VERSION 5.8 ;
BUSBITCHARS "[]" ;
DIVIDERCHAR "/" ;
UNITS
    DATABASE MICRONS 1000 ;
END UNITS

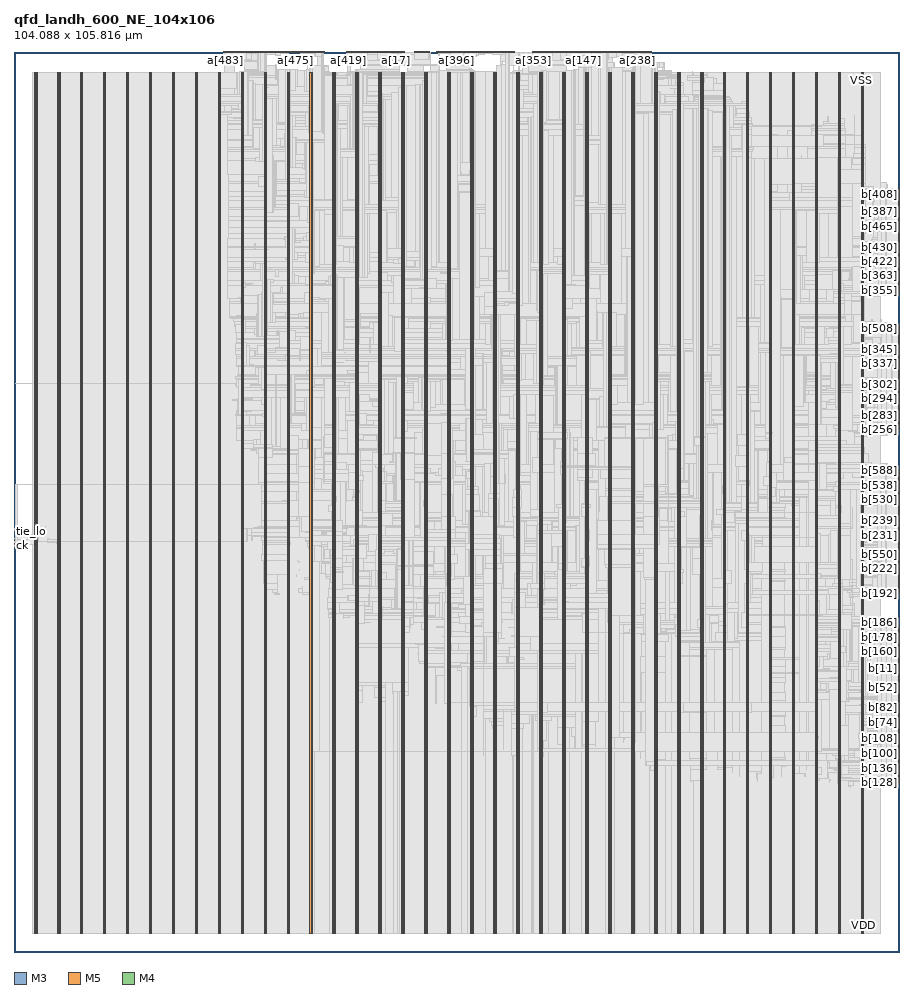
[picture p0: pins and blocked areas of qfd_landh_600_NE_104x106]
MACRO qfd_landh_600_NE_104x106
  FOREIGN qfd_landh_600_NE_104x106 0 0 ;
  CLASS BLOCK ;
  SIZE 104.088 BY 105.816 ;
  PIN a[0]
    DIRECTION INPUT ;
    USE SIGNAL ;
    PORT
      LAYER M3 ;
        RECT  43.668 105.779 43.686 105.816 ;
    END
  END a[0]
  PIN a[100]
    DIRECTION INPUT ;
    USE SIGNAL ;
    PORT
      LAYER M5 ;
        RECT  50.064 105.732 50.088 105.816 ;
    END
  END a[100]
  PIN a[101]
    DIRECTION INPUT ;
    USE SIGNAL ;
    PORT
      LAYER M5 ;
        RECT  50.16 105.732 50.184 105.816 ;
    END
  END a[101]
  PIN a[102]
    DIRECTION INPUT ;
    USE SIGNAL ;
    PORT
      LAYER M5 ;
        RECT  50.256 105.732 50.28 105.816 ;
    END
  END a[102]
  PIN a[103]
    DIRECTION INPUT ;
    USE SIGNAL ;
    PORT
      LAYER M5 ;
        RECT  50.352 105.732 50.376 105.816 ;
    END
  END a[103]
  PIN a[104]
    DIRECTION INPUT ;
    USE SIGNAL ;
    PORT
      LAYER M5 ;
        RECT  50.448 105.732 50.472 105.816 ;
    END
  END a[104]
  PIN a[105]
    DIRECTION INPUT ;
    USE SIGNAL ;
    PORT
      LAYER M5 ;
        RECT  50.544 105.732 50.568 105.816 ;
    END
  END a[105]
  PIN a[106]
    DIRECTION INPUT ;
    USE SIGNAL ;
    PORT
      LAYER M5 ;
        RECT  50.64 105.732 50.664 105.816 ;
    END
  END a[106]
  PIN a[107]
    DIRECTION INPUT ;
    USE SIGNAL ;
    PORT
      LAYER M5 ;
        RECT  50.736 105.732 50.76 105.816 ;
    END
  END a[107]
  PIN a[108]
    DIRECTION INPUT ;
    USE SIGNAL ;
    PORT
      LAYER M5 ;
        RECT  50.832 105.732 50.856 105.816 ;
    END
  END a[108]
  PIN a[109]
    DIRECTION INPUT ;
    USE SIGNAL ;
    PORT
      LAYER M5 ;
        RECT  50.928 105.732 50.952 105.816 ;
    END
  END a[109]
  PIN a[10]
    DIRECTION INPUT ;
    USE SIGNAL ;
    PORT
      LAYER M3 ;
        RECT  44.388 105.779 44.406 105.816 ;
    END
  END a[10]
  PIN a[110]
    DIRECTION INPUT ;
    USE SIGNAL ;
    PORT
      LAYER M5 ;
        RECT  51.024 105.732 51.048 105.816 ;
    END
  END a[110]
  PIN a[111]
    DIRECTION INPUT ;
    USE SIGNAL ;
    PORT
      LAYER M5 ;
        RECT  51.12 105.732 51.144 105.816 ;
    END
  END a[111]
  PIN a[112]
    DIRECTION INPUT ;
    USE SIGNAL ;
    PORT
      LAYER M5 ;
        RECT  51.216 105.732 51.24 105.816 ;
    END
  END a[112]
  PIN a[113]
    DIRECTION INPUT ;
    USE SIGNAL ;
    PORT
      LAYER M5 ;
        RECT  51.312 105.732 51.336 105.816 ;
    END
  END a[113]
  PIN a[114]
    DIRECTION INPUT ;
    USE SIGNAL ;
    PORT
      LAYER M5 ;
        RECT  51.408 105.732 51.432 105.816 ;
    END
  END a[114]
  PIN a[115]
    DIRECTION INPUT ;
    USE SIGNAL ;
    PORT
      LAYER M5 ;
        RECT  51.504 105.732 51.528 105.816 ;
    END
  END a[115]
  PIN a[116]
    DIRECTION INPUT ;
    USE SIGNAL ;
    PORT
      LAYER M5 ;
        RECT  51.6 105.732 51.624 105.816 ;
    END
  END a[116]
  PIN a[117]
    DIRECTION INPUT ;
    USE SIGNAL ;
    PORT
      LAYER M5 ;
        RECT  51.696 105.732 51.72 105.816 ;
    END
  END a[117]
  PIN a[118]
    DIRECTION INPUT ;
    USE SIGNAL ;
    PORT
      LAYER M5 ;
        RECT  51.792 105.732 51.816 105.816 ;
    END
  END a[118]
  PIN a[119]
    DIRECTION INPUT ;
    USE SIGNAL ;
    PORT
      LAYER M5 ;
        RECT  51.888 105.732 51.912 105.816 ;
    END
  END a[119]
  PIN a[11]
    DIRECTION INPUT ;
    USE SIGNAL ;
    PORT
      LAYER M3 ;
        RECT  44.46 105.779 44.478 105.816 ;
    END
  END a[11]
  PIN a[120]
    DIRECTION INPUT ;
    USE SIGNAL ;
    PORT
      LAYER M5 ;
        RECT  51.984 105.732 52.008 105.816 ;
    END
  END a[120]
  PIN a[121]
    DIRECTION INPUT ;
    USE SIGNAL ;
    PORT
      LAYER M5 ;
        RECT  52.08 105.732 52.104 105.816 ;
    END
  END a[121]
  PIN a[122]
    DIRECTION INPUT ;
    USE SIGNAL ;
    PORT
      LAYER M5 ;
        RECT  52.176 105.732 52.2 105.816 ;
    END
  END a[122]
  PIN a[123]
    DIRECTION INPUT ;
    USE SIGNAL ;
    PORT
      LAYER M5 ;
        RECT  52.272 105.732 52.296 105.816 ;
    END
  END a[123]
  PIN a[124]
    DIRECTION INPUT ;
    USE SIGNAL ;
    PORT
      LAYER M5 ;
        RECT  52.368 105.732 52.392 105.816 ;
    END
  END a[124]
  PIN a[125]
    DIRECTION INPUT ;
    USE SIGNAL ;
    PORT
      LAYER M5 ;
        RECT  52.464 105.732 52.488 105.816 ;
    END
  END a[125]
  PIN a[126]
    DIRECTION INPUT ;
    USE SIGNAL ;
    PORT
      LAYER M5 ;
        RECT  52.56 105.732 52.584 105.816 ;
    END
  END a[126]
  PIN a[127]
    DIRECTION INPUT ;
    USE SIGNAL ;
    PORT
      LAYER M5 ;
        RECT  52.656 105.732 52.68 105.816 ;
    END
  END a[127]
  PIN a[128]
    DIRECTION INPUT ;
    USE SIGNAL ;
    PORT
      LAYER M3 ;
        RECT  65.556 105.779 65.574 105.816 ;
    END
  END a[128]
  PIN a[129]
    DIRECTION INPUT ;
    USE SIGNAL ;
    PORT
      LAYER M3 ;
        RECT  65.628 105.779 65.646 105.816 ;
    END
  END a[129]
  PIN a[12]
    DIRECTION INPUT ;
    USE SIGNAL ;
    PORT
      LAYER M3 ;
        RECT  44.532 105.779 44.55 105.816 ;
    END
  END a[12]
  PIN a[130]
    DIRECTION INPUT ;
    USE SIGNAL ;
    PORT
      LAYER M3 ;
        RECT  65.7 105.779 65.718 105.816 ;
    END
  END a[130]
  PIN a[131]
    DIRECTION INPUT ;
    USE SIGNAL ;
    PORT
      LAYER M3 ;
        RECT  65.772 105.779 65.79 105.816 ;
    END
  END a[131]
  PIN a[132]
    DIRECTION INPUT ;
    USE SIGNAL ;
    PORT
      LAYER M3 ;
        RECT  65.844 105.779 65.862 105.816 ;
    END
  END a[132]
  PIN a[133]
    DIRECTION INPUT ;
    USE SIGNAL ;
    PORT
      LAYER M3 ;
        RECT  65.916 105.779 65.934 105.816 ;
    END
  END a[133]
  PIN a[134]
    DIRECTION INPUT ;
    USE SIGNAL ;
    PORT
      LAYER M3 ;
        RECT  65.988 105.779 66.006 105.816 ;
    END
  END a[134]
  PIN a[135]
    DIRECTION INPUT ;
    USE SIGNAL ;
    PORT
      LAYER M3 ;
        RECT  66.06 105.779 66.078 105.816 ;
    END
  END a[135]
  PIN a[136]
    DIRECTION INPUT ;
    USE SIGNAL ;
    PORT
      LAYER M3 ;
        RECT  66.132 105.779 66.15 105.816 ;
    END
  END a[136]
  PIN a[137]
    DIRECTION INPUT ;
    USE SIGNAL ;
    PORT
      LAYER M3 ;
        RECT  66.204 105.779 66.222 105.816 ;
    END
  END a[137]
  PIN a[138]
    DIRECTION INPUT ;
    USE SIGNAL ;
    PORT
      LAYER M3 ;
        RECT  66.276 105.779 66.294 105.816 ;
    END
  END a[138]
  PIN a[139]
    DIRECTION INPUT ;
    USE SIGNAL ;
    PORT
      LAYER M3 ;
        RECT  66.348 105.779 66.366 105.816 ;
    END
  END a[139]
  PIN a[13]
    DIRECTION INPUT ;
    USE SIGNAL ;
    PORT
      LAYER M3 ;
        RECT  44.604 105.779 44.622 105.816 ;
    END
  END a[13]
  PIN a[140]
    DIRECTION INPUT ;
    USE SIGNAL ;
    PORT
      LAYER M3 ;
        RECT  66.42 105.779 66.438 105.816 ;
    END
  END a[140]
  PIN a[141]
    DIRECTION INPUT ;
    USE SIGNAL ;
    PORT
      LAYER M3 ;
        RECT  66.492 105.779 66.51 105.816 ;
    END
  END a[141]
  PIN a[142]
    DIRECTION INPUT ;
    USE SIGNAL ;
    PORT
      LAYER M3 ;
        RECT  66.564 105.779 66.582 105.816 ;
    END
  END a[142]
  PIN a[143]
    DIRECTION INPUT ;
    USE SIGNAL ;
    PORT
      LAYER M3 ;
        RECT  66.636 105.779 66.654 105.816 ;
    END
  END a[143]
  PIN a[144]
    DIRECTION INPUT ;
    USE SIGNAL ;
    PORT
      LAYER M3 ;
        RECT  66.708 105.779 66.726 105.816 ;
    END
  END a[144]
  PIN a[145]
    DIRECTION INPUT ;
    USE SIGNAL ;
    PORT
      LAYER M3 ;
        RECT  66.78 105.779 66.798 105.816 ;
    END
  END a[145]
  PIN a[146]
    DIRECTION INPUT ;
    USE SIGNAL ;
    PORT
      LAYER M3 ;
        RECT  66.852 105.779 66.87 105.816 ;
    END
  END a[146]
  PIN a[147]
    DIRECTION INPUT ;
    USE SIGNAL ;
    PORT
      LAYER M3 ;
        RECT  66.924 105.779 66.942 105.816 ;
    END
  END a[147]
  PIN a[148]
    DIRECTION INPUT ;
    USE SIGNAL ;
    PORT
      LAYER M3 ;
        RECT  66.996 105.779 67.014 105.816 ;
    END
  END a[148]
  PIN a[149]
    DIRECTION INPUT ;
    USE SIGNAL ;
    PORT
      LAYER M3 ;
        RECT  67.068 105.779 67.086 105.816 ;
    END
  END a[149]
  PIN a[14]
    DIRECTION INPUT ;
    USE SIGNAL ;
    PORT
      LAYER M3 ;
        RECT  44.676 105.779 44.694 105.816 ;
    END
  END a[14]
  PIN a[150]
    DIRECTION INPUT ;
    USE SIGNAL ;
    PORT
      LAYER M3 ;
        RECT  67.14 105.779 67.158 105.816 ;
    END
  END a[150]
  PIN a[151]
    DIRECTION INPUT ;
    USE SIGNAL ;
    PORT
      LAYER M3 ;
        RECT  67.212 105.779 67.23 105.816 ;
    END
  END a[151]
  PIN a[152]
    DIRECTION INPUT ;
    USE SIGNAL ;
    PORT
      LAYER M3 ;
        RECT  67.284 105.779 67.302 105.816 ;
    END
  END a[152]
  PIN a[153]
    DIRECTION INPUT ;
    USE SIGNAL ;
    PORT
      LAYER M3 ;
        RECT  67.356 105.779 67.374 105.816 ;
    END
  END a[153]
  PIN a[154]
    DIRECTION INPUT ;
    USE SIGNAL ;
    PORT
      LAYER M3 ;
        RECT  67.428 105.779 67.446 105.816 ;
    END
  END a[154]
  PIN a[155]
    DIRECTION INPUT ;
    USE SIGNAL ;
    PORT
      LAYER M3 ;
        RECT  67.5 105.779 67.518 105.816 ;
    END
  END a[155]
  PIN a[156]
    DIRECTION INPUT ;
    USE SIGNAL ;
    PORT
      LAYER M3 ;
        RECT  67.572 105.779 67.59 105.816 ;
    END
  END a[156]
  PIN a[157]
    DIRECTION INPUT ;
    USE SIGNAL ;
    PORT
      LAYER M3 ;
        RECT  67.644 105.779 67.662 105.816 ;
    END
  END a[157]
  PIN a[158]
    DIRECTION INPUT ;
    USE SIGNAL ;
    PORT
      LAYER M3 ;
        RECT  67.716 105.779 67.734 105.816 ;
    END
  END a[158]
  PIN a[159]
    DIRECTION INPUT ;
    USE SIGNAL ;
    PORT
      LAYER M3 ;
        RECT  67.788 105.779 67.806 105.816 ;
    END
  END a[159]
  PIN a[15]
    DIRECTION INPUT ;
    USE SIGNAL ;
    PORT
      LAYER M3 ;
        RECT  44.748 105.779 44.766 105.816 ;
    END
  END a[15]
  PIN a[160]
    DIRECTION INPUT ;
    USE SIGNAL ;
    PORT
      LAYER M3 ;
        RECT  67.86 105.779 67.878 105.816 ;
    END
  END a[160]
  PIN a[161]
    DIRECTION INPUT ;
    USE SIGNAL ;
    PORT
      LAYER M3 ;
        RECT  67.932 105.779 67.95 105.816 ;
    END
  END a[161]
  PIN a[162]
    DIRECTION INPUT ;
    USE SIGNAL ;
    PORT
      LAYER M3 ;
        RECT  68.004 105.779 68.022 105.816 ;
    END
  END a[162]
  PIN a[163]
    DIRECTION INPUT ;
    USE SIGNAL ;
    PORT
      LAYER M3 ;
        RECT  68.076 105.779 68.094 105.816 ;
    END
  END a[163]
  PIN a[164]
    DIRECTION INPUT ;
    USE SIGNAL ;
    PORT
      LAYER M3 ;
        RECT  68.148 105.779 68.166 105.816 ;
    END
  END a[164]
  PIN a[165]
    DIRECTION INPUT ;
    USE SIGNAL ;
    PORT
      LAYER M3 ;
        RECT  68.22 105.779 68.238 105.816 ;
    END
  END a[165]
  PIN a[166]
    DIRECTION INPUT ;
    USE SIGNAL ;
    PORT
      LAYER M3 ;
        RECT  68.292 105.779 68.31 105.816 ;
    END
  END a[166]
  PIN a[167]
    DIRECTION INPUT ;
    USE SIGNAL ;
    PORT
      LAYER M3 ;
        RECT  68.364 105.779 68.382 105.816 ;
    END
  END a[167]
  PIN a[168]
    DIRECTION INPUT ;
    USE SIGNAL ;
    PORT
      LAYER M3 ;
        RECT  68.436 105.779 68.454 105.816 ;
    END
  END a[168]
  PIN a[169]
    DIRECTION INPUT ;
    USE SIGNAL ;
    PORT
      LAYER M3 ;
        RECT  68.508 105.779 68.526 105.816 ;
    END
  END a[169]
  PIN a[16]
    DIRECTION INPUT ;
    USE SIGNAL ;
    PORT
      LAYER M3 ;
        RECT  44.82 105.779 44.838 105.816 ;
    END
  END a[16]
  PIN a[170]
    DIRECTION INPUT ;
    USE SIGNAL ;
    PORT
      LAYER M3 ;
        RECT  68.58 105.779 68.598 105.816 ;
    END
  END a[170]
  PIN a[171]
    DIRECTION INPUT ;
    USE SIGNAL ;
    PORT
      LAYER M3 ;
        RECT  68.652 105.779 68.67 105.816 ;
    END
  END a[171]
  PIN a[172]
    DIRECTION INPUT ;
    USE SIGNAL ;
    PORT
      LAYER M3 ;
        RECT  68.724 105.779 68.742 105.816 ;
    END
  END a[172]
  PIN a[173]
    DIRECTION INPUT ;
    USE SIGNAL ;
    PORT
      LAYER M3 ;
        RECT  68.796 105.779 68.814 105.816 ;
    END
  END a[173]
  PIN a[174]
    DIRECTION INPUT ;
    USE SIGNAL ;
    PORT
      LAYER M3 ;
        RECT  68.868 105.779 68.886 105.816 ;
    END
  END a[174]
  PIN a[175]
    DIRECTION INPUT ;
    USE SIGNAL ;
    PORT
      LAYER M3 ;
        RECT  68.94 105.779 68.958 105.816 ;
    END
  END a[175]
  PIN a[176]
    DIRECTION INPUT ;
    USE SIGNAL ;
    PORT
      LAYER M3 ;
        RECT  69.012 105.779 69.03 105.816 ;
    END
  END a[176]
  PIN a[177]
    DIRECTION INPUT ;
    USE SIGNAL ;
    PORT
      LAYER M3 ;
        RECT  69.084 105.779 69.102 105.816 ;
    END
  END a[177]
  PIN a[178]
    DIRECTION INPUT ;
    USE SIGNAL ;
    PORT
      LAYER M3 ;
        RECT  69.156 105.779 69.174 105.816 ;
    END
  END a[178]
  PIN a[179]
    DIRECTION INPUT ;
    USE SIGNAL ;
    PORT
      LAYER M3 ;
        RECT  69.228 105.779 69.246 105.816 ;
    END
  END a[179]
  PIN a[17]
    DIRECTION INPUT ;
    USE SIGNAL ;
    PORT
      LAYER M3 ;
        RECT  44.892 105.779 44.91 105.816 ;
    END
  END a[17]
  PIN a[180]
    DIRECTION INPUT ;
    USE SIGNAL ;
    PORT
      LAYER M3 ;
        RECT  69.3 105.779 69.318 105.816 ;
    END
  END a[180]
  PIN a[181]
    DIRECTION INPUT ;
    USE SIGNAL ;
    PORT
      LAYER M3 ;
        RECT  69.372 105.779 69.39 105.816 ;
    END
  END a[181]
  PIN a[182]
    DIRECTION INPUT ;
    USE SIGNAL ;
    PORT
      LAYER M3 ;
        RECT  69.444 105.779 69.462 105.816 ;
    END
  END a[182]
  PIN a[183]
    DIRECTION INPUT ;
    USE SIGNAL ;
    PORT
      LAYER M3 ;
        RECT  69.516 105.779 69.534 105.816 ;
    END
  END a[183]
  PIN a[184]
    DIRECTION INPUT ;
    USE SIGNAL ;
    PORT
      LAYER M3 ;
        RECT  69.588 105.779 69.606 105.816 ;
    END
  END a[184]
  PIN a[185]
    DIRECTION INPUT ;
    USE SIGNAL ;
    PORT
      LAYER M3 ;
        RECT  69.66 105.779 69.678 105.816 ;
    END
  END a[185]
  PIN a[186]
    DIRECTION INPUT ;
    USE SIGNAL ;
    PORT
      LAYER M3 ;
        RECT  69.732 105.779 69.75 105.816 ;
    END
  END a[186]
  PIN a[187]
    DIRECTION INPUT ;
    USE SIGNAL ;
    PORT
      LAYER M3 ;
        RECT  69.804 105.779 69.822 105.816 ;
    END
  END a[187]
  PIN a[188]
    DIRECTION INPUT ;
    USE SIGNAL ;
    PORT
      LAYER M3 ;
        RECT  69.876 105.779 69.894 105.816 ;
    END
  END a[188]
  PIN a[189]
    DIRECTION INPUT ;
    USE SIGNAL ;
    PORT
      LAYER M3 ;
        RECT  69.948 105.779 69.966 105.816 ;
    END
  END a[189]
  PIN a[18]
    DIRECTION INPUT ;
    USE SIGNAL ;
    PORT
      LAYER M3 ;
        RECT  44.964 105.779 44.982 105.816 ;
    END
  END a[18]
  PIN a[190]
    DIRECTION INPUT ;
    USE SIGNAL ;
    PORT
      LAYER M3 ;
        RECT  70.02 105.779 70.038 105.816 ;
    END
  END a[190]
  PIN a[191]
    DIRECTION INPUT ;
    USE SIGNAL ;
    PORT
      LAYER M3 ;
        RECT  70.092 105.779 70.11 105.816 ;
    END
  END a[191]
  PIN a[192]
    DIRECTION INPUT ;
    USE SIGNAL ;
    PORT
      LAYER M5 ;
        RECT  55.824 105.732 55.848 105.816 ;
    END
  END a[192]
  PIN a[193]
    DIRECTION INPUT ;
    USE SIGNAL ;
    PORT
      LAYER M5 ;
        RECT  55.92 105.732 55.944 105.816 ;
    END
  END a[193]
  PIN a[194]
    DIRECTION INPUT ;
    USE SIGNAL ;
    PORT
      LAYER M5 ;
        RECT  56.016 105.732 56.04 105.816 ;
    END
  END a[194]
  PIN a[195]
    DIRECTION INPUT ;
    USE SIGNAL ;
    PORT
      LAYER M5 ;
        RECT  56.112 105.732 56.136 105.816 ;
    END
  END a[195]
  PIN a[196]
    DIRECTION INPUT ;
    USE SIGNAL ;
    PORT
      LAYER M5 ;
        RECT  56.208 105.732 56.232 105.816 ;
    END
  END a[196]
  PIN a[197]
    DIRECTION INPUT ;
    USE SIGNAL ;
    PORT
      LAYER M5 ;
        RECT  56.304 105.732 56.328 105.816 ;
    END
  END a[197]
  PIN a[198]
    DIRECTION INPUT ;
    USE SIGNAL ;
    PORT
      LAYER M5 ;
        RECT  56.4 105.732 56.424 105.816 ;
    END
  END a[198]
  PIN a[199]
    DIRECTION INPUT ;
    USE SIGNAL ;
    PORT
      LAYER M5 ;
        RECT  56.496 105.732 56.52 105.816 ;
    END
  END a[199]
  PIN a[19]
    DIRECTION INPUT ;
    USE SIGNAL ;
    PORT
      LAYER M3 ;
        RECT  45.036 105.779 45.054 105.816 ;
    END
  END a[19]
  PIN a[1]
    DIRECTION INPUT ;
    USE SIGNAL ;
    PORT
      LAYER M3 ;
        RECT  43.74 105.779 43.758 105.816 ;
    END
  END a[1]
  PIN a[200]
    DIRECTION INPUT ;
    USE SIGNAL ;
    PORT
      LAYER M5 ;
        RECT  56.592 105.732 56.616 105.816 ;
    END
  END a[200]
  PIN a[201]
    DIRECTION INPUT ;
    USE SIGNAL ;
    PORT
      LAYER M5 ;
        RECT  56.688 105.732 56.712 105.816 ;
    END
  END a[201]
  PIN a[202]
    DIRECTION INPUT ;
    USE SIGNAL ;
    PORT
      LAYER M5 ;
        RECT  56.784 105.732 56.808 105.816 ;
    END
  END a[202]
  PIN a[203]
    DIRECTION INPUT ;
    USE SIGNAL ;
    PORT
      LAYER M5 ;
        RECT  56.88 105.732 56.904 105.816 ;
    END
  END a[203]
  PIN a[204]
    DIRECTION INPUT ;
    USE SIGNAL ;
    PORT
      LAYER M5 ;
        RECT  56.976 105.732 57 105.816 ;
    END
  END a[204]
  PIN a[205]
    DIRECTION INPUT ;
    USE SIGNAL ;
    PORT
      LAYER M5 ;
        RECT  57.072 105.732 57.096 105.816 ;
    END
  END a[205]
  PIN a[206]
    DIRECTION INPUT ;
    USE SIGNAL ;
    PORT
      LAYER M5 ;
        RECT  57.168 105.732 57.192 105.816 ;
    END
  END a[206]
  PIN a[207]
    DIRECTION INPUT ;
    USE SIGNAL ;
    PORT
      LAYER M5 ;
        RECT  57.264 105.732 57.288 105.816 ;
    END
  END a[207]
  PIN a[208]
    DIRECTION INPUT ;
    USE SIGNAL ;
    PORT
      LAYER M5 ;
        RECT  57.36 105.732 57.384 105.816 ;
    END
  END a[208]
  PIN a[209]
    DIRECTION INPUT ;
    USE SIGNAL ;
    PORT
      LAYER M5 ;
        RECT  57.456 105.732 57.48 105.816 ;
    END
  END a[209]
  PIN a[20]
    DIRECTION INPUT ;
    USE SIGNAL ;
    PORT
      LAYER M3 ;
        RECT  45.108 105.779 45.126 105.816 ;
    END
  END a[20]
  PIN a[210]
    DIRECTION INPUT ;
    USE SIGNAL ;
    PORT
      LAYER M5 ;
        RECT  57.552 105.732 57.576 105.816 ;
    END
  END a[210]
  PIN a[211]
    DIRECTION INPUT ;
    USE SIGNAL ;
    PORT
      LAYER M5 ;
        RECT  57.648 105.732 57.672 105.816 ;
    END
  END a[211]
  PIN a[212]
    DIRECTION INPUT ;
    USE SIGNAL ;
    PORT
      LAYER M5 ;
        RECT  57.744 105.732 57.768 105.816 ;
    END
  END a[212]
  PIN a[213]
    DIRECTION INPUT ;
    USE SIGNAL ;
    PORT
      LAYER M5 ;
        RECT  57.84 105.732 57.864 105.816 ;
    END
  END a[213]
  PIN a[214]
    DIRECTION INPUT ;
    USE SIGNAL ;
    PORT
      LAYER M5 ;
        RECT  57.936 105.732 57.96 105.816 ;
    END
  END a[214]
  PIN a[215]
    DIRECTION INPUT ;
    USE SIGNAL ;
    PORT
      LAYER M5 ;
        RECT  58.032 105.732 58.056 105.816 ;
    END
  END a[215]
  PIN a[216]
    DIRECTION INPUT ;
    USE SIGNAL ;
    PORT
      LAYER M5 ;
        RECT  58.128 105.732 58.152 105.816 ;
    END
  END a[216]
  PIN a[217]
    DIRECTION INPUT ;
    USE SIGNAL ;
    PORT
      LAYER M5 ;
        RECT  58.224 105.732 58.248 105.816 ;
    END
  END a[217]
  PIN a[218]
    DIRECTION INPUT ;
    USE SIGNAL ;
    PORT
      LAYER M5 ;
        RECT  58.32 105.732 58.344 105.816 ;
    END
  END a[218]
  PIN a[219]
    DIRECTION INPUT ;
    USE SIGNAL ;
    PORT
      LAYER M5 ;
        RECT  58.416 105.732 58.44 105.816 ;
    END
  END a[219]
  PIN a[21]
    DIRECTION INPUT ;
    USE SIGNAL ;
    PORT
      LAYER M3 ;
        RECT  45.18 105.779 45.198 105.816 ;
    END
  END a[21]
  PIN a[220]
    DIRECTION INPUT ;
    USE SIGNAL ;
    PORT
      LAYER M5 ;
        RECT  58.512 105.732 58.536 105.816 ;
    END
  END a[220]
  PIN a[221]
    DIRECTION INPUT ;
    USE SIGNAL ;
    PORT
      LAYER M5 ;
        RECT  58.608 105.732 58.632 105.816 ;
    END
  END a[221]
  PIN a[222]
    DIRECTION INPUT ;
    USE SIGNAL ;
    PORT
      LAYER M5 ;
        RECT  58.704 105.732 58.728 105.816 ;
    END
  END a[222]
  PIN a[223]
    DIRECTION INPUT ;
    USE SIGNAL ;
    PORT
      LAYER M5 ;
        RECT  58.8 105.732 58.824 105.816 ;
    END
  END a[223]
  PIN a[224]
    DIRECTION INPUT ;
    USE SIGNAL ;
    PORT
      LAYER M5 ;
        RECT  71.952 105.732 71.976 105.816 ;
    END
  END a[224]
  PIN a[225]
    DIRECTION INPUT ;
    USE SIGNAL ;
    PORT
      LAYER M5 ;
        RECT  72.048 105.732 72.072 105.816 ;
    END
  END a[225]
  PIN a[226]
    DIRECTION INPUT ;
    USE SIGNAL ;
    PORT
      LAYER M5 ;
        RECT  72.144 105.732 72.168 105.816 ;
    END
  END a[226]
  PIN a[227]
    DIRECTION INPUT ;
    USE SIGNAL ;
    PORT
      LAYER M5 ;
        RECT  72.24 105.732 72.264 105.816 ;
    END
  END a[227]
  PIN a[228]
    DIRECTION INPUT ;
    USE SIGNAL ;
    PORT
      LAYER M5 ;
        RECT  72.336 105.732 72.36 105.816 ;
    END
  END a[228]
  PIN a[229]
    DIRECTION INPUT ;
    USE SIGNAL ;
    PORT
      LAYER M5 ;
        RECT  72.432 105.732 72.456 105.816 ;
    END
  END a[229]
  PIN a[22]
    DIRECTION INPUT ;
    USE SIGNAL ;
    PORT
      LAYER M3 ;
        RECT  45.252 105.779 45.27 105.816 ;
    END
  END a[22]
  PIN a[230]
    DIRECTION INPUT ;
    USE SIGNAL ;
    PORT
      LAYER M5 ;
        RECT  72.528 105.732 72.552 105.816 ;
    END
  END a[230]
  PIN a[231]
    DIRECTION INPUT ;
    USE SIGNAL ;
    PORT
      LAYER M5 ;
        RECT  72.624 105.732 72.648 105.816 ;
    END
  END a[231]
  PIN a[232]
    DIRECTION INPUT ;
    USE SIGNAL ;
    PORT
      LAYER M5 ;
        RECT  72.72 105.732 72.744 105.816 ;
    END
  END a[232]
  PIN a[233]
    DIRECTION INPUT ;
    USE SIGNAL ;
    PORT
      LAYER M5 ;
        RECT  72.816 105.732 72.84 105.816 ;
    END
  END a[233]
  PIN a[234]
    DIRECTION INPUT ;
    USE SIGNAL ;
    PORT
      LAYER M5 ;
        RECT  72.912 105.732 72.936 105.816 ;
    END
  END a[234]
  PIN a[235]
    DIRECTION INPUT ;
    USE SIGNAL ;
    PORT
      LAYER M5 ;
        RECT  73.008 105.732 73.032 105.816 ;
    END
  END a[235]
  PIN a[236]
    DIRECTION INPUT ;
    USE SIGNAL ;
    PORT
      LAYER M5 ;
        RECT  73.104 105.732 73.128 105.816 ;
    END
  END a[236]
  PIN a[237]
    DIRECTION INPUT ;
    USE SIGNAL ;
    PORT
      LAYER M5 ;
        RECT  73.2 105.732 73.224 105.816 ;
    END
  END a[237]
  PIN a[238]
    DIRECTION INPUT ;
    USE SIGNAL ;
    PORT
      LAYER M5 ;
        RECT  73.296 105.732 73.32 105.816 ;
    END
  END a[238]
  PIN a[239]
    DIRECTION INPUT ;
    USE SIGNAL ;
    PORT
      LAYER M5 ;
        RECT  73.392 105.732 73.416 105.816 ;
    END
  END a[239]
  PIN a[23]
    DIRECTION INPUT ;
    USE SIGNAL ;
    PORT
      LAYER M3 ;
        RECT  45.324 105.779 45.342 105.816 ;
    END
  END a[23]
  PIN a[240]
    DIRECTION INPUT ;
    USE SIGNAL ;
    PORT
      LAYER M5 ;
        RECT  73.488 105.732 73.512 105.816 ;
    END
  END a[240]
  PIN a[241]
    DIRECTION INPUT ;
    USE SIGNAL ;
    PORT
      LAYER M5 ;
        RECT  73.584 105.732 73.608 105.816 ;
    END
  END a[241]
  PIN a[242]
    DIRECTION INPUT ;
    USE SIGNAL ;
    PORT
      LAYER M5 ;
        RECT  73.68 105.732 73.704 105.816 ;
    END
  END a[242]
  PIN a[243]
    DIRECTION INPUT ;
    USE SIGNAL ;
    PORT
      LAYER M5 ;
        RECT  73.776 105.732 73.8 105.816 ;
    END
  END a[243]
  PIN a[244]
    DIRECTION INPUT ;
    USE SIGNAL ;
    PORT
      LAYER M5 ;
        RECT  73.872 105.732 73.896 105.816 ;
    END
  END a[244]
  PIN a[245]
    DIRECTION INPUT ;
    USE SIGNAL ;
    PORT
      LAYER M5 ;
        RECT  73.968 105.732 73.992 105.816 ;
    END
  END a[245]
  PIN a[246]
    DIRECTION INPUT ;
    USE SIGNAL ;
    PORT
      LAYER M5 ;
        RECT  74.064 105.732 74.088 105.816 ;
    END
  END a[246]
  PIN a[247]
    DIRECTION INPUT ;
    USE SIGNAL ;
    PORT
      LAYER M5 ;
        RECT  74.16 105.732 74.184 105.816 ;
    END
  END a[247]
  PIN a[248]
    DIRECTION INPUT ;
    USE SIGNAL ;
    PORT
      LAYER M5 ;
        RECT  74.256 105.732 74.28 105.816 ;
    END
  END a[248]
  PIN a[249]
    DIRECTION INPUT ;
    USE SIGNAL ;
    PORT
      LAYER M5 ;
        RECT  74.352 105.732 74.376 105.816 ;
    END
  END a[249]
  PIN a[24]
    DIRECTION INPUT ;
    USE SIGNAL ;
    PORT
      LAYER M3 ;
        RECT  45.396 105.779 45.414 105.816 ;
    END
  END a[24]
  PIN a[250]
    DIRECTION INPUT ;
    USE SIGNAL ;
    PORT
      LAYER M5 ;
        RECT  74.448 105.732 74.472 105.816 ;
    END
  END a[250]
  PIN a[251]
    DIRECTION INPUT ;
    USE SIGNAL ;
    PORT
      LAYER M5 ;
        RECT  74.544 105.732 74.568 105.816 ;
    END
  END a[251]
  PIN a[252]
    DIRECTION INPUT ;
    USE SIGNAL ;
    PORT
      LAYER M5 ;
        RECT  74.64 105.732 74.664 105.816 ;
    END
  END a[252]
  PIN a[253]
    DIRECTION INPUT ;
    USE SIGNAL ;
    PORT
      LAYER M5 ;
        RECT  74.736 105.732 74.76 105.816 ;
    END
  END a[253]
  PIN a[254]
    DIRECTION INPUT ;
    USE SIGNAL ;
    PORT
      LAYER M5 ;
        RECT  74.832 105.732 74.856 105.816 ;
    END
  END a[254]
  PIN a[255]
    DIRECTION INPUT ;
    USE SIGNAL ;
    PORT
      LAYER M5 ;
        RECT  74.928 105.732 74.952 105.816 ;
    END
  END a[255]
  PIN a[256]
    DIRECTION INPUT ;
    USE SIGNAL ;
    PORT
      LAYER M5 ;
        RECT  68.88 105.732 68.904 105.816 ;
    END
  END a[256]
  PIN a[257]
    DIRECTION INPUT ;
    USE SIGNAL ;
    PORT
      LAYER M5 ;
        RECT  68.976 105.732 69 105.816 ;
    END
  END a[257]
  PIN a[258]
    DIRECTION INPUT ;
    USE SIGNAL ;
    PORT
      LAYER M5 ;
        RECT  69.072 105.732 69.096 105.816 ;
    END
  END a[258]
  PIN a[259]
    DIRECTION INPUT ;
    USE SIGNAL ;
    PORT
      LAYER M5 ;
        RECT  69.168 105.732 69.192 105.816 ;
    END
  END a[259]
  PIN a[25]
    DIRECTION INPUT ;
    USE SIGNAL ;
    PORT
      LAYER M3 ;
        RECT  45.468 105.779 45.486 105.816 ;
    END
  END a[25]
  PIN a[260]
    DIRECTION INPUT ;
    USE SIGNAL ;
    PORT
      LAYER M5 ;
        RECT  69.264 105.732 69.288 105.816 ;
    END
  END a[260]
  PIN a[261]
    DIRECTION INPUT ;
    USE SIGNAL ;
    PORT
      LAYER M5 ;
        RECT  69.36 105.732 69.384 105.816 ;
    END
  END a[261]
  PIN a[262]
    DIRECTION INPUT ;
    USE SIGNAL ;
    PORT
      LAYER M5 ;
        RECT  69.456 105.732 69.48 105.816 ;
    END
  END a[262]
  PIN a[263]
    DIRECTION INPUT ;
    USE SIGNAL ;
    PORT
      LAYER M5 ;
        RECT  69.552 105.732 69.576 105.816 ;
    END
  END a[263]
  PIN a[264]
    DIRECTION INPUT ;
    USE SIGNAL ;
    PORT
      LAYER M5 ;
        RECT  69.648 105.732 69.672 105.816 ;
    END
  END a[264]
  PIN a[265]
    DIRECTION INPUT ;
    USE SIGNAL ;
    PORT
      LAYER M5 ;
        RECT  69.744 105.732 69.768 105.816 ;
    END
  END a[265]
  PIN a[266]
    DIRECTION INPUT ;
    USE SIGNAL ;
    PORT
      LAYER M5 ;
        RECT  69.84 105.732 69.864 105.816 ;
    END
  END a[266]
  PIN a[267]
    DIRECTION INPUT ;
    USE SIGNAL ;
    PORT
      LAYER M5 ;
        RECT  69.936 105.732 69.96 105.816 ;
    END
  END a[267]
  PIN a[268]
    DIRECTION INPUT ;
    USE SIGNAL ;
    PORT
      LAYER M5 ;
        RECT  70.032 105.732 70.056 105.816 ;
    END
  END a[268]
  PIN a[269]
    DIRECTION INPUT ;
    USE SIGNAL ;
    PORT
      LAYER M5 ;
        RECT  70.128 105.732 70.152 105.816 ;
    END
  END a[269]
  PIN a[26]
    DIRECTION INPUT ;
    USE SIGNAL ;
    PORT
      LAYER M3 ;
        RECT  45.54 105.779 45.558 105.816 ;
    END
  END a[26]
  PIN a[270]
    DIRECTION INPUT ;
    USE SIGNAL ;
    PORT
      LAYER M5 ;
        RECT  70.224 105.732 70.248 105.816 ;
    END
  END a[270]
  PIN a[271]
    DIRECTION INPUT ;
    USE SIGNAL ;
    PORT
      LAYER M5 ;
        RECT  70.32 105.732 70.344 105.816 ;
    END
  END a[271]
  PIN a[272]
    DIRECTION INPUT ;
    USE SIGNAL ;
    PORT
      LAYER M5 ;
        RECT  70.416 105.732 70.44 105.816 ;
    END
  END a[272]
  PIN a[273]
    DIRECTION INPUT ;
    USE SIGNAL ;
    PORT
      LAYER M5 ;
        RECT  70.512 105.732 70.536 105.816 ;
    END
  END a[273]
  PIN a[274]
    DIRECTION INPUT ;
    USE SIGNAL ;
    PORT
      LAYER M5 ;
        RECT  70.608 105.732 70.632 105.816 ;
    END
  END a[274]
  PIN a[275]
    DIRECTION INPUT ;
    USE SIGNAL ;
    PORT
      LAYER M5 ;
        RECT  70.704 105.732 70.728 105.816 ;
    END
  END a[275]
  PIN a[276]
    DIRECTION INPUT ;
    USE SIGNAL ;
    PORT
      LAYER M5 ;
        RECT  70.8 105.732 70.824 105.816 ;
    END
  END a[276]
  PIN a[277]
    DIRECTION INPUT ;
    USE SIGNAL ;
    PORT
      LAYER M5 ;
        RECT  70.896 105.732 70.92 105.816 ;
    END
  END a[277]
  PIN a[278]
    DIRECTION INPUT ;
    USE SIGNAL ;
    PORT
      LAYER M5 ;
        RECT  70.992 105.732 71.016 105.816 ;
    END
  END a[278]
  PIN a[279]
    DIRECTION INPUT ;
    USE SIGNAL ;
    PORT
      LAYER M5 ;
        RECT  71.088 105.732 71.112 105.816 ;
    END
  END a[279]
  PIN a[27]
    DIRECTION INPUT ;
    USE SIGNAL ;
    PORT
      LAYER M3 ;
        RECT  45.612 105.779 45.63 105.816 ;
    END
  END a[27]
  PIN a[280]
    DIRECTION INPUT ;
    USE SIGNAL ;
    PORT
      LAYER M5 ;
        RECT  71.184 105.732 71.208 105.816 ;
    END
  END a[280]
  PIN a[281]
    DIRECTION INPUT ;
    USE SIGNAL ;
    PORT
      LAYER M5 ;
        RECT  71.28 105.732 71.304 105.816 ;
    END
  END a[281]
  PIN a[282]
    DIRECTION INPUT ;
    USE SIGNAL ;
    PORT
      LAYER M5 ;
        RECT  71.376 105.732 71.4 105.816 ;
    END
  END a[282]
  PIN a[283]
    DIRECTION INPUT ;
    USE SIGNAL ;
    PORT
      LAYER M5 ;
        RECT  71.472 105.732 71.496 105.816 ;
    END
  END a[283]
  PIN a[284]
    DIRECTION INPUT ;
    USE SIGNAL ;
    PORT
      LAYER M5 ;
        RECT  71.568 105.732 71.592 105.816 ;
    END
  END a[284]
  PIN a[285]
    DIRECTION INPUT ;
    USE SIGNAL ;
    PORT
      LAYER M5 ;
        RECT  71.664 105.732 71.688 105.816 ;
    END
  END a[285]
  PIN a[286]
    DIRECTION INPUT ;
    USE SIGNAL ;
    PORT
      LAYER M5 ;
        RECT  71.76 105.732 71.784 105.816 ;
    END
  END a[286]
  PIN a[287]
    DIRECTION INPUT ;
    USE SIGNAL ;
    PORT
      LAYER M5 ;
        RECT  71.856 105.732 71.88 105.816 ;
    END
  END a[287]
  PIN a[288]
    DIRECTION INPUT ;
    USE SIGNAL ;
    PORT
      LAYER M3 ;
        RECT  63.252 105.779 63.27 105.816 ;
    END
  END a[288]
  PIN a[289]
    DIRECTION INPUT ;
    USE SIGNAL ;
    PORT
      LAYER M3 ;
        RECT  63.324 105.779 63.342 105.816 ;
    END
  END a[289]
  PIN a[28]
    DIRECTION INPUT ;
    USE SIGNAL ;
    PORT
      LAYER M3 ;
        RECT  45.684 105.779 45.702 105.816 ;
    END
  END a[28]
  PIN a[290]
    DIRECTION INPUT ;
    USE SIGNAL ;
    PORT
      LAYER M3 ;
        RECT  63.396 105.779 63.414 105.816 ;
    END
  END a[290]
  PIN a[291]
    DIRECTION INPUT ;
    USE SIGNAL ;
    PORT
      LAYER M3 ;
        RECT  63.468 105.779 63.486 105.816 ;
    END
  END a[291]
  PIN a[292]
    DIRECTION INPUT ;
    USE SIGNAL ;
    PORT
      LAYER M3 ;
        RECT  63.54 105.779 63.558 105.816 ;
    END
  END a[292]
  PIN a[293]
    DIRECTION INPUT ;
    USE SIGNAL ;
    PORT
      LAYER M3 ;
        RECT  63.612 105.779 63.63 105.816 ;
    END
  END a[293]
  PIN a[294]
    DIRECTION INPUT ;
    USE SIGNAL ;
    PORT
      LAYER M3 ;
        RECT  63.684 105.779 63.702 105.816 ;
    END
  END a[294]
  PIN a[295]
    DIRECTION INPUT ;
    USE SIGNAL ;
    PORT
      LAYER M3 ;
        RECT  63.756 105.779 63.774 105.816 ;
    END
  END a[295]
  PIN a[296]
    DIRECTION INPUT ;
    USE SIGNAL ;
    PORT
      LAYER M3 ;
        RECT  63.828 105.779 63.846 105.816 ;
    END
  END a[296]
  PIN a[297]
    DIRECTION INPUT ;
    USE SIGNAL ;
    PORT
      LAYER M3 ;
        RECT  63.9 105.779 63.918 105.816 ;
    END
  END a[297]
  PIN a[298]
    DIRECTION INPUT ;
    USE SIGNAL ;
    PORT
      LAYER M3 ;
        RECT  63.972 105.779 63.99 105.816 ;
    END
  END a[298]
  PIN a[299]
    DIRECTION INPUT ;
    USE SIGNAL ;
    PORT
      LAYER M3 ;
        RECT  64.044 105.779 64.062 105.816 ;
    END
  END a[299]
  PIN a[29]
    DIRECTION INPUT ;
    USE SIGNAL ;
    PORT
      LAYER M3 ;
        RECT  45.756 105.779 45.774 105.816 ;
    END
  END a[29]
  PIN a[2]
    DIRECTION INPUT ;
    USE SIGNAL ;
    PORT
      LAYER M3 ;
        RECT  43.812 105.779 43.83 105.816 ;
    END
  END a[2]
  PIN a[300]
    DIRECTION INPUT ;
    USE SIGNAL ;
    PORT
      LAYER M3 ;
        RECT  64.116 105.779 64.134 105.816 ;
    END
  END a[300]
  PIN a[301]
    DIRECTION INPUT ;
    USE SIGNAL ;
    PORT
      LAYER M3 ;
        RECT  64.188 105.779 64.206 105.816 ;
    END
  END a[301]
  PIN a[302]
    DIRECTION INPUT ;
    USE SIGNAL ;
    PORT
      LAYER M3 ;
        RECT  64.26 105.779 64.278 105.816 ;
    END
  END a[302]
  PIN a[303]
    DIRECTION INPUT ;
    USE SIGNAL ;
    PORT
      LAYER M3 ;
        RECT  64.332 105.779 64.35 105.816 ;
    END
  END a[303]
  PIN a[304]
    DIRECTION INPUT ;
    USE SIGNAL ;
    PORT
      LAYER M3 ;
        RECT  64.404 105.779 64.422 105.816 ;
    END
  END a[304]
  PIN a[305]
    DIRECTION INPUT ;
    USE SIGNAL ;
    PORT
      LAYER M3 ;
        RECT  64.476 105.779 64.494 105.816 ;
    END
  END a[305]
  PIN a[306]
    DIRECTION INPUT ;
    USE SIGNAL ;
    PORT
      LAYER M3 ;
        RECT  64.548 105.779 64.566 105.816 ;
    END
  END a[306]
  PIN a[307]
    DIRECTION INPUT ;
    USE SIGNAL ;
    PORT
      LAYER M3 ;
        RECT  64.62 105.779 64.638 105.816 ;
    END
  END a[307]
  PIN a[308]
    DIRECTION INPUT ;
    USE SIGNAL ;
    PORT
      LAYER M3 ;
        RECT  64.692 105.779 64.71 105.816 ;
    END
  END a[308]
  PIN a[309]
    DIRECTION INPUT ;
    USE SIGNAL ;
    PORT
      LAYER M3 ;
        RECT  64.764 105.779 64.782 105.816 ;
    END
  END a[309]
  PIN a[30]
    DIRECTION INPUT ;
    USE SIGNAL ;
    PORT
      LAYER M3 ;
        RECT  45.828 105.779 45.846 105.816 ;
    END
  END a[30]
  PIN a[310]
    DIRECTION INPUT ;
    USE SIGNAL ;
    PORT
      LAYER M3 ;
        RECT  64.836 105.779 64.854 105.816 ;
    END
  END a[310]
  PIN a[311]
    DIRECTION INPUT ;
    USE SIGNAL ;
    PORT
      LAYER M3 ;
        RECT  64.908 105.779 64.926 105.816 ;
    END
  END a[311]
  PIN a[312]
    DIRECTION INPUT ;
    USE SIGNAL ;
    PORT
      LAYER M3 ;
        RECT  64.98 105.779 64.998 105.816 ;
    END
  END a[312]
  PIN a[313]
    DIRECTION INPUT ;
    USE SIGNAL ;
    PORT
      LAYER M3 ;
        RECT  65.052 105.779 65.07 105.816 ;
    END
  END a[313]
  PIN a[314]
    DIRECTION INPUT ;
    USE SIGNAL ;
    PORT
      LAYER M3 ;
        RECT  65.124 105.779 65.142 105.816 ;
    END
  END a[314]
  PIN a[315]
    DIRECTION INPUT ;
    USE SIGNAL ;
    PORT
      LAYER M3 ;
        RECT  65.196 105.779 65.214 105.816 ;
    END
  END a[315]
  PIN a[316]
    DIRECTION INPUT ;
    USE SIGNAL ;
    PORT
      LAYER M3 ;
        RECT  65.268 105.779 65.286 105.816 ;
    END
  END a[316]
  PIN a[317]
    DIRECTION INPUT ;
    USE SIGNAL ;
    PORT
      LAYER M3 ;
        RECT  65.34 105.779 65.358 105.816 ;
    END
  END a[317]
  PIN a[318]
    DIRECTION INPUT ;
    USE SIGNAL ;
    PORT
      LAYER M3 ;
        RECT  65.412 105.779 65.43 105.816 ;
    END
  END a[318]
  PIN a[319]
    DIRECTION INPUT ;
    USE SIGNAL ;
    PORT
      LAYER M3 ;
        RECT  65.484 105.779 65.502 105.816 ;
    END
  END a[319]
  PIN a[31]
    DIRECTION INPUT ;
    USE SIGNAL ;
    PORT
      LAYER M3 ;
        RECT  45.9 105.779 45.918 105.816 ;
    END
  END a[31]
  PIN a[320]
    DIRECTION INPUT ;
    USE SIGNAL ;
    PORT
      LAYER M5 ;
        RECT  52.752 105.732 52.776 105.816 ;
    END
  END a[320]
  PIN a[321]
    DIRECTION INPUT ;
    USE SIGNAL ;
    PORT
      LAYER M5 ;
        RECT  52.848 105.732 52.872 105.816 ;
    END
  END a[321]
  PIN a[322]
    DIRECTION INPUT ;
    USE SIGNAL ;
    PORT
      LAYER M5 ;
        RECT  52.944 105.732 52.968 105.816 ;
    END
  END a[322]
  PIN a[323]
    DIRECTION INPUT ;
    USE SIGNAL ;
    PORT
      LAYER M5 ;
        RECT  53.04 105.732 53.064 105.816 ;
    END
  END a[323]
  PIN a[324]
    DIRECTION INPUT ;
    USE SIGNAL ;
    PORT
      LAYER M5 ;
        RECT  53.136 105.732 53.16 105.816 ;
    END
  END a[324]
  PIN a[325]
    DIRECTION INPUT ;
    USE SIGNAL ;
    PORT
      LAYER M5 ;
        RECT  53.232 105.732 53.256 105.816 ;
    END
  END a[325]
  PIN a[326]
    DIRECTION INPUT ;
    USE SIGNAL ;
    PORT
      LAYER M5 ;
        RECT  53.328 105.732 53.352 105.816 ;
    END
  END a[326]
  PIN a[327]
    DIRECTION INPUT ;
    USE SIGNAL ;
    PORT
      LAYER M5 ;
        RECT  53.424 105.732 53.448 105.816 ;
    END
  END a[327]
  PIN a[328]
    DIRECTION INPUT ;
    USE SIGNAL ;
    PORT
      LAYER M5 ;
        RECT  53.52 105.732 53.544 105.816 ;
    END
  END a[328]
  PIN a[329]
    DIRECTION INPUT ;
    USE SIGNAL ;
    PORT
      LAYER M5 ;
        RECT  53.616 105.732 53.64 105.816 ;
    END
  END a[329]
  PIN a[32]
    DIRECTION INPUT ;
    USE SIGNAL ;
    PORT
      LAYER M5 ;
        RECT  27.408 105.732 27.432 105.816 ;
    END
  END a[32]
  PIN a[330]
    DIRECTION INPUT ;
    USE SIGNAL ;
    PORT
      LAYER M5 ;
        RECT  53.712 105.732 53.736 105.816 ;
    END
  END a[330]
  PIN a[331]
    DIRECTION INPUT ;
    USE SIGNAL ;
    PORT
      LAYER M5 ;
        RECT  53.808 105.732 53.832 105.816 ;
    END
  END a[331]
  PIN a[332]
    DIRECTION INPUT ;
    USE SIGNAL ;
    PORT
      LAYER M5 ;
        RECT  53.904 105.732 53.928 105.816 ;
    END
  END a[332]
  PIN a[333]
    DIRECTION INPUT ;
    USE SIGNAL ;
    PORT
      LAYER M5 ;
        RECT  54 105.732 54.024 105.816 ;
    END
  END a[333]
  PIN a[334]
    DIRECTION INPUT ;
    USE SIGNAL ;
    PORT
      LAYER M5 ;
        RECT  54.096 105.732 54.12 105.816 ;
    END
  END a[334]
  PIN a[335]
    DIRECTION INPUT ;
    USE SIGNAL ;
    PORT
      LAYER M5 ;
        RECT  54.192 105.732 54.216 105.816 ;
    END
  END a[335]
  PIN a[336]
    DIRECTION INPUT ;
    USE SIGNAL ;
    PORT
      LAYER M5 ;
        RECT  54.288 105.732 54.312 105.816 ;
    END
  END a[336]
  PIN a[337]
    DIRECTION INPUT ;
    USE SIGNAL ;
    PORT
      LAYER M5 ;
        RECT  54.384 105.732 54.408 105.816 ;
    END
  END a[337]
  PIN a[338]
    DIRECTION INPUT ;
    USE SIGNAL ;
    PORT
      LAYER M5 ;
        RECT  54.48 105.732 54.504 105.816 ;
    END
  END a[338]
  PIN a[339]
    DIRECTION INPUT ;
    USE SIGNAL ;
    PORT
      LAYER M5 ;
        RECT  54.576 105.732 54.6 105.816 ;
    END
  END a[339]
  PIN a[33]
    DIRECTION INPUT ;
    USE SIGNAL ;
    PORT
      LAYER M5 ;
        RECT  27.504 105.732 27.528 105.816 ;
    END
  END a[33]
  PIN a[340]
    DIRECTION INPUT ;
    USE SIGNAL ;
    PORT
      LAYER M5 ;
        RECT  54.672 105.732 54.696 105.816 ;
    END
  END a[340]
  PIN a[341]
    DIRECTION INPUT ;
    USE SIGNAL ;
    PORT
      LAYER M5 ;
        RECT  54.768 105.732 54.792 105.816 ;
    END
  END a[341]
  PIN a[342]
    DIRECTION INPUT ;
    USE SIGNAL ;
    PORT
      LAYER M5 ;
        RECT  54.864 105.732 54.888 105.816 ;
    END
  END a[342]
  PIN a[343]
    DIRECTION INPUT ;
    USE SIGNAL ;
    PORT
      LAYER M5 ;
        RECT  54.96 105.732 54.984 105.816 ;
    END
  END a[343]
  PIN a[344]
    DIRECTION INPUT ;
    USE SIGNAL ;
    PORT
      LAYER M5 ;
        RECT  55.056 105.732 55.08 105.816 ;
    END
  END a[344]
  PIN a[345]
    DIRECTION INPUT ;
    USE SIGNAL ;
    PORT
      LAYER M5 ;
        RECT  55.152 105.732 55.176 105.816 ;
    END
  END a[345]
  PIN a[346]
    DIRECTION INPUT ;
    USE SIGNAL ;
    PORT
      LAYER M5 ;
        RECT  55.248 105.732 55.272 105.816 ;
    END
  END a[346]
  PIN a[347]
    DIRECTION INPUT ;
    USE SIGNAL ;
    PORT
      LAYER M5 ;
        RECT  55.344 105.732 55.368 105.816 ;
    END
  END a[347]
  PIN a[348]
    DIRECTION INPUT ;
    USE SIGNAL ;
    PORT
      LAYER M5 ;
        RECT  55.44 105.732 55.464 105.816 ;
    END
  END a[348]
  PIN a[349]
    DIRECTION INPUT ;
    USE SIGNAL ;
    PORT
      LAYER M5 ;
        RECT  55.536 105.732 55.56 105.816 ;
    END
  END a[349]
  PIN a[34]
    DIRECTION INPUT ;
    USE SIGNAL ;
    PORT
      LAYER M5 ;
        RECT  27.6 105.732 27.624 105.816 ;
    END
  END a[34]
  PIN a[350]
    DIRECTION INPUT ;
    USE SIGNAL ;
    PORT
      LAYER M5 ;
        RECT  55.632 105.732 55.656 105.816 ;
    END
  END a[350]
  PIN a[351]
    DIRECTION INPUT ;
    USE SIGNAL ;
    PORT
      LAYER M5 ;
        RECT  55.728 105.732 55.752 105.816 ;
    END
  END a[351]
  PIN a[352]
    DIRECTION INPUT ;
    USE SIGNAL ;
    PORT
      LAYER M3 ;
        RECT  60.948 105.779 60.966 105.816 ;
    END
  END a[352]
  PIN a[353]
    DIRECTION INPUT ;
    USE SIGNAL ;
    PORT
      LAYER M3 ;
        RECT  61.02 105.779 61.038 105.816 ;
    END
  END a[353]
  PIN a[354]
    DIRECTION INPUT ;
    USE SIGNAL ;
    PORT
      LAYER M3 ;
        RECT  61.092 105.779 61.11 105.816 ;
    END
  END a[354]
  PIN a[355]
    DIRECTION INPUT ;
    USE SIGNAL ;
    PORT
      LAYER M3 ;
        RECT  61.164 105.779 61.182 105.816 ;
    END
  END a[355]
  PIN a[356]
    DIRECTION INPUT ;
    USE SIGNAL ;
    PORT
      LAYER M3 ;
        RECT  61.236 105.779 61.254 105.816 ;
    END
  END a[356]
  PIN a[357]
    DIRECTION INPUT ;
    USE SIGNAL ;
    PORT
      LAYER M3 ;
        RECT  61.308 105.779 61.326 105.816 ;
    END
  END a[357]
  PIN a[358]
    DIRECTION INPUT ;
    USE SIGNAL ;
    PORT
      LAYER M3 ;
        RECT  61.38 105.779 61.398 105.816 ;
    END
  END a[358]
  PIN a[359]
    DIRECTION INPUT ;
    USE SIGNAL ;
    PORT
      LAYER M3 ;
        RECT  61.452 105.779 61.47 105.816 ;
    END
  END a[359]
  PIN a[35]
    DIRECTION INPUT ;
    USE SIGNAL ;
    PORT
      LAYER M5 ;
        RECT  27.696 105.732 27.72 105.816 ;
    END
  END a[35]
  PIN a[360]
    DIRECTION INPUT ;
    USE SIGNAL ;
    PORT
      LAYER M3 ;
        RECT  61.524 105.779 61.542 105.816 ;
    END
  END a[360]
  PIN a[361]
    DIRECTION INPUT ;
    USE SIGNAL ;
    PORT
      LAYER M3 ;
        RECT  61.596 105.779 61.614 105.816 ;
    END
  END a[361]
  PIN a[362]
    DIRECTION INPUT ;
    USE SIGNAL ;
    PORT
      LAYER M3 ;
        RECT  61.668 105.779 61.686 105.816 ;
    END
  END a[362]
  PIN a[363]
    DIRECTION INPUT ;
    USE SIGNAL ;
    PORT
      LAYER M3 ;
        RECT  61.74 105.779 61.758 105.816 ;
    END
  END a[363]
  PIN a[364]
    DIRECTION INPUT ;
    USE SIGNAL ;
    PORT
      LAYER M3 ;
        RECT  61.812 105.779 61.83 105.816 ;
    END
  END a[364]
  PIN a[365]
    DIRECTION INPUT ;
    USE SIGNAL ;
    PORT
      LAYER M3 ;
        RECT  61.884 105.779 61.902 105.816 ;
    END
  END a[365]
  PIN a[366]
    DIRECTION INPUT ;
    USE SIGNAL ;
    PORT
      LAYER M3 ;
        RECT  61.956 105.779 61.974 105.816 ;
    END
  END a[366]
  PIN a[367]
    DIRECTION INPUT ;
    USE SIGNAL ;
    PORT
      LAYER M3 ;
        RECT  62.028 105.779 62.046 105.816 ;
    END
  END a[367]
  PIN a[368]
    DIRECTION INPUT ;
    USE SIGNAL ;
    PORT
      LAYER M3 ;
        RECT  62.1 105.779 62.118 105.816 ;
    END
  END a[368]
  PIN a[369]
    DIRECTION INPUT ;
    USE SIGNAL ;
    PORT
      LAYER M3 ;
        RECT  62.172 105.779 62.19 105.816 ;
    END
  END a[369]
  PIN a[36]
    DIRECTION INPUT ;
    USE SIGNAL ;
    PORT
      LAYER M5 ;
        RECT  27.792 105.732 27.816 105.816 ;
    END
  END a[36]
  PIN a[370]
    DIRECTION INPUT ;
    USE SIGNAL ;
    PORT
      LAYER M3 ;
        RECT  62.244 105.779 62.262 105.816 ;
    END
  END a[370]
  PIN a[371]
    DIRECTION INPUT ;
    USE SIGNAL ;
    PORT
      LAYER M3 ;
        RECT  62.316 105.779 62.334 105.816 ;
    END
  END a[371]
  PIN a[372]
    DIRECTION INPUT ;
    USE SIGNAL ;
    PORT
      LAYER M3 ;
        RECT  62.388 105.779 62.406 105.816 ;
    END
  END a[372]
  PIN a[373]
    DIRECTION INPUT ;
    USE SIGNAL ;
    PORT
      LAYER M3 ;
        RECT  62.46 105.779 62.478 105.816 ;
    END
  END a[373]
  PIN a[374]
    DIRECTION INPUT ;
    USE SIGNAL ;
    PORT
      LAYER M3 ;
        RECT  62.532 105.779 62.55 105.816 ;
    END
  END a[374]
  PIN a[375]
    DIRECTION INPUT ;
    USE SIGNAL ;
    PORT
      LAYER M3 ;
        RECT  62.604 105.779 62.622 105.816 ;
    END
  END a[375]
  PIN a[376]
    DIRECTION INPUT ;
    USE SIGNAL ;
    PORT
      LAYER M3 ;
        RECT  62.676 105.779 62.694 105.816 ;
    END
  END a[376]
  PIN a[377]
    DIRECTION INPUT ;
    USE SIGNAL ;
    PORT
      LAYER M3 ;
        RECT  62.748 105.779 62.766 105.816 ;
    END
  END a[377]
  PIN a[378]
    DIRECTION INPUT ;
    USE SIGNAL ;
    PORT
      LAYER M3 ;
        RECT  62.82 105.779 62.838 105.816 ;
    END
  END a[378]
  PIN a[379]
    DIRECTION INPUT ;
    USE SIGNAL ;
    PORT
      LAYER M3 ;
        RECT  62.892 105.779 62.91 105.816 ;
    END
  END a[379]
  PIN a[37]
    DIRECTION INPUT ;
    USE SIGNAL ;
    PORT
      LAYER M5 ;
        RECT  27.888 105.732 27.912 105.816 ;
    END
  END a[37]
  PIN a[380]
    DIRECTION INPUT ;
    USE SIGNAL ;
    PORT
      LAYER M3 ;
        RECT  62.964 105.779 62.982 105.816 ;
    END
  END a[380]
  PIN a[381]
    DIRECTION INPUT ;
    USE SIGNAL ;
    PORT
      LAYER M3 ;
        RECT  63.036 105.779 63.054 105.816 ;
    END
  END a[381]
  PIN a[382]
    DIRECTION INPUT ;
    USE SIGNAL ;
    PORT
      LAYER M3 ;
        RECT  63.108 105.779 63.126 105.816 ;
    END
  END a[382]
  PIN a[383]
    DIRECTION INPUT ;
    USE SIGNAL ;
    PORT
      LAYER M3 ;
        RECT  63.18 105.779 63.198 105.816 ;
    END
  END a[383]
  PIN a[384]
    DIRECTION INPUT ;
    USE SIGNAL ;
    PORT
      LAYER M3 ;
        RECT  51.156 105.779 51.174 105.816 ;
    END
  END a[384]
  PIN a[385]
    DIRECTION INPUT ;
    USE SIGNAL ;
    PORT
      LAYER M3 ;
        RECT  51.228 105.779 51.246 105.816 ;
    END
  END a[385]
  PIN a[386]
    DIRECTION INPUT ;
    USE SIGNAL ;
    PORT
      LAYER M3 ;
        RECT  51.3 105.779 51.318 105.816 ;
    END
  END a[386]
  PIN a[387]
    DIRECTION INPUT ;
    USE SIGNAL ;
    PORT
      LAYER M3 ;
        RECT  51.372 105.779 51.39 105.816 ;
    END
  END a[387]
  PIN a[388]
    DIRECTION INPUT ;
    USE SIGNAL ;
    PORT
      LAYER M3 ;
        RECT  51.444 105.779 51.462 105.816 ;
    END
  END a[388]
  PIN a[389]
    DIRECTION INPUT ;
    USE SIGNAL ;
    PORT
      LAYER M3 ;
        RECT  51.516 105.779 51.534 105.816 ;
    END
  END a[389]
  PIN a[38]
    DIRECTION INPUT ;
    USE SIGNAL ;
    PORT
      LAYER M5 ;
        RECT  27.984 105.732 28.008 105.816 ;
    END
  END a[38]
  PIN a[390]
    DIRECTION INPUT ;
    USE SIGNAL ;
    PORT
      LAYER M3 ;
        RECT  51.588 105.779 51.606 105.816 ;
    END
  END a[390]
  PIN a[391]
    DIRECTION INPUT ;
    USE SIGNAL ;
    PORT
      LAYER M3 ;
        RECT  51.66 105.779 51.678 105.816 ;
    END
  END a[391]
  PIN a[392]
    DIRECTION INPUT ;
    USE SIGNAL ;
    PORT
      LAYER M3 ;
        RECT  51.732 105.779 51.75 105.816 ;
    END
  END a[392]
  PIN a[393]
    DIRECTION INPUT ;
    USE SIGNAL ;
    PORT
      LAYER M3 ;
        RECT  51.804 105.779 51.822 105.816 ;
    END
  END a[393]
  PIN a[394]
    DIRECTION INPUT ;
    USE SIGNAL ;
    PORT
      LAYER M3 ;
        RECT  51.876 105.779 51.894 105.816 ;
    END
  END a[394]
  PIN a[395]
    DIRECTION INPUT ;
    USE SIGNAL ;
    PORT
      LAYER M3 ;
        RECT  51.948 105.779 51.966 105.816 ;
    END
  END a[395]
  PIN a[396]
    DIRECTION INPUT ;
    USE SIGNAL ;
    PORT
      LAYER M3 ;
        RECT  52.02 105.779 52.038 105.816 ;
    END
  END a[396]
  PIN a[397]
    DIRECTION INPUT ;
    USE SIGNAL ;
    PORT
      LAYER M3 ;
        RECT  52.092 105.779 52.11 105.816 ;
    END
  END a[397]
  PIN a[398]
    DIRECTION INPUT ;
    USE SIGNAL ;
    PORT
      LAYER M3 ;
        RECT  52.164 105.779 52.182 105.816 ;
    END
  END a[398]
  PIN a[399]
    DIRECTION INPUT ;
    USE SIGNAL ;
    PORT
      LAYER M3 ;
        RECT  52.236 105.779 52.254 105.816 ;
    END
  END a[399]
  PIN a[39]
    DIRECTION INPUT ;
    USE SIGNAL ;
    PORT
      LAYER M5 ;
        RECT  28.08 105.732 28.104 105.816 ;
    END
  END a[39]
  PIN a[3]
    DIRECTION INPUT ;
    USE SIGNAL ;
    PORT
      LAYER M3 ;
        RECT  43.884 105.779 43.902 105.816 ;
    END
  END a[3]
  PIN a[400]
    DIRECTION INPUT ;
    USE SIGNAL ;
    PORT
      LAYER M3 ;
        RECT  52.308 105.779 52.326 105.816 ;
    END
  END a[400]
  PIN a[401]
    DIRECTION INPUT ;
    USE SIGNAL ;
    PORT
      LAYER M3 ;
        RECT  52.38 105.779 52.398 105.816 ;
    END
  END a[401]
  PIN a[402]
    DIRECTION INPUT ;
    USE SIGNAL ;
    PORT
      LAYER M3 ;
        RECT  52.452 105.779 52.47 105.816 ;
    END
  END a[402]
  PIN a[403]
    DIRECTION INPUT ;
    USE SIGNAL ;
    PORT
      LAYER M3 ;
        RECT  52.524 105.779 52.542 105.816 ;
    END
  END a[403]
  PIN a[404]
    DIRECTION INPUT ;
    USE SIGNAL ;
    PORT
      LAYER M3 ;
        RECT  52.596 105.779 52.614 105.816 ;
    END
  END a[404]
  PIN a[405]
    DIRECTION INPUT ;
    USE SIGNAL ;
    PORT
      LAYER M3 ;
        RECT  52.668 105.779 52.686 105.816 ;
    END
  END a[405]
  PIN a[406]
    DIRECTION INPUT ;
    USE SIGNAL ;
    PORT
      LAYER M3 ;
        RECT  52.74 105.779 52.758 105.816 ;
    END
  END a[406]
  PIN a[407]
    DIRECTION INPUT ;
    USE SIGNAL ;
    PORT
      LAYER M3 ;
        RECT  52.812 105.779 52.83 105.816 ;
    END
  END a[407]
  PIN a[408]
    DIRECTION INPUT ;
    USE SIGNAL ;
    PORT
      LAYER M3 ;
        RECT  52.884 105.779 52.902 105.816 ;
    END
  END a[408]
  PIN a[409]
    DIRECTION INPUT ;
    USE SIGNAL ;
    PORT
      LAYER M3 ;
        RECT  52.956 105.779 52.974 105.816 ;
    END
  END a[409]
  PIN a[40]
    DIRECTION INPUT ;
    USE SIGNAL ;
    PORT
      LAYER M5 ;
        RECT  28.176 105.732 28.2 105.816 ;
    END
  END a[40]
  PIN a[410]
    DIRECTION INPUT ;
    USE SIGNAL ;
    PORT
      LAYER M3 ;
        RECT  53.028 105.779 53.046 105.816 ;
    END
  END a[410]
  PIN a[411]
    DIRECTION INPUT ;
    USE SIGNAL ;
    PORT
      LAYER M3 ;
        RECT  53.1 105.779 53.118 105.816 ;
    END
  END a[411]
  PIN a[412]
    DIRECTION INPUT ;
    USE SIGNAL ;
    PORT
      LAYER M3 ;
        RECT  53.172 105.779 53.19 105.816 ;
    END
  END a[412]
  PIN a[413]
    DIRECTION INPUT ;
    USE SIGNAL ;
    PORT
      LAYER M3 ;
        RECT  53.244 105.779 53.262 105.816 ;
    END
  END a[413]
  PIN a[414]
    DIRECTION INPUT ;
    USE SIGNAL ;
    PORT
      LAYER M3 ;
        RECT  53.316 105.779 53.334 105.816 ;
    END
  END a[414]
  PIN a[415]
    DIRECTION INPUT ;
    USE SIGNAL ;
    PORT
      LAYER M3 ;
        RECT  53.388 105.779 53.406 105.816 ;
    END
  END a[415]
  PIN a[416]
    DIRECTION INPUT ;
    USE SIGNAL ;
    PORT
      LAYER M3 ;
        RECT  39.06 105.779 39.078 105.816 ;
    END
  END a[416]
  PIN a[417]
    DIRECTION INPUT ;
    USE SIGNAL ;
    PORT
      LAYER M3 ;
        RECT  39.132 105.779 39.15 105.816 ;
    END
  END a[417]
  PIN a[418]
    DIRECTION INPUT ;
    USE SIGNAL ;
    PORT
      LAYER M3 ;
        RECT  39.204 105.779 39.222 105.816 ;
    END
  END a[418]
  PIN a[419]
    DIRECTION INPUT ;
    USE SIGNAL ;
    PORT
      LAYER M3 ;
        RECT  39.276 105.779 39.294 105.816 ;
    END
  END a[419]
  PIN a[41]
    DIRECTION INPUT ;
    USE SIGNAL ;
    PORT
      LAYER M5 ;
        RECT  28.272 105.732 28.296 105.816 ;
    END
  END a[41]
  PIN a[420]
    DIRECTION INPUT ;
    USE SIGNAL ;
    PORT
      LAYER M3 ;
        RECT  39.348 105.779 39.366 105.816 ;
    END
  END a[420]
  PIN a[421]
    DIRECTION INPUT ;
    USE SIGNAL ;
    PORT
      LAYER M3 ;
        RECT  39.42 105.779 39.438 105.816 ;
    END
  END a[421]
  PIN a[422]
    DIRECTION INPUT ;
    USE SIGNAL ;
    PORT
      LAYER M3 ;
        RECT  39.492 105.779 39.51 105.816 ;
    END
  END a[422]
  PIN a[423]
    DIRECTION INPUT ;
    USE SIGNAL ;
    PORT
      LAYER M3 ;
        RECT  39.564 105.779 39.582 105.816 ;
    END
  END a[423]
  PIN a[424]
    DIRECTION INPUT ;
    USE SIGNAL ;
    PORT
      LAYER M3 ;
        RECT  39.636 105.779 39.654 105.816 ;
    END
  END a[424]
  PIN a[425]
    DIRECTION INPUT ;
    USE SIGNAL ;
    PORT
      LAYER M3 ;
        RECT  39.708 105.779 39.726 105.816 ;
    END
  END a[425]
  PIN a[426]
    DIRECTION INPUT ;
    USE SIGNAL ;
    PORT
      LAYER M3 ;
        RECT  39.78 105.779 39.798 105.816 ;
    END
  END a[426]
  PIN a[427]
    DIRECTION INPUT ;
    USE SIGNAL ;
    PORT
      LAYER M3 ;
        RECT  39.852 105.779 39.87 105.816 ;
    END
  END a[427]
  PIN a[428]
    DIRECTION INPUT ;
    USE SIGNAL ;
    PORT
      LAYER M3 ;
        RECT  39.924 105.779 39.942 105.816 ;
    END
  END a[428]
  PIN a[429]
    DIRECTION INPUT ;
    USE SIGNAL ;
    PORT
      LAYER M3 ;
        RECT  39.996 105.779 40.014 105.816 ;
    END
  END a[429]
  PIN a[42]
    DIRECTION INPUT ;
    USE SIGNAL ;
    PORT
      LAYER M5 ;
        RECT  28.368 105.732 28.392 105.816 ;
    END
  END a[42]
  PIN a[430]
    DIRECTION INPUT ;
    USE SIGNAL ;
    PORT
      LAYER M3 ;
        RECT  40.068 105.779 40.086 105.816 ;
    END
  END a[430]
  PIN a[431]
    DIRECTION INPUT ;
    USE SIGNAL ;
    PORT
      LAYER M3 ;
        RECT  40.14 105.779 40.158 105.816 ;
    END
  END a[431]
  PIN a[432]
    DIRECTION INPUT ;
    USE SIGNAL ;
    PORT
      LAYER M3 ;
        RECT  40.212 105.779 40.23 105.816 ;
    END
  END a[432]
  PIN a[433]
    DIRECTION INPUT ;
    USE SIGNAL ;
    PORT
      LAYER M3 ;
        RECT  40.284 105.779 40.302 105.816 ;
    END
  END a[433]
  PIN a[434]
    DIRECTION INPUT ;
    USE SIGNAL ;
    PORT
      LAYER M3 ;
        RECT  40.356 105.779 40.374 105.816 ;
    END
  END a[434]
  PIN a[435]
    DIRECTION INPUT ;
    USE SIGNAL ;
    PORT
      LAYER M3 ;
        RECT  40.428 105.779 40.446 105.816 ;
    END
  END a[435]
  PIN a[436]
    DIRECTION INPUT ;
    USE SIGNAL ;
    PORT
      LAYER M3 ;
        RECT  40.5 105.779 40.518 105.816 ;
    END
  END a[436]
  PIN a[437]
    DIRECTION INPUT ;
    USE SIGNAL ;
    PORT
      LAYER M3 ;
        RECT  40.572 105.779 40.59 105.816 ;
    END
  END a[437]
  PIN a[438]
    DIRECTION INPUT ;
    USE SIGNAL ;
    PORT
      LAYER M3 ;
        RECT  40.644 105.779 40.662 105.816 ;
    END
  END a[438]
  PIN a[439]
    DIRECTION INPUT ;
    USE SIGNAL ;
    PORT
      LAYER M3 ;
        RECT  40.716 105.779 40.734 105.816 ;
    END
  END a[439]
  PIN a[43]
    DIRECTION INPUT ;
    USE SIGNAL ;
    PORT
      LAYER M5 ;
        RECT  28.464 105.732 28.488 105.816 ;
    END
  END a[43]
  PIN a[440]
    DIRECTION INPUT ;
    USE SIGNAL ;
    PORT
      LAYER M3 ;
        RECT  40.788 105.779 40.806 105.816 ;
    END
  END a[440]
  PIN a[441]
    DIRECTION INPUT ;
    USE SIGNAL ;
    PORT
      LAYER M3 ;
        RECT  40.86 105.779 40.878 105.816 ;
    END
  END a[441]
  PIN a[442]
    DIRECTION INPUT ;
    USE SIGNAL ;
    PORT
      LAYER M3 ;
        RECT  40.932 105.779 40.95 105.816 ;
    END
  END a[442]
  PIN a[443]
    DIRECTION INPUT ;
    USE SIGNAL ;
    PORT
      LAYER M3 ;
        RECT  41.004 105.779 41.022 105.816 ;
    END
  END a[443]
  PIN a[444]
    DIRECTION INPUT ;
    USE SIGNAL ;
    PORT
      LAYER M3 ;
        RECT  41.076 105.779 41.094 105.816 ;
    END
  END a[444]
  PIN a[445]
    DIRECTION INPUT ;
    USE SIGNAL ;
    PORT
      LAYER M3 ;
        RECT  41.148 105.779 41.166 105.816 ;
    END
  END a[445]
  PIN a[446]
    DIRECTION INPUT ;
    USE SIGNAL ;
    PORT
      LAYER M3 ;
        RECT  41.22 105.779 41.238 105.816 ;
    END
  END a[446]
  PIN a[447]
    DIRECTION INPUT ;
    USE SIGNAL ;
    PORT
      LAYER M3 ;
        RECT  41.292 105.779 41.31 105.816 ;
    END
  END a[447]
  PIN a[448]
    DIRECTION INPUT ;
    USE SIGNAL ;
    PORT
      LAYER M5 ;
        RECT  30.48 105.732 30.504 105.816 ;
    END
  END a[448]
  PIN a[449]
    DIRECTION INPUT ;
    USE SIGNAL ;
    PORT
      LAYER M5 ;
        RECT  30.576 105.732 30.6 105.816 ;
    END
  END a[449]
  PIN a[44]
    DIRECTION INPUT ;
    USE SIGNAL ;
    PORT
      LAYER M5 ;
        RECT  28.56 105.732 28.584 105.816 ;
    END
  END a[44]
  PIN a[450]
    DIRECTION INPUT ;
    USE SIGNAL ;
    PORT
      LAYER M5 ;
        RECT  30.672 105.732 30.696 105.816 ;
    END
  END a[450]
  PIN a[451]
    DIRECTION INPUT ;
    USE SIGNAL ;
    PORT
      LAYER M5 ;
        RECT  30.768 105.732 30.792 105.816 ;
    END
  END a[451]
  PIN a[452]
    DIRECTION INPUT ;
    USE SIGNAL ;
    PORT
      LAYER M5 ;
        RECT  30.864 105.732 30.888 105.816 ;
    END
  END a[452]
  PIN a[453]
    DIRECTION INPUT ;
    USE SIGNAL ;
    PORT
      LAYER M5 ;
        RECT  30.96 105.732 30.984 105.816 ;
    END
  END a[453]
  PIN a[454]
    DIRECTION INPUT ;
    USE SIGNAL ;
    PORT
      LAYER M5 ;
        RECT  31.056 105.732 31.08 105.816 ;
    END
  END a[454]
  PIN a[455]
    DIRECTION INPUT ;
    USE SIGNAL ;
    PORT
      LAYER M5 ;
        RECT  31.152 105.732 31.176 105.816 ;
    END
  END a[455]
  PIN a[456]
    DIRECTION INPUT ;
    USE SIGNAL ;
    PORT
      LAYER M5 ;
        RECT  31.248 105.732 31.272 105.816 ;
    END
  END a[456]
  PIN a[457]
    DIRECTION INPUT ;
    USE SIGNAL ;
    PORT
      LAYER M5 ;
        RECT  31.344 105.732 31.368 105.816 ;
    END
  END a[457]
  PIN a[458]
    DIRECTION INPUT ;
    USE SIGNAL ;
    PORT
      LAYER M5 ;
        RECT  31.44 105.732 31.464 105.816 ;
    END
  END a[458]
  PIN a[459]
    DIRECTION INPUT ;
    USE SIGNAL ;
    PORT
      LAYER M5 ;
        RECT  31.536 105.732 31.56 105.816 ;
    END
  END a[459]
  PIN a[45]
    DIRECTION INPUT ;
    USE SIGNAL ;
    PORT
      LAYER M5 ;
        RECT  28.656 105.732 28.68 105.816 ;
    END
  END a[45]
  PIN a[460]
    DIRECTION INPUT ;
    USE SIGNAL ;
    PORT
      LAYER M5 ;
        RECT  31.632 105.732 31.656 105.816 ;
    END
  END a[460]
  PIN a[461]
    DIRECTION INPUT ;
    USE SIGNAL ;
    PORT
      LAYER M5 ;
        RECT  31.728 105.732 31.752 105.816 ;
    END
  END a[461]
  PIN a[462]
    DIRECTION INPUT ;
    USE SIGNAL ;
    PORT
      LAYER M5 ;
        RECT  31.824 105.732 31.848 105.816 ;
    END
  END a[462]
  PIN a[463]
    DIRECTION INPUT ;
    USE SIGNAL ;
    PORT
      LAYER M5 ;
        RECT  31.92 105.732 31.944 105.816 ;
    END
  END a[463]
  PIN a[464]
    DIRECTION INPUT ;
    USE SIGNAL ;
    PORT
      LAYER M5 ;
        RECT  32.016 105.732 32.04 105.816 ;
    END
  END a[464]
  PIN a[465]
    DIRECTION INPUT ;
    USE SIGNAL ;
    PORT
      LAYER M5 ;
        RECT  32.112 105.732 32.136 105.816 ;
    END
  END a[465]
  PIN a[466]
    DIRECTION INPUT ;
    USE SIGNAL ;
    PORT
      LAYER M5 ;
        RECT  32.208 105.732 32.232 105.816 ;
    END
  END a[466]
  PIN a[467]
    DIRECTION INPUT ;
    USE SIGNAL ;
    PORT
      LAYER M5 ;
        RECT  32.304 105.732 32.328 105.816 ;
    END
  END a[467]
  PIN a[468]
    DIRECTION INPUT ;
    USE SIGNAL ;
    PORT
      LAYER M5 ;
        RECT  32.4 105.732 32.424 105.816 ;
    END
  END a[468]
  PIN a[469]
    DIRECTION INPUT ;
    USE SIGNAL ;
    PORT
      LAYER M5 ;
        RECT  32.496 105.732 32.52 105.816 ;
    END
  END a[469]
  PIN a[46]
    DIRECTION INPUT ;
    USE SIGNAL ;
    PORT
      LAYER M5 ;
        RECT  28.752 105.732 28.776 105.816 ;
    END
  END a[46]
  PIN a[470]
    DIRECTION INPUT ;
    USE SIGNAL ;
    PORT
      LAYER M5 ;
        RECT  32.592 105.732 32.616 105.816 ;
    END
  END a[470]
  PIN a[471]
    DIRECTION INPUT ;
    USE SIGNAL ;
    PORT
      LAYER M5 ;
        RECT  32.688 105.732 32.712 105.816 ;
    END
  END a[471]
  PIN a[472]
    DIRECTION INPUT ;
    USE SIGNAL ;
    PORT
      LAYER M5 ;
        RECT  32.784 105.732 32.808 105.816 ;
    END
  END a[472]
  PIN a[473]
    DIRECTION INPUT ;
    USE SIGNAL ;
    PORT
      LAYER M5 ;
        RECT  32.88 105.732 32.904 105.816 ;
    END
  END a[473]
  PIN a[474]
    DIRECTION INPUT ;
    USE SIGNAL ;
    PORT
      LAYER M5 ;
        RECT  32.976 105.732 33 105.816 ;
    END
  END a[474]
  PIN a[475]
    DIRECTION INPUT ;
    USE SIGNAL ;
    PORT
      LAYER M5 ;
        RECT  33.072 105.732 33.096 105.816 ;
    END
  END a[475]
  PIN a[476]
    DIRECTION INPUT ;
    USE SIGNAL ;
    PORT
      LAYER M5 ;
        RECT  33.168 105.732 33.192 105.816 ;
    END
  END a[476]
  PIN a[477]
    DIRECTION INPUT ;
    USE SIGNAL ;
    PORT
      LAYER M5 ;
        RECT  33.264 105.732 33.288 105.816 ;
    END
  END a[477]
  PIN a[478]
    DIRECTION INPUT ;
    USE SIGNAL ;
    PORT
      LAYER M5 ;
        RECT  33.36 105.732 33.384 105.816 ;
    END
  END a[478]
  PIN a[479]
    DIRECTION INPUT ;
    USE SIGNAL ;
    PORT
      LAYER M5 ;
        RECT  33.456 105.732 33.48 105.816 ;
    END
  END a[479]
  PIN a[47]
    DIRECTION INPUT ;
    USE SIGNAL ;
    PORT
      LAYER M5 ;
        RECT  28.848 105.732 28.872 105.816 ;
    END
  END a[47]
  PIN a[480]
    DIRECTION INPUT ;
    USE SIGNAL ;
    PORT
      LAYER M3 ;
        RECT  24.66 105.779 24.678 105.816 ;
    END
  END a[480]
  PIN a[481]
    DIRECTION INPUT ;
    USE SIGNAL ;
    PORT
      LAYER M3 ;
        RECT  24.732 105.779 24.75 105.816 ;
    END
  END a[481]
  PIN a[482]
    DIRECTION INPUT ;
    USE SIGNAL ;
    PORT
      LAYER M3 ;
        RECT  24.804 105.779 24.822 105.816 ;
    END
  END a[482]
  PIN a[483]
    DIRECTION INPUT ;
    USE SIGNAL ;
    PORT
      LAYER M3 ;
        RECT  24.876 105.779 24.894 105.816 ;
    END
  END a[483]
  PIN a[484]
    DIRECTION INPUT ;
    USE SIGNAL ;
    PORT
      LAYER M3 ;
        RECT  24.948 105.779 24.966 105.816 ;
    END
  END a[484]
  PIN a[485]
    DIRECTION INPUT ;
    USE SIGNAL ;
    PORT
      LAYER M3 ;
        RECT  25.02 105.779 25.038 105.816 ;
    END
  END a[485]
  PIN a[486]
    DIRECTION INPUT ;
    USE SIGNAL ;
    PORT
      LAYER M3 ;
        RECT  25.092 105.779 25.11 105.816 ;
    END
  END a[486]
  PIN a[487]
    DIRECTION INPUT ;
    USE SIGNAL ;
    PORT
      LAYER M3 ;
        RECT  25.164 105.779 25.182 105.816 ;
    END
  END a[487]
  PIN a[488]
    DIRECTION INPUT ;
    USE SIGNAL ;
    PORT
      LAYER M3 ;
        RECT  25.236 105.779 25.254 105.816 ;
    END
  END a[488]
  PIN a[489]
    DIRECTION INPUT ;
    USE SIGNAL ;
    PORT
      LAYER M3 ;
        RECT  25.308 105.779 25.326 105.816 ;
    END
  END a[489]
  PIN a[48]
    DIRECTION INPUT ;
    USE SIGNAL ;
    PORT
      LAYER M5 ;
        RECT  28.944 105.732 28.968 105.816 ;
    END
  END a[48]
  PIN a[490]
    DIRECTION INPUT ;
    USE SIGNAL ;
    PORT
      LAYER M3 ;
        RECT  25.38 105.779 25.398 105.816 ;
    END
  END a[490]
  PIN a[491]
    DIRECTION INPUT ;
    USE SIGNAL ;
    PORT
      LAYER M3 ;
        RECT  25.452 105.779 25.47 105.816 ;
    END
  END a[491]
  PIN a[492]
    DIRECTION INPUT ;
    USE SIGNAL ;
    PORT
      LAYER M3 ;
        RECT  25.524 105.779 25.542 105.816 ;
    END
  END a[492]
  PIN a[493]
    DIRECTION INPUT ;
    USE SIGNAL ;
    PORT
      LAYER M3 ;
        RECT  25.596 105.779 25.614 105.816 ;
    END
  END a[493]
  PIN a[494]
    DIRECTION INPUT ;
    USE SIGNAL ;
    PORT
      LAYER M3 ;
        RECT  25.668 105.779 25.686 105.816 ;
    END
  END a[494]
  PIN a[495]
    DIRECTION INPUT ;
    USE SIGNAL ;
    PORT
      LAYER M3 ;
        RECT  25.74 105.779 25.758 105.816 ;
    END
  END a[495]
  PIN a[496]
    DIRECTION INPUT ;
    USE SIGNAL ;
    PORT
      LAYER M3 ;
        RECT  25.812 105.779 25.83 105.816 ;
    END
  END a[496]
  PIN a[497]
    DIRECTION INPUT ;
    USE SIGNAL ;
    PORT
      LAYER M3 ;
        RECT  25.884 105.779 25.902 105.816 ;
    END
  END a[497]
  PIN a[498]
    DIRECTION INPUT ;
    USE SIGNAL ;
    PORT
      LAYER M3 ;
        RECT  25.956 105.779 25.974 105.816 ;
    END
  END a[498]
  PIN a[499]
    DIRECTION INPUT ;
    USE SIGNAL ;
    PORT
      LAYER M3 ;
        RECT  26.028 105.779 26.046 105.816 ;
    END
  END a[499]
  PIN a[49]
    DIRECTION INPUT ;
    USE SIGNAL ;
    PORT
      LAYER M5 ;
        RECT  29.04 105.732 29.064 105.816 ;
    END
  END a[49]
  PIN a[4]
    DIRECTION INPUT ;
    USE SIGNAL ;
    PORT
      LAYER M3 ;
        RECT  43.956 105.779 43.974 105.816 ;
    END
  END a[4]
  PIN a[500]
    DIRECTION INPUT ;
    USE SIGNAL ;
    PORT
      LAYER M3 ;
        RECT  26.1 105.779 26.118 105.816 ;
    END
  END a[500]
  PIN a[501]
    DIRECTION INPUT ;
    USE SIGNAL ;
    PORT
      LAYER M3 ;
        RECT  26.172 105.779 26.19 105.816 ;
    END
  END a[501]
  PIN a[502]
    DIRECTION INPUT ;
    USE SIGNAL ;
    PORT
      LAYER M3 ;
        RECT  26.244 105.779 26.262 105.816 ;
    END
  END a[502]
  PIN a[503]
    DIRECTION INPUT ;
    USE SIGNAL ;
    PORT
      LAYER M3 ;
        RECT  26.316 105.779 26.334 105.816 ;
    END
  END a[503]
  PIN a[504]
    DIRECTION INPUT ;
    USE SIGNAL ;
    PORT
      LAYER M3 ;
        RECT  26.388 105.779 26.406 105.816 ;
    END
  END a[504]
  PIN a[505]
    DIRECTION INPUT ;
    USE SIGNAL ;
    PORT
      LAYER M3 ;
        RECT  26.46 105.779 26.478 105.816 ;
    END
  END a[505]
  PIN a[506]
    DIRECTION INPUT ;
    USE SIGNAL ;
    PORT
      LAYER M3 ;
        RECT  26.532 105.779 26.55 105.816 ;
    END
  END a[506]
  PIN a[507]
    DIRECTION INPUT ;
    USE SIGNAL ;
    PORT
      LAYER M3 ;
        RECT  26.604 105.779 26.622 105.816 ;
    END
  END a[507]
  PIN a[508]
    DIRECTION INPUT ;
    USE SIGNAL ;
    PORT
      LAYER M3 ;
        RECT  26.676 105.779 26.694 105.816 ;
    END
  END a[508]
  PIN a[509]
    DIRECTION INPUT ;
    USE SIGNAL ;
    PORT
      LAYER M3 ;
        RECT  26.748 105.779 26.766 105.816 ;
    END
  END a[509]
  PIN a[50]
    DIRECTION INPUT ;
    USE SIGNAL ;
    PORT
      LAYER M5 ;
        RECT  29.136 105.732 29.16 105.816 ;
    END
  END a[50]
  PIN a[510]
    DIRECTION INPUT ;
    USE SIGNAL ;
    PORT
      LAYER M3 ;
        RECT  26.82 105.779 26.838 105.816 ;
    END
  END a[510]
  PIN a[511]
    DIRECTION INPUT ;
    USE SIGNAL ;
    PORT
      LAYER M3 ;
        RECT  26.892 105.779 26.91 105.816 ;
    END
  END a[511]
  PIN a[512]
    DIRECTION INPUT ;
    USE SIGNAL ;
    PORT
      LAYER M3 ;
        RECT  26.964 105.779 26.982 105.816 ;
    END
  END a[512]
  PIN a[513]
    DIRECTION INPUT ;
    USE SIGNAL ;
    PORT
      LAYER M3 ;
        RECT  27.036 105.779 27.054 105.816 ;
    END
  END a[513]
  PIN a[514]
    DIRECTION INPUT ;
    USE SIGNAL ;
    PORT
      LAYER M3 ;
        RECT  27.108 105.779 27.126 105.816 ;
    END
  END a[514]
  PIN a[515]
    DIRECTION INPUT ;
    USE SIGNAL ;
    PORT
      LAYER M3 ;
        RECT  27.18 105.779 27.198 105.816 ;
    END
  END a[515]
  PIN a[516]
    DIRECTION INPUT ;
    USE SIGNAL ;
    PORT
      LAYER M3 ;
        RECT  27.252 105.779 27.27 105.816 ;
    END
  END a[516]
  PIN a[517]
    DIRECTION INPUT ;
    USE SIGNAL ;
    PORT
      LAYER M3 ;
        RECT  27.324 105.779 27.342 105.816 ;
    END
  END a[517]
  PIN a[518]
    DIRECTION INPUT ;
    USE SIGNAL ;
    PORT
      LAYER M3 ;
        RECT  27.396 105.779 27.414 105.816 ;
    END
  END a[518]
  PIN a[519]
    DIRECTION INPUT ;
    USE SIGNAL ;
    PORT
      LAYER M3 ;
        RECT  27.468 105.779 27.486 105.816 ;
    END
  END a[519]
  PIN a[51]
    DIRECTION INPUT ;
    USE SIGNAL ;
    PORT
      LAYER M5 ;
        RECT  29.232 105.732 29.256 105.816 ;
    END
  END a[51]
  PIN a[520]
    DIRECTION INPUT ;
    USE SIGNAL ;
    PORT
      LAYER M3 ;
        RECT  27.54 105.779 27.558 105.816 ;
    END
  END a[520]
  PIN a[521]
    DIRECTION INPUT ;
    USE SIGNAL ;
    PORT
      LAYER M3 ;
        RECT  27.612 105.779 27.63 105.816 ;
    END
  END a[521]
  PIN a[522]
    DIRECTION INPUT ;
    USE SIGNAL ;
    PORT
      LAYER M3 ;
        RECT  27.684 105.779 27.702 105.816 ;
    END
  END a[522]
  PIN a[523]
    DIRECTION INPUT ;
    USE SIGNAL ;
    PORT
      LAYER M3 ;
        RECT  27.756 105.779 27.774 105.816 ;
    END
  END a[523]
  PIN a[524]
    DIRECTION INPUT ;
    USE SIGNAL ;
    PORT
      LAYER M3 ;
        RECT  27.828 105.779 27.846 105.816 ;
    END
  END a[524]
  PIN a[525]
    DIRECTION INPUT ;
    USE SIGNAL ;
    PORT
      LAYER M3 ;
        RECT  27.9 105.779 27.918 105.816 ;
    END
  END a[525]
  PIN a[526]
    DIRECTION INPUT ;
    USE SIGNAL ;
    PORT
      LAYER M3 ;
        RECT  27.972 105.779 27.99 105.816 ;
    END
  END a[526]
  PIN a[527]
    DIRECTION INPUT ;
    USE SIGNAL ;
    PORT
      LAYER M3 ;
        RECT  28.044 105.779 28.062 105.816 ;
    END
  END a[527]
  PIN a[528]
    DIRECTION INPUT ;
    USE SIGNAL ;
    PORT
      LAYER M3 ;
        RECT  28.116 105.779 28.134 105.816 ;
    END
  END a[528]
  PIN a[529]
    DIRECTION INPUT ;
    USE SIGNAL ;
    PORT
      LAYER M3 ;
        RECT  28.188 105.779 28.206 105.816 ;
    END
  END a[529]
  PIN a[52]
    DIRECTION INPUT ;
    USE SIGNAL ;
    PORT
      LAYER M5 ;
        RECT  29.328 105.732 29.352 105.816 ;
    END
  END a[52]
  PIN a[530]
    DIRECTION INPUT ;
    USE SIGNAL ;
    PORT
      LAYER M3 ;
        RECT  28.26 105.779 28.278 105.816 ;
    END
  END a[530]
  PIN a[531]
    DIRECTION INPUT ;
    USE SIGNAL ;
    PORT
      LAYER M3 ;
        RECT  28.332 105.779 28.35 105.816 ;
    END
  END a[531]
  PIN a[532]
    DIRECTION INPUT ;
    USE SIGNAL ;
    PORT
      LAYER M3 ;
        RECT  28.404 105.779 28.422 105.816 ;
    END
  END a[532]
  PIN a[533]
    DIRECTION INPUT ;
    USE SIGNAL ;
    PORT
      LAYER M3 ;
        RECT  28.476 105.779 28.494 105.816 ;
    END
  END a[533]
  PIN a[534]
    DIRECTION INPUT ;
    USE SIGNAL ;
    PORT
      LAYER M3 ;
        RECT  28.548 105.779 28.566 105.816 ;
    END
  END a[534]
  PIN a[535]
    DIRECTION INPUT ;
    USE SIGNAL ;
    PORT
      LAYER M3 ;
        RECT  28.62 105.779 28.638 105.816 ;
    END
  END a[535]
  PIN a[536]
    DIRECTION INPUT ;
    USE SIGNAL ;
    PORT
      LAYER M3 ;
        RECT  28.692 105.779 28.71 105.816 ;
    END
  END a[536]
  PIN a[537]
    DIRECTION INPUT ;
    USE SIGNAL ;
    PORT
      LAYER M3 ;
        RECT  28.764 105.779 28.782 105.816 ;
    END
  END a[537]
  PIN a[538]
    DIRECTION INPUT ;
    USE SIGNAL ;
    PORT
      LAYER M3 ;
        RECT  28.836 105.779 28.854 105.816 ;
    END
  END a[538]
  PIN a[539]
    DIRECTION INPUT ;
    USE SIGNAL ;
    PORT
      LAYER M3 ;
        RECT  28.908 105.779 28.926 105.816 ;
    END
  END a[539]
  PIN a[53]
    DIRECTION INPUT ;
    USE SIGNAL ;
    PORT
      LAYER M5 ;
        RECT  29.424 105.732 29.448 105.816 ;
    END
  END a[53]
  PIN a[540]
    DIRECTION INPUT ;
    USE SIGNAL ;
    PORT
      LAYER M3 ;
        RECT  28.98 105.779 28.998 105.816 ;
    END
  END a[540]
  PIN a[541]
    DIRECTION INPUT ;
    USE SIGNAL ;
    PORT
      LAYER M3 ;
        RECT  29.052 105.779 29.07 105.816 ;
    END
  END a[541]
  PIN a[542]
    DIRECTION INPUT ;
    USE SIGNAL ;
    PORT
      LAYER M3 ;
        RECT  29.124 105.779 29.142 105.816 ;
    END
  END a[542]
  PIN a[543]
    DIRECTION INPUT ;
    USE SIGNAL ;
    PORT
      LAYER M3 ;
        RECT  29.196 105.779 29.214 105.816 ;
    END
  END a[543]
  PIN a[544]
    DIRECTION INPUT ;
    USE SIGNAL ;
    PORT
      LAYER M5 ;
        RECT  33.552 105.732 33.576 105.816 ;
    END
  END a[544]
  PIN a[545]
    DIRECTION INPUT ;
    USE SIGNAL ;
    PORT
      LAYER M5 ;
        RECT  33.648 105.732 33.672 105.816 ;
    END
  END a[545]
  PIN a[546]
    DIRECTION INPUT ;
    USE SIGNAL ;
    PORT
      LAYER M5 ;
        RECT  33.744 105.732 33.768 105.816 ;
    END
  END a[546]
  PIN a[547]
    DIRECTION INPUT ;
    USE SIGNAL ;
    PORT
      LAYER M5 ;
        RECT  33.84 105.732 33.864 105.816 ;
    END
  END a[547]
  PIN a[548]
    DIRECTION INPUT ;
    USE SIGNAL ;
    PORT
      LAYER M5 ;
        RECT  33.936 105.732 33.96 105.816 ;
    END
  END a[548]
  PIN a[549]
    DIRECTION INPUT ;
    USE SIGNAL ;
    PORT
      LAYER M5 ;
        RECT  34.032 105.732 34.056 105.816 ;
    END
  END a[549]
  PIN a[54]
    DIRECTION INPUT ;
    USE SIGNAL ;
    PORT
      LAYER M5 ;
        RECT  29.52 105.732 29.544 105.816 ;
    END
  END a[54]
  PIN a[550]
    DIRECTION INPUT ;
    USE SIGNAL ;
    PORT
      LAYER M5 ;
        RECT  34.128 105.732 34.152 105.816 ;
    END
  END a[550]
  PIN a[551]
    DIRECTION INPUT ;
    USE SIGNAL ;
    PORT
      LAYER M5 ;
        RECT  34.224 105.732 34.248 105.816 ;
    END
  END a[551]
  PIN a[552]
    DIRECTION INPUT ;
    USE SIGNAL ;
    PORT
      LAYER M5 ;
        RECT  34.32 105.732 34.344 105.816 ;
    END
  END a[552]
  PIN a[553]
    DIRECTION INPUT ;
    USE SIGNAL ;
    PORT
      LAYER M5 ;
        RECT  34.416 105.732 34.44 105.816 ;
    END
  END a[553]
  PIN a[554]
    DIRECTION INPUT ;
    USE SIGNAL ;
    PORT
      LAYER M5 ;
        RECT  34.512 105.732 34.536 105.816 ;
    END
  END a[554]
  PIN a[555]
    DIRECTION INPUT ;
    USE SIGNAL ;
    PORT
      LAYER M5 ;
        RECT  34.608 105.732 34.632 105.816 ;
    END
  END a[555]
  PIN a[556]
    DIRECTION INPUT ;
    USE SIGNAL ;
    PORT
      LAYER M5 ;
        RECT  34.704 105.732 34.728 105.816 ;
    END
  END a[556]
  PIN a[557]
    DIRECTION INPUT ;
    USE SIGNAL ;
    PORT
      LAYER M5 ;
        RECT  34.8 105.732 34.824 105.816 ;
    END
  END a[557]
  PIN a[558]
    DIRECTION INPUT ;
    USE SIGNAL ;
    PORT
      LAYER M5 ;
        RECT  34.896 105.732 34.92 105.816 ;
    END
  END a[558]
  PIN a[559]
    DIRECTION INPUT ;
    USE SIGNAL ;
    PORT
      LAYER M5 ;
        RECT  34.992 105.732 35.016 105.816 ;
    END
  END a[559]
  PIN a[55]
    DIRECTION INPUT ;
    USE SIGNAL ;
    PORT
      LAYER M5 ;
        RECT  29.616 105.732 29.64 105.816 ;
    END
  END a[55]
  PIN a[560]
    DIRECTION INPUT ;
    USE SIGNAL ;
    PORT
      LAYER M5 ;
        RECT  35.088 105.732 35.112 105.816 ;
    END
  END a[560]
  PIN a[561]
    DIRECTION INPUT ;
    USE SIGNAL ;
    PORT
      LAYER M5 ;
        RECT  35.184 105.732 35.208 105.816 ;
    END
  END a[561]
  PIN a[562]
    DIRECTION INPUT ;
    USE SIGNAL ;
    PORT
      LAYER M5 ;
        RECT  35.28 105.732 35.304 105.816 ;
    END
  END a[562]
  PIN a[563]
    DIRECTION INPUT ;
    USE SIGNAL ;
    PORT
      LAYER M5 ;
        RECT  35.376 105.732 35.4 105.816 ;
    END
  END a[563]
  PIN a[564]
    DIRECTION INPUT ;
    USE SIGNAL ;
    PORT
      LAYER M5 ;
        RECT  35.472 105.732 35.496 105.816 ;
    END
  END a[564]
  PIN a[565]
    DIRECTION INPUT ;
    USE SIGNAL ;
    PORT
      LAYER M5 ;
        RECT  35.568 105.732 35.592 105.816 ;
    END
  END a[565]
  PIN a[566]
    DIRECTION INPUT ;
    USE SIGNAL ;
    PORT
      LAYER M5 ;
        RECT  35.664 105.732 35.688 105.816 ;
    END
  END a[566]
  PIN a[567]
    DIRECTION INPUT ;
    USE SIGNAL ;
    PORT
      LAYER M5 ;
        RECT  35.76 105.732 35.784 105.816 ;
    END
  END a[567]
  PIN a[568]
    DIRECTION INPUT ;
    USE SIGNAL ;
    PORT
      LAYER M5 ;
        RECT  35.856 105.732 35.88 105.816 ;
    END
  END a[568]
  PIN a[569]
    DIRECTION INPUT ;
    USE SIGNAL ;
    PORT
      LAYER M5 ;
        RECT  35.952 105.732 35.976 105.816 ;
    END
  END a[569]
  PIN a[56]
    DIRECTION INPUT ;
    USE SIGNAL ;
    PORT
      LAYER M5 ;
        RECT  29.712 105.732 29.736 105.816 ;
    END
  END a[56]
  PIN a[570]
    DIRECTION INPUT ;
    USE SIGNAL ;
    PORT
      LAYER M5 ;
        RECT  36.048 105.732 36.072 105.816 ;
    END
  END a[570]
  PIN a[571]
    DIRECTION INPUT ;
    USE SIGNAL ;
    PORT
      LAYER M5 ;
        RECT  36.144 105.732 36.168 105.816 ;
    END
  END a[571]
  PIN a[572]
    DIRECTION INPUT ;
    USE SIGNAL ;
    PORT
      LAYER M5 ;
        RECT  36.24 105.732 36.264 105.816 ;
    END
  END a[572]
  PIN a[573]
    DIRECTION INPUT ;
    USE SIGNAL ;
    PORT
      LAYER M5 ;
        RECT  36.336 105.732 36.36 105.816 ;
    END
  END a[573]
  PIN a[574]
    DIRECTION INPUT ;
    USE SIGNAL ;
    PORT
      LAYER M5 ;
        RECT  36.432 105.732 36.456 105.816 ;
    END
  END a[574]
  PIN a[575]
    DIRECTION INPUT ;
    USE SIGNAL ;
    PORT
      LAYER M5 ;
        RECT  36.528 105.732 36.552 105.816 ;
    END
  END a[575]
  PIN a[576]
    DIRECTION INPUT ;
    USE SIGNAL ;
    PORT
      LAYER M3 ;
        RECT  47.052 105.779 47.07 105.816 ;
    END
  END a[576]
  PIN a[577]
    DIRECTION INPUT ;
    USE SIGNAL ;
    PORT
      LAYER M3 ;
        RECT  47.124 105.779 47.142 105.816 ;
    END
  END a[577]
  PIN a[578]
    DIRECTION INPUT ;
    USE SIGNAL ;
    PORT
      LAYER M3 ;
        RECT  47.196 105.779 47.214 105.816 ;
    END
  END a[578]
  PIN a[579]
    DIRECTION INPUT ;
    USE SIGNAL ;
    PORT
      LAYER M3 ;
        RECT  47.268 105.779 47.286 105.816 ;
    END
  END a[579]
  PIN a[57]
    DIRECTION INPUT ;
    USE SIGNAL ;
    PORT
      LAYER M5 ;
        RECT  29.808 105.732 29.832 105.816 ;
    END
  END a[57]
  PIN a[580]
    DIRECTION INPUT ;
    USE SIGNAL ;
    PORT
      LAYER M3 ;
        RECT  47.34 105.779 47.358 105.816 ;
    END
  END a[580]
  PIN a[581]
    DIRECTION INPUT ;
    USE SIGNAL ;
    PORT
      LAYER M3 ;
        RECT  47.412 105.779 47.43 105.816 ;
    END
  END a[581]
  PIN a[582]
    DIRECTION INPUT ;
    USE SIGNAL ;
    PORT
      LAYER M3 ;
        RECT  47.484 105.779 47.502 105.816 ;
    END
  END a[582]
  PIN a[583]
    DIRECTION INPUT ;
    USE SIGNAL ;
    PORT
      LAYER M3 ;
        RECT  47.556 105.779 47.574 105.816 ;
    END
  END a[583]
  PIN a[584]
    DIRECTION INPUT ;
    USE SIGNAL ;
    PORT
      LAYER M3 ;
        RECT  47.628 105.779 47.646 105.816 ;
    END
  END a[584]
  PIN a[585]
    DIRECTION INPUT ;
    USE SIGNAL ;
    PORT
      LAYER M3 ;
        RECT  47.7 105.779 47.718 105.816 ;
    END
  END a[585]
  PIN a[586]
    DIRECTION INPUT ;
    USE SIGNAL ;
    PORT
      LAYER M3 ;
        RECT  47.772 105.779 47.79 105.816 ;
    END
  END a[586]
  PIN a[587]
    DIRECTION INPUT ;
    USE SIGNAL ;
    PORT
      LAYER M3 ;
        RECT  47.844 105.779 47.862 105.816 ;
    END
  END a[587]
  PIN a[588]
    DIRECTION INPUT ;
    USE SIGNAL ;
    PORT
      LAYER M3 ;
        RECT  47.916 105.779 47.934 105.816 ;
    END
  END a[588]
  PIN a[589]
    DIRECTION INPUT ;
    USE SIGNAL ;
    PORT
      LAYER M3 ;
        RECT  47.988 105.779 48.006 105.816 ;
    END
  END a[589]
  PIN a[58]
    DIRECTION INPUT ;
    USE SIGNAL ;
    PORT
      LAYER M5 ;
        RECT  29.904 105.732 29.928 105.816 ;
    END
  END a[58]
  PIN a[590]
    DIRECTION INPUT ;
    USE SIGNAL ;
    PORT
      LAYER M3 ;
        RECT  48.06 105.779 48.078 105.816 ;
    END
  END a[590]
  PIN a[591]
    DIRECTION INPUT ;
    USE SIGNAL ;
    PORT
      LAYER M3 ;
        RECT  48.132 105.779 48.15 105.816 ;
    END
  END a[591]
  PIN a[592]
    DIRECTION INPUT ;
    USE SIGNAL ;
    PORT
      LAYER M3 ;
        RECT  48.204 105.779 48.222 105.816 ;
    END
  END a[592]
  PIN a[593]
    DIRECTION INPUT ;
    USE SIGNAL ;
    PORT
      LAYER M3 ;
        RECT  48.276 105.779 48.294 105.816 ;
    END
  END a[593]
  PIN a[594]
    DIRECTION INPUT ;
    USE SIGNAL ;
    PORT
      LAYER M3 ;
        RECT  48.348 105.779 48.366 105.816 ;
    END
  END a[594]
  PIN a[595]
    DIRECTION INPUT ;
    USE SIGNAL ;
    PORT
      LAYER M3 ;
        RECT  48.42 105.779 48.438 105.816 ;
    END
  END a[595]
  PIN a[596]
    DIRECTION INPUT ;
    USE SIGNAL ;
    PORT
      LAYER M3 ;
        RECT  48.492 105.779 48.51 105.816 ;
    END
  END a[596]
  PIN a[597]
    DIRECTION INPUT ;
    USE SIGNAL ;
    PORT
      LAYER M3 ;
        RECT  48.564 105.779 48.582 105.816 ;
    END
  END a[597]
  PIN a[598]
    DIRECTION INPUT ;
    USE SIGNAL ;
    PORT
      LAYER M3 ;
        RECT  48.636 105.779 48.654 105.816 ;
    END
  END a[598]
  PIN a[599]
    DIRECTION INPUT ;
    USE SIGNAL ;
    PORT
      LAYER M3 ;
        RECT  48.708 105.779 48.726 105.816 ;
    END
  END a[599]
  PIN a[59]
    DIRECTION INPUT ;
    USE SIGNAL ;
    PORT
      LAYER M5 ;
        RECT  30 105.732 30.024 105.816 ;
    END
  END a[59]
  PIN a[5]
    DIRECTION INPUT ;
    USE SIGNAL ;
    PORT
      LAYER M3 ;
        RECT  44.028 105.779 44.046 105.816 ;
    END
  END a[5]
  PIN a[60]
    DIRECTION INPUT ;
    USE SIGNAL ;
    PORT
      LAYER M5 ;
        RECT  30.096 105.732 30.12 105.816 ;
    END
  END a[60]
  PIN a[61]
    DIRECTION INPUT ;
    USE SIGNAL ;
    PORT
      LAYER M5 ;
        RECT  30.192 105.732 30.216 105.816 ;
    END
  END a[61]
  PIN a[62]
    DIRECTION INPUT ;
    USE SIGNAL ;
    PORT
      LAYER M5 ;
        RECT  30.288 105.732 30.312 105.816 ;
    END
  END a[62]
  PIN a[63]
    DIRECTION INPUT ;
    USE SIGNAL ;
    PORT
      LAYER M5 ;
        RECT  30.384 105.732 30.408 105.816 ;
    END
  END a[63]
  PIN a[64]
    DIRECTION INPUT ;
    USE SIGNAL ;
    PORT
      LAYER M3 ;
        RECT  41.364 105.779 41.382 105.816 ;
    END
  END a[64]
  PIN a[65]
    DIRECTION INPUT ;
    USE SIGNAL ;
    PORT
      LAYER M3 ;
        RECT  41.436 105.779 41.454 105.816 ;
    END
  END a[65]
  PIN a[66]
    DIRECTION INPUT ;
    USE SIGNAL ;
    PORT
      LAYER M3 ;
        RECT  41.508 105.779 41.526 105.816 ;
    END
  END a[66]
  PIN a[67]
    DIRECTION INPUT ;
    USE SIGNAL ;
    PORT
      LAYER M3 ;
        RECT  41.58 105.779 41.598 105.816 ;
    END
  END a[67]
  PIN a[68]
    DIRECTION INPUT ;
    USE SIGNAL ;
    PORT
      LAYER M3 ;
        RECT  41.652 105.779 41.67 105.816 ;
    END
  END a[68]
  PIN a[69]
    DIRECTION INPUT ;
    USE SIGNAL ;
    PORT
      LAYER M3 ;
        RECT  41.724 105.779 41.742 105.816 ;
    END
  END a[69]
  PIN a[6]
    DIRECTION INPUT ;
    USE SIGNAL ;
    PORT
      LAYER M3 ;
        RECT  44.1 105.779 44.118 105.816 ;
    END
  END a[6]
  PIN a[70]
    DIRECTION INPUT ;
    USE SIGNAL ;
    PORT
      LAYER M3 ;
        RECT  41.796 105.779 41.814 105.816 ;
    END
  END a[70]
  PIN a[71]
    DIRECTION INPUT ;
    USE SIGNAL ;
    PORT
      LAYER M3 ;
        RECT  41.868 105.779 41.886 105.816 ;
    END
  END a[71]
  PIN a[72]
    DIRECTION INPUT ;
    USE SIGNAL ;
    PORT
      LAYER M3 ;
        RECT  41.94 105.779 41.958 105.816 ;
    END
  END a[72]
  PIN a[73]
    DIRECTION INPUT ;
    USE SIGNAL ;
    PORT
      LAYER M3 ;
        RECT  42.012 105.779 42.03 105.816 ;
    END
  END a[73]
  PIN a[74]
    DIRECTION INPUT ;
    USE SIGNAL ;
    PORT
      LAYER M3 ;
        RECT  42.084 105.779 42.102 105.816 ;
    END
  END a[74]
  PIN a[75]
    DIRECTION INPUT ;
    USE SIGNAL ;
    PORT
      LAYER M3 ;
        RECT  42.156 105.779 42.174 105.816 ;
    END
  END a[75]
  PIN a[76]
    DIRECTION INPUT ;
    USE SIGNAL ;
    PORT
      LAYER M3 ;
        RECT  42.228 105.779 42.246 105.816 ;
    END
  END a[76]
  PIN a[77]
    DIRECTION INPUT ;
    USE SIGNAL ;
    PORT
      LAYER M3 ;
        RECT  42.3 105.779 42.318 105.816 ;
    END
  END a[77]
  PIN a[78]
    DIRECTION INPUT ;
    USE SIGNAL ;
    PORT
      LAYER M3 ;
        RECT  42.372 105.779 42.39 105.816 ;
    END
  END a[78]
  PIN a[79]
    DIRECTION INPUT ;
    USE SIGNAL ;
    PORT
      LAYER M3 ;
        RECT  42.444 105.779 42.462 105.816 ;
    END
  END a[79]
  PIN a[7]
    DIRECTION INPUT ;
    USE SIGNAL ;
    PORT
      LAYER M3 ;
        RECT  44.172 105.779 44.19 105.816 ;
    END
  END a[7]
  PIN a[80]
    DIRECTION INPUT ;
    USE SIGNAL ;
    PORT
      LAYER M3 ;
        RECT  42.516 105.779 42.534 105.816 ;
    END
  END a[80]
  PIN a[81]
    DIRECTION INPUT ;
    USE SIGNAL ;
    PORT
      LAYER M3 ;
        RECT  42.588 105.779 42.606 105.816 ;
    END
  END a[81]
  PIN a[82]
    DIRECTION INPUT ;
    USE SIGNAL ;
    PORT
      LAYER M3 ;
        RECT  42.66 105.779 42.678 105.816 ;
    END
  END a[82]
  PIN a[83]
    DIRECTION INPUT ;
    USE SIGNAL ;
    PORT
      LAYER M3 ;
        RECT  42.732 105.779 42.75 105.816 ;
    END
  END a[83]
  PIN a[84]
    DIRECTION INPUT ;
    USE SIGNAL ;
    PORT
      LAYER M3 ;
        RECT  42.804 105.779 42.822 105.816 ;
    END
  END a[84]
  PIN a[85]
    DIRECTION INPUT ;
    USE SIGNAL ;
    PORT
      LAYER M3 ;
        RECT  42.876 105.779 42.894 105.816 ;
    END
  END a[85]
  PIN a[86]
    DIRECTION INPUT ;
    USE SIGNAL ;
    PORT
      LAYER M3 ;
        RECT  42.948 105.779 42.966 105.816 ;
    END
  END a[86]
  PIN a[87]
    DIRECTION INPUT ;
    USE SIGNAL ;
    PORT
      LAYER M3 ;
        RECT  43.02 105.779 43.038 105.816 ;
    END
  END a[87]
  PIN a[88]
    DIRECTION INPUT ;
    USE SIGNAL ;
    PORT
      LAYER M3 ;
        RECT  43.092 105.779 43.11 105.816 ;
    END
  END a[88]
  PIN a[89]
    DIRECTION INPUT ;
    USE SIGNAL ;
    PORT
      LAYER M3 ;
        RECT  43.164 105.779 43.182 105.816 ;
    END
  END a[89]
  PIN a[8]
    DIRECTION INPUT ;
    USE SIGNAL ;
    PORT
      LAYER M3 ;
        RECT  44.244 105.779 44.262 105.816 ;
    END
  END a[8]
  PIN a[90]
    DIRECTION INPUT ;
    USE SIGNAL ;
    PORT
      LAYER M3 ;
        RECT  43.236 105.779 43.254 105.816 ;
    END
  END a[90]
  PIN a[91]
    DIRECTION INPUT ;
    USE SIGNAL ;
    PORT
      LAYER M3 ;
        RECT  43.308 105.779 43.326 105.816 ;
    END
  END a[91]
  PIN a[92]
    DIRECTION INPUT ;
    USE SIGNAL ;
    PORT
      LAYER M3 ;
        RECT  43.38 105.779 43.398 105.816 ;
    END
  END a[92]
  PIN a[93]
    DIRECTION INPUT ;
    USE SIGNAL ;
    PORT
      LAYER M3 ;
        RECT  43.452 105.779 43.47 105.816 ;
    END
  END a[93]
  PIN a[94]
    DIRECTION INPUT ;
    USE SIGNAL ;
    PORT
      LAYER M3 ;
        RECT  43.524 105.779 43.542 105.816 ;
    END
  END a[94]
  PIN a[95]
    DIRECTION INPUT ;
    USE SIGNAL ;
    PORT
      LAYER M3 ;
        RECT  43.596 105.779 43.614 105.816 ;
    END
  END a[95]
  PIN a[96]
    DIRECTION INPUT ;
    USE SIGNAL ;
    PORT
      LAYER M5 ;
        RECT  49.68 105.732 49.704 105.816 ;
    END
  END a[96]
  PIN a[97]
    DIRECTION INPUT ;
    USE SIGNAL ;
    PORT
      LAYER M5 ;
        RECT  49.776 105.732 49.8 105.816 ;
    END
  END a[97]
  PIN a[98]
    DIRECTION INPUT ;
    USE SIGNAL ;
    PORT
      LAYER M5 ;
        RECT  49.872 105.732 49.896 105.816 ;
    END
  END a[98]
  PIN a[99]
    DIRECTION INPUT ;
    USE SIGNAL ;
    PORT
      LAYER M5 ;
        RECT  49.968 105.732 49.992 105.816 ;
    END
  END a[99]
  PIN a[9]
    DIRECTION INPUT ;
    USE SIGNAL ;
    PORT
      LAYER M3 ;
        RECT  44.316 105.779 44.334 105.816 ;
    END
  END a[9]
  PIN b[0]
    DIRECTION OUTPUT ;
    USE SIGNAL ;
    PORT
      LAYER M4 ;
        RECT  104.004 32.208 104.088 32.232 ;
    END
  END b[0]
  PIN b[100]
    DIRECTION OUTPUT ;
    USE SIGNAL ;
    PORT
      LAYER M4 ;
        RECT  104.004 23.376 104.088 23.4 ;
    END
  END b[100]
  PIN b[101]
    DIRECTION OUTPUT ;
    USE SIGNAL ;
    PORT
      LAYER M4 ;
        RECT  104.004 23.472 104.088 23.496 ;
    END
  END b[101]
  PIN b[102]
    DIRECTION OUTPUT ;
    USE SIGNAL ;
    PORT
      LAYER M4 ;
        RECT  104.004 23.568 104.088 23.592 ;
    END
  END b[102]
  PIN b[103]
    DIRECTION OUTPUT ;
    USE SIGNAL ;
    PORT
      LAYER M4 ;
        RECT  104.004 23.664 104.088 23.688 ;
    END
  END b[103]
  PIN b[104]
    DIRECTION OUTPUT ;
    USE SIGNAL ;
    PORT
      LAYER M4 ;
        RECT  104.004 23.76 104.088 23.784 ;
    END
  END b[104]
  PIN b[105]
    DIRECTION OUTPUT ;
    USE SIGNAL ;
    PORT
      LAYER M4 ;
        RECT  104.004 23.856 104.088 23.88 ;
    END
  END b[105]
  PIN b[106]
    DIRECTION OUTPUT ;
    USE SIGNAL ;
    PORT
      LAYER M4 ;
        RECT  104.004 23.952 104.088 23.976 ;
    END
  END b[106]
  PIN b[107]
    DIRECTION OUTPUT ;
    USE SIGNAL ;
    PORT
      LAYER M4 ;
        RECT  104.004 24.048 104.088 24.072 ;
    END
  END b[107]
  PIN b[108]
    DIRECTION OUTPUT ;
    USE SIGNAL ;
    PORT
      LAYER M4 ;
        RECT  104.004 24.144 104.088 24.168 ;
    END
  END b[108]
  PIN b[109]
    DIRECTION OUTPUT ;
    USE SIGNAL ;
    PORT
      LAYER M4 ;
        RECT  104.004 24.24 104.088 24.264 ;
    END
  END b[109]
  PIN b[10]
    DIRECTION OUTPUT ;
    USE SIGNAL ;
    PORT
      LAYER M4 ;
        RECT  104.004 33.168 104.088 33.192 ;
    END
  END b[10]
  PIN b[110]
    DIRECTION OUTPUT ;
    USE SIGNAL ;
    PORT
      LAYER M4 ;
        RECT  104.004 24.336 104.088 24.36 ;
    END
  END b[110]
  PIN b[111]
    DIRECTION OUTPUT ;
    USE SIGNAL ;
    PORT
      LAYER M4 ;
        RECT  104.004 24.432 104.088 24.456 ;
    END
  END b[111]
  PIN b[112]
    DIRECTION OUTPUT ;
    USE SIGNAL ;
    PORT
      LAYER M4 ;
        RECT  104.004 24.528 104.088 24.552 ;
    END
  END b[112]
  PIN b[113]
    DIRECTION OUTPUT ;
    USE SIGNAL ;
    PORT
      LAYER M4 ;
        RECT  104.004 24.624 104.088 24.648 ;
    END
  END b[113]
  PIN b[114]
    DIRECTION OUTPUT ;
    USE SIGNAL ;
    PORT
      LAYER M4 ;
        RECT  104.004 24.72 104.088 24.744 ;
    END
  END b[114]
  PIN b[115]
    DIRECTION OUTPUT ;
    USE SIGNAL ;
    PORT
      LAYER M4 ;
        RECT  104.004 24.816 104.088 24.84 ;
    END
  END b[115]
  PIN b[116]
    DIRECTION OUTPUT ;
    USE SIGNAL ;
    PORT
      LAYER M4 ;
        RECT  104.004 24.912 104.088 24.936 ;
    END
  END b[116]
  PIN b[117]
    DIRECTION OUTPUT ;
    USE SIGNAL ;
    PORT
      LAYER M4 ;
        RECT  104.004 25.008 104.088 25.032 ;
    END
  END b[117]
  PIN b[118]
    DIRECTION OUTPUT ;
    USE SIGNAL ;
    PORT
      LAYER M4 ;
        RECT  104.004 25.104 104.088 25.128 ;
    END
  END b[118]
  PIN b[119]
    DIRECTION OUTPUT ;
    USE SIGNAL ;
    PORT
      LAYER M4 ;
        RECT  104.004 25.2 104.088 25.224 ;
    END
  END b[119]
  PIN b[11]
    DIRECTION OUTPUT ;
    USE SIGNAL ;
    PORT
      LAYER M4 ;
        RECT  104.004 33.264 104.088 33.288 ;
    END
  END b[11]
  PIN b[120]
    DIRECTION OUTPUT ;
    USE SIGNAL ;
    PORT
      LAYER M4 ;
        RECT  104.004 25.296 104.088 25.32 ;
    END
  END b[120]
  PIN b[121]
    DIRECTION OUTPUT ;
    USE SIGNAL ;
    PORT
      LAYER M4 ;
        RECT  104.004 25.392 104.088 25.416 ;
    END
  END b[121]
  PIN b[122]
    DIRECTION OUTPUT ;
    USE SIGNAL ;
    PORT
      LAYER M4 ;
        RECT  104.004 25.488 104.088 25.512 ;
    END
  END b[122]
  PIN b[123]
    DIRECTION OUTPUT ;
    USE SIGNAL ;
    PORT
      LAYER M4 ;
        RECT  104.004 25.584 104.088 25.608 ;
    END
  END b[123]
  PIN b[124]
    DIRECTION OUTPUT ;
    USE SIGNAL ;
    PORT
      LAYER M4 ;
        RECT  104.004 25.68 104.088 25.704 ;
    END
  END b[124]
  PIN b[125]
    DIRECTION OUTPUT ;
    USE SIGNAL ;
    PORT
      LAYER M4 ;
        RECT  104.004 25.776 104.088 25.8 ;
    END
  END b[125]
  PIN b[126]
    DIRECTION OUTPUT ;
    USE SIGNAL ;
    PORT
      LAYER M4 ;
        RECT  104.004 25.872 104.088 25.896 ;
    END
  END b[126]
  PIN b[127]
    DIRECTION OUTPUT ;
    USE SIGNAL ;
    PORT
      LAYER M4 ;
        RECT  104.004 25.968 104.088 25.992 ;
    END
  END b[127]
  PIN b[128]
    DIRECTION OUTPUT ;
    USE SIGNAL ;
    PORT
      LAYER M4 ;
        RECT  104.004 19.92 104.088 19.944 ;
    END
  END b[128]
  PIN b[129]
    DIRECTION OUTPUT ;
    USE SIGNAL ;
    PORT
      LAYER M4 ;
        RECT  104.004 20.016 104.088 20.04 ;
    END
  END b[129]
  PIN b[12]
    DIRECTION OUTPUT ;
    USE SIGNAL ;
    PORT
      LAYER M4 ;
        RECT  104.004 33.36 104.088 33.384 ;
    END
  END b[12]
  PIN b[130]
    DIRECTION OUTPUT ;
    USE SIGNAL ;
    PORT
      LAYER M4 ;
        RECT  104.004 20.112 104.088 20.136 ;
    END
  END b[130]
  PIN b[131]
    DIRECTION OUTPUT ;
    USE SIGNAL ;
    PORT
      LAYER M4 ;
        RECT  104.004 20.208 104.088 20.232 ;
    END
  END b[131]
  PIN b[132]
    DIRECTION OUTPUT ;
    USE SIGNAL ;
    PORT
      LAYER M4 ;
        RECT  104.004 20.304 104.088 20.328 ;
    END
  END b[132]
  PIN b[133]
    DIRECTION OUTPUT ;
    USE SIGNAL ;
    PORT
      LAYER M4 ;
        RECT  104.004 20.4 104.088 20.424 ;
    END
  END b[133]
  PIN b[134]
    DIRECTION OUTPUT ;
    USE SIGNAL ;
    PORT
      LAYER M4 ;
        RECT  104.004 20.496 104.088 20.52 ;
    END
  END b[134]
  PIN b[135]
    DIRECTION OUTPUT ;
    USE SIGNAL ;
    PORT
      LAYER M4 ;
        RECT  104.004 20.592 104.088 20.616 ;
    END
  END b[135]
  PIN b[136]
    DIRECTION OUTPUT ;
    USE SIGNAL ;
    PORT
      LAYER M4 ;
        RECT  104.004 20.688 104.088 20.712 ;
    END
  END b[136]
  PIN b[137]
    DIRECTION OUTPUT ;
    USE SIGNAL ;
    PORT
      LAYER M4 ;
        RECT  104.004 20.784 104.088 20.808 ;
    END
  END b[137]
  PIN b[138]
    DIRECTION OUTPUT ;
    USE SIGNAL ;
    PORT
      LAYER M4 ;
        RECT  104.004 20.88 104.088 20.904 ;
    END
  END b[138]
  PIN b[139]
    DIRECTION OUTPUT ;
    USE SIGNAL ;
    PORT
      LAYER M4 ;
        RECT  104.004 20.976 104.088 21 ;
    END
  END b[139]
  PIN b[13]
    DIRECTION OUTPUT ;
    USE SIGNAL ;
    PORT
      LAYER M4 ;
        RECT  104.004 33.456 104.088 33.48 ;
    END
  END b[13]
  PIN b[140]
    DIRECTION OUTPUT ;
    USE SIGNAL ;
    PORT
      LAYER M4 ;
        RECT  104.004 21.072 104.088 21.096 ;
    END
  END b[140]
  PIN b[141]
    DIRECTION OUTPUT ;
    USE SIGNAL ;
    PORT
      LAYER M4 ;
        RECT  104.004 21.168 104.088 21.192 ;
    END
  END b[141]
  PIN b[142]
    DIRECTION OUTPUT ;
    USE SIGNAL ;
    PORT
      LAYER M4 ;
        RECT  104.004 21.264 104.088 21.288 ;
    END
  END b[142]
  PIN b[143]
    DIRECTION OUTPUT ;
    USE SIGNAL ;
    PORT
      LAYER M4 ;
        RECT  104.004 21.36 104.088 21.384 ;
    END
  END b[143]
  PIN b[144]
    DIRECTION OUTPUT ;
    USE SIGNAL ;
    PORT
      LAYER M4 ;
        RECT  104.004 21.456 104.088 21.48 ;
    END
  END b[144]
  PIN b[145]
    DIRECTION OUTPUT ;
    USE SIGNAL ;
    PORT
      LAYER M4 ;
        RECT  104.004 21.552 104.088 21.576 ;
    END
  END b[145]
  PIN b[146]
    DIRECTION OUTPUT ;
    USE SIGNAL ;
    PORT
      LAYER M4 ;
        RECT  104.004 21.648 104.088 21.672 ;
    END
  END b[146]
  PIN b[147]
    DIRECTION OUTPUT ;
    USE SIGNAL ;
    PORT
      LAYER M4 ;
        RECT  104.004 21.744 104.088 21.768 ;
    END
  END b[147]
  PIN b[148]
    DIRECTION OUTPUT ;
    USE SIGNAL ;
    PORT
      LAYER M4 ;
        RECT  104.004 21.84 104.088 21.864 ;
    END
  END b[148]
  PIN b[149]
    DIRECTION OUTPUT ;
    USE SIGNAL ;
    PORT
      LAYER M4 ;
        RECT  104.004 21.936 104.088 21.96 ;
    END
  END b[149]
  PIN b[14]
    DIRECTION OUTPUT ;
    USE SIGNAL ;
    PORT
      LAYER M4 ;
        RECT  104.004 33.552 104.088 33.576 ;
    END
  END b[14]
  PIN b[150]
    DIRECTION OUTPUT ;
    USE SIGNAL ;
    PORT
      LAYER M4 ;
        RECT  104.004 22.032 104.088 22.056 ;
    END
  END b[150]
  PIN b[151]
    DIRECTION OUTPUT ;
    USE SIGNAL ;
    PORT
      LAYER M4 ;
        RECT  104.004 22.128 104.088 22.152 ;
    END
  END b[151]
  PIN b[152]
    DIRECTION OUTPUT ;
    USE SIGNAL ;
    PORT
      LAYER M4 ;
        RECT  104.004 22.224 104.088 22.248 ;
    END
  END b[152]
  PIN b[153]
    DIRECTION OUTPUT ;
    USE SIGNAL ;
    PORT
      LAYER M4 ;
        RECT  104.004 22.32 104.088 22.344 ;
    END
  END b[153]
  PIN b[154]
    DIRECTION OUTPUT ;
    USE SIGNAL ;
    PORT
      LAYER M4 ;
        RECT  104.004 22.416 104.088 22.44 ;
    END
  END b[154]
  PIN b[155]
    DIRECTION OUTPUT ;
    USE SIGNAL ;
    PORT
      LAYER M4 ;
        RECT  104.004 22.512 104.088 22.536 ;
    END
  END b[155]
  PIN b[156]
    DIRECTION OUTPUT ;
    USE SIGNAL ;
    PORT
      LAYER M4 ;
        RECT  104.004 22.608 104.088 22.632 ;
    END
  END b[156]
  PIN b[157]
    DIRECTION OUTPUT ;
    USE SIGNAL ;
    PORT
      LAYER M4 ;
        RECT  104.004 22.704 104.088 22.728 ;
    END
  END b[157]
  PIN b[158]
    DIRECTION OUTPUT ;
    USE SIGNAL ;
    PORT
      LAYER M4 ;
        RECT  104.004 22.8 104.088 22.824 ;
    END
  END b[158]
  PIN b[159]
    DIRECTION OUTPUT ;
    USE SIGNAL ;
    PORT
      LAYER M4 ;
        RECT  104.004 22.896 104.088 22.92 ;
    END
  END b[159]
  PIN b[15]
    DIRECTION OUTPUT ;
    USE SIGNAL ;
    PORT
      LAYER M4 ;
        RECT  104.004 33.648 104.088 33.672 ;
    END
  END b[15]
  PIN b[160]
    DIRECTION OUTPUT ;
    USE SIGNAL ;
    PORT
      LAYER M4 ;
        RECT  104.004 35.28 104.088 35.304 ;
    END
  END b[160]
  PIN b[161]
    DIRECTION OUTPUT ;
    USE SIGNAL ;
    PORT
      LAYER M4 ;
        RECT  104.004 35.376 104.088 35.4 ;
    END
  END b[161]
  PIN b[162]
    DIRECTION OUTPUT ;
    USE SIGNAL ;
    PORT
      LAYER M4 ;
        RECT  104.004 35.472 104.088 35.496 ;
    END
  END b[162]
  PIN b[163]
    DIRECTION OUTPUT ;
    USE SIGNAL ;
    PORT
      LAYER M4 ;
        RECT  104.004 35.568 104.088 35.592 ;
    END
  END b[163]
  PIN b[164]
    DIRECTION OUTPUT ;
    USE SIGNAL ;
    PORT
      LAYER M4 ;
        RECT  104.004 35.664 104.088 35.688 ;
    END
  END b[164]
  PIN b[165]
    DIRECTION OUTPUT ;
    USE SIGNAL ;
    PORT
      LAYER M4 ;
        RECT  104.004 35.76 104.088 35.784 ;
    END
  END b[165]
  PIN b[166]
    DIRECTION OUTPUT ;
    USE SIGNAL ;
    PORT
      LAYER M4 ;
        RECT  104.004 35.856 104.088 35.88 ;
    END
  END b[166]
  PIN b[167]
    DIRECTION OUTPUT ;
    USE SIGNAL ;
    PORT
      LAYER M4 ;
        RECT  104.004 35.952 104.088 35.976 ;
    END
  END b[167]
  PIN b[168]
    DIRECTION OUTPUT ;
    USE SIGNAL ;
    PORT
      LAYER M4 ;
        RECT  104.004 36.048 104.088 36.072 ;
    END
  END b[168]
  PIN b[169]
    DIRECTION OUTPUT ;
    USE SIGNAL ;
    PORT
      LAYER M4 ;
        RECT  104.004 36.144 104.088 36.168 ;
    END
  END b[169]
  PIN b[16]
    DIRECTION OUTPUT ;
    USE SIGNAL ;
    PORT
      LAYER M4 ;
        RECT  104.004 33.744 104.088 33.768 ;
    END
  END b[16]
  PIN b[170]
    DIRECTION OUTPUT ;
    USE SIGNAL ;
    PORT
      LAYER M4 ;
        RECT  104.004 36.24 104.088 36.264 ;
    END
  END b[170]
  PIN b[171]
    DIRECTION OUTPUT ;
    USE SIGNAL ;
    PORT
      LAYER M4 ;
        RECT  104.004 36.336 104.088 36.36 ;
    END
  END b[171]
  PIN b[172]
    DIRECTION OUTPUT ;
    USE SIGNAL ;
    PORT
      LAYER M4 ;
        RECT  104.004 36.432 104.088 36.456 ;
    END
  END b[172]
  PIN b[173]
    DIRECTION OUTPUT ;
    USE SIGNAL ;
    PORT
      LAYER M4 ;
        RECT  104.004 36.528 104.088 36.552 ;
    END
  END b[173]
  PIN b[174]
    DIRECTION OUTPUT ;
    USE SIGNAL ;
    PORT
      LAYER M4 ;
        RECT  104.004 36.624 104.088 36.648 ;
    END
  END b[174]
  PIN b[175]
    DIRECTION OUTPUT ;
    USE SIGNAL ;
    PORT
      LAYER M4 ;
        RECT  104.004 36.72 104.088 36.744 ;
    END
  END b[175]
  PIN b[176]
    DIRECTION OUTPUT ;
    USE SIGNAL ;
    PORT
      LAYER M4 ;
        RECT  104.004 36.816 104.088 36.84 ;
    END
  END b[176]
  PIN b[177]
    DIRECTION OUTPUT ;
    USE SIGNAL ;
    PORT
      LAYER M4 ;
        RECT  104.004 36.912 104.088 36.936 ;
    END
  END b[177]
  PIN b[178]
    DIRECTION OUTPUT ;
    USE SIGNAL ;
    PORT
      LAYER M4 ;
        RECT  104.004 37.008 104.088 37.032 ;
    END
  END b[178]
  PIN b[179]
    DIRECTION OUTPUT ;
    USE SIGNAL ;
    PORT
      LAYER M4 ;
        RECT  104.004 37.104 104.088 37.128 ;
    END
  END b[179]
  PIN b[17]
    DIRECTION OUTPUT ;
    USE SIGNAL ;
    PORT
      LAYER M4 ;
        RECT  104.004 33.84 104.088 33.864 ;
    END
  END b[17]
  PIN b[180]
    DIRECTION OUTPUT ;
    USE SIGNAL ;
    PORT
      LAYER M4 ;
        RECT  104.004 37.2 104.088 37.224 ;
    END
  END b[180]
  PIN b[181]
    DIRECTION OUTPUT ;
    USE SIGNAL ;
    PORT
      LAYER M4 ;
        RECT  104.004 37.296 104.088 37.32 ;
    END
  END b[181]
  PIN b[182]
    DIRECTION OUTPUT ;
    USE SIGNAL ;
    PORT
      LAYER M4 ;
        RECT  104.004 37.392 104.088 37.416 ;
    END
  END b[182]
  PIN b[183]
    DIRECTION OUTPUT ;
    USE SIGNAL ;
    PORT
      LAYER M4 ;
        RECT  104.004 37.488 104.088 37.512 ;
    END
  END b[183]
  PIN b[184]
    DIRECTION OUTPUT ;
    USE SIGNAL ;
    PORT
      LAYER M4 ;
        RECT  104.004 37.584 104.088 37.608 ;
    END
  END b[184]
  PIN b[185]
    DIRECTION OUTPUT ;
    USE SIGNAL ;
    PORT
      LAYER M4 ;
        RECT  104.004 37.68 104.088 37.704 ;
    END
  END b[185]
  PIN b[186]
    DIRECTION OUTPUT ;
    USE SIGNAL ;
    PORT
      LAYER M4 ;
        RECT  104.004 37.776 104.088 37.8 ;
    END
  END b[186]
  PIN b[187]
    DIRECTION OUTPUT ;
    USE SIGNAL ;
    PORT
      LAYER M4 ;
        RECT  104.004 37.872 104.088 37.896 ;
    END
  END b[187]
  PIN b[188]
    DIRECTION OUTPUT ;
    USE SIGNAL ;
    PORT
      LAYER M4 ;
        RECT  104.004 37.968 104.088 37.992 ;
    END
  END b[188]
  PIN b[189]
    DIRECTION OUTPUT ;
    USE SIGNAL ;
    PORT
      LAYER M4 ;
        RECT  104.004 38.064 104.088 38.088 ;
    END
  END b[189]
  PIN b[18]
    DIRECTION OUTPUT ;
    USE SIGNAL ;
    PORT
      LAYER M4 ;
        RECT  104.004 33.936 104.088 33.96 ;
    END
  END b[18]
  PIN b[190]
    DIRECTION OUTPUT ;
    USE SIGNAL ;
    PORT
      LAYER M4 ;
        RECT  104.004 38.16 104.088 38.184 ;
    END
  END b[190]
  PIN b[191]
    DIRECTION OUTPUT ;
    USE SIGNAL ;
    PORT
      LAYER M4 ;
        RECT  104.004 38.256 104.088 38.28 ;
    END
  END b[191]
  PIN b[192]
    DIRECTION OUTPUT ;
    USE SIGNAL ;
    PORT
      LAYER M4 ;
        RECT  104.004 42.192 104.088 42.216 ;
    END
  END b[192]
  PIN b[193]
    DIRECTION OUTPUT ;
    USE SIGNAL ;
    PORT
      LAYER M4 ;
        RECT  104.004 42.288 104.088 42.312 ;
    END
  END b[193]
  PIN b[194]
    DIRECTION OUTPUT ;
    USE SIGNAL ;
    PORT
      LAYER M4 ;
        RECT  104.004 42.384 104.088 42.408 ;
    END
  END b[194]
  PIN b[195]
    DIRECTION OUTPUT ;
    USE SIGNAL ;
    PORT
      LAYER M4 ;
        RECT  104.004 42.48 104.088 42.504 ;
    END
  END b[195]
  PIN b[196]
    DIRECTION OUTPUT ;
    USE SIGNAL ;
    PORT
      LAYER M4 ;
        RECT  104.004 42.576 104.088 42.6 ;
    END
  END b[196]
  PIN b[197]
    DIRECTION OUTPUT ;
    USE SIGNAL ;
    PORT
      LAYER M4 ;
        RECT  104.004 42.672 104.088 42.696 ;
    END
  END b[197]
  PIN b[198]
    DIRECTION OUTPUT ;
    USE SIGNAL ;
    PORT
      LAYER M4 ;
        RECT  104.004 42.768 104.088 42.792 ;
    END
  END b[198]
  PIN b[199]
    DIRECTION OUTPUT ;
    USE SIGNAL ;
    PORT
      LAYER M4 ;
        RECT  104.004 42.864 104.088 42.888 ;
    END
  END b[199]
  PIN b[19]
    DIRECTION OUTPUT ;
    USE SIGNAL ;
    PORT
      LAYER M4 ;
        RECT  104.004 34.032 104.088 34.056 ;
    END
  END b[19]
  PIN b[1]
    DIRECTION OUTPUT ;
    USE SIGNAL ;
    PORT
      LAYER M4 ;
        RECT  104.004 32.304 104.088 32.328 ;
    END
  END b[1]
  PIN b[200]
    DIRECTION OUTPUT ;
    USE SIGNAL ;
    PORT
      LAYER M4 ;
        RECT  104.004 42.96 104.088 42.984 ;
    END
  END b[200]
  PIN b[201]
    DIRECTION OUTPUT ;
    USE SIGNAL ;
    PORT
      LAYER M4 ;
        RECT  104.004 43.056 104.088 43.08 ;
    END
  END b[201]
  PIN b[202]
    DIRECTION OUTPUT ;
    USE SIGNAL ;
    PORT
      LAYER M4 ;
        RECT  104.004 43.152 104.088 43.176 ;
    END
  END b[202]
  PIN b[203]
    DIRECTION OUTPUT ;
    USE SIGNAL ;
    PORT
      LAYER M4 ;
        RECT  104.004 43.248 104.088 43.272 ;
    END
  END b[203]
  PIN b[204]
    DIRECTION OUTPUT ;
    USE SIGNAL ;
    PORT
      LAYER M4 ;
        RECT  104.004 43.344 104.088 43.368 ;
    END
  END b[204]
  PIN b[205]
    DIRECTION OUTPUT ;
    USE SIGNAL ;
    PORT
      LAYER M4 ;
        RECT  104.004 43.44 104.088 43.464 ;
    END
  END b[205]
  PIN b[206]
    DIRECTION OUTPUT ;
    USE SIGNAL ;
    PORT
      LAYER M4 ;
        RECT  104.004 43.536 104.088 43.56 ;
    END
  END b[206]
  PIN b[207]
    DIRECTION OUTPUT ;
    USE SIGNAL ;
    PORT
      LAYER M4 ;
        RECT  104.004 43.632 104.088 43.656 ;
    END
  END b[207]
  PIN b[208]
    DIRECTION OUTPUT ;
    USE SIGNAL ;
    PORT
      LAYER M4 ;
        RECT  104.004 43.728 104.088 43.752 ;
    END
  END b[208]
  PIN b[209]
    DIRECTION OUTPUT ;
    USE SIGNAL ;
    PORT
      LAYER M4 ;
        RECT  104.004 43.824 104.088 43.848 ;
    END
  END b[209]
  PIN b[20]
    DIRECTION OUTPUT ;
    USE SIGNAL ;
    PORT
      LAYER M4 ;
        RECT  104.004 34.128 104.088 34.152 ;
    END
  END b[20]
  PIN b[210]
    DIRECTION OUTPUT ;
    USE SIGNAL ;
    PORT
      LAYER M4 ;
        RECT  104.004 43.92 104.088 43.944 ;
    END
  END b[210]
  PIN b[211]
    DIRECTION OUTPUT ;
    USE SIGNAL ;
    PORT
      LAYER M4 ;
        RECT  104.004 44.016 104.088 44.04 ;
    END
  END b[211]
  PIN b[212]
    DIRECTION OUTPUT ;
    USE SIGNAL ;
    PORT
      LAYER M4 ;
        RECT  104.004 44.112 104.088 44.136 ;
    END
  END b[212]
  PIN b[213]
    DIRECTION OUTPUT ;
    USE SIGNAL ;
    PORT
      LAYER M4 ;
        RECT  104.004 44.208 104.088 44.232 ;
    END
  END b[213]
  PIN b[214]
    DIRECTION OUTPUT ;
    USE SIGNAL ;
    PORT
      LAYER M4 ;
        RECT  104.004 44.304 104.088 44.328 ;
    END
  END b[214]
  PIN b[215]
    DIRECTION OUTPUT ;
    USE SIGNAL ;
    PORT
      LAYER M4 ;
        RECT  104.004 44.4 104.088 44.424 ;
    END
  END b[215]
  PIN b[216]
    DIRECTION OUTPUT ;
    USE SIGNAL ;
    PORT
      LAYER M4 ;
        RECT  104.004 44.496 104.088 44.52 ;
    END
  END b[216]
  PIN b[217]
    DIRECTION OUTPUT ;
    USE SIGNAL ;
    PORT
      LAYER M4 ;
        RECT  104.004 44.592 104.088 44.616 ;
    END
  END b[217]
  PIN b[218]
    DIRECTION OUTPUT ;
    USE SIGNAL ;
    PORT
      LAYER M4 ;
        RECT  104.004 44.688 104.088 44.712 ;
    END
  END b[218]
  PIN b[219]
    DIRECTION OUTPUT ;
    USE SIGNAL ;
    PORT
      LAYER M4 ;
        RECT  104.004 44.784 104.088 44.808 ;
    END
  END b[219]
  PIN b[21]
    DIRECTION OUTPUT ;
    USE SIGNAL ;
    PORT
      LAYER M4 ;
        RECT  104.004 34.224 104.088 34.248 ;
    END
  END b[21]
  PIN b[220]
    DIRECTION OUTPUT ;
    USE SIGNAL ;
    PORT
      LAYER M4 ;
        RECT  104.004 44.88 104.088 44.904 ;
    END
  END b[220]
  PIN b[221]
    DIRECTION OUTPUT ;
    USE SIGNAL ;
    PORT
      LAYER M4 ;
        RECT  104.004 44.976 104.088 45 ;
    END
  END b[221]
  PIN b[222]
    DIRECTION OUTPUT ;
    USE SIGNAL ;
    PORT
      LAYER M4 ;
        RECT  104.004 45.072 104.088 45.096 ;
    END
  END b[222]
  PIN b[223]
    DIRECTION OUTPUT ;
    USE SIGNAL ;
    PORT
      LAYER M4 ;
        RECT  104.004 45.168 104.088 45.192 ;
    END
  END b[223]
  PIN b[224]
    DIRECTION OUTPUT ;
    USE SIGNAL ;
    PORT
      LAYER M4 ;
        RECT  104.004 48.336 104.088 48.36 ;
    END
  END b[224]
  PIN b[225]
    DIRECTION OUTPUT ;
    USE SIGNAL ;
    PORT
      LAYER M4 ;
        RECT  104.004 48.432 104.088 48.456 ;
    END
  END b[225]
  PIN b[226]
    DIRECTION OUTPUT ;
    USE SIGNAL ;
    PORT
      LAYER M4 ;
        RECT  104.004 48.528 104.088 48.552 ;
    END
  END b[226]
  PIN b[227]
    DIRECTION OUTPUT ;
    USE SIGNAL ;
    PORT
      LAYER M4 ;
        RECT  104.004 48.624 104.088 48.648 ;
    END
  END b[227]
  PIN b[228]
    DIRECTION OUTPUT ;
    USE SIGNAL ;
    PORT
      LAYER M4 ;
        RECT  104.004 48.72 104.088 48.744 ;
    END
  END b[228]
  PIN b[229]
    DIRECTION OUTPUT ;
    USE SIGNAL ;
    PORT
      LAYER M4 ;
        RECT  104.004 48.816 104.088 48.84 ;
    END
  END b[229]
  PIN b[22]
    DIRECTION OUTPUT ;
    USE SIGNAL ;
    PORT
      LAYER M4 ;
        RECT  104.004 34.32 104.088 34.344 ;
    END
  END b[22]
  PIN b[230]
    DIRECTION OUTPUT ;
    USE SIGNAL ;
    PORT
      LAYER M4 ;
        RECT  104.004 48.912 104.088 48.936 ;
    END
  END b[230]
  PIN b[231]
    DIRECTION OUTPUT ;
    USE SIGNAL ;
    PORT
      LAYER M4 ;
        RECT  104.004 49.008 104.088 49.032 ;
    END
  END b[231]
  PIN b[232]
    DIRECTION OUTPUT ;
    USE SIGNAL ;
    PORT
      LAYER M4 ;
        RECT  104.004 49.104 104.088 49.128 ;
    END
  END b[232]
  PIN b[233]
    DIRECTION OUTPUT ;
    USE SIGNAL ;
    PORT
      LAYER M4 ;
        RECT  104.004 49.2 104.088 49.224 ;
    END
  END b[233]
  PIN b[234]
    DIRECTION OUTPUT ;
    USE SIGNAL ;
    PORT
      LAYER M4 ;
        RECT  104.004 49.296 104.088 49.32 ;
    END
  END b[234]
  PIN b[235]
    DIRECTION OUTPUT ;
    USE SIGNAL ;
    PORT
      LAYER M4 ;
        RECT  104.004 49.392 104.088 49.416 ;
    END
  END b[235]
  PIN b[236]
    DIRECTION OUTPUT ;
    USE SIGNAL ;
    PORT
      LAYER M4 ;
        RECT  104.004 49.488 104.088 49.512 ;
    END
  END b[236]
  PIN b[237]
    DIRECTION OUTPUT ;
    USE SIGNAL ;
    PORT
      LAYER M4 ;
        RECT  104.004 49.584 104.088 49.608 ;
    END
  END b[237]
  PIN b[238]
    DIRECTION OUTPUT ;
    USE SIGNAL ;
    PORT
      LAYER M4 ;
        RECT  104.004 49.68 104.088 49.704 ;
    END
  END b[238]
  PIN b[239]
    DIRECTION OUTPUT ;
    USE SIGNAL ;
    PORT
      LAYER M4 ;
        RECT  104.004 49.776 104.088 49.8 ;
    END
  END b[239]
  PIN b[23]
    DIRECTION OUTPUT ;
    USE SIGNAL ;
    PORT
      LAYER M4 ;
        RECT  104.004 34.416 104.088 34.44 ;
    END
  END b[23]
  PIN b[240]
    DIRECTION OUTPUT ;
    USE SIGNAL ;
    PORT
      LAYER M4 ;
        RECT  104.004 49.872 104.088 49.896 ;
    END
  END b[240]
  PIN b[241]
    DIRECTION OUTPUT ;
    USE SIGNAL ;
    PORT
      LAYER M4 ;
        RECT  104.004 49.968 104.088 49.992 ;
    END
  END b[241]
  PIN b[242]
    DIRECTION OUTPUT ;
    USE SIGNAL ;
    PORT
      LAYER M4 ;
        RECT  104.004 50.064 104.088 50.088 ;
    END
  END b[242]
  PIN b[243]
    DIRECTION OUTPUT ;
    USE SIGNAL ;
    PORT
      LAYER M4 ;
        RECT  104.004 50.16 104.088 50.184 ;
    END
  END b[243]
  PIN b[244]
    DIRECTION OUTPUT ;
    USE SIGNAL ;
    PORT
      LAYER M4 ;
        RECT  104.004 50.256 104.088 50.28 ;
    END
  END b[244]
  PIN b[245]
    DIRECTION OUTPUT ;
    USE SIGNAL ;
    PORT
      LAYER M4 ;
        RECT  104.004 50.352 104.088 50.376 ;
    END
  END b[245]
  PIN b[246]
    DIRECTION OUTPUT ;
    USE SIGNAL ;
    PORT
      LAYER M4 ;
        RECT  104.004 50.448 104.088 50.472 ;
    END
  END b[246]
  PIN b[247]
    DIRECTION OUTPUT ;
    USE SIGNAL ;
    PORT
      LAYER M4 ;
        RECT  104.004 50.544 104.088 50.568 ;
    END
  END b[247]
  PIN b[248]
    DIRECTION OUTPUT ;
    USE SIGNAL ;
    PORT
      LAYER M4 ;
        RECT  104.004 50.64 104.088 50.664 ;
    END
  END b[248]
  PIN b[249]
    DIRECTION OUTPUT ;
    USE SIGNAL ;
    PORT
      LAYER M4 ;
        RECT  104.004 50.736 104.088 50.76 ;
    END
  END b[249]
  PIN b[24]
    DIRECTION OUTPUT ;
    USE SIGNAL ;
    PORT
      LAYER M4 ;
        RECT  104.004 34.512 104.088 34.536 ;
    END
  END b[24]
  PIN b[250]
    DIRECTION OUTPUT ;
    USE SIGNAL ;
    PORT
      LAYER M4 ;
        RECT  104.004 50.832 104.088 50.856 ;
    END
  END b[250]
  PIN b[251]
    DIRECTION OUTPUT ;
    USE SIGNAL ;
    PORT
      LAYER M4 ;
        RECT  104.004 50.928 104.088 50.952 ;
    END
  END b[251]
  PIN b[252]
    DIRECTION OUTPUT ;
    USE SIGNAL ;
    PORT
      LAYER M4 ;
        RECT  104.004 51.024 104.088 51.048 ;
    END
  END b[252]
  PIN b[253]
    DIRECTION OUTPUT ;
    USE SIGNAL ;
    PORT
      LAYER M4 ;
        RECT  104.004 51.12 104.088 51.144 ;
    END
  END b[253]
  PIN b[254]
    DIRECTION OUTPUT ;
    USE SIGNAL ;
    PORT
      LAYER M4 ;
        RECT  104.004 51.216 104.088 51.24 ;
    END
  END b[254]
  PIN b[255]
    DIRECTION OUTPUT ;
    USE SIGNAL ;
    PORT
      LAYER M4 ;
        RECT  104.004 51.312 104.088 51.336 ;
    END
  END b[255]
  PIN b[256]
    DIRECTION OUTPUT ;
    USE SIGNAL ;
    PORT
      LAYER M4 ;
        RECT  104.004 61.392 104.088 61.416 ;
    END
  END b[256]
  PIN b[257]
    DIRECTION OUTPUT ;
    USE SIGNAL ;
    PORT
      LAYER M4 ;
        RECT  104.004 61.488 104.088 61.512 ;
    END
  END b[257]
  PIN b[258]
    DIRECTION OUTPUT ;
    USE SIGNAL ;
    PORT
      LAYER M4 ;
        RECT  104.004 61.584 104.088 61.608 ;
    END
  END b[258]
  PIN b[259]
    DIRECTION OUTPUT ;
    USE SIGNAL ;
    PORT
      LAYER M4 ;
        RECT  104.004 61.68 104.088 61.704 ;
    END
  END b[259]
  PIN b[25]
    DIRECTION OUTPUT ;
    USE SIGNAL ;
    PORT
      LAYER M4 ;
        RECT  104.004 34.608 104.088 34.632 ;
    END
  END b[25]
  PIN b[260]
    DIRECTION OUTPUT ;
    USE SIGNAL ;
    PORT
      LAYER M4 ;
        RECT  104.004 61.776 104.088 61.8 ;
    END
  END b[260]
  PIN b[261]
    DIRECTION OUTPUT ;
    USE SIGNAL ;
    PORT
      LAYER M4 ;
        RECT  104.004 61.872 104.088 61.896 ;
    END
  END b[261]
  PIN b[262]
    DIRECTION OUTPUT ;
    USE SIGNAL ;
    PORT
      LAYER M4 ;
        RECT  104.004 61.968 104.088 61.992 ;
    END
  END b[262]
  PIN b[263]
    DIRECTION OUTPUT ;
    USE SIGNAL ;
    PORT
      LAYER M4 ;
        RECT  104.004 62.064 104.088 62.088 ;
    END
  END b[263]
  PIN b[264]
    DIRECTION OUTPUT ;
    USE SIGNAL ;
    PORT
      LAYER M4 ;
        RECT  104.004 62.16 104.088 62.184 ;
    END
  END b[264]
  PIN b[265]
    DIRECTION OUTPUT ;
    USE SIGNAL ;
    PORT
      LAYER M4 ;
        RECT  104.004 62.256 104.088 62.28 ;
    END
  END b[265]
  PIN b[266]
    DIRECTION OUTPUT ;
    USE SIGNAL ;
    PORT
      LAYER M4 ;
        RECT  104.004 62.352 104.088 62.376 ;
    END
  END b[266]
  PIN b[267]
    DIRECTION OUTPUT ;
    USE SIGNAL ;
    PORT
      LAYER M4 ;
        RECT  104.004 62.448 104.088 62.472 ;
    END
  END b[267]
  PIN b[268]
    DIRECTION OUTPUT ;
    USE SIGNAL ;
    PORT
      LAYER M4 ;
        RECT  104.004 62.544 104.088 62.568 ;
    END
  END b[268]
  PIN b[269]
    DIRECTION OUTPUT ;
    USE SIGNAL ;
    PORT
      LAYER M4 ;
        RECT  104.004 62.64 104.088 62.664 ;
    END
  END b[269]
  PIN b[26]
    DIRECTION OUTPUT ;
    USE SIGNAL ;
    PORT
      LAYER M4 ;
        RECT  104.004 34.704 104.088 34.728 ;
    END
  END b[26]
  PIN b[270]
    DIRECTION OUTPUT ;
    USE SIGNAL ;
    PORT
      LAYER M4 ;
        RECT  104.004 62.736 104.088 62.76 ;
    END
  END b[270]
  PIN b[271]
    DIRECTION OUTPUT ;
    USE SIGNAL ;
    PORT
      LAYER M4 ;
        RECT  104.004 62.832 104.088 62.856 ;
    END
  END b[271]
  PIN b[272]
    DIRECTION OUTPUT ;
    USE SIGNAL ;
    PORT
      LAYER M4 ;
        RECT  104.004 62.928 104.088 62.952 ;
    END
  END b[272]
  PIN b[273]
    DIRECTION OUTPUT ;
    USE SIGNAL ;
    PORT
      LAYER M4 ;
        RECT  104.004 63.024 104.088 63.048 ;
    END
  END b[273]
  PIN b[274]
    DIRECTION OUTPUT ;
    USE SIGNAL ;
    PORT
      LAYER M4 ;
        RECT  104.004 63.12 104.088 63.144 ;
    END
  END b[274]
  PIN b[275]
    DIRECTION OUTPUT ;
    USE SIGNAL ;
    PORT
      LAYER M4 ;
        RECT  104.004 63.216 104.088 63.24 ;
    END
  END b[275]
  PIN b[276]
    DIRECTION OUTPUT ;
    USE SIGNAL ;
    PORT
      LAYER M4 ;
        RECT  104.004 63.312 104.088 63.336 ;
    END
  END b[276]
  PIN b[277]
    DIRECTION OUTPUT ;
    USE SIGNAL ;
    PORT
      LAYER M4 ;
        RECT  104.004 63.408 104.088 63.432 ;
    END
  END b[277]
  PIN b[278]
    DIRECTION OUTPUT ;
    USE SIGNAL ;
    PORT
      LAYER M4 ;
        RECT  104.004 63.504 104.088 63.528 ;
    END
  END b[278]
  PIN b[279]
    DIRECTION OUTPUT ;
    USE SIGNAL ;
    PORT
      LAYER M4 ;
        RECT  104.004 63.6 104.088 63.624 ;
    END
  END b[279]
  PIN b[27]
    DIRECTION OUTPUT ;
    USE SIGNAL ;
    PORT
      LAYER M4 ;
        RECT  104.004 34.8 104.088 34.824 ;
    END
  END b[27]
  PIN b[280]
    DIRECTION OUTPUT ;
    USE SIGNAL ;
    PORT
      LAYER M4 ;
        RECT  104.004 63.696 104.088 63.72 ;
    END
  END b[280]
  PIN b[281]
    DIRECTION OUTPUT ;
    USE SIGNAL ;
    PORT
      LAYER M4 ;
        RECT  104.004 63.792 104.088 63.816 ;
    END
  END b[281]
  PIN b[282]
    DIRECTION OUTPUT ;
    USE SIGNAL ;
    PORT
      LAYER M4 ;
        RECT  104.004 63.888 104.088 63.912 ;
    END
  END b[282]
  PIN b[283]
    DIRECTION OUTPUT ;
    USE SIGNAL ;
    PORT
      LAYER M4 ;
        RECT  104.004 63.984 104.088 64.008 ;
    END
  END b[283]
  PIN b[284]
    DIRECTION OUTPUT ;
    USE SIGNAL ;
    PORT
      LAYER M4 ;
        RECT  104.004 64.08 104.088 64.104 ;
    END
  END b[284]
  PIN b[285]
    DIRECTION OUTPUT ;
    USE SIGNAL ;
    PORT
      LAYER M4 ;
        RECT  104.004 64.176 104.088 64.2 ;
    END
  END b[285]
  PIN b[286]
    DIRECTION OUTPUT ;
    USE SIGNAL ;
    PORT
      LAYER M4 ;
        RECT  104.004 64.272 104.088 64.296 ;
    END
  END b[286]
  PIN b[287]
    DIRECTION OUTPUT ;
    USE SIGNAL ;
    PORT
      LAYER M4 ;
        RECT  104.004 64.368 104.088 64.392 ;
    END
  END b[287]
  PIN b[288]
    DIRECTION OUTPUT ;
    USE SIGNAL ;
    PORT
      LAYER M4 ;
        RECT  104.004 64.464 104.088 64.488 ;
    END
  END b[288]
  PIN b[289]
    DIRECTION OUTPUT ;
    USE SIGNAL ;
    PORT
      LAYER M4 ;
        RECT  104.004 64.56 104.088 64.584 ;
    END
  END b[289]
  PIN b[28]
    DIRECTION OUTPUT ;
    USE SIGNAL ;
    PORT
      LAYER M4 ;
        RECT  104.004 34.896 104.088 34.92 ;
    END
  END b[28]
  PIN b[290]
    DIRECTION OUTPUT ;
    USE SIGNAL ;
    PORT
      LAYER M4 ;
        RECT  104.004 64.656 104.088 64.68 ;
    END
  END b[290]
  PIN b[291]
    DIRECTION OUTPUT ;
    USE SIGNAL ;
    PORT
      LAYER M4 ;
        RECT  104.004 64.752 104.088 64.776 ;
    END
  END b[291]
  PIN b[292]
    DIRECTION OUTPUT ;
    USE SIGNAL ;
    PORT
      LAYER M4 ;
        RECT  104.004 64.848 104.088 64.872 ;
    END
  END b[292]
  PIN b[293]
    DIRECTION OUTPUT ;
    USE SIGNAL ;
    PORT
      LAYER M4 ;
        RECT  104.004 64.944 104.088 64.968 ;
    END
  END b[293]
  PIN b[294]
    DIRECTION OUTPUT ;
    USE SIGNAL ;
    PORT
      LAYER M4 ;
        RECT  104.004 65.04 104.088 65.064 ;
    END
  END b[294]
  PIN b[295]
    DIRECTION OUTPUT ;
    USE SIGNAL ;
    PORT
      LAYER M4 ;
        RECT  104.004 65.136 104.088 65.16 ;
    END
  END b[295]
  PIN b[296]
    DIRECTION OUTPUT ;
    USE SIGNAL ;
    PORT
      LAYER M4 ;
        RECT  104.004 65.232 104.088 65.256 ;
    END
  END b[296]
  PIN b[297]
    DIRECTION OUTPUT ;
    USE SIGNAL ;
    PORT
      LAYER M4 ;
        RECT  104.004 65.328 104.088 65.352 ;
    END
  END b[297]
  PIN b[298]
    DIRECTION OUTPUT ;
    USE SIGNAL ;
    PORT
      LAYER M4 ;
        RECT  104.004 65.424 104.088 65.448 ;
    END
  END b[298]
  PIN b[299]
    DIRECTION OUTPUT ;
    USE SIGNAL ;
    PORT
      LAYER M4 ;
        RECT  104.004 65.52 104.088 65.544 ;
    END
  END b[299]
  PIN b[29]
    DIRECTION OUTPUT ;
    USE SIGNAL ;
    PORT
      LAYER M4 ;
        RECT  104.004 34.992 104.088 35.016 ;
    END
  END b[29]
  PIN b[2]
    DIRECTION OUTPUT ;
    USE SIGNAL ;
    PORT
      LAYER M4 ;
        RECT  104.004 32.4 104.088 32.424 ;
    END
  END b[2]
  PIN b[300]
    DIRECTION OUTPUT ;
    USE SIGNAL ;
    PORT
      LAYER M4 ;
        RECT  104.004 65.616 104.088 65.64 ;
    END
  END b[300]
  PIN b[301]
    DIRECTION OUTPUT ;
    USE SIGNAL ;
    PORT
      LAYER M4 ;
        RECT  104.004 65.712 104.088 65.736 ;
    END
  END b[301]
  PIN b[302]
    DIRECTION OUTPUT ;
    USE SIGNAL ;
    PORT
      LAYER M4 ;
        RECT  104.004 65.808 104.088 65.832 ;
    END
  END b[302]
  PIN b[303]
    DIRECTION OUTPUT ;
    USE SIGNAL ;
    PORT
      LAYER M4 ;
        RECT  104.004 65.904 104.088 65.928 ;
    END
  END b[303]
  PIN b[304]
    DIRECTION OUTPUT ;
    USE SIGNAL ;
    PORT
      LAYER M4 ;
        RECT  104.004 66 104.088 66.024 ;
    END
  END b[304]
  PIN b[305]
    DIRECTION OUTPUT ;
    USE SIGNAL ;
    PORT
      LAYER M4 ;
        RECT  104.004 66.096 104.088 66.12 ;
    END
  END b[305]
  PIN b[306]
    DIRECTION OUTPUT ;
    USE SIGNAL ;
    PORT
      LAYER M4 ;
        RECT  104.004 66.192 104.088 66.216 ;
    END
  END b[306]
  PIN b[307]
    DIRECTION OUTPUT ;
    USE SIGNAL ;
    PORT
      LAYER M4 ;
        RECT  104.004 66.288 104.088 66.312 ;
    END
  END b[307]
  PIN b[308]
    DIRECTION OUTPUT ;
    USE SIGNAL ;
    PORT
      LAYER M4 ;
        RECT  104.004 66.384 104.088 66.408 ;
    END
  END b[308]
  PIN b[309]
    DIRECTION OUTPUT ;
    USE SIGNAL ;
    PORT
      LAYER M4 ;
        RECT  104.004 66.48 104.088 66.504 ;
    END
  END b[309]
  PIN b[30]
    DIRECTION OUTPUT ;
    USE SIGNAL ;
    PORT
      LAYER M4 ;
        RECT  104.004 35.088 104.088 35.112 ;
    END
  END b[30]
  PIN b[310]
    DIRECTION OUTPUT ;
    USE SIGNAL ;
    PORT
      LAYER M4 ;
        RECT  104.004 66.576 104.088 66.6 ;
    END
  END b[310]
  PIN b[311]
    DIRECTION OUTPUT ;
    USE SIGNAL ;
    PORT
      LAYER M4 ;
        RECT  104.004 66.672 104.088 66.696 ;
    END
  END b[311]
  PIN b[312]
    DIRECTION OUTPUT ;
    USE SIGNAL ;
    PORT
      LAYER M4 ;
        RECT  104.004 66.768 104.088 66.792 ;
    END
  END b[312]
  PIN b[313]
    DIRECTION OUTPUT ;
    USE SIGNAL ;
    PORT
      LAYER M4 ;
        RECT  104.004 66.864 104.088 66.888 ;
    END
  END b[313]
  PIN b[314]
    DIRECTION OUTPUT ;
    USE SIGNAL ;
    PORT
      LAYER M4 ;
        RECT  104.004 66.96 104.088 66.984 ;
    END
  END b[314]
  PIN b[315]
    DIRECTION OUTPUT ;
    USE SIGNAL ;
    PORT
      LAYER M4 ;
        RECT  104.004 67.056 104.088 67.08 ;
    END
  END b[315]
  PIN b[316]
    DIRECTION OUTPUT ;
    USE SIGNAL ;
    PORT
      LAYER M4 ;
        RECT  104.004 67.152 104.088 67.176 ;
    END
  END b[316]
  PIN b[317]
    DIRECTION OUTPUT ;
    USE SIGNAL ;
    PORT
      LAYER M4 ;
        RECT  104.004 67.248 104.088 67.272 ;
    END
  END b[317]
  PIN b[318]
    DIRECTION OUTPUT ;
    USE SIGNAL ;
    PORT
      LAYER M4 ;
        RECT  104.004 67.344 104.088 67.368 ;
    END
  END b[318]
  PIN b[319]
    DIRECTION OUTPUT ;
    USE SIGNAL ;
    PORT
      LAYER M4 ;
        RECT  104.004 67.44 104.088 67.464 ;
    END
  END b[319]
  PIN b[31]
    DIRECTION OUTPUT ;
    USE SIGNAL ;
    PORT
      LAYER M4 ;
        RECT  104.004 35.184 104.088 35.208 ;
    END
  END b[31]
  PIN b[320]
    DIRECTION OUTPUT ;
    USE SIGNAL ;
    PORT
      LAYER M4 ;
        RECT  104.004 67.536 104.088 67.56 ;
    END
  END b[320]
  PIN b[321]
    DIRECTION OUTPUT ;
    USE SIGNAL ;
    PORT
      LAYER M4 ;
        RECT  104.004 67.632 104.088 67.656 ;
    END
  END b[321]
  PIN b[322]
    DIRECTION OUTPUT ;
    USE SIGNAL ;
    PORT
      LAYER M4 ;
        RECT  104.004 67.728 104.088 67.752 ;
    END
  END b[322]
  PIN b[323]
    DIRECTION OUTPUT ;
    USE SIGNAL ;
    PORT
      LAYER M4 ;
        RECT  104.004 67.824 104.088 67.848 ;
    END
  END b[323]
  PIN b[324]
    DIRECTION OUTPUT ;
    USE SIGNAL ;
    PORT
      LAYER M4 ;
        RECT  104.004 67.92 104.088 67.944 ;
    END
  END b[324]
  PIN b[325]
    DIRECTION OUTPUT ;
    USE SIGNAL ;
    PORT
      LAYER M4 ;
        RECT  104.004 68.016 104.088 68.04 ;
    END
  END b[325]
  PIN b[326]
    DIRECTION OUTPUT ;
    USE SIGNAL ;
    PORT
      LAYER M4 ;
        RECT  104.004 68.112 104.088 68.136 ;
    END
  END b[326]
  PIN b[327]
    DIRECTION OUTPUT ;
    USE SIGNAL ;
    PORT
      LAYER M4 ;
        RECT  104.004 68.208 104.088 68.232 ;
    END
  END b[327]
  PIN b[328]
    DIRECTION OUTPUT ;
    USE SIGNAL ;
    PORT
      LAYER M4 ;
        RECT  104.004 68.304 104.088 68.328 ;
    END
  END b[328]
  PIN b[329]
    DIRECTION OUTPUT ;
    USE SIGNAL ;
    PORT
      LAYER M4 ;
        RECT  104.004 68.4 104.088 68.424 ;
    END
  END b[329]
  PIN b[32]
    DIRECTION OUTPUT ;
    USE SIGNAL ;
    PORT
      LAYER M4 ;
        RECT  104.004 29.136 104.088 29.16 ;
    END
  END b[32]
  PIN b[330]
    DIRECTION OUTPUT ;
    USE SIGNAL ;
    PORT
      LAYER M4 ;
        RECT  104.004 68.496 104.088 68.52 ;
    END
  END b[330]
  PIN b[331]
    DIRECTION OUTPUT ;
    USE SIGNAL ;
    PORT
      LAYER M4 ;
        RECT  104.004 68.592 104.088 68.616 ;
    END
  END b[331]
  PIN b[332]
    DIRECTION OUTPUT ;
    USE SIGNAL ;
    PORT
      LAYER M4 ;
        RECT  104.004 68.688 104.088 68.712 ;
    END
  END b[332]
  PIN b[333]
    DIRECTION OUTPUT ;
    USE SIGNAL ;
    PORT
      LAYER M4 ;
        RECT  104.004 68.784 104.088 68.808 ;
    END
  END b[333]
  PIN b[334]
    DIRECTION OUTPUT ;
    USE SIGNAL ;
    PORT
      LAYER M4 ;
        RECT  104.004 68.88 104.088 68.904 ;
    END
  END b[334]
  PIN b[335]
    DIRECTION OUTPUT ;
    USE SIGNAL ;
    PORT
      LAYER M4 ;
        RECT  104.004 68.976 104.088 69 ;
    END
  END b[335]
  PIN b[336]
    DIRECTION OUTPUT ;
    USE SIGNAL ;
    PORT
      LAYER M4 ;
        RECT  104.004 69.072 104.088 69.096 ;
    END
  END b[336]
  PIN b[337]
    DIRECTION OUTPUT ;
    USE SIGNAL ;
    PORT
      LAYER M4 ;
        RECT  104.004 69.168 104.088 69.192 ;
    END
  END b[337]
  PIN b[338]
    DIRECTION OUTPUT ;
    USE SIGNAL ;
    PORT
      LAYER M4 ;
        RECT  104.004 69.264 104.088 69.288 ;
    END
  END b[338]
  PIN b[339]
    DIRECTION OUTPUT ;
    USE SIGNAL ;
    PORT
      LAYER M4 ;
        RECT  104.004 69.36 104.088 69.384 ;
    END
  END b[339]
  PIN b[33]
    DIRECTION OUTPUT ;
    USE SIGNAL ;
    PORT
      LAYER M4 ;
        RECT  104.004 29.232 104.088 29.256 ;
    END
  END b[33]
  PIN b[340]
    DIRECTION OUTPUT ;
    USE SIGNAL ;
    PORT
      LAYER M4 ;
        RECT  104.004 69.456 104.088 69.48 ;
    END
  END b[340]
  PIN b[341]
    DIRECTION OUTPUT ;
    USE SIGNAL ;
    PORT
      LAYER M4 ;
        RECT  104.004 69.552 104.088 69.576 ;
    END
  END b[341]
  PIN b[342]
    DIRECTION OUTPUT ;
    USE SIGNAL ;
    PORT
      LAYER M4 ;
        RECT  104.004 69.648 104.088 69.672 ;
    END
  END b[342]
  PIN b[343]
    DIRECTION OUTPUT ;
    USE SIGNAL ;
    PORT
      LAYER M4 ;
        RECT  104.004 69.744 104.088 69.768 ;
    END
  END b[343]
  PIN b[344]
    DIRECTION OUTPUT ;
    USE SIGNAL ;
    PORT
      LAYER M4 ;
        RECT  104.004 69.84 104.088 69.864 ;
    END
  END b[344]
  PIN b[345]
    DIRECTION OUTPUT ;
    USE SIGNAL ;
    PORT
      LAYER M4 ;
        RECT  104.004 69.936 104.088 69.96 ;
    END
  END b[345]
  PIN b[346]
    DIRECTION OUTPUT ;
    USE SIGNAL ;
    PORT
      LAYER M4 ;
        RECT  104.004 70.032 104.088 70.056 ;
    END
  END b[346]
  PIN b[347]
    DIRECTION OUTPUT ;
    USE SIGNAL ;
    PORT
      LAYER M4 ;
        RECT  104.004 70.128 104.088 70.152 ;
    END
  END b[347]
  PIN b[348]
    DIRECTION OUTPUT ;
    USE SIGNAL ;
    PORT
      LAYER M4 ;
        RECT  104.004 70.224 104.088 70.248 ;
    END
  END b[348]
  PIN b[349]
    DIRECTION OUTPUT ;
    USE SIGNAL ;
    PORT
      LAYER M4 ;
        RECT  104.004 70.32 104.088 70.344 ;
    END
  END b[349]
  PIN b[34]
    DIRECTION OUTPUT ;
    USE SIGNAL ;
    PORT
      LAYER M4 ;
        RECT  104.004 29.328 104.088 29.352 ;
    END
  END b[34]
  PIN b[350]
    DIRECTION OUTPUT ;
    USE SIGNAL ;
    PORT
      LAYER M4 ;
        RECT  104.004 70.416 104.088 70.44 ;
    END
  END b[350]
  PIN b[351]
    DIRECTION OUTPUT ;
    USE SIGNAL ;
    PORT
      LAYER M4 ;
        RECT  104.004 70.512 104.088 70.536 ;
    END
  END b[351]
  PIN b[352]
    DIRECTION OUTPUT ;
    USE SIGNAL ;
    PORT
      LAYER M4 ;
        RECT  104.004 77.52 104.088 77.544 ;
    END
  END b[352]
  PIN b[353]
    DIRECTION OUTPUT ;
    USE SIGNAL ;
    PORT
      LAYER M4 ;
        RECT  104.004 77.616 104.088 77.64 ;
    END
  END b[353]
  PIN b[354]
    DIRECTION OUTPUT ;
    USE SIGNAL ;
    PORT
      LAYER M4 ;
        RECT  104.004 77.712 104.088 77.736 ;
    END
  END b[354]
  PIN b[355]
    DIRECTION OUTPUT ;
    USE SIGNAL ;
    PORT
      LAYER M4 ;
        RECT  104.004 77.808 104.088 77.832 ;
    END
  END b[355]
  PIN b[356]
    DIRECTION OUTPUT ;
    USE SIGNAL ;
    PORT
      LAYER M4 ;
        RECT  104.004 77.904 104.088 77.928 ;
    END
  END b[356]
  PIN b[357]
    DIRECTION OUTPUT ;
    USE SIGNAL ;
    PORT
      LAYER M4 ;
        RECT  104.004 78 104.088 78.024 ;
    END
  END b[357]
  PIN b[358]
    DIRECTION OUTPUT ;
    USE SIGNAL ;
    PORT
      LAYER M4 ;
        RECT  104.004 78.096 104.088 78.12 ;
    END
  END b[358]
  PIN b[359]
    DIRECTION OUTPUT ;
    USE SIGNAL ;
    PORT
      LAYER M4 ;
        RECT  104.004 78.192 104.088 78.216 ;
    END
  END b[359]
  PIN b[35]
    DIRECTION OUTPUT ;
    USE SIGNAL ;
    PORT
      LAYER M4 ;
        RECT  104.004 29.424 104.088 29.448 ;
    END
  END b[35]
  PIN b[360]
    DIRECTION OUTPUT ;
    USE SIGNAL ;
    PORT
      LAYER M4 ;
        RECT  104.004 78.288 104.088 78.312 ;
    END
  END b[360]
  PIN b[361]
    DIRECTION OUTPUT ;
    USE SIGNAL ;
    PORT
      LAYER M4 ;
        RECT  104.004 78.384 104.088 78.408 ;
    END
  END b[361]
  PIN b[362]
    DIRECTION OUTPUT ;
    USE SIGNAL ;
    PORT
      LAYER M4 ;
        RECT  104.004 78.48 104.088 78.504 ;
    END
  END b[362]
  PIN b[363]
    DIRECTION OUTPUT ;
    USE SIGNAL ;
    PORT
      LAYER M4 ;
        RECT  104.004 78.576 104.088 78.6 ;
    END
  END b[363]
  PIN b[364]
    DIRECTION OUTPUT ;
    USE SIGNAL ;
    PORT
      LAYER M4 ;
        RECT  104.004 78.672 104.088 78.696 ;
    END
  END b[364]
  PIN b[365]
    DIRECTION OUTPUT ;
    USE SIGNAL ;
    PORT
      LAYER M4 ;
        RECT  104.004 78.768 104.088 78.792 ;
    END
  END b[365]
  PIN b[366]
    DIRECTION OUTPUT ;
    USE SIGNAL ;
    PORT
      LAYER M4 ;
        RECT  104.004 78.864 104.088 78.888 ;
    END
  END b[366]
  PIN b[367]
    DIRECTION OUTPUT ;
    USE SIGNAL ;
    PORT
      LAYER M4 ;
        RECT  104.004 78.96 104.088 78.984 ;
    END
  END b[367]
  PIN b[368]
    DIRECTION OUTPUT ;
    USE SIGNAL ;
    PORT
      LAYER M4 ;
        RECT  104.004 79.056 104.088 79.08 ;
    END
  END b[368]
  PIN b[369]
    DIRECTION OUTPUT ;
    USE SIGNAL ;
    PORT
      LAYER M4 ;
        RECT  104.004 79.152 104.088 79.176 ;
    END
  END b[369]
  PIN b[36]
    DIRECTION OUTPUT ;
    USE SIGNAL ;
    PORT
      LAYER M4 ;
        RECT  104.004 29.52 104.088 29.544 ;
    END
  END b[36]
  PIN b[370]
    DIRECTION OUTPUT ;
    USE SIGNAL ;
    PORT
      LAYER M4 ;
        RECT  104.004 79.248 104.088 79.272 ;
    END
  END b[370]
  PIN b[371]
    DIRECTION OUTPUT ;
    USE SIGNAL ;
    PORT
      LAYER M4 ;
        RECT  104.004 79.344 104.088 79.368 ;
    END
  END b[371]
  PIN b[372]
    DIRECTION OUTPUT ;
    USE SIGNAL ;
    PORT
      LAYER M4 ;
        RECT  104.004 79.44 104.088 79.464 ;
    END
  END b[372]
  PIN b[373]
    DIRECTION OUTPUT ;
    USE SIGNAL ;
    PORT
      LAYER M4 ;
        RECT  104.004 79.536 104.088 79.56 ;
    END
  END b[373]
  PIN b[374]
    DIRECTION OUTPUT ;
    USE SIGNAL ;
    PORT
      LAYER M4 ;
        RECT  104.004 79.632 104.088 79.656 ;
    END
  END b[374]
  PIN b[375]
    DIRECTION OUTPUT ;
    USE SIGNAL ;
    PORT
      LAYER M4 ;
        RECT  104.004 79.728 104.088 79.752 ;
    END
  END b[375]
  PIN b[376]
    DIRECTION OUTPUT ;
    USE SIGNAL ;
    PORT
      LAYER M4 ;
        RECT  104.004 79.824 104.088 79.848 ;
    END
  END b[376]
  PIN b[377]
    DIRECTION OUTPUT ;
    USE SIGNAL ;
    PORT
      LAYER M4 ;
        RECT  104.004 79.92 104.088 79.944 ;
    END
  END b[377]
  PIN b[378]
    DIRECTION OUTPUT ;
    USE SIGNAL ;
    PORT
      LAYER M4 ;
        RECT  104.004 80.016 104.088 80.04 ;
    END
  END b[378]
  PIN b[379]
    DIRECTION OUTPUT ;
    USE SIGNAL ;
    PORT
      LAYER M4 ;
        RECT  104.004 80.112 104.088 80.136 ;
    END
  END b[379]
  PIN b[37]
    DIRECTION OUTPUT ;
    USE SIGNAL ;
    PORT
      LAYER M4 ;
        RECT  104.004 29.616 104.088 29.64 ;
    END
  END b[37]
  PIN b[380]
    DIRECTION OUTPUT ;
    USE SIGNAL ;
    PORT
      LAYER M4 ;
        RECT  104.004 80.208 104.088 80.232 ;
    END
  END b[380]
  PIN b[381]
    DIRECTION OUTPUT ;
    USE SIGNAL ;
    PORT
      LAYER M4 ;
        RECT  104.004 80.304 104.088 80.328 ;
    END
  END b[381]
  PIN b[382]
    DIRECTION OUTPUT ;
    USE SIGNAL ;
    PORT
      LAYER M4 ;
        RECT  104.004 80.4 104.088 80.424 ;
    END
  END b[382]
  PIN b[383]
    DIRECTION OUTPUT ;
    USE SIGNAL ;
    PORT
      LAYER M4 ;
        RECT  104.004 80.496 104.088 80.52 ;
    END
  END b[383]
  PIN b[384]
    DIRECTION OUTPUT ;
    USE SIGNAL ;
    PORT
      LAYER M4 ;
        RECT  104.004 86.736 104.088 86.76 ;
    END
  END b[384]
  PIN b[385]
    DIRECTION OUTPUT ;
    USE SIGNAL ;
    PORT
      LAYER M4 ;
        RECT  104.004 86.832 104.088 86.856 ;
    END
  END b[385]
  PIN b[386]
    DIRECTION OUTPUT ;
    USE SIGNAL ;
    PORT
      LAYER M4 ;
        RECT  104.004 86.928 104.088 86.952 ;
    END
  END b[386]
  PIN b[387]
    DIRECTION OUTPUT ;
    USE SIGNAL ;
    PORT
      LAYER M4 ;
        RECT  104.004 87.024 104.088 87.048 ;
    END
  END b[387]
  PIN b[388]
    DIRECTION OUTPUT ;
    USE SIGNAL ;
    PORT
      LAYER M4 ;
        RECT  104.004 87.12 104.088 87.144 ;
    END
  END b[388]
  PIN b[389]
    DIRECTION OUTPUT ;
    USE SIGNAL ;
    PORT
      LAYER M4 ;
        RECT  104.004 87.216 104.088 87.24 ;
    END
  END b[389]
  PIN b[38]
    DIRECTION OUTPUT ;
    USE SIGNAL ;
    PORT
      LAYER M4 ;
        RECT  104.004 29.712 104.088 29.736 ;
    END
  END b[38]
  PIN b[390]
    DIRECTION OUTPUT ;
    USE SIGNAL ;
    PORT
      LAYER M4 ;
        RECT  104.004 87.312 104.088 87.336 ;
    END
  END b[390]
  PIN b[391]
    DIRECTION OUTPUT ;
    USE SIGNAL ;
    PORT
      LAYER M4 ;
        RECT  104.004 87.408 104.088 87.432 ;
    END
  END b[391]
  PIN b[392]
    DIRECTION OUTPUT ;
    USE SIGNAL ;
    PORT
      LAYER M4 ;
        RECT  104.004 87.504 104.088 87.528 ;
    END
  END b[392]
  PIN b[393]
    DIRECTION OUTPUT ;
    USE SIGNAL ;
    PORT
      LAYER M4 ;
        RECT  104.004 87.6 104.088 87.624 ;
    END
  END b[393]
  PIN b[394]
    DIRECTION OUTPUT ;
    USE SIGNAL ;
    PORT
      LAYER M4 ;
        RECT  104.004 87.696 104.088 87.72 ;
    END
  END b[394]
  PIN b[395]
    DIRECTION OUTPUT ;
    USE SIGNAL ;
    PORT
      LAYER M4 ;
        RECT  104.004 87.792 104.088 87.816 ;
    END
  END b[395]
  PIN b[396]
    DIRECTION OUTPUT ;
    USE SIGNAL ;
    PORT
      LAYER M4 ;
        RECT  104.004 87.888 104.088 87.912 ;
    END
  END b[396]
  PIN b[397]
    DIRECTION OUTPUT ;
    USE SIGNAL ;
    PORT
      LAYER M4 ;
        RECT  104.004 87.984 104.088 88.008 ;
    END
  END b[397]
  PIN b[398]
    DIRECTION OUTPUT ;
    USE SIGNAL ;
    PORT
      LAYER M4 ;
        RECT  104.004 88.08 104.088 88.104 ;
    END
  END b[398]
  PIN b[399]
    DIRECTION OUTPUT ;
    USE SIGNAL ;
    PORT
      LAYER M4 ;
        RECT  104.004 88.176 104.088 88.2 ;
    END
  END b[399]
  PIN b[39]
    DIRECTION OUTPUT ;
    USE SIGNAL ;
    PORT
      LAYER M4 ;
        RECT  104.004 29.808 104.088 29.832 ;
    END
  END b[39]
  PIN b[3]
    DIRECTION OUTPUT ;
    USE SIGNAL ;
    PORT
      LAYER M4 ;
        RECT  104.004 32.496 104.088 32.52 ;
    END
  END b[3]
  PIN b[400]
    DIRECTION OUTPUT ;
    USE SIGNAL ;
    PORT
      LAYER M4 ;
        RECT  104.004 88.272 104.088 88.296 ;
    END
  END b[400]
  PIN b[401]
    DIRECTION OUTPUT ;
    USE SIGNAL ;
    PORT
      LAYER M4 ;
        RECT  104.004 88.368 104.088 88.392 ;
    END
  END b[401]
  PIN b[402]
    DIRECTION OUTPUT ;
    USE SIGNAL ;
    PORT
      LAYER M4 ;
        RECT  104.004 88.464 104.088 88.488 ;
    END
  END b[402]
  PIN b[403]
    DIRECTION OUTPUT ;
    USE SIGNAL ;
    PORT
      LAYER M4 ;
        RECT  104.004 88.56 104.088 88.584 ;
    END
  END b[403]
  PIN b[404]
    DIRECTION OUTPUT ;
    USE SIGNAL ;
    PORT
      LAYER M4 ;
        RECT  104.004 88.656 104.088 88.68 ;
    END
  END b[404]
  PIN b[405]
    DIRECTION OUTPUT ;
    USE SIGNAL ;
    PORT
      LAYER M4 ;
        RECT  104.004 88.752 104.088 88.776 ;
    END
  END b[405]
  PIN b[406]
    DIRECTION OUTPUT ;
    USE SIGNAL ;
    PORT
      LAYER M4 ;
        RECT  104.004 88.848 104.088 88.872 ;
    END
  END b[406]
  PIN b[407]
    DIRECTION OUTPUT ;
    USE SIGNAL ;
    PORT
      LAYER M4 ;
        RECT  104.004 88.944 104.088 88.968 ;
    END
  END b[407]
  PIN b[408]
    DIRECTION OUTPUT ;
    USE SIGNAL ;
    PORT
      LAYER M4 ;
        RECT  104.004 89.04 104.088 89.064 ;
    END
  END b[408]
  PIN b[409]
    DIRECTION OUTPUT ;
    USE SIGNAL ;
    PORT
      LAYER M4 ;
        RECT  104.004 89.136 104.088 89.16 ;
    END
  END b[409]
  PIN b[40]
    DIRECTION OUTPUT ;
    USE SIGNAL ;
    PORT
      LAYER M4 ;
        RECT  104.004 29.904 104.088 29.928 ;
    END
  END b[40]
  PIN b[410]
    DIRECTION OUTPUT ;
    USE SIGNAL ;
    PORT
      LAYER M4 ;
        RECT  104.004 89.232 104.088 89.256 ;
    END
  END b[410]
  PIN b[411]
    DIRECTION OUTPUT ;
    USE SIGNAL ;
    PORT
      LAYER M4 ;
        RECT  104.004 89.328 104.088 89.352 ;
    END
  END b[411]
  PIN b[412]
    DIRECTION OUTPUT ;
    USE SIGNAL ;
    PORT
      LAYER M4 ;
        RECT  104.004 89.424 104.088 89.448 ;
    END
  END b[412]
  PIN b[413]
    DIRECTION OUTPUT ;
    USE SIGNAL ;
    PORT
      LAYER M4 ;
        RECT  104.004 89.52 104.088 89.544 ;
    END
  END b[413]
  PIN b[414]
    DIRECTION OUTPUT ;
    USE SIGNAL ;
    PORT
      LAYER M4 ;
        RECT  104.004 89.616 104.088 89.64 ;
    END
  END b[414]
  PIN b[415]
    DIRECTION OUTPUT ;
    USE SIGNAL ;
    PORT
      LAYER M4 ;
        RECT  104.004 89.712 104.088 89.736 ;
    END
  END b[415]
  PIN b[416]
    DIRECTION OUTPUT ;
    USE SIGNAL ;
    PORT
      LAYER M4 ;
        RECT  104.004 80.592 104.088 80.616 ;
    END
  END b[416]
  PIN b[417]
    DIRECTION OUTPUT ;
    USE SIGNAL ;
    PORT
      LAYER M4 ;
        RECT  104.004 80.688 104.088 80.712 ;
    END
  END b[417]
  PIN b[418]
    DIRECTION OUTPUT ;
    USE SIGNAL ;
    PORT
      LAYER M4 ;
        RECT  104.004 80.784 104.088 80.808 ;
    END
  END b[418]
  PIN b[419]
    DIRECTION OUTPUT ;
    USE SIGNAL ;
    PORT
      LAYER M4 ;
        RECT  104.004 80.88 104.088 80.904 ;
    END
  END b[419]
  PIN b[41]
    DIRECTION OUTPUT ;
    USE SIGNAL ;
    PORT
      LAYER M4 ;
        RECT  104.004 30 104.088 30.024 ;
    END
  END b[41]
  PIN b[420]
    DIRECTION OUTPUT ;
    USE SIGNAL ;
    PORT
      LAYER M4 ;
        RECT  104.004 80.976 104.088 81 ;
    END
  END b[420]
  PIN b[421]
    DIRECTION OUTPUT ;
    USE SIGNAL ;
    PORT
      LAYER M4 ;
        RECT  104.004 81.072 104.088 81.096 ;
    END
  END b[421]
  PIN b[422]
    DIRECTION OUTPUT ;
    USE SIGNAL ;
    PORT
      LAYER M4 ;
        RECT  104.004 81.168 104.088 81.192 ;
    END
  END b[422]
  PIN b[423]
    DIRECTION OUTPUT ;
    USE SIGNAL ;
    PORT
      LAYER M4 ;
        RECT  104.004 81.264 104.088 81.288 ;
    END
  END b[423]
  PIN b[424]
    DIRECTION OUTPUT ;
    USE SIGNAL ;
    PORT
      LAYER M4 ;
        RECT  104.004 81.36 104.088 81.384 ;
    END
  END b[424]
  PIN b[425]
    DIRECTION OUTPUT ;
    USE SIGNAL ;
    PORT
      LAYER M4 ;
        RECT  104.004 81.456 104.088 81.48 ;
    END
  END b[425]
  PIN b[426]
    DIRECTION OUTPUT ;
    USE SIGNAL ;
    PORT
      LAYER M4 ;
        RECT  104.004 81.552 104.088 81.576 ;
    END
  END b[426]
  PIN b[427]
    DIRECTION OUTPUT ;
    USE SIGNAL ;
    PORT
      LAYER M4 ;
        RECT  104.004 81.648 104.088 81.672 ;
    END
  END b[427]
  PIN b[428]
    DIRECTION OUTPUT ;
    USE SIGNAL ;
    PORT
      LAYER M4 ;
        RECT  104.004 81.744 104.088 81.768 ;
    END
  END b[428]
  PIN b[429]
    DIRECTION OUTPUT ;
    USE SIGNAL ;
    PORT
      LAYER M4 ;
        RECT  104.004 81.84 104.088 81.864 ;
    END
  END b[429]
  PIN b[42]
    DIRECTION OUTPUT ;
    USE SIGNAL ;
    PORT
      LAYER M4 ;
        RECT  104.004 30.096 104.088 30.12 ;
    END
  END b[42]
  PIN b[430]
    DIRECTION OUTPUT ;
    USE SIGNAL ;
    PORT
      LAYER M4 ;
        RECT  104.004 81.936 104.088 81.96 ;
    END
  END b[430]
  PIN b[431]
    DIRECTION OUTPUT ;
    USE SIGNAL ;
    PORT
      LAYER M4 ;
        RECT  104.004 82.032 104.088 82.056 ;
    END
  END b[431]
  PIN b[432]
    DIRECTION OUTPUT ;
    USE SIGNAL ;
    PORT
      LAYER M4 ;
        RECT  104.004 82.128 104.088 82.152 ;
    END
  END b[432]
  PIN b[433]
    DIRECTION OUTPUT ;
    USE SIGNAL ;
    PORT
      LAYER M4 ;
        RECT  104.004 82.224 104.088 82.248 ;
    END
  END b[433]
  PIN b[434]
    DIRECTION OUTPUT ;
    USE SIGNAL ;
    PORT
      LAYER M4 ;
        RECT  104.004 82.32 104.088 82.344 ;
    END
  END b[434]
  PIN b[435]
    DIRECTION OUTPUT ;
    USE SIGNAL ;
    PORT
      LAYER M4 ;
        RECT  104.004 82.416 104.088 82.44 ;
    END
  END b[435]
  PIN b[436]
    DIRECTION OUTPUT ;
    USE SIGNAL ;
    PORT
      LAYER M4 ;
        RECT  104.004 82.512 104.088 82.536 ;
    END
  END b[436]
  PIN b[437]
    DIRECTION OUTPUT ;
    USE SIGNAL ;
    PORT
      LAYER M4 ;
        RECT  104.004 82.608 104.088 82.632 ;
    END
  END b[437]
  PIN b[438]
    DIRECTION OUTPUT ;
    USE SIGNAL ;
    PORT
      LAYER M4 ;
        RECT  104.004 82.704 104.088 82.728 ;
    END
  END b[438]
  PIN b[439]
    DIRECTION OUTPUT ;
    USE SIGNAL ;
    PORT
      LAYER M4 ;
        RECT  104.004 82.8 104.088 82.824 ;
    END
  END b[439]
  PIN b[43]
    DIRECTION OUTPUT ;
    USE SIGNAL ;
    PORT
      LAYER M4 ;
        RECT  104.004 30.192 104.088 30.216 ;
    END
  END b[43]
  PIN b[440]
    DIRECTION OUTPUT ;
    USE SIGNAL ;
    PORT
      LAYER M4 ;
        RECT  104.004 82.896 104.088 82.92 ;
    END
  END b[440]
  PIN b[441]
    DIRECTION OUTPUT ;
    USE SIGNAL ;
    PORT
      LAYER M4 ;
        RECT  104.004 82.992 104.088 83.016 ;
    END
  END b[441]
  PIN b[442]
    DIRECTION OUTPUT ;
    USE SIGNAL ;
    PORT
      LAYER M4 ;
        RECT  104.004 83.088 104.088 83.112 ;
    END
  END b[442]
  PIN b[443]
    DIRECTION OUTPUT ;
    USE SIGNAL ;
    PORT
      LAYER M4 ;
        RECT  104.004 83.184 104.088 83.208 ;
    END
  END b[443]
  PIN b[444]
    DIRECTION OUTPUT ;
    USE SIGNAL ;
    PORT
      LAYER M4 ;
        RECT  104.004 83.28 104.088 83.304 ;
    END
  END b[444]
  PIN b[445]
    DIRECTION OUTPUT ;
    USE SIGNAL ;
    PORT
      LAYER M4 ;
        RECT  104.004 83.376 104.088 83.4 ;
    END
  END b[445]
  PIN b[446]
    DIRECTION OUTPUT ;
    USE SIGNAL ;
    PORT
      LAYER M4 ;
        RECT  104.004 83.472 104.088 83.496 ;
    END
  END b[446]
  PIN b[447]
    DIRECTION OUTPUT ;
    USE SIGNAL ;
    PORT
      LAYER M4 ;
        RECT  104.004 83.568 104.088 83.592 ;
    END
  END b[447]
  PIN b[448]
    DIRECTION OUTPUT ;
    USE SIGNAL ;
    PORT
      LAYER M4 ;
        RECT  104.004 83.664 104.088 83.688 ;
    END
  END b[448]
  PIN b[449]
    DIRECTION OUTPUT ;
    USE SIGNAL ;
    PORT
      LAYER M4 ;
        RECT  104.004 83.76 104.088 83.784 ;
    END
  END b[449]
  PIN b[44]
    DIRECTION OUTPUT ;
    USE SIGNAL ;
    PORT
      LAYER M4 ;
        RECT  104.004 30.288 104.088 30.312 ;
    END
  END b[44]
  PIN b[450]
    DIRECTION OUTPUT ;
    USE SIGNAL ;
    PORT
      LAYER M4 ;
        RECT  104.004 83.856 104.088 83.88 ;
    END
  END b[450]
  PIN b[451]
    DIRECTION OUTPUT ;
    USE SIGNAL ;
    PORT
      LAYER M4 ;
        RECT  104.004 83.952 104.088 83.976 ;
    END
  END b[451]
  PIN b[452]
    DIRECTION OUTPUT ;
    USE SIGNAL ;
    PORT
      LAYER M4 ;
        RECT  104.004 84.048 104.088 84.072 ;
    END
  END b[452]
  PIN b[453]
    DIRECTION OUTPUT ;
    USE SIGNAL ;
    PORT
      LAYER M4 ;
        RECT  104.004 84.144 104.088 84.168 ;
    END
  END b[453]
  PIN b[454]
    DIRECTION OUTPUT ;
    USE SIGNAL ;
    PORT
      LAYER M4 ;
        RECT  104.004 84.24 104.088 84.264 ;
    END
  END b[454]
  PIN b[455]
    DIRECTION OUTPUT ;
    USE SIGNAL ;
    PORT
      LAYER M4 ;
        RECT  104.004 84.336 104.088 84.36 ;
    END
  END b[455]
  PIN b[456]
    DIRECTION OUTPUT ;
    USE SIGNAL ;
    PORT
      LAYER M4 ;
        RECT  104.004 84.432 104.088 84.456 ;
    END
  END b[456]
  PIN b[457]
    DIRECTION OUTPUT ;
    USE SIGNAL ;
    PORT
      LAYER M4 ;
        RECT  104.004 84.528 104.088 84.552 ;
    END
  END b[457]
  PIN b[458]
    DIRECTION OUTPUT ;
    USE SIGNAL ;
    PORT
      LAYER M4 ;
        RECT  104.004 84.624 104.088 84.648 ;
    END
  END b[458]
  PIN b[459]
    DIRECTION OUTPUT ;
    USE SIGNAL ;
    PORT
      LAYER M4 ;
        RECT  104.004 84.72 104.088 84.744 ;
    END
  END b[459]
  PIN b[45]
    DIRECTION OUTPUT ;
    USE SIGNAL ;
    PORT
      LAYER M4 ;
        RECT  104.004 30.384 104.088 30.408 ;
    END
  END b[45]
  PIN b[460]
    DIRECTION OUTPUT ;
    USE SIGNAL ;
    PORT
      LAYER M4 ;
        RECT  104.004 84.816 104.088 84.84 ;
    END
  END b[460]
  PIN b[461]
    DIRECTION OUTPUT ;
    USE SIGNAL ;
    PORT
      LAYER M4 ;
        RECT  104.004 84.912 104.088 84.936 ;
    END
  END b[461]
  PIN b[462]
    DIRECTION OUTPUT ;
    USE SIGNAL ;
    PORT
      LAYER M4 ;
        RECT  104.004 85.008 104.088 85.032 ;
    END
  END b[462]
  PIN b[463]
    DIRECTION OUTPUT ;
    USE SIGNAL ;
    PORT
      LAYER M4 ;
        RECT  104.004 85.104 104.088 85.128 ;
    END
  END b[463]
  PIN b[464]
    DIRECTION OUTPUT ;
    USE SIGNAL ;
    PORT
      LAYER M4 ;
        RECT  104.004 85.2 104.088 85.224 ;
    END
  END b[464]
  PIN b[465]
    DIRECTION OUTPUT ;
    USE SIGNAL ;
    PORT
      LAYER M4 ;
        RECT  104.004 85.296 104.088 85.32 ;
    END
  END b[465]
  PIN b[466]
    DIRECTION OUTPUT ;
    USE SIGNAL ;
    PORT
      LAYER M4 ;
        RECT  104.004 85.392 104.088 85.416 ;
    END
  END b[466]
  PIN b[467]
    DIRECTION OUTPUT ;
    USE SIGNAL ;
    PORT
      LAYER M4 ;
        RECT  104.004 85.488 104.088 85.512 ;
    END
  END b[467]
  PIN b[468]
    DIRECTION OUTPUT ;
    USE SIGNAL ;
    PORT
      LAYER M4 ;
        RECT  104.004 85.584 104.088 85.608 ;
    END
  END b[468]
  PIN b[469]
    DIRECTION OUTPUT ;
    USE SIGNAL ;
    PORT
      LAYER M4 ;
        RECT  104.004 85.68 104.088 85.704 ;
    END
  END b[469]
  PIN b[46]
    DIRECTION OUTPUT ;
    USE SIGNAL ;
    PORT
      LAYER M4 ;
        RECT  104.004 30.48 104.088 30.504 ;
    END
  END b[46]
  PIN b[470]
    DIRECTION OUTPUT ;
    USE SIGNAL ;
    PORT
      LAYER M4 ;
        RECT  104.004 85.776 104.088 85.8 ;
    END
  END b[470]
  PIN b[471]
    DIRECTION OUTPUT ;
    USE SIGNAL ;
    PORT
      LAYER M4 ;
        RECT  104.004 85.872 104.088 85.896 ;
    END
  END b[471]
  PIN b[472]
    DIRECTION OUTPUT ;
    USE SIGNAL ;
    PORT
      LAYER M4 ;
        RECT  104.004 85.968 104.088 85.992 ;
    END
  END b[472]
  PIN b[473]
    DIRECTION OUTPUT ;
    USE SIGNAL ;
    PORT
      LAYER M4 ;
        RECT  104.004 86.064 104.088 86.088 ;
    END
  END b[473]
  PIN b[474]
    DIRECTION OUTPUT ;
    USE SIGNAL ;
    PORT
      LAYER M4 ;
        RECT  104.004 86.16 104.088 86.184 ;
    END
  END b[474]
  PIN b[475]
    DIRECTION OUTPUT ;
    USE SIGNAL ;
    PORT
      LAYER M4 ;
        RECT  104.004 86.256 104.088 86.28 ;
    END
  END b[475]
  PIN b[476]
    DIRECTION OUTPUT ;
    USE SIGNAL ;
    PORT
      LAYER M4 ;
        RECT  104.004 86.352 104.088 86.376 ;
    END
  END b[476]
  PIN b[477]
    DIRECTION OUTPUT ;
    USE SIGNAL ;
    PORT
      LAYER M4 ;
        RECT  104.004 86.448 104.088 86.472 ;
    END
  END b[477]
  PIN b[478]
    DIRECTION OUTPUT ;
    USE SIGNAL ;
    PORT
      LAYER M4 ;
        RECT  104.004 86.544 104.088 86.568 ;
    END
  END b[478]
  PIN b[479]
    DIRECTION OUTPUT ;
    USE SIGNAL ;
    PORT
      LAYER M4 ;
        RECT  104.004 86.64 104.088 86.664 ;
    END
  END b[479]
  PIN b[47]
    DIRECTION OUTPUT ;
    USE SIGNAL ;
    PORT
      LAYER M4 ;
        RECT  104.004 30.576 104.088 30.6 ;
    END
  END b[47]
  PIN b[480]
    DIRECTION OUTPUT ;
    USE SIGNAL ;
    PORT
      LAYER M4 ;
        RECT  104.004 70.608 104.088 70.632 ;
    END
  END b[480]
  PIN b[481]
    DIRECTION OUTPUT ;
    USE SIGNAL ;
    PORT
      LAYER M4 ;
        RECT  104.004 70.704 104.088 70.728 ;
    END
  END b[481]
  PIN b[482]
    DIRECTION OUTPUT ;
    USE SIGNAL ;
    PORT
      LAYER M4 ;
        RECT  104.004 70.8 104.088 70.824 ;
    END
  END b[482]
  PIN b[483]
    DIRECTION OUTPUT ;
    USE SIGNAL ;
    PORT
      LAYER M4 ;
        RECT  104.004 70.896 104.088 70.92 ;
    END
  END b[483]
  PIN b[484]
    DIRECTION OUTPUT ;
    USE SIGNAL ;
    PORT
      LAYER M4 ;
        RECT  104.004 70.992 104.088 71.016 ;
    END
  END b[484]
  PIN b[485]
    DIRECTION OUTPUT ;
    USE SIGNAL ;
    PORT
      LAYER M4 ;
        RECT  104.004 71.088 104.088 71.112 ;
    END
  END b[485]
  PIN b[486]
    DIRECTION OUTPUT ;
    USE SIGNAL ;
    PORT
      LAYER M4 ;
        RECT  104.004 71.184 104.088 71.208 ;
    END
  END b[486]
  PIN b[487]
    DIRECTION OUTPUT ;
    USE SIGNAL ;
    PORT
      LAYER M4 ;
        RECT  104.004 71.28 104.088 71.304 ;
    END
  END b[487]
  PIN b[488]
    DIRECTION OUTPUT ;
    USE SIGNAL ;
    PORT
      LAYER M4 ;
        RECT  104.004 71.376 104.088 71.4 ;
    END
  END b[488]
  PIN b[489]
    DIRECTION OUTPUT ;
    USE SIGNAL ;
    PORT
      LAYER M4 ;
        RECT  104.004 71.472 104.088 71.496 ;
    END
  END b[489]
  PIN b[48]
    DIRECTION OUTPUT ;
    USE SIGNAL ;
    PORT
      LAYER M4 ;
        RECT  104.004 30.672 104.088 30.696 ;
    END
  END b[48]
  PIN b[490]
    DIRECTION OUTPUT ;
    USE SIGNAL ;
    PORT
      LAYER M4 ;
        RECT  104.004 71.568 104.088 71.592 ;
    END
  END b[490]
  PIN b[491]
    DIRECTION OUTPUT ;
    USE SIGNAL ;
    PORT
      LAYER M4 ;
        RECT  104.004 71.664 104.088 71.688 ;
    END
  END b[491]
  PIN b[492]
    DIRECTION OUTPUT ;
    USE SIGNAL ;
    PORT
      LAYER M4 ;
        RECT  104.004 71.76 104.088 71.784 ;
    END
  END b[492]
  PIN b[493]
    DIRECTION OUTPUT ;
    USE SIGNAL ;
    PORT
      LAYER M4 ;
        RECT  104.004 71.856 104.088 71.88 ;
    END
  END b[493]
  PIN b[494]
    DIRECTION OUTPUT ;
    USE SIGNAL ;
    PORT
      LAYER M4 ;
        RECT  104.004 71.952 104.088 71.976 ;
    END
  END b[494]
  PIN b[495]
    DIRECTION OUTPUT ;
    USE SIGNAL ;
    PORT
      LAYER M4 ;
        RECT  104.004 72.048 104.088 72.072 ;
    END
  END b[495]
  PIN b[496]
    DIRECTION OUTPUT ;
    USE SIGNAL ;
    PORT
      LAYER M4 ;
        RECT  104.004 72.144 104.088 72.168 ;
    END
  END b[496]
  PIN b[497]
    DIRECTION OUTPUT ;
    USE SIGNAL ;
    PORT
      LAYER M4 ;
        RECT  104.004 72.24 104.088 72.264 ;
    END
  END b[497]
  PIN b[498]
    DIRECTION OUTPUT ;
    USE SIGNAL ;
    PORT
      LAYER M4 ;
        RECT  104.004 72.336 104.088 72.36 ;
    END
  END b[498]
  PIN b[499]
    DIRECTION OUTPUT ;
    USE SIGNAL ;
    PORT
      LAYER M4 ;
        RECT  104.004 72.432 104.088 72.456 ;
    END
  END b[499]
  PIN b[49]
    DIRECTION OUTPUT ;
    USE SIGNAL ;
    PORT
      LAYER M4 ;
        RECT  104.004 30.768 104.088 30.792 ;
    END
  END b[49]
  PIN b[4]
    DIRECTION OUTPUT ;
    USE SIGNAL ;
    PORT
      LAYER M4 ;
        RECT  104.004 32.592 104.088 32.616 ;
    END
  END b[4]
  PIN b[500]
    DIRECTION OUTPUT ;
    USE SIGNAL ;
    PORT
      LAYER M4 ;
        RECT  104.004 72.528 104.088 72.552 ;
    END
  END b[500]
  PIN b[501]
    DIRECTION OUTPUT ;
    USE SIGNAL ;
    PORT
      LAYER M4 ;
        RECT  104.004 72.624 104.088 72.648 ;
    END
  END b[501]
  PIN b[502]
    DIRECTION OUTPUT ;
    USE SIGNAL ;
    PORT
      LAYER M4 ;
        RECT  104.004 72.72 104.088 72.744 ;
    END
  END b[502]
  PIN b[503]
    DIRECTION OUTPUT ;
    USE SIGNAL ;
    PORT
      LAYER M4 ;
        RECT  104.004 72.816 104.088 72.84 ;
    END
  END b[503]
  PIN b[504]
    DIRECTION OUTPUT ;
    USE SIGNAL ;
    PORT
      LAYER M4 ;
        RECT  104.004 72.912 104.088 72.936 ;
    END
  END b[504]
  PIN b[505]
    DIRECTION OUTPUT ;
    USE SIGNAL ;
    PORT
      LAYER M4 ;
        RECT  104.004 73.008 104.088 73.032 ;
    END
  END b[505]
  PIN b[506]
    DIRECTION OUTPUT ;
    USE SIGNAL ;
    PORT
      LAYER M4 ;
        RECT  104.004 73.104 104.088 73.128 ;
    END
  END b[506]
  PIN b[507]
    DIRECTION OUTPUT ;
    USE SIGNAL ;
    PORT
      LAYER M4 ;
        RECT  104.004 73.2 104.088 73.224 ;
    END
  END b[507]
  PIN b[508]
    DIRECTION OUTPUT ;
    USE SIGNAL ;
    PORT
      LAYER M4 ;
        RECT  104.004 73.296 104.088 73.32 ;
    END
  END b[508]
  PIN b[509]
    DIRECTION OUTPUT ;
    USE SIGNAL ;
    PORT
      LAYER M4 ;
        RECT  104.004 73.392 104.088 73.416 ;
    END
  END b[509]
  PIN b[50]
    DIRECTION OUTPUT ;
    USE SIGNAL ;
    PORT
      LAYER M4 ;
        RECT  104.004 30.864 104.088 30.888 ;
    END
  END b[50]
  PIN b[510]
    DIRECTION OUTPUT ;
    USE SIGNAL ;
    PORT
      LAYER M4 ;
        RECT  104.004 73.488 104.088 73.512 ;
    END
  END b[510]
  PIN b[511]
    DIRECTION OUTPUT ;
    USE SIGNAL ;
    PORT
      LAYER M4 ;
        RECT  104.004 73.584 104.088 73.608 ;
    END
  END b[511]
  PIN b[512]
    DIRECTION OUTPUT ;
    USE SIGNAL ;
    PORT
      LAYER M4 ;
        RECT  104.004 51.408 104.088 51.432 ;
    END
  END b[512]
  PIN b[513]
    DIRECTION OUTPUT ;
    USE SIGNAL ;
    PORT
      LAYER M4 ;
        RECT  104.004 51.504 104.088 51.528 ;
    END
  END b[513]
  PIN b[514]
    DIRECTION OUTPUT ;
    USE SIGNAL ;
    PORT
      LAYER M4 ;
        RECT  104.004 51.6 104.088 51.624 ;
    END
  END b[514]
  PIN b[515]
    DIRECTION OUTPUT ;
    USE SIGNAL ;
    PORT
      LAYER M4 ;
        RECT  104.004 51.696 104.088 51.72 ;
    END
  END b[515]
  PIN b[516]
    DIRECTION OUTPUT ;
    USE SIGNAL ;
    PORT
      LAYER M4 ;
        RECT  104.004 51.792 104.088 51.816 ;
    END
  END b[516]
  PIN b[517]
    DIRECTION OUTPUT ;
    USE SIGNAL ;
    PORT
      LAYER M4 ;
        RECT  104.004 51.888 104.088 51.912 ;
    END
  END b[517]
  PIN b[518]
    DIRECTION OUTPUT ;
    USE SIGNAL ;
    PORT
      LAYER M4 ;
        RECT  104.004 51.984 104.088 52.008 ;
    END
  END b[518]
  PIN b[519]
    DIRECTION OUTPUT ;
    USE SIGNAL ;
    PORT
      LAYER M4 ;
        RECT  104.004 52.08 104.088 52.104 ;
    END
  END b[519]
  PIN b[51]
    DIRECTION OUTPUT ;
    USE SIGNAL ;
    PORT
      LAYER M4 ;
        RECT  104.004 30.96 104.088 30.984 ;
    END
  END b[51]
  PIN b[520]
    DIRECTION OUTPUT ;
    USE SIGNAL ;
    PORT
      LAYER M4 ;
        RECT  104.004 52.176 104.088 52.2 ;
    END
  END b[520]
  PIN b[521]
    DIRECTION OUTPUT ;
    USE SIGNAL ;
    PORT
      LAYER M4 ;
        RECT  104.004 52.272 104.088 52.296 ;
    END
  END b[521]
  PIN b[522]
    DIRECTION OUTPUT ;
    USE SIGNAL ;
    PORT
      LAYER M4 ;
        RECT  104.004 52.368 104.088 52.392 ;
    END
  END b[522]
  PIN b[523]
    DIRECTION OUTPUT ;
    USE SIGNAL ;
    PORT
      LAYER M4 ;
        RECT  104.004 52.464 104.088 52.488 ;
    END
  END b[523]
  PIN b[524]
    DIRECTION OUTPUT ;
    USE SIGNAL ;
    PORT
      LAYER M4 ;
        RECT  104.004 52.56 104.088 52.584 ;
    END
  END b[524]
  PIN b[525]
    DIRECTION OUTPUT ;
    USE SIGNAL ;
    PORT
      LAYER M4 ;
        RECT  104.004 52.656 104.088 52.68 ;
    END
  END b[525]
  PIN b[526]
    DIRECTION OUTPUT ;
    USE SIGNAL ;
    PORT
      LAYER M4 ;
        RECT  104.004 52.752 104.088 52.776 ;
    END
  END b[526]
  PIN b[527]
    DIRECTION OUTPUT ;
    USE SIGNAL ;
    PORT
      LAYER M4 ;
        RECT  104.004 52.848 104.088 52.872 ;
    END
  END b[527]
  PIN b[528]
    DIRECTION OUTPUT ;
    USE SIGNAL ;
    PORT
      LAYER M4 ;
        RECT  104.004 52.944 104.088 52.968 ;
    END
  END b[528]
  PIN b[529]
    DIRECTION OUTPUT ;
    USE SIGNAL ;
    PORT
      LAYER M4 ;
        RECT  104.004 53.04 104.088 53.064 ;
    END
  END b[529]
  PIN b[52]
    DIRECTION OUTPUT ;
    USE SIGNAL ;
    PORT
      LAYER M4 ;
        RECT  104.004 31.056 104.088 31.08 ;
    END
  END b[52]
  PIN b[530]
    DIRECTION OUTPUT ;
    USE SIGNAL ;
    PORT
      LAYER M4 ;
        RECT  104.004 53.136 104.088 53.16 ;
    END
  END b[530]
  PIN b[531]
    DIRECTION OUTPUT ;
    USE SIGNAL ;
    PORT
      LAYER M4 ;
        RECT  104.004 53.232 104.088 53.256 ;
    END
  END b[531]
  PIN b[532]
    DIRECTION OUTPUT ;
    USE SIGNAL ;
    PORT
      LAYER M4 ;
        RECT  104.004 53.328 104.088 53.352 ;
    END
  END b[532]
  PIN b[533]
    DIRECTION OUTPUT ;
    USE SIGNAL ;
    PORT
      LAYER M4 ;
        RECT  104.004 53.424 104.088 53.448 ;
    END
  END b[533]
  PIN b[534]
    DIRECTION OUTPUT ;
    USE SIGNAL ;
    PORT
      LAYER M4 ;
        RECT  104.004 53.52 104.088 53.544 ;
    END
  END b[534]
  PIN b[535]
    DIRECTION OUTPUT ;
    USE SIGNAL ;
    PORT
      LAYER M4 ;
        RECT  104.004 53.616 104.088 53.64 ;
    END
  END b[535]
  PIN b[536]
    DIRECTION OUTPUT ;
    USE SIGNAL ;
    PORT
      LAYER M4 ;
        RECT  104.004 53.712 104.088 53.736 ;
    END
  END b[536]
  PIN b[537]
    DIRECTION OUTPUT ;
    USE SIGNAL ;
    PORT
      LAYER M4 ;
        RECT  104.004 53.808 104.088 53.832 ;
    END
  END b[537]
  PIN b[538]
    DIRECTION OUTPUT ;
    USE SIGNAL ;
    PORT
      LAYER M4 ;
        RECT  104.004 53.904 104.088 53.928 ;
    END
  END b[538]
  PIN b[539]
    DIRECTION OUTPUT ;
    USE SIGNAL ;
    PORT
      LAYER M4 ;
        RECT  104.004 54 104.088 54.024 ;
    END
  END b[539]
  PIN b[53]
    DIRECTION OUTPUT ;
    USE SIGNAL ;
    PORT
      LAYER M4 ;
        RECT  104.004 31.152 104.088 31.176 ;
    END
  END b[53]
  PIN b[540]
    DIRECTION OUTPUT ;
    USE SIGNAL ;
    PORT
      LAYER M4 ;
        RECT  104.004 54.096 104.088 54.12 ;
    END
  END b[540]
  PIN b[541]
    DIRECTION OUTPUT ;
    USE SIGNAL ;
    PORT
      LAYER M4 ;
        RECT  104.004 54.192 104.088 54.216 ;
    END
  END b[541]
  PIN b[542]
    DIRECTION OUTPUT ;
    USE SIGNAL ;
    PORT
      LAYER M4 ;
        RECT  104.004 54.288 104.088 54.312 ;
    END
  END b[542]
  PIN b[543]
    DIRECTION OUTPUT ;
    USE SIGNAL ;
    PORT
      LAYER M4 ;
        RECT  104.004 54.384 104.088 54.408 ;
    END
  END b[543]
  PIN b[544]
    DIRECTION OUTPUT ;
    USE SIGNAL ;
    PORT
      LAYER M4 ;
        RECT  104.004 45.264 104.088 45.288 ;
    END
  END b[544]
  PIN b[545]
    DIRECTION OUTPUT ;
    USE SIGNAL ;
    PORT
      LAYER M4 ;
        RECT  104.004 45.36 104.088 45.384 ;
    END
  END b[545]
  PIN b[546]
    DIRECTION OUTPUT ;
    USE SIGNAL ;
    PORT
      LAYER M4 ;
        RECT  104.004 45.456 104.088 45.48 ;
    END
  END b[546]
  PIN b[547]
    DIRECTION OUTPUT ;
    USE SIGNAL ;
    PORT
      LAYER M4 ;
        RECT  104.004 45.552 104.088 45.576 ;
    END
  END b[547]
  PIN b[548]
    DIRECTION OUTPUT ;
    USE SIGNAL ;
    PORT
      LAYER M4 ;
        RECT  104.004 45.648 104.088 45.672 ;
    END
  END b[548]
  PIN b[549]
    DIRECTION OUTPUT ;
    USE SIGNAL ;
    PORT
      LAYER M4 ;
        RECT  104.004 45.744 104.088 45.768 ;
    END
  END b[549]
  PIN b[54]
    DIRECTION OUTPUT ;
    USE SIGNAL ;
    PORT
      LAYER M4 ;
        RECT  104.004 31.248 104.088 31.272 ;
    END
  END b[54]
  PIN b[550]
    DIRECTION OUTPUT ;
    USE SIGNAL ;
    PORT
      LAYER M4 ;
        RECT  104.004 45.84 104.088 45.864 ;
    END
  END b[550]
  PIN b[551]
    DIRECTION OUTPUT ;
    USE SIGNAL ;
    PORT
      LAYER M4 ;
        RECT  104.004 45.936 104.088 45.96 ;
    END
  END b[551]
  PIN b[552]
    DIRECTION OUTPUT ;
    USE SIGNAL ;
    PORT
      LAYER M4 ;
        RECT  104.004 46.032 104.088 46.056 ;
    END
  END b[552]
  PIN b[553]
    DIRECTION OUTPUT ;
    USE SIGNAL ;
    PORT
      LAYER M4 ;
        RECT  104.004 46.128 104.088 46.152 ;
    END
  END b[553]
  PIN b[554]
    DIRECTION OUTPUT ;
    USE SIGNAL ;
    PORT
      LAYER M4 ;
        RECT  104.004 46.224 104.088 46.248 ;
    END
  END b[554]
  PIN b[555]
    DIRECTION OUTPUT ;
    USE SIGNAL ;
    PORT
      LAYER M4 ;
        RECT  104.004 46.32 104.088 46.344 ;
    END
  END b[555]
  PIN b[556]
    DIRECTION OUTPUT ;
    USE SIGNAL ;
    PORT
      LAYER M4 ;
        RECT  104.004 46.416 104.088 46.44 ;
    END
  END b[556]
  PIN b[557]
    DIRECTION OUTPUT ;
    USE SIGNAL ;
    PORT
      LAYER M4 ;
        RECT  104.004 46.512 104.088 46.536 ;
    END
  END b[557]
  PIN b[558]
    DIRECTION OUTPUT ;
    USE SIGNAL ;
    PORT
      LAYER M4 ;
        RECT  104.004 46.608 104.088 46.632 ;
    END
  END b[558]
  PIN b[559]
    DIRECTION OUTPUT ;
    USE SIGNAL ;
    PORT
      LAYER M4 ;
        RECT  104.004 46.704 104.088 46.728 ;
    END
  END b[559]
  PIN b[55]
    DIRECTION OUTPUT ;
    USE SIGNAL ;
    PORT
      LAYER M4 ;
        RECT  104.004 31.344 104.088 31.368 ;
    END
  END b[55]
  PIN b[560]
    DIRECTION OUTPUT ;
    USE SIGNAL ;
    PORT
      LAYER M4 ;
        RECT  104.004 46.8 104.088 46.824 ;
    END
  END b[560]
  PIN b[561]
    DIRECTION OUTPUT ;
    USE SIGNAL ;
    PORT
      LAYER M4 ;
        RECT  104.004 46.896 104.088 46.92 ;
    END
  END b[561]
  PIN b[562]
    DIRECTION OUTPUT ;
    USE SIGNAL ;
    PORT
      LAYER M4 ;
        RECT  104.004 46.992 104.088 47.016 ;
    END
  END b[562]
  PIN b[563]
    DIRECTION OUTPUT ;
    USE SIGNAL ;
    PORT
      LAYER M4 ;
        RECT  104.004 47.088 104.088 47.112 ;
    END
  END b[563]
  PIN b[564]
    DIRECTION OUTPUT ;
    USE SIGNAL ;
    PORT
      LAYER M4 ;
        RECT  104.004 47.184 104.088 47.208 ;
    END
  END b[564]
  PIN b[565]
    DIRECTION OUTPUT ;
    USE SIGNAL ;
    PORT
      LAYER M4 ;
        RECT  104.004 47.28 104.088 47.304 ;
    END
  END b[565]
  PIN b[566]
    DIRECTION OUTPUT ;
    USE SIGNAL ;
    PORT
      LAYER M4 ;
        RECT  104.004 47.376 104.088 47.4 ;
    END
  END b[566]
  PIN b[567]
    DIRECTION OUTPUT ;
    USE SIGNAL ;
    PORT
      LAYER M4 ;
        RECT  104.004 47.472 104.088 47.496 ;
    END
  END b[567]
  PIN b[568]
    DIRECTION OUTPUT ;
    USE SIGNAL ;
    PORT
      LAYER M4 ;
        RECT  104.004 47.568 104.088 47.592 ;
    END
  END b[568]
  PIN b[569]
    DIRECTION OUTPUT ;
    USE SIGNAL ;
    PORT
      LAYER M4 ;
        RECT  104.004 47.664 104.088 47.688 ;
    END
  END b[569]
  PIN b[56]
    DIRECTION OUTPUT ;
    USE SIGNAL ;
    PORT
      LAYER M4 ;
        RECT  104.004 31.44 104.088 31.464 ;
    END
  END b[56]
  PIN b[570]
    DIRECTION OUTPUT ;
    USE SIGNAL ;
    PORT
      LAYER M4 ;
        RECT  104.004 47.76 104.088 47.784 ;
    END
  END b[570]
  PIN b[571]
    DIRECTION OUTPUT ;
    USE SIGNAL ;
    PORT
      LAYER M4 ;
        RECT  104.004 47.856 104.088 47.88 ;
    END
  END b[571]
  PIN b[572]
    DIRECTION OUTPUT ;
    USE SIGNAL ;
    PORT
      LAYER M4 ;
        RECT  104.004 47.952 104.088 47.976 ;
    END
  END b[572]
  PIN b[573]
    DIRECTION OUTPUT ;
    USE SIGNAL ;
    PORT
      LAYER M4 ;
        RECT  104.004 48.048 104.088 48.072 ;
    END
  END b[573]
  PIN b[574]
    DIRECTION OUTPUT ;
    USE SIGNAL ;
    PORT
      LAYER M4 ;
        RECT  104.004 48.144 104.088 48.168 ;
    END
  END b[574]
  PIN b[575]
    DIRECTION OUTPUT ;
    USE SIGNAL ;
    PORT
      LAYER M4 ;
        RECT  104.004 48.24 104.088 48.264 ;
    END
  END b[575]
  PIN b[576]
    DIRECTION OUTPUT ;
    USE SIGNAL ;
    PORT
      LAYER M4 ;
        RECT  104.004 54.48 104.088 54.504 ;
    END
  END b[576]
  PIN b[577]
    DIRECTION OUTPUT ;
    USE SIGNAL ;
    PORT
      LAYER M4 ;
        RECT  104.004 54.576 104.088 54.6 ;
    END
  END b[577]
  PIN b[578]
    DIRECTION OUTPUT ;
    USE SIGNAL ;
    PORT
      LAYER M4 ;
        RECT  104.004 54.672 104.088 54.696 ;
    END
  END b[578]
  PIN b[579]
    DIRECTION OUTPUT ;
    USE SIGNAL ;
    PORT
      LAYER M4 ;
        RECT  104.004 54.768 104.088 54.792 ;
    END
  END b[579]
  PIN b[57]
    DIRECTION OUTPUT ;
    USE SIGNAL ;
    PORT
      LAYER M4 ;
        RECT  104.004 31.536 104.088 31.56 ;
    END
  END b[57]
  PIN b[580]
    DIRECTION OUTPUT ;
    USE SIGNAL ;
    PORT
      LAYER M4 ;
        RECT  104.004 54.864 104.088 54.888 ;
    END
  END b[580]
  PIN b[581]
    DIRECTION OUTPUT ;
    USE SIGNAL ;
    PORT
      LAYER M4 ;
        RECT  104.004 54.96 104.088 54.984 ;
    END
  END b[581]
  PIN b[582]
    DIRECTION OUTPUT ;
    USE SIGNAL ;
    PORT
      LAYER M4 ;
        RECT  104.004 55.056 104.088 55.08 ;
    END
  END b[582]
  PIN b[583]
    DIRECTION OUTPUT ;
    USE SIGNAL ;
    PORT
      LAYER M4 ;
        RECT  104.004 55.152 104.088 55.176 ;
    END
  END b[583]
  PIN b[584]
    DIRECTION OUTPUT ;
    USE SIGNAL ;
    PORT
      LAYER M4 ;
        RECT  104.004 55.248 104.088 55.272 ;
    END
  END b[584]
  PIN b[585]
    DIRECTION OUTPUT ;
    USE SIGNAL ;
    PORT
      LAYER M4 ;
        RECT  104.004 55.344 104.088 55.368 ;
    END
  END b[585]
  PIN b[586]
    DIRECTION OUTPUT ;
    USE SIGNAL ;
    PORT
      LAYER M4 ;
        RECT  104.004 55.44 104.088 55.464 ;
    END
  END b[586]
  PIN b[587]
    DIRECTION OUTPUT ;
    USE SIGNAL ;
    PORT
      LAYER M4 ;
        RECT  104.004 55.536 104.088 55.56 ;
    END
  END b[587]
  PIN b[588]
    DIRECTION OUTPUT ;
    USE SIGNAL ;
    PORT
      LAYER M4 ;
        RECT  104.004 55.632 104.088 55.656 ;
    END
  END b[588]
  PIN b[589]
    DIRECTION OUTPUT ;
    USE SIGNAL ;
    PORT
      LAYER M4 ;
        RECT  104.004 55.728 104.088 55.752 ;
    END
  END b[589]
  PIN b[58]
    DIRECTION OUTPUT ;
    USE SIGNAL ;
    PORT
      LAYER M4 ;
        RECT  104.004 31.632 104.088 31.656 ;
    END
  END b[58]
  PIN b[590]
    DIRECTION OUTPUT ;
    USE SIGNAL ;
    PORT
      LAYER M4 ;
        RECT  104.004 55.824 104.088 55.848 ;
    END
  END b[590]
  PIN b[591]
    DIRECTION OUTPUT ;
    USE SIGNAL ;
    PORT
      LAYER M4 ;
        RECT  104.004 55.92 104.088 55.944 ;
    END
  END b[591]
  PIN b[592]
    DIRECTION OUTPUT ;
    USE SIGNAL ;
    PORT
      LAYER M4 ;
        RECT  104.004 56.016 104.088 56.04 ;
    END
  END b[592]
  PIN b[593]
    DIRECTION OUTPUT ;
    USE SIGNAL ;
    PORT
      LAYER M4 ;
        RECT  104.004 56.112 104.088 56.136 ;
    END
  END b[593]
  PIN b[594]
    DIRECTION OUTPUT ;
    USE SIGNAL ;
    PORT
      LAYER M4 ;
        RECT  104.004 56.208 104.088 56.232 ;
    END
  END b[594]
  PIN b[595]
    DIRECTION OUTPUT ;
    USE SIGNAL ;
    PORT
      LAYER M4 ;
        RECT  104.004 56.304 104.088 56.328 ;
    END
  END b[595]
  PIN b[596]
    DIRECTION OUTPUT ;
    USE SIGNAL ;
    PORT
      LAYER M4 ;
        RECT  104.004 56.4 104.088 56.424 ;
    END
  END b[596]
  PIN b[597]
    DIRECTION OUTPUT ;
    USE SIGNAL ;
    PORT
      LAYER M4 ;
        RECT  104.004 56.496 104.088 56.52 ;
    END
  END b[597]
  PIN b[598]
    DIRECTION OUTPUT ;
    USE SIGNAL ;
    PORT
      LAYER M4 ;
        RECT  104.004 56.592 104.088 56.616 ;
    END
  END b[598]
  PIN b[599]
    DIRECTION OUTPUT ;
    USE SIGNAL ;
    PORT
      LAYER M4 ;
        RECT  104.004 56.688 104.088 56.712 ;
    END
  END b[599]
  PIN b[59]
    DIRECTION OUTPUT ;
    USE SIGNAL ;
    PORT
      LAYER M4 ;
        RECT  104.004 31.728 104.088 31.752 ;
    END
  END b[59]
  PIN b[5]
    DIRECTION OUTPUT ;
    USE SIGNAL ;
    PORT
      LAYER M4 ;
        RECT  104.004 32.688 104.088 32.712 ;
    END
  END b[5]
  PIN b[60]
    DIRECTION OUTPUT ;
    USE SIGNAL ;
    PORT
      LAYER M4 ;
        RECT  104.004 31.824 104.088 31.848 ;
    END
  END b[60]
  PIN b[61]
    DIRECTION OUTPUT ;
    USE SIGNAL ;
    PORT
      LAYER M4 ;
        RECT  104.004 31.92 104.088 31.944 ;
    END
  END b[61]
  PIN b[62]
    DIRECTION OUTPUT ;
    USE SIGNAL ;
    PORT
      LAYER M4 ;
        RECT  104.004 32.016 104.088 32.04 ;
    END
  END b[62]
  PIN b[63]
    DIRECTION OUTPUT ;
    USE SIGNAL ;
    PORT
      LAYER M4 ;
        RECT  104.004 32.112 104.088 32.136 ;
    END
  END b[63]
  PIN b[64]
    DIRECTION OUTPUT ;
    USE SIGNAL ;
    PORT
      LAYER M4 ;
        RECT  104.004 26.064 104.088 26.088 ;
    END
  END b[64]
  PIN b[65]
    DIRECTION OUTPUT ;
    USE SIGNAL ;
    PORT
      LAYER M4 ;
        RECT  104.004 26.16 104.088 26.184 ;
    END
  END b[65]
  PIN b[66]
    DIRECTION OUTPUT ;
    USE SIGNAL ;
    PORT
      LAYER M4 ;
        RECT  104.004 26.256 104.088 26.28 ;
    END
  END b[66]
  PIN b[67]
    DIRECTION OUTPUT ;
    USE SIGNAL ;
    PORT
      LAYER M4 ;
        RECT  104.004 26.352 104.088 26.376 ;
    END
  END b[67]
  PIN b[68]
    DIRECTION OUTPUT ;
    USE SIGNAL ;
    PORT
      LAYER M4 ;
        RECT  104.004 26.448 104.088 26.472 ;
    END
  END b[68]
  PIN b[69]
    DIRECTION OUTPUT ;
    USE SIGNAL ;
    PORT
      LAYER M4 ;
        RECT  104.004 26.544 104.088 26.568 ;
    END
  END b[69]
  PIN b[6]
    DIRECTION OUTPUT ;
    USE SIGNAL ;
    PORT
      LAYER M4 ;
        RECT  104.004 32.784 104.088 32.808 ;
    END
  END b[6]
  PIN b[70]
    DIRECTION OUTPUT ;
    USE SIGNAL ;
    PORT
      LAYER M4 ;
        RECT  104.004 26.64 104.088 26.664 ;
    END
  END b[70]
  PIN b[71]
    DIRECTION OUTPUT ;
    USE SIGNAL ;
    PORT
      LAYER M4 ;
        RECT  104.004 26.736 104.088 26.76 ;
    END
  END b[71]
  PIN b[72]
    DIRECTION OUTPUT ;
    USE SIGNAL ;
    PORT
      LAYER M4 ;
        RECT  104.004 26.832 104.088 26.856 ;
    END
  END b[72]
  PIN b[73]
    DIRECTION OUTPUT ;
    USE SIGNAL ;
    PORT
      LAYER M4 ;
        RECT  104.004 26.928 104.088 26.952 ;
    END
  END b[73]
  PIN b[74]
    DIRECTION OUTPUT ;
    USE SIGNAL ;
    PORT
      LAYER M4 ;
        RECT  104.004 27.024 104.088 27.048 ;
    END
  END b[74]
  PIN b[75]
    DIRECTION OUTPUT ;
    USE SIGNAL ;
    PORT
      LAYER M4 ;
        RECT  104.004 27.12 104.088 27.144 ;
    END
  END b[75]
  PIN b[76]
    DIRECTION OUTPUT ;
    USE SIGNAL ;
    PORT
      LAYER M4 ;
        RECT  104.004 27.216 104.088 27.24 ;
    END
  END b[76]
  PIN b[77]
    DIRECTION OUTPUT ;
    USE SIGNAL ;
    PORT
      LAYER M4 ;
        RECT  104.004 27.312 104.088 27.336 ;
    END
  END b[77]
  PIN b[78]
    DIRECTION OUTPUT ;
    USE SIGNAL ;
    PORT
      LAYER M4 ;
        RECT  104.004 27.408 104.088 27.432 ;
    END
  END b[78]
  PIN b[79]
    DIRECTION OUTPUT ;
    USE SIGNAL ;
    PORT
      LAYER M4 ;
        RECT  104.004 27.504 104.088 27.528 ;
    END
  END b[79]
  PIN b[7]
    DIRECTION OUTPUT ;
    USE SIGNAL ;
    PORT
      LAYER M4 ;
        RECT  104.004 32.88 104.088 32.904 ;
    END
  END b[7]
  PIN b[80]
    DIRECTION OUTPUT ;
    USE SIGNAL ;
    PORT
      LAYER M4 ;
        RECT  104.004 27.6 104.088 27.624 ;
    END
  END b[80]
  PIN b[81]
    DIRECTION OUTPUT ;
    USE SIGNAL ;
    PORT
      LAYER M4 ;
        RECT  104.004 27.696 104.088 27.72 ;
    END
  END b[81]
  PIN b[82]
    DIRECTION OUTPUT ;
    USE SIGNAL ;
    PORT
      LAYER M4 ;
        RECT  104.004 27.792 104.088 27.816 ;
    END
  END b[82]
  PIN b[83]
    DIRECTION OUTPUT ;
    USE SIGNAL ;
    PORT
      LAYER M4 ;
        RECT  104.004 27.888 104.088 27.912 ;
    END
  END b[83]
  PIN b[84]
    DIRECTION OUTPUT ;
    USE SIGNAL ;
    PORT
      LAYER M4 ;
        RECT  104.004 27.984 104.088 28.008 ;
    END
  END b[84]
  PIN b[85]
    DIRECTION OUTPUT ;
    USE SIGNAL ;
    PORT
      LAYER M4 ;
        RECT  104.004 28.08 104.088 28.104 ;
    END
  END b[85]
  PIN b[86]
    DIRECTION OUTPUT ;
    USE SIGNAL ;
    PORT
      LAYER M4 ;
        RECT  104.004 28.176 104.088 28.2 ;
    END
  END b[86]
  PIN b[87]
    DIRECTION OUTPUT ;
    USE SIGNAL ;
    PORT
      LAYER M4 ;
        RECT  104.004 28.272 104.088 28.296 ;
    END
  END b[87]
  PIN b[88]
    DIRECTION OUTPUT ;
    USE SIGNAL ;
    PORT
      LAYER M4 ;
        RECT  104.004 28.368 104.088 28.392 ;
    END
  END b[88]
  PIN b[89]
    DIRECTION OUTPUT ;
    USE SIGNAL ;
    PORT
      LAYER M4 ;
        RECT  104.004 28.464 104.088 28.488 ;
    END
  END b[89]
  PIN b[8]
    DIRECTION OUTPUT ;
    USE SIGNAL ;
    PORT
      LAYER M4 ;
        RECT  104.004 32.976 104.088 33 ;
    END
  END b[8]
  PIN b[90]
    DIRECTION OUTPUT ;
    USE SIGNAL ;
    PORT
      LAYER M4 ;
        RECT  104.004 28.56 104.088 28.584 ;
    END
  END b[90]
  PIN b[91]
    DIRECTION OUTPUT ;
    USE SIGNAL ;
    PORT
      LAYER M4 ;
        RECT  104.004 28.656 104.088 28.68 ;
    END
  END b[91]
  PIN b[92]
    DIRECTION OUTPUT ;
    USE SIGNAL ;
    PORT
      LAYER M4 ;
        RECT  104.004 28.752 104.088 28.776 ;
    END
  END b[92]
  PIN b[93]
    DIRECTION OUTPUT ;
    USE SIGNAL ;
    PORT
      LAYER M4 ;
        RECT  104.004 28.848 104.088 28.872 ;
    END
  END b[93]
  PIN b[94]
    DIRECTION OUTPUT ;
    USE SIGNAL ;
    PORT
      LAYER M4 ;
        RECT  104.004 28.944 104.088 28.968 ;
    END
  END b[94]
  PIN b[95]
    DIRECTION OUTPUT ;
    USE SIGNAL ;
    PORT
      LAYER M4 ;
        RECT  104.004 29.04 104.088 29.064 ;
    END
  END b[95]
  PIN b[96]
    DIRECTION OUTPUT ;
    USE SIGNAL ;
    PORT
      LAYER M4 ;
        RECT  104.004 22.992 104.088 23.016 ;
    END
  END b[96]
  PIN b[97]
    DIRECTION OUTPUT ;
    USE SIGNAL ;
    PORT
      LAYER M4 ;
        RECT  104.004 23.088 104.088 23.112 ;
    END
  END b[97]
  PIN b[98]
    DIRECTION OUTPUT ;
    USE SIGNAL ;
    PORT
      LAYER M4 ;
        RECT  104.004 23.184 104.088 23.208 ;
    END
  END b[98]
  PIN b[99]
    DIRECTION OUTPUT ;
    USE SIGNAL ;
    PORT
      LAYER M4 ;
        RECT  104.004 23.28 104.088 23.304 ;
    END
  END b[99]
  PIN b[9]
    DIRECTION OUTPUT ;
    USE SIGNAL ;
    PORT
      LAYER M4 ;
        RECT  104.004 33.072 104.088 33.096 ;
    END
  END b[9]
  PIN ck
    DIRECTION INPUT ;
    USE SIGNAL ;
    PORT
      LAYER M4 ;
        RECT  0 47.76 0.084 47.784 ;
    END
  END ck
  PIN ckf
    DIRECTION INPUT ;
    USE SIGNAL ;
    PORT
      LAYER M4 ;
        RECT  0 47.856 0.084 47.88 ;
    END
  END ckf
  PIN ea
    DIRECTION INPUT ;
    USE SIGNAL ;
    PORT
      LAYER M3 ;
        RECT  48.78 105.779 48.798 105.816 ;
    END
  END ea
  PIN fault
    DIRECTION OUTPUT ;
    USE SIGNAL ;
    PORT
      LAYER M4 ;
        RECT  0 47.952 0.084 47.976 ;
    END
  END fault
  PIN k0
    DIRECTION INPUT ;
    USE SIGNAL ;
    PORT
      LAYER M4 ;
        RECT  0 48.048 0.084 48.072 ;
    END
  END k0
  PIN k1
    DIRECTION INPUT ;
    USE SIGNAL ;
    PORT
      LAYER M4 ;
        RECT  0 48.144 0.084 48.168 ;
    END
  END k1
  PIN k2
    DIRECTION INPUT ;
    USE SIGNAL ;
    PORT
      LAYER M4 ;
        RECT  0 48.24 0.084 48.264 ;
    END
  END k2
  PIN rs
    DIRECTION INPUT ;
    USE SIGNAL ;
    PORT
      LAYER M4 ;
        RECT  0 48.336 0.084 48.36 ;
    END
  END rs
  PIN tie_hi
    DIRECTION OUTPUT ;
    USE SIGNAL ;
    PORT
      LAYER M4 ;
        RECT  0 48.432 0.084 48.456 ;
    END
  END tie_hi
  PIN tie_lo
    DIRECTION OUTPUT ;
    USE SIGNAL ;
    PORT
      LAYER M4 ;
        RECT  0 48.528 0.084 48.552 ;
    END
  END tie_lo
  PIN VDD
    DIRECTION INOUT ;
    USE POWER ;
    PORT
      LAYER M5 ;
        RECT  99.792 2.151 99.912 103.433 ;
        RECT  97.092 2.151 97.212 103.433 ;
        RECT  94.392 2.151 94.512 103.433 ;
        RECT  91.692 2.151 91.812 103.433 ;
        RECT  88.992 2.151 89.112 103.433 ;
        RECT  86.292 2.151 86.412 103.433 ;
        RECT  83.592 2.151 83.712 103.433 ;
        RECT  80.892 2.151 81.012 103.433 ;
        RECT  78.192 2.151 78.312 103.433 ;
        RECT  75.492 2.151 75.612 103.433 ;
        RECT  72.792 2.151 72.912 103.433 ;
        RECT  70.092 2.151 70.212 103.433 ;
        RECT  67.392 2.151 67.512 103.433 ;
        RECT  64.692 2.151 64.812 103.433 ;
        RECT  61.992 2.151 62.112 103.433 ;
        RECT  59.292 2.151 59.412 103.433 ;
        RECT  56.592 2.151 56.712 103.433 ;
        RECT  53.892 2.151 54.012 103.433 ;
        RECT  51.192 2.151 51.312 103.433 ;
        RECT  48.492 2.151 48.612 103.433 ;
        RECT  45.792 2.151 45.912 103.433 ;
        RECT  43.092 2.151 43.212 103.433 ;
        RECT  40.392 2.151 40.512 103.433 ;
        RECT  37.692 2.151 37.812 103.433 ;
        RECT  34.992 2.151 35.112 103.433 ;
        RECT  32.292 2.151 32.412 103.433 ;
        RECT  29.592 2.151 29.712 103.433 ;
        RECT  26.892 2.151 27.012 103.433 ;
        RECT  24.192 2.151 24.312 103.433 ;
        RECT  21.492 2.151 21.612 103.433 ;
        RECT  18.792 2.151 18.912 103.433 ;
        RECT  16.092 2.151 16.212 103.433 ;
        RECT  13.392 2.151 13.512 103.433 ;
        RECT  10.692 2.151 10.812 103.433 ;
        RECT  7.992 2.151 8.112 103.433 ;
        RECT  5.292 2.151 5.412 103.433 ;
        RECT  2.592 2.151 2.712 103.433 ;
    END
  END VDD
  PIN VSS
    DIRECTION INOUT ;
    USE GROUND ;
    PORT
      LAYER M5 ;
        RECT  99.6 2.137 99.72 103.419 ;
        RECT  96.9 2.137 97.02 103.419 ;
        RECT  94.2 2.137 94.32 103.419 ;
        RECT  91.5 2.137 91.62 103.419 ;
        RECT  88.8 2.137 88.92 103.419 ;
        RECT  86.1 2.137 86.22 103.419 ;
        RECT  83.4 2.137 83.52 103.419 ;
        RECT  80.7 2.137 80.82 103.419 ;
        RECT  78 2.137 78.12 103.419 ;
        RECT  75.3 2.137 75.42 103.419 ;
        RECT  72.6 2.137 72.72 103.419 ;
        RECT  69.9 2.137 70.02 103.419 ;
        RECT  67.2 2.137 67.32 103.419 ;
        RECT  64.5 2.137 64.62 103.419 ;
        RECT  61.8 2.137 61.92 103.419 ;
        RECT  59.1 2.137 59.22 103.419 ;
        RECT  56.4 2.137 56.52 103.419 ;
        RECT  53.7 2.137 53.82 103.419 ;
        RECT  51 2.137 51.12 103.419 ;
        RECT  48.3 2.137 48.42 103.419 ;
        RECT  45.6 2.137 45.72 103.419 ;
        RECT  42.9 2.137 43.02 103.419 ;
        RECT  40.2 2.137 40.32 103.419 ;
        RECT  37.5 2.137 37.62 103.419 ;
        RECT  34.8 2.137 34.92 103.419 ;
        RECT  32.1 2.137 32.22 103.419 ;
        RECT  29.4 2.137 29.52 103.419 ;
        RECT  26.7 2.137 26.82 103.419 ;
        RECT  24 2.137 24.12 103.419 ;
        RECT  21.3 2.137 21.42 103.419 ;
        RECT  18.6 2.137 18.72 103.419 ;
        RECT  15.9 2.137 16.02 103.419 ;
        RECT  13.2 2.137 13.32 103.419 ;
        RECT  10.5 2.137 10.62 103.419 ;
        RECT  7.8 2.137 7.92 103.419 ;
        RECT  5.1 2.137 5.22 103.419 ;
        RECT  2.4 2.137 2.52 103.419 ;
    END
  END VSS
  OBS
    LAYER RVTN ;
     RECT  2.16 2.16 101.898 2.295 ;
     RECT  2.16 2.565 101.898 2.835 ;
     RECT  2.16 3.105 101.898 3.375 ;
     RECT  2.16 3.645 101.898 3.915 ;
     RECT  2.16 4.185 101.898 4.455 ;
     RECT  2.16 4.725 101.898 4.995 ;
     RECT  2.16 5.265 101.898 5.535 ;
     RECT  2.16 5.805 101.898 6.075 ;
     RECT  2.16 6.345 101.898 6.615 ;
     RECT  2.16 6.885 101.898 7.155 ;
     RECT  2.16 7.425 101.898 7.695 ;
     RECT  2.16 7.965 101.898 8.235 ;
     RECT  2.16 8.505 101.898 8.775 ;
     RECT  2.16 9.045 101.898 9.315 ;
     RECT  2.16 9.585 101.898 9.855 ;
     RECT  2.16 10.125 101.898 10.395 ;
     RECT  2.16 10.665 101.898 10.935 ;
     RECT  2.16 11.205 101.898 11.475 ;
     RECT  2.16 11.745 101.898 12.015 ;
     RECT  2.16 12.285 101.898 12.555 ;
     RECT  2.16 12.825 101.898 13.095 ;
     RECT  2.16 13.365 101.898 13.635 ;
     RECT  2.16 13.905 101.898 14.175 ;
     RECT  2.16 14.445 101.898 14.715 ;
     RECT  2.16 14.985 101.898 15.255 ;
     RECT  2.16 15.525 101.898 15.795 ;
     RECT  2.16 16.065 101.898 16.335 ;
     RECT  2.16 16.605 101.898 16.875 ;
     RECT  2.16 17.145 101.898 17.415 ;
     RECT  2.16 17.685 101.898 17.955 ;
     RECT  2.16 18.225 101.898 18.495 ;
     RECT  2.16 18.765 101.898 19.035 ;
     RECT  2.16 19.305 101.898 19.575 ;
     RECT  2.16 19.845 101.898 20.115 ;
     RECT  2.16 20.385 101.898 20.655 ;
     RECT  2.16 20.925 101.898 21.195 ;
     RECT  2.16 21.465 101.898 21.735 ;
     RECT  2.16 22.005 101.898 22.275 ;
     RECT  2.16 22.545 101.898 22.815 ;
     RECT  2.16 23.085 101.898 23.355 ;
     RECT  2.16 23.625 101.898 23.895 ;
     RECT  2.16 24.165 101.898 24.435 ;
     RECT  2.16 24.705 101.898 24.975 ;
     RECT  2.16 25.245 101.898 25.515 ;
     RECT  2.16 25.785 101.898 26.055 ;
     RECT  2.16 26.325 101.898 26.595 ;
     RECT  2.16 26.865 101.898 27.135 ;
     RECT  2.16 27.405 101.898 27.675 ;
     RECT  2.16 27.945 101.898 28.215 ;
     RECT  2.16 28.485 101.898 28.755 ;
     RECT  2.16 29.025 101.898 29.295 ;
     RECT  2.16 29.565 101.898 29.835 ;
     RECT  2.16 30.105 101.898 30.375 ;
     RECT  2.16 30.645 101.898 30.915 ;
     RECT  2.16 31.185 101.898 31.455 ;
     RECT  2.16 31.725 101.898 31.995 ;
     RECT  2.16 32.265 101.898 32.535 ;
     RECT  2.16 32.805 101.898 33.075 ;
     RECT  2.16 33.345 101.898 33.615 ;
     RECT  2.16 33.885 101.898 34.155 ;
     RECT  2.16 34.425 101.898 34.695 ;
     RECT  2.16 34.965 101.898 35.235 ;
     RECT  2.16 35.505 101.898 35.775 ;
     RECT  2.16 36.045 101.898 36.315 ;
     RECT  2.16 36.585 101.898 36.855 ;
     RECT  2.16 37.125 101.898 37.395 ;
     RECT  2.16 37.665 101.898 37.935 ;
     RECT  2.16 38.205 101.898 38.475 ;
     RECT  2.16 38.745 101.898 39.015 ;
     RECT  2.16 39.285 101.898 39.555 ;
     RECT  2.16 39.825 101.898 40.095 ;
     RECT  2.16 40.365 101.898 40.635 ;
     RECT  2.16 40.905 101.898 41.175 ;
     RECT  2.16 41.445 101.898 41.715 ;
     RECT  2.16 41.985 101.898 42.255 ;
     RECT  2.16 42.525 101.898 42.795 ;
     RECT  2.16 43.065 101.898 43.335 ;
     RECT  2.16 43.605 101.898 43.875 ;
     RECT  2.16 44.145 101.898 44.415 ;
     RECT  2.16 44.685 101.898 44.955 ;
     RECT  2.16 45.225 101.898 45.495 ;
     RECT  2.16 45.765 101.898 46.035 ;
     RECT  2.16 46.305 101.898 46.575 ;
     RECT  2.16 46.845 101.898 47.115 ;
     RECT  2.16 47.385 101.898 47.655 ;
     RECT  2.16 47.925 101.898 48.195 ;
     RECT  2.16 48.465 101.898 48.735 ;
     RECT  2.16 49.005 101.898 49.275 ;
     RECT  2.16 49.545 101.898 49.815 ;
     RECT  2.16 50.085 101.898 50.355 ;
     RECT  2.16 50.625 101.898 50.895 ;
     RECT  2.16 51.165 101.898 51.435 ;
     RECT  2.16 51.705 101.898 51.975 ;
     RECT  2.16 52.245 101.898 52.515 ;
     RECT  2.16 52.785 101.898 53.055 ;
     RECT  2.16 53.325 101.898 53.595 ;
     RECT  2.16 53.865 101.898 54.135 ;
     RECT  2.16 54.405 101.898 54.675 ;
     RECT  2.16 54.945 101.898 55.215 ;
     RECT  2.16 55.485 101.898 55.755 ;
     RECT  2.16 56.025 101.898 56.295 ;
     RECT  2.16 56.565 101.898 56.835 ;
     RECT  2.16 57.105 101.898 57.375 ;
     RECT  2.16 57.645 101.898 57.915 ;
     RECT  2.16 58.185 101.898 58.455 ;
     RECT  2.16 58.725 101.898 58.995 ;
     RECT  2.16 59.265 101.898 59.535 ;
     RECT  2.16 59.805 101.898 60.075 ;
     RECT  2.16 60.345 101.898 60.615 ;
     RECT  2.16 60.885 101.898 61.155 ;
     RECT  2.16 61.425 101.898 61.695 ;
     RECT  2.16 61.965 101.898 62.235 ;
     RECT  2.16 62.505 101.898 62.775 ;
     RECT  2.16 63.045 101.898 63.315 ;
     RECT  2.16 63.585 101.898 63.855 ;
     RECT  2.16 64.125 101.898 64.395 ;
     RECT  2.16 64.665 101.898 64.935 ;
     RECT  2.16 65.205 101.898 65.475 ;
     RECT  2.16 65.745 101.898 66.015 ;
     RECT  2.16 66.285 101.898 66.555 ;
     RECT  2.16 66.825 101.898 67.095 ;
     RECT  2.16 67.365 101.898 67.635 ;
     RECT  2.16 67.905 101.898 68.175 ;
     RECT  2.16 68.445 101.898 68.715 ;
     RECT  2.16 68.985 101.898 69.255 ;
     RECT  2.16 69.525 101.898 69.795 ;
     RECT  2.16 70.065 101.898 70.335 ;
     RECT  2.16 70.605 101.898 70.875 ;
     RECT  2.16 71.145 101.898 71.415 ;
     RECT  2.16 71.685 101.898 71.955 ;
     RECT  2.16 72.225 101.898 72.495 ;
     RECT  2.16 72.765 101.898 73.035 ;
     RECT  2.16 73.305 101.898 73.575 ;
     RECT  2.16 73.845 101.898 74.115 ;
     RECT  2.16 74.385 101.898 74.655 ;
     RECT  2.16 74.925 101.898 75.195 ;
     RECT  2.16 75.465 101.898 75.735 ;
     RECT  2.16 76.005 101.898 76.275 ;
     RECT  2.16 76.545 101.898 76.815 ;
     RECT  2.16 77.085 101.898 77.355 ;
     RECT  2.16 77.625 101.898 77.895 ;
     RECT  2.16 78.165 101.898 78.435 ;
     RECT  2.16 78.705 101.898 78.975 ;
     RECT  2.16 79.245 101.898 79.515 ;
     RECT  2.16 79.785 101.898 80.055 ;
     RECT  2.16 80.325 101.898 80.595 ;
     RECT  2.16 80.865 101.898 81.135 ;
     RECT  2.16 81.405 101.898 81.675 ;
     RECT  2.16 81.945 101.898 82.215 ;
     RECT  2.16 82.485 101.898 82.755 ;
     RECT  2.16 83.025 101.898 83.295 ;
     RECT  2.16 83.565 101.898 83.835 ;
     RECT  2.16 84.105 101.898 84.375 ;
     RECT  2.16 84.645 101.898 84.915 ;
     RECT  2.16 85.185 101.898 85.455 ;
     RECT  2.16 85.725 101.898 85.995 ;
     RECT  2.16 86.265 101.898 86.535 ;
     RECT  2.16 86.805 101.898 87.075 ;
     RECT  2.16 87.345 101.898 87.615 ;
     RECT  2.16 87.885 101.898 88.155 ;
     RECT  2.16 88.425 101.898 88.695 ;
     RECT  2.16 88.965 101.898 89.235 ;
     RECT  2.16 89.505 101.898 89.775 ;
     RECT  2.16 90.045 101.898 90.315 ;
     RECT  2.16 90.585 101.898 90.855 ;
     RECT  2.16 91.125 101.898 91.395 ;
     RECT  2.16 91.665 101.898 91.935 ;
     RECT  2.16 92.205 101.898 92.475 ;
     RECT  2.16 92.745 101.898 93.015 ;
     RECT  2.16 93.285 101.898 93.555 ;
     RECT  2.16 93.825 101.898 94.095 ;
     RECT  2.16 94.365 101.898 94.635 ;
     RECT  2.16 94.905 101.898 95.175 ;
     RECT  2.16 95.445 101.898 95.715 ;
     RECT  2.16 95.985 101.898 96.255 ;
     RECT  2.16 96.525 101.898 96.795 ;
     RECT  2.16 97.065 101.898 97.335 ;
     RECT  2.16 97.605 101.898 97.875 ;
     RECT  2.16 98.145 101.898 98.415 ;
     RECT  2.16 98.685 101.898 98.955 ;
     RECT  2.16 99.225 101.898 99.495 ;
     RECT  2.16 99.765 101.898 100.035 ;
     RECT  2.16 100.305 101.898 100.575 ;
     RECT  2.16 100.845 101.898 101.115 ;
     RECT  2.16 101.385 101.898 101.655 ;
     RECT  2.16 101.925 101.898 102.195 ;
     RECT  2.16 102.465 101.898 102.735 ;
     RECT  2.16 103.005 101.898 103.275 ;
    LAYER RVTP ;
     RECT  2.16 2.295 101.898 2.565 ;
     RECT  2.16 2.835 101.898 3.105 ;
     RECT  2.16 3.375 101.898 3.645 ;
     RECT  2.16 3.915 101.898 4.185 ;
     RECT  2.16 4.455 101.898 4.725 ;
     RECT  2.16 4.995 101.898 5.265 ;
     RECT  2.16 5.535 101.898 5.805 ;
     RECT  2.16 6.075 101.898 6.345 ;
     RECT  2.16 6.615 101.898 6.885 ;
     RECT  2.16 7.155 101.898 7.425 ;
     RECT  2.16 7.695 101.898 7.965 ;
     RECT  2.16 8.235 101.898 8.505 ;
     RECT  2.16 8.775 101.898 9.045 ;
     RECT  2.16 9.315 101.898 9.585 ;
     RECT  2.16 9.855 101.898 10.125 ;
     RECT  2.16 10.395 101.898 10.665 ;
     RECT  2.16 10.935 101.898 11.205 ;
     RECT  2.16 11.475 101.898 11.745 ;
     RECT  2.16 12.015 101.898 12.285 ;
     RECT  2.16 12.555 101.898 12.825 ;
     RECT  2.16 13.095 101.898 13.365 ;
     RECT  2.16 13.635 101.898 13.905 ;
     RECT  2.16 14.175 101.898 14.445 ;
     RECT  2.16 14.715 101.898 14.985 ;
     RECT  2.16 15.255 101.898 15.525 ;
     RECT  2.16 15.795 101.898 16.065 ;
     RECT  2.16 16.335 101.898 16.605 ;
     RECT  2.16 16.875 101.898 17.145 ;
     RECT  2.16 17.415 101.898 17.685 ;
     RECT  2.16 17.955 101.898 18.225 ;
     RECT  2.16 18.495 101.898 18.765 ;
     RECT  2.16 19.035 101.898 19.305 ;
     RECT  2.16 19.575 101.898 19.845 ;
     RECT  2.16 20.115 101.898 20.385 ;
     RECT  2.16 20.655 101.898 20.925 ;
     RECT  2.16 21.195 101.898 21.465 ;
     RECT  2.16 21.735 101.898 22.005 ;
     RECT  2.16 22.275 101.898 22.545 ;
     RECT  2.16 22.815 101.898 23.085 ;
     RECT  2.16 23.355 101.898 23.625 ;
     RECT  2.16 23.895 101.898 24.165 ;
     RECT  2.16 24.435 101.898 24.705 ;
     RECT  2.16 24.975 101.898 25.245 ;
     RECT  2.16 25.515 101.898 25.785 ;
     RECT  2.16 26.055 101.898 26.325 ;
     RECT  2.16 26.595 101.898 26.865 ;
     RECT  2.16 27.135 101.898 27.405 ;
     RECT  2.16 27.675 101.898 27.945 ;
     RECT  2.16 28.215 101.898 28.485 ;
     RECT  2.16 28.755 101.898 29.025 ;
     RECT  2.16 29.295 101.898 29.565 ;
     RECT  2.16 29.835 101.898 30.105 ;
     RECT  2.16 30.375 101.898 30.645 ;
     RECT  2.16 30.915 101.898 31.185 ;
     RECT  2.16 31.455 101.898 31.725 ;
     RECT  2.16 31.995 101.898 32.265 ;
     RECT  2.16 32.535 101.898 32.805 ;
     RECT  2.16 33.075 101.898 33.345 ;
     RECT  2.16 33.615 101.898 33.885 ;
     RECT  2.16 34.155 101.898 34.425 ;
     RECT  2.16 34.695 101.898 34.965 ;
     RECT  2.16 35.235 101.898 35.505 ;
     RECT  2.16 35.775 101.898 36.045 ;
     RECT  2.16 36.315 101.898 36.585 ;
     RECT  2.16 36.855 101.898 37.125 ;
     RECT  2.16 37.395 101.898 37.665 ;
     RECT  2.16 37.935 101.898 38.205 ;
     RECT  2.16 38.475 101.898 38.745 ;
     RECT  2.16 39.015 101.898 39.285 ;
     RECT  2.16 39.555 101.898 39.825 ;
     RECT  2.16 40.095 101.898 40.365 ;
     RECT  2.16 40.635 101.898 40.905 ;
     RECT  2.16 41.175 101.898 41.445 ;
     RECT  2.16 41.715 101.898 41.985 ;
     RECT  2.16 42.255 101.898 42.525 ;
     RECT  2.16 42.795 101.898 43.065 ;
     RECT  2.16 43.335 101.898 43.605 ;
     RECT  2.16 43.875 101.898 44.145 ;
     RECT  2.16 44.415 101.898 44.685 ;
     RECT  2.16 44.955 101.898 45.225 ;
     RECT  2.16 45.495 101.898 45.765 ;
     RECT  2.16 46.035 101.898 46.305 ;
     RECT  2.16 46.575 101.898 46.845 ;
     RECT  2.16 47.115 101.898 47.385 ;
     RECT  2.16 47.655 101.898 47.925 ;
     RECT  2.16 48.195 101.898 48.465 ;
     RECT  2.16 48.735 101.898 49.005 ;
     RECT  2.16 49.275 101.898 49.545 ;
     RECT  2.16 49.815 101.898 50.085 ;
     RECT  2.16 50.355 101.898 50.625 ;
     RECT  2.16 50.895 101.898 51.165 ;
     RECT  2.16 51.435 101.898 51.705 ;
     RECT  2.16 51.975 101.898 52.245 ;
     RECT  2.16 52.515 101.898 52.785 ;
     RECT  2.16 53.055 101.898 53.325 ;
     RECT  2.16 53.595 101.898 53.865 ;
     RECT  2.16 54.135 101.898 54.405 ;
     RECT  2.16 54.675 101.898 54.945 ;
     RECT  2.16 55.215 101.898 55.485 ;
     RECT  2.16 55.755 101.898 56.025 ;
     RECT  2.16 56.295 101.898 56.565 ;
     RECT  2.16 56.835 101.898 57.105 ;
     RECT  2.16 57.375 101.898 57.645 ;
     RECT  2.16 57.915 101.898 58.185 ;
     RECT  2.16 58.455 101.898 58.725 ;
     RECT  2.16 58.995 101.898 59.265 ;
     RECT  2.16 59.535 101.898 59.805 ;
     RECT  2.16 60.075 101.898 60.345 ;
     RECT  2.16 60.615 101.898 60.885 ;
     RECT  2.16 61.155 101.898 61.425 ;
     RECT  2.16 61.695 101.898 61.965 ;
     RECT  2.16 62.235 101.898 62.505 ;
     RECT  2.16 62.775 101.898 63.045 ;
     RECT  2.16 63.315 101.898 63.585 ;
     RECT  2.16 63.855 101.898 64.125 ;
     RECT  2.16 64.395 101.898 64.665 ;
     RECT  2.16 64.935 101.898 65.205 ;
     RECT  2.16 65.475 101.898 65.745 ;
     RECT  2.16 66.015 101.898 66.285 ;
     RECT  2.16 66.555 101.898 66.825 ;
     RECT  2.16 67.095 101.898 67.365 ;
     RECT  2.16 67.635 101.898 67.905 ;
     RECT  2.16 68.175 101.898 68.445 ;
     RECT  2.16 68.715 101.898 68.985 ;
     RECT  2.16 69.255 101.898 69.525 ;
     RECT  2.16 69.795 101.898 70.065 ;
     RECT  2.16 70.335 101.898 70.605 ;
     RECT  2.16 70.875 101.898 71.145 ;
     RECT  2.16 71.415 101.898 71.685 ;
     RECT  2.16 71.955 101.898 72.225 ;
     RECT  2.16 72.495 101.898 72.765 ;
     RECT  2.16 73.035 101.898 73.305 ;
     RECT  2.16 73.575 101.898 73.845 ;
     RECT  2.16 74.115 101.898 74.385 ;
     RECT  2.16 74.655 101.898 74.925 ;
     RECT  2.16 75.195 101.898 75.465 ;
     RECT  2.16 75.735 101.898 76.005 ;
     RECT  2.16 76.275 101.898 76.545 ;
     RECT  2.16 76.815 101.898 77.085 ;
     RECT  2.16 77.355 101.898 77.625 ;
     RECT  2.16 77.895 101.898 78.165 ;
     RECT  2.16 78.435 101.898 78.705 ;
     RECT  2.16 78.975 101.898 79.245 ;
     RECT  2.16 79.515 101.898 79.785 ;
     RECT  2.16 80.055 101.898 80.325 ;
     RECT  2.16 80.595 101.898 80.865 ;
     RECT  2.16 81.135 101.898 81.405 ;
     RECT  2.16 81.675 101.898 81.945 ;
     RECT  2.16 82.215 101.898 82.485 ;
     RECT  2.16 82.755 101.898 83.025 ;
     RECT  2.16 83.295 101.898 83.565 ;
     RECT  2.16 83.835 101.898 84.105 ;
     RECT  2.16 84.375 101.898 84.645 ;
     RECT  2.16 84.915 101.898 85.185 ;
     RECT  2.16 85.455 101.898 85.725 ;
     RECT  2.16 85.995 101.898 86.265 ;
     RECT  2.16 86.535 101.898 86.805 ;
     RECT  2.16 87.075 101.898 87.345 ;
     RECT  2.16 87.615 101.898 87.885 ;
     RECT  2.16 88.155 101.898 88.425 ;
     RECT  2.16 88.695 101.898 88.965 ;
     RECT  2.16 89.235 101.898 89.505 ;
     RECT  2.16 89.775 101.898 90.045 ;
     RECT  2.16 90.315 101.898 90.585 ;
     RECT  2.16 90.855 101.898 91.125 ;
     RECT  2.16 91.395 101.898 91.665 ;
     RECT  2.16 91.935 101.898 92.205 ;
     RECT  2.16 92.475 101.898 92.745 ;
     RECT  2.16 93.015 101.898 93.285 ;
     RECT  2.16 93.555 101.898 93.825 ;
     RECT  2.16 94.095 101.898 94.365 ;
     RECT  2.16 94.635 101.898 94.905 ;
     RECT  2.16 95.175 101.898 95.445 ;
     RECT  2.16 95.715 101.898 95.985 ;
     RECT  2.16 96.255 101.898 96.525 ;
     RECT  2.16 96.795 101.898 97.065 ;
     RECT  2.16 97.335 101.898 97.605 ;
     RECT  2.16 97.875 101.898 98.145 ;
     RECT  2.16 98.415 101.898 98.685 ;
     RECT  2.16 98.955 101.898 99.225 ;
     RECT  2.16 99.495 101.898 99.765 ;
     RECT  2.16 100.035 101.898 100.305 ;
     RECT  2.16 100.575 101.898 100.845 ;
     RECT  2.16 101.115 101.898 101.385 ;
     RECT  2.16 101.655 101.898 101.925 ;
     RECT  2.16 102.195 101.898 102.465 ;
     RECT  2.16 102.735 101.898 103.005 ;
     RECT  2.16 103.275 101.898 103.41 ;
    LAYER M1 ;
     RECT  2.16 2.151 101.898 103.419 ;
    LAYER M2 ;
     RECT  0.103 48.546 0.139 48.564 ;
     RECT  0.139 48.546 2.16 49.104 ;
     RECT  25.231 105.75 25.295 105.768 ;
     RECT  25.303 105.678 25.367 105.696 ;
     RECT  26.887 105.75 26.959 105.768 ;
     RECT  26.959 105.516 27.131 105.768 ;
     RECT  27.131 105.606 27.203 105.768 ;
     RECT  27.203 105.642 27.967 105.768 ;
     RECT  27.967 105.606 28.067 105.768 ;
     RECT  28.067 105.678 28.211 105.768 ;
     RECT  28.211 105.714 28.319 105.768 ;
     RECT  28.319 105.75 28.391 105.768 ;
     RECT  2.16 2.151 35.311 103.419 ;
     RECT  35.311 2.151 37.139 103.464 ;
     RECT  40.495 105.75 40.567 105.768 ;
     RECT  40.567 105.678 40.855 105.768 ;
     RECT  40.855 105.606 40.955 105.768 ;
     RECT  40.955 105.642 41.683 105.768 ;
     RECT  41.683 105.408 41.827 105.768 ;
     RECT  41.827 105.408 42.179 105.804 ;
     RECT  42.871 104.292 43.015 104.31 ;
     RECT  43.015 104.211 43.087 104.31 ;
     RECT  43.087 104.211 43.159 104.724 ;
     RECT  37.139 2.151 43.231 103.419 ;
     RECT  43.159 104.166 43.231 104.724 ;
     RECT  42.179 105.516 43.411 105.804 ;
     RECT  43.231 2.151 43.663 104.724 ;
     RECT  43.411 105.48 43.663 105.804 ;
     RECT  43.663 2.151 44.663 105.804 ;
     RECT  44.663 105.642 44.735 105.804 ;
     RECT  44.663 2.151 45.059 104.886 ;
     RECT  45.059 2.151 45.275 104.724 ;
     RECT  44.735 105.75 45.311 105.804 ;
     RECT  45.275 104.292 46.283 104.724 ;
     RECT  45.311 105.75 46.571 105.768 ;
     RECT  46.283 104.706 46.679 104.724 ;
     RECT  47.119 104.796 47.219 104.814 ;
     RECT  47.407 105.606 47.911 105.624 ;
     RECT  47.911 105.561 47.983 105.624 ;
     RECT  47.983 105.561 48.083 105.66 ;
     RECT  48.083 105.642 48.191 105.66 ;
     RECT  48.631 105.75 48.947 105.768 ;
     RECT  48.703 104.292 49.379 104.31 ;
     RECT  50.863 105.75 51.295 105.768 ;
     RECT  51.295 105.678 51.511 105.768 ;
     RECT  51.511 105.606 52.159 105.768 ;
     RECT  52.159 105.174 52.259 105.768 ;
     RECT  45.275 2.151 52.663 103.419 ;
     RECT  52.259 105.606 52.943 105.768 ;
     RECT  52.663 2.151 53.267 103.734 ;
     RECT  52.943 105.606 53.339 105.624 ;
     RECT  53.267 2.151 55.399 103.419 ;
     RECT  55.399 2.151 56.363 103.536 ;
     RECT  56.363 2.151 58.639 103.464 ;
     RECT  58.639 2.151 58.711 103.572 ;
     RECT  58.711 2.151 59.827 103.608 ;
     RECT  59.827 2.151 60.827 104.31 ;
     RECT  60.827 2.151 61.007 103.608 ;
     RECT  61.007 2.151 61.115 103.572 ;
     RECT  61.115 2.151 61.951 103.5 ;
     RECT  61.951 2.151 62.051 103.734 ;
     RECT  62.239 105.606 62.339 105.624 ;
     RECT  62.527 105.561 62.627 105.579 ;
     RECT  62.051 2.151 62.815 103.464 ;
     RECT  63.139 105.75 63.275 105.768 ;
     RECT  63.535 105.606 63.851 105.624 ;
     RECT  64.687 104.598 64.831 104.616 ;
     RECT  64.399 105.561 64.831 105.579 ;
     RECT  64.831 104.598 64.931 105.579 ;
     RECT  64.931 105.372 64.975 105.579 ;
     RECT  64.975 105.372 65.047 105.696 ;
     RECT  65.047 105.372 65.111 105.768 ;
     RECT  65.111 105.444 65.183 105.768 ;
     RECT  62.815 2.151 65.327 103.536 ;
     RECT  65.183 105.444 65.947 105.732 ;
     RECT  65.327 2.151 66.703 103.419 ;
     RECT  65.947 105.444 66.983 105.804 ;
     RECT  66.983 105.516 67.091 105.804 ;
     RECT  66.703 2.151 67.559 103.464 ;
     RECT  67.091 105.561 67.927 105.804 ;
     RECT  67.927 105.48 68.099 105.804 ;
     RECT  68.099 105.786 69.295 105.804 ;
     RECT  69.295 105.75 69.331 105.804 ;
     RECT  67.559 2.151 69.511 103.419 ;
     RECT  69.331 105.678 69.539 105.804 ;
     RECT  69.511 2.151 70.087 103.464 ;
     RECT  64.931 104.598 70.087 104.616 ;
     RECT  69.539 105.786 70.403 105.804 ;
     RECT  70.087 2.151 70.547 104.616 ;
     RECT  70.547 2.151 73.031 104.04 ;
     RECT  73.031 2.151 74.687 103.734 ;
     RECT  74.687 2.151 76.631 103.689 ;
     RECT  76.631 2.151 77.279 103.644 ;
     RECT  77.279 2.151 79.835 103.464 ;
     RECT  79.835 2.151 101.898 103.419 ;
     RECT  101.898 60.696 101.975 74.304 ;
     RECT  101.898 41.796 102.047 57.402 ;
     RECT  101.898 19.386 102.083 38.934 ;
     RECT  102.047 41.886 102.587 57.402 ;
     RECT  101.898 77.166 102.587 90.504 ;
     RECT  102.083 19.584 102.623 38.934 ;
     RECT  102.587 41.958 102.623 57.402 ;
     RECT  101.975 60.696 102.623 74.034 ;
     RECT  102.587 81.684 102.623 90.504 ;
     RECT  102.623 23.634 102.659 24.354 ;
     RECT  102.623 29.466 102.659 33.174 ;
     RECT  102.623 34.056 102.659 38.934 ;
     RECT  102.623 47.736 102.659 57.402 ;
     RECT  102.623 60.696 102.659 66.384 ;
     RECT  102.623 67.446 102.659 69.624 ;
     RECT  102.587 77.166 102.659 80.928 ;
     RECT  102.623 82.836 102.659 85.284 ;
     RECT  102.659 29.808 102.695 33.174 ;
     RECT  102.659 50.634 102.695 51.354 ;
     RECT  102.659 55.296 102.695 55.404 ;
     RECT  102.659 61.056 102.695 63.774 ;
     RECT  102.659 67.446 102.695 69.012 ;
     RECT  102.659 77.364 102.695 80.928 ;
     RECT  102.623 87.93 102.695 90.234 ;
     RECT  102.659 56.268 102.731 57.204 ;
     RECT  102.623 71.496 102.731 74.034 ;
     RECT  102.731 71.496 102.767 73.944 ;
     RECT  102.659 38.214 103.163 38.934 ;
     RECT  102.695 77.364 103.163 79.704 ;
     RECT  102.623 19.584 103.199 22.734 ;
     RECT  102.659 24.336 103.199 24.354 ;
     RECT  102.623 25.254 103.199 28.584 ;
     RECT  102.695 29.808 103.199 30.096 ;
     RECT  102.695 31.266 103.199 33.174 ;
     RECT  102.659 34.056 103.199 37.044 ;
     RECT  103.163 38.214 103.199 38.304 ;
     RECT  102.623 41.994 103.199 46.944 ;
     RECT  102.659 47.736 103.199 49.878 ;
     RECT  102.695 51.246 103.199 51.354 ;
     RECT  102.659 53.37 103.199 54.468 ;
     RECT  102.695 55.296 103.199 55.314 ;
     RECT  102.731 56.268 103.199 56.394 ;
     RECT  102.731 57.15 103.199 57.204 ;
     RECT  102.695 61.128 103.199 63.648 ;
     RECT  102.659 65.016 103.199 66.384 ;
     RECT  102.695 67.446 103.199 68.004 ;
     RECT  102.695 68.994 103.199 69.012 ;
     RECT  102.623 70.686 103.199 70.704 ;
     RECT  102.767 71.496 103.199 73.872 ;
     RECT  103.163 77.364 103.199 78.39 ;
     RECT  103.163 79.146 103.199 79.704 ;
     RECT  102.695 80.568 103.199 80.928 ;
     RECT  102.623 81.684 103.199 81.702 ;
     RECT  102.659 82.836 103.199 83.394 ;
     RECT  102.659 84.456 103.199 84.672 ;
     RECT  102.623 86.31 103.199 87.138 ;
     RECT  102.695 87.93 103.199 87.948 ;
     RECT  102.695 88.776 103.199 89.802 ;
     RECT  103.199 20.16 103.235 22.302 ;
     RECT  103.199 26.37 103.235 26.964 ;
     RECT  103.199 28.026 103.235 28.044 ;
     RECT  103.199 29.808 103.235 29.826 ;
     RECT  103.199 32.616 103.235 32.634 ;
     RECT  103.199 34.236 103.235 34.254 ;
     RECT  103.199 35.586 103.235 37.044 ;
     RECT  103.199 38.214 103.235 38.268 ;
     RECT  103.199 41.994 103.235 42.984 ;
     RECT  103.199 43.848 103.235 44.91 ;
     RECT  103.199 47.898 103.235 47.952 ;
     RECT  103.199 49.356 103.235 49.374 ;
     RECT  103.199 51.246 103.235 51.264 ;
     RECT  103.199 53.874 103.235 53.892 ;
     RECT  103.199 56.268 103.235 56.286 ;
     RECT  103.199 61.776 103.235 62.262 ;
     RECT  103.199 71.964 103.235 71.982 ;
     RECT  103.199 72.846 103.235 73.674 ;
     RECT  103.199 77.634 103.235 77.652 ;
     RECT  103.199 79.218 103.235 79.704 ;
     RECT  103.199 86.886 103.235 86.904 ;
     RECT  103.199 88.776 103.235 88.794 ;
     RECT  103.235 20.466 103.271 20.484 ;
     RECT  103.235 36.486 103.271 37.044 ;
     RECT  103.235 38.25 103.271 38.268 ;
     RECT  103.235 42.156 103.271 42.48 ;
     RECT  103.235 44.226 103.271 44.244 ;
     RECT  103.199 57.186 103.271 57.204 ;
     RECT  103.235 61.974 103.271 62.262 ;
     RECT  103.235 73.548 103.271 73.674 ;
     RECT  103.199 89.55 103.271 89.766 ;
     RECT  103.271 37.026 103.307 37.044 ;
     RECT  103.235 47.898 103.307 47.916 ;
     RECT  103.271 73.548 103.307 73.566 ;
     RECT  103.271 89.55 103.307 89.568 ;
     RECT  103.235 22.284 103.963 22.302 ;
     RECT  103.235 26.766 103.991 26.784 ;
     RECT  103.271 42.462 103.991 42.48 ;
     RECT  103.271 62.244 103.991 62.262 ;
     RECT  103.963 22.284 104.063 22.842 ;
    LAYER M3 ;
     RECT  2.415 2.143 2.505 2.413 ;
     RECT  5.115 2.143 5.205 2.413 ;
     RECT  7.815 2.143 7.905 2.413 ;
     RECT  10.515 2.143 10.605 2.413 ;
     RECT  13.215 2.143 13.305 2.413 ;
     RECT  15.915 2.143 16.005 2.413 ;
     RECT  18.615 2.143 18.705 2.413 ;
     RECT  21.315 2.143 21.405 2.413 ;
     RECT  24.015 2.143 24.105 2.413 ;
     RECT  26.715 2.143 26.805 2.413 ;
     RECT  29.415 2.143 29.505 2.413 ;
     RECT  32.115 2.143 32.205 2.413 ;
     RECT  34.815 2.143 34.905 2.413 ;
     RECT  37.515 2.143 37.605 2.413 ;
     RECT  40.215 2.143 40.305 2.413 ;
     RECT  42.915 2.143 43.005 2.413 ;
     RECT  45.615 2.143 45.705 2.413 ;
     RECT  48.315 2.143 48.405 2.413 ;
     RECT  51.015 2.143 51.105 2.413 ;
     RECT  53.715 2.143 53.805 2.413 ;
     RECT  56.415 2.143 56.505 2.413 ;
     RECT  59.115 2.143 59.205 2.413 ;
     RECT  61.815 2.143 61.905 2.413 ;
     RECT  64.515 2.143 64.605 2.413 ;
     RECT  67.215 2.143 67.305 2.413 ;
     RECT  69.915 2.143 70.005 2.413 ;
     RECT  72.615 2.143 72.705 2.413 ;
     RECT  75.315 2.143 75.405 2.413 ;
     RECT  78.015 2.143 78.105 2.413 ;
     RECT  80.715 2.143 80.805 2.413 ;
     RECT  83.415 2.143 83.505 2.413 ;
     RECT  86.115 2.143 86.205 2.413 ;
     RECT  88.815 2.143 88.905 2.413 ;
     RECT  91.515 2.143 91.605 2.413 ;
     RECT  94.215 2.143 94.305 2.413 ;
     RECT  96.915 2.143 97.005 2.413 ;
     RECT  99.615 2.143 99.705 2.413 ;
     RECT  98.316 19.381 98.334 19.471 ;
     RECT  102.06 19.381 102.078 19.471 ;
     RECT  100.764 19.471 100.782 19.507 ;
     RECT  101.736 19.471 102.078 19.507 ;
     RECT  99.615 2.413 99.897 19.579 ;
     RECT  98.064 19.471 98.334 19.615 ;
     RECT  99.615 19.579 100.026 19.615 ;
     RECT  100.764 19.507 102.078 19.615 ;
     RECT  99.615 19.615 102.114 19.651 ;
     RECT  103.176 19.579 103.194 19.651 ;
     RECT  96.915 2.413 97.197 19.849 ;
     RECT  99.615 19.651 103.194 19.921 ;
     RECT  98.064 19.615 98.694 20.047 ;
     RECT  99.576 19.921 103.194 20.047 ;
     RECT  98.064 20.047 103.194 20.14 ;
     RECT  94.215 2.413 94.497 20.155 ;
     RECT  95.904 19.921 95.922 20.155 ;
     RECT  96.876 19.849 97.197 20.155 ;
     RECT  79.596 20.047 79.614 20.191 ;
     RECT  80.715 2.413 80.997 20.191 ;
     RECT  96.84 20.155 97.197 20.191 ;
     RECT  98.064 20.14 103.23 20.191 ;
     RECT  95.904 20.155 95.994 20.309 ;
     RECT  87.372 20.083 87.39 20.389 ;
     RECT  94.215 20.155 94.734 20.389 ;
     RECT  96.84 20.191 103.23 20.429 ;
     RECT  88.815 2.413 89.097 20.461 ;
     RECT  102.6 20.429 103.23 20.461 ;
     RECT  95.724 20.389 95.742 20.477 ;
     RECT  94.215 20.389 94.986 20.587 ;
     RECT  96.84 20.429 101.79 20.849 ;
     RECT  87.3 20.389 87.39 20.929 ;
     RECT  91.515 2.413 91.797 20.965 ;
     RECT  92.988 20.587 93.006 20.965 ;
     RECT  91.515 20.965 93.006 20.993 ;
     RECT  102.6 20.461 103.266 21.101 ;
     RECT  98.064 20.849 101.79 21.163 ;
     RECT  102.6 21.101 103.23 21.163 ;
     RECT  86.115 2.413 86.397 21.235 ;
     RECT  87.3 20.929 87.93 21.235 ;
     RECT  96.84 20.849 97.29 21.361 ;
     RECT  98.064 21.163 103.23 21.389 ;
     RECT  75.315 2.413 75.597 21.397 ;
     RECT  79.596 20.191 80.997 21.433 ;
     RECT  96.516 21.361 97.29 21.433 ;
     RECT  83.415 2.413 83.697 21.505 ;
     RECT  98.064 21.389 100.602 21.533 ;
     RECT  94.215 20.587 95.598 21.541 ;
     RECT  96.372 21.433 97.29 21.541 ;
     RECT  94.215 21.541 97.29 21.659 ;
     RECT  82.728 21.505 83.697 21.667 ;
     RECT  84.456 21.127 84.474 21.667 ;
     RECT  90.18 20.623 90.198 21.811 ;
     RECT  96.84 21.659 97.29 21.901 ;
     RECT  98.064 21.533 100.422 21.901 ;
     RECT  78.015 2.413 78.297 21.979 ;
     RECT  88.815 20.461 89.262 22.045 ;
     RECT  90.18 21.811 90.666 22.045 ;
     RECT  93.132 21.469 93.15 22.045 ;
     RECT  78.015 21.979 78.678 22.109 ;
     RECT  101.34 21.389 103.23 22.157 ;
     RECT  101.34 22.157 101.646 22.207 ;
     RECT  93.132 22.045 93.438 22.235 ;
     RECT  94.215 21.659 95.886 22.235 ;
     RECT  96.84 21.901 100.422 22.279 ;
     RECT  101.304 22.207 101.646 22.279 ;
     RECT  96.84 22.279 101.646 22.441 ;
     RECT  94.215 22.235 95.778 22.469 ;
     RECT  74.844 21.397 75.597 22.585 ;
     RECT  76.572 21.703 76.59 22.585 ;
     RECT  96.804 22.441 101.646 22.585 ;
     RECT  88.815 22.045 90.666 22.621 ;
     RECT  102.528 22.157 103.23 22.733 ;
     RECT  96.624 22.585 101.646 22.739 ;
     RECT  79.596 21.433 81.45 22.783 ;
     RECT  88.815 22.621 90.702 22.811 ;
     RECT  99.576 22.739 101.646 22.811 ;
     RECT  104.04 22.279 104.058 22.819 ;
     RECT  103.968 22.819 104.058 22.847 ;
     RECT  61.815 2.413 62.097 23.017 ;
     RECT  102.528 22.733 103.194 23.021 ;
     RECT  102.528 23.021 102.654 23.089 ;
     RECT  59.115 2.413 59.397 23.125 ;
     RECT  96.624 22.739 98.802 23.161 ;
     RECT  94.215 22.469 95.49 23.323 ;
     RECT  96.228 23.161 98.802 23.323 ;
     RECT  94.215 23.323 98.802 23.665 ;
     RECT  99.576 22.811 101.07 23.665 ;
     RECT  102.024 23.089 102.654 23.693 ;
     RECT  94.215 23.665 101.07 23.827 ;
     RECT  65.844 23.629 65.862 23.971 ;
     RECT  67.215 2.413 67.497 24.169 ;
     RECT  102.492 23.693 102.654 24.331 ;
     RECT  103.968 22.847 103.986 24.365 ;
     RECT  64.515 2.413 64.797 24.367 ;
     RECT  66.852 24.169 67.497 24.403 ;
     RECT  68.4 24.205 68.418 24.403 ;
     RECT  94.215 23.827 101.466 24.427 ;
     RECT  102.492 24.331 103.194 24.427 ;
     RECT  94.215 24.427 103.194 24.503 ;
     RECT  88.815 22.811 90.594 24.601 ;
     RECT  82.728 21.667 84.474 24.709 ;
     RECT  88.815 24.601 90.702 24.773 ;
     RECT  101.34 24.503 103.194 24.854 ;
     RECT  61.815 23.017 62.226 24.907 ;
     RECT  71.604 24.601 71.622 24.943 ;
     RECT  78.015 22.109 78.297 25.147 ;
     RECT  79.38 22.783 81.45 25.147 ;
     RECT  101.34 24.854 101.358 25.169 ;
     RECT  78.015 25.147 81.45 25.277 ;
     RECT  94.215 24.503 100.602 25.277 ;
     RECT  65.844 23.971 66.006 25.285 ;
     RECT  96.84 25.277 100.602 25.285 ;
     RECT  71.604 24.943 71.73 25.321 ;
     RECT  72.615 2.413 72.897 25.321 ;
     RECT  102.528 24.854 103.194 25.579 ;
     RECT  96.84 25.285 100.782 25.963 ;
     RECT  101.988 25.579 103.194 25.963 ;
     RECT  73.656 22.711 73.674 25.987 ;
     RECT  94.215 25.277 95.994 26.023 ;
     RECT  96.84 25.963 103.194 26.023 ;
     RECT  94.215 26.023 103.194 26.248 ;
     RECT  94.215 26.248 103.23 26.249 ;
     RECT  56.415 2.413 56.697 26.257 ;
     RECT  58.464 23.125 59.397 26.329 ;
     RECT  63.936 24.367 64.797 26.365 ;
     RECT  65.52 25.285 66.006 26.365 ;
     RECT  56.268 26.257 56.697 26.635 ;
     RECT  88.815 24.773 90.666 26.663 ;
     RECT  56.16 26.635 56.697 26.671 ;
     RECT  57.564 23.791 57.582 26.671 ;
     RECT  94.215 26.249 100.458 26.699 ;
     RECT  101.484 26.249 103.23 26.699 ;
     RECT  103.968 26.761 103.986 26.861 ;
     RECT  58.464 26.329 59.958 26.869 ;
     RECT  102.6 26.699 103.23 27.053 ;
     RECT  66.852 24.403 68.418 27.103 ;
     RECT  56.16 26.671 57.582 27.139 ;
     RECT  98.136 26.699 100.458 27.139 ;
     RECT  101.484 26.699 101.502 27.139 ;
     RECT  61.815 24.907 62.55 27.175 ;
     RECT  61.344 27.175 62.55 27.211 ;
     RECT  98.136 27.139 101.502 27.437 ;
     RECT  55.188 23.089 55.206 27.481 ;
     RECT  55.944 27.139 57.582 27.481 ;
     RECT  98.136 27.437 100.566 27.509 ;
     RECT  88.815 26.663 90.594 27.643 ;
     RECT  61.344 27.211 63.198 27.679 ;
     RECT  63.936 26.365 66.006 27.679 ;
     RECT  53.715 2.413 53.997 27.715 ;
     RECT  88.815 27.643 90.702 27.779 ;
     RECT  101.484 27.437 101.502 27.869 ;
     RECT  58.464 26.869 60.606 27.949 ;
     RECT  61.344 27.679 66.006 27.949 ;
     RECT  94.215 26.699 97.398 27.949 ;
     RECT  98.136 27.509 100.458 27.949 ;
     RECT  102.6 27.053 103.194 28.012 ;
     RECT  102.6 28.012 103.23 28.075 ;
     RECT  69.915 2.413 70.197 28.123 ;
     RECT  78.015 25.277 78.297 28.123 ;
     RECT  79.38 25.277 81.45 28.123 ;
     RECT  94.215 27.949 100.458 28.205 ;
     RECT  102.564 28.075 103.23 28.301 ;
     RECT  102.564 28.301 103.194 28.381 ;
     RECT  55.188 27.481 57.582 28.489 ;
     RECT  58.464 27.949 66.006 28.489 ;
     RECT  88.815 27.779 90.666 28.561 ;
     RECT  101.988 28.381 103.194 28.685 ;
     RECT  69.915 28.123 70.722 28.781 ;
     RECT  78.015 28.123 81.45 28.781 ;
     RECT  100.728 28.687 100.854 28.787 ;
     RECT  53.715 27.715 54.342 28.831 ;
     RECT  53.496 28.831 54.342 29.029 ;
     RECT  55.188 28.489 66.006 29.029 ;
     RECT  94.215 28.205 99.99 29.035 ;
     RECT  100.728 28.787 100.746 29.035 ;
     RECT  101.988 28.685 102.618 29.101 ;
     RECT  49.68 29.227 49.698 29.263 ;
     RECT  40.215 2.413 40.497 29.371 ;
     RECT  42.915 2.413 43.197 29.461 ;
     RECT  101.484 29.101 102.618 29.461 ;
     RECT  88.815 28.561 90.702 29.525 ;
     RECT  94.215 29.035 100.746 29.641 ;
     RECT  101.484 29.461 102.654 29.641 ;
     RECT  94.215 29.641 102.654 29.707 ;
     RECT  94.215 29.707 103.194 29.741 ;
     RECT  97.992 29.741 103.194 29.759 ;
     RECT  98.064 29.759 103.194 29.797 ;
     RECT  48.315 2.413 48.597 29.803 ;
     RECT  98.064 29.797 103.23 29.837 ;
     RECT  42.915 29.461 43.722 29.875 ;
     RECT  98.064 29.837 103.194 29.939 ;
     RECT  45.615 2.413 45.897 30.109 ;
     RECT  100.908 29.939 103.194 30.413 ;
     RECT  88.815 29.525 90.666 30.479 ;
     RECT  94.215 29.741 97.197 30.541 ;
     RECT  98.064 29.939 100.17 30.541 ;
     RECT  45.615 30.109 46.422 30.649 ;
     RECT  44.496 30.451 44.514 30.685 ;
     RECT  45.432 30.649 46.422 30.685 ;
     RECT  94.215 30.541 100.17 30.713 ;
     RECT  40.215 29.371 40.95 30.721 ;
     RECT  98.136 30.713 100.17 30.811 ;
     RECT  100.908 30.413 102.69 30.811 ;
     RECT  103.896 30.859 103.914 31.037 ;
     RECT  42.372 29.875 43.722 31.081 ;
     RECT  98.136 30.811 102.69 31.181 ;
     RECT  102.564 31.181 102.69 31.243 ;
     RECT  40.215 30.721 41.022 31.387 ;
     RECT  42.336 31.081 43.722 31.387 ;
     RECT  40.215 31.387 43.722 31.657 ;
     RECT  44.496 30.685 46.422 31.657 ;
     RECT  88.815 30.479 90.594 31.729 ;
     RECT  94.215 30.713 97.362 31.765 ;
     RECT  98.136 31.181 101.61 31.765 ;
     RECT  94.215 31.765 101.61 31.829 ;
     RECT  102.564 31.243 103.194 31.999 ;
     RECT  94.215 31.829 101.034 32.189 ;
     RECT  88.815 31.729 90.666 32.233 ;
     RECT  102.06 31.999 103.194 32.395 ;
     RECT  49.536 29.263 49.698 32.467 ;
     RECT  51.015 2.413 51.297 32.467 ;
     RECT  102.06 32.395 103.23 32.575 ;
     RECT  101.484 32.575 103.23 32.639 ;
     RECT  88.815 32.233 90.702 32.737 ;
     RECT  91.515 20.993 92.394 32.737 ;
     RECT  73.656 25.987 73.818 32.845 ;
     RECT  74.844 22.585 76.59 32.845 ;
     RECT  88.815 32.737 92.394 32.873 ;
     RECT  88.815 32.873 90.738 32.909 ;
     RECT  94.215 32.189 100.35 32.971 ;
     RECT  94.215 32.971 100.71 33.071 ;
     RECT  52.272 33.043 52.29 33.115 ;
     RECT  53.496 29.029 66.006 33.385 ;
     RECT  48.24 29.803 48.597 33.421 ;
     RECT  49.536 32.467 51.297 33.421 ;
     RECT  52.164 33.115 52.578 33.421 ;
     RECT  88.815 32.909 90.702 33.539 ;
     RECT  94.215 33.071 99.99 33.539 ;
     RECT  48.24 33.421 52.578 33.547 ;
     RECT  53.388 33.385 66.006 33.547 ;
     RECT  101.484 32.639 103.194 33.889 ;
     RECT  98.136 33.539 99.99 33.925 ;
     RECT  48.24 33.547 66.006 33.961 ;
     RECT  101.34 33.889 103.194 33.989 ;
     RECT  101.484 33.989 103.194 34.061 ;
     RECT  98.136 33.925 100.35 34.195 ;
     RECT  102.6 34.061 103.194 34.231 ;
     RECT  88.815 33.539 90.666 34.393 ;
     RECT  88.815 34.393 90.774 34.429 ;
     RECT  91.515 32.873 92.394 34.429 ;
     RECT  94.215 33.539 97.254 34.501 ;
     RECT  98.136 34.195 100.674 34.501 ;
     RECT  88.815 34.429 92.394 34.655 ;
     RECT  69.915 28.781 70.197 34.771 ;
     RECT  78.015 28.781 78.297 34.771 ;
     RECT  79.38 28.781 81.45 34.771 ;
     RECT  94.215 34.501 100.674 34.771 ;
     RECT  101.484 34.061 101.502 34.771 ;
     RECT  102.6 34.231 103.23 34.795 ;
     RECT  73.656 32.845 76.59 34.799 ;
     RECT  69.915 34.771 70.722 34.889 ;
     RECT  78.015 34.771 81.45 34.889 ;
     RECT  102.564 34.795 103.23 34.987 ;
     RECT  47.664 33.961 66.006 35.041 ;
     RECT  66.852 27.103 68.706 35.041 ;
     RECT  94.215 34.771 101.502 35.303 ;
     RECT  47.52 35.041 68.706 35.501 ;
     RECT  102.528 34.987 103.23 35.545 ;
     RECT  79.38 34.889 81.45 35.581 ;
     RECT  82.332 24.709 84.474 35.581 ;
     RECT  88.815 34.655 90.594 35.581 ;
     RECT  94.215 35.303 101.178 35.735 ;
     RECT  88.815 35.581 90.738 35.771 ;
     RECT  40.215 31.657 46.422 35.815 ;
     RECT  47.52 35.501 51.39 35.815 ;
     RECT  79.38 35.581 84.474 35.851 ;
     RECT  85.248 20.587 85.266 35.851 ;
     RECT  101.988 35.545 103.23 36.043 ;
     RECT  40.215 35.815 51.39 36.283 ;
     RECT  52.236 35.501 68.706 36.283 ;
     RECT  79.38 35.851 85.266 36.355 ;
     RECT  100.8 35.735 101.178 36.355 ;
     RECT  101.988 36.043 103.266 36.355 ;
     RECT  100.8 36.355 103.266 36.508 ;
     RECT  73.728 34.799 76.59 36.553 ;
     RECT  78.015 34.889 78.297 36.553 ;
     RECT  79.092 36.355 85.266 36.553 ;
     RECT  78.015 36.553 85.266 36.661 ;
     RECT  86.115 21.235 87.93 36.661 ;
     RECT  94.215 35.735 99.99 36.931 ;
     RECT  100.8 36.508 103.302 36.931 ;
     RECT  88.815 35.771 90.702 37.049 ;
     RECT  94.215 36.931 103.302 37.049 ;
     RECT  78.015 36.661 87.93 37.057 ;
     RECT  94.215 37.049 103.194 37.319 ;
     RECT  73.728 36.553 76.986 37.327 ;
     RECT  69.915 34.889 70.197 37.435 ;
     RECT  73.656 37.327 76.986 37.471 ;
     RECT  77.796 37.057 87.93 37.471 ;
     RECT  71.604 25.321 72.897 37.579 ;
     RECT  73.656 37.471 87.93 37.579 ;
     RECT  96.915 37.319 103.194 37.625 ;
     RECT  101.988 37.625 103.194 37.697 ;
     RECT  102.024 37.697 103.194 37.867 ;
     RECT  94.215 37.319 96.138 38.101 ;
     RECT  96.915 37.625 101.25 38.101 ;
     RECT  69.915 37.435 70.722 38.209 ;
     RECT  88.815 37.049 90.666 38.209 ;
     RECT  102.024 37.867 103.266 38.273 ;
     RECT  102.024 38.273 103.23 38.285 ;
     RECT  88.815 38.209 90.702 38.309 ;
     RECT  102.024 38.285 103.194 38.309 ;
     RECT  94.215 38.101 101.25 38.443 ;
     RECT  102.024 38.309 103.158 38.443 ;
     RECT  69.915 38.209 70.794 38.479 ;
     RECT  71.604 37.579 87.93 38.479 ;
     RECT  69.915 38.479 87.93 38.551 ;
     RECT  94.215 38.443 103.158 38.579 ;
     RECT  94.215 38.579 101.43 38.669 ;
     RECT  102.636 38.579 103.158 38.669 ;
     RECT  69.84 38.551 87.93 38.713 ;
     RECT  94.215 38.669 101.322 38.741 ;
     RECT  103.14 38.669 103.158 38.939 ;
     RECT  40.215 36.283 68.706 39.047 ;
     RECT  94.215 38.741 100.35 39.119 ;
     RECT  38.772 39.253 38.79 39.325 ;
     RECT  37.515 2.413 37.797 39.361 ;
     RECT  94.215 39.119 99.897 39.389 ;
     RECT  69.768 38.713 87.93 39.523 ;
     RECT  38.772 39.325 39.474 39.559 ;
     RECT  40.215 39.047 51.426 39.559 ;
     RECT  94.215 39.389 98.874 39.623 ;
     RECT  94.215 39.623 98.838 39.629 ;
     RECT  36.972 39.361 37.797 39.631 ;
     RECT  36.972 39.631 37.89 39.793 ;
     RECT  38.772 39.559 51.426 39.793 ;
     RECT  36.972 39.793 51.426 39.901 ;
     RECT  52.272 39.047 68.706 39.901 ;
     RECT  36.972 39.901 68.706 40.289 ;
     RECT  95.472 39.629 98.838 40.289 ;
     RECT  36.972 40.289 47.466 40.315 ;
     RECT  36.864 40.315 47.466 40.325 ;
     RECT  48.24 40.289 68.706 40.405 ;
     RECT  69.732 39.523 87.93 40.405 ;
     RECT  96.915 40.289 98.838 40.739 ;
     RECT  96.915 40.739 97.506 40.829 ;
     RECT  98.388 40.739 98.838 40.973 ;
     RECT  48.24 40.405 87.93 41.071 ;
     RECT  36.864 40.325 47.358 41.143 ;
     RECT  48.204 41.071 87.93 41.143 ;
     RECT  34.815 2.413 35.097 41.215 ;
     RECT  94.215 39.629 94.698 41.369 ;
     RECT  36.864 41.143 87.93 41.639 ;
     RECT  99.615 39.389 99.897 41.647 ;
     RECT  98.388 40.973 98.622 41.719 ;
     RECT  98.244 41.719 98.694 41.755 ;
     RECT  99.615 41.647 99.99 41.755 ;
     RECT  100.908 41.719 100.926 41.755 ;
     RECT  102.024 41.791 102.042 41.881 ;
     RECT  102.024 41.881 102.582 41.953 ;
     RECT  96.915 40.829 97.197 41.989 ;
     RECT  98.244 41.755 100.926 41.989 ;
     RECT  102.024 41.953 102.618 41.989 ;
     RECT  95.472 40.289 95.85 41.995 ;
     RECT  31.176 42.025 31.194 42.061 ;
     RECT  33.876 41.989 33.894 42.061 ;
     RECT  34.776 41.215 35.097 42.061 ;
     RECT  96.915 41.989 97.218 42.061 ;
     RECT  98.244 41.989 103.23 42.089 ;
     RECT  102.024 42.089 103.23 42.151 ;
     RECT  30.636 42.061 31.194 42.179 ;
     RECT  94.215 41.369 94.497 42.223 ;
     RECT  95.472 41.995 95.994 42.223 ;
     RECT  33.876 42.061 35.097 42.251 ;
     RECT  30.636 42.179 30.978 42.295 ;
     RECT  33.876 42.251 33.894 42.295 ;
     RECT  98.244 42.089 101.07 42.295 ;
     RECT  98.028 42.295 101.07 42.323 ;
     RECT  102.024 42.151 103.266 42.457 ;
     RECT  96.768 42.061 97.218 42.529 ;
     RECT  98.028 42.323 98.478 42.529 ;
     RECT  29.415 2.413 29.697 42.565 ;
     RECT  30.42 42.295 30.978 42.565 ;
     RECT  94.215 42.223 95.994 42.565 ;
     RECT  96.768 42.529 98.478 42.565 ;
     RECT  102.024 42.457 103.986 42.605 ;
     RECT  33.444 42.295 33.894 42.719 ;
     RECT  36.972 41.639 87.93 42.719 ;
     RECT  99.36 42.323 101.07 42.871 ;
     RECT  102.024 42.605 103.23 42.871 ;
     RECT  33.876 42.719 33.894 42.989 ;
     RECT  94.215 42.565 98.478 42.989 ;
     RECT  103.968 42.605 103.986 42.989 ;
     RECT  99.36 42.871 103.23 43.099 ;
     RECT  98.28 42.989 98.478 43.141 ;
     RECT  99.252 43.099 103.23 43.141 ;
     RECT  34.815 42.251 35.097 43.231 ;
     RECT  29.415 42.565 30.978 43.267 ;
     RECT  96.228 42.989 97.434 43.295 ;
     RECT  98.28 43.141 103.23 43.469 ;
     RECT  88.815 38.309 90.594 43.609 ;
     RECT  88.815 43.609 90.702 43.709 ;
     RECT  34.776 43.231 35.097 43.843 ;
     RECT  37.044 42.719 87.93 43.879 ;
     RECT  34.164 43.843 35.097 44.069 ;
     RECT  94.215 42.989 95.418 44.107 ;
     RECT  96.48 43.295 97.434 44.107 ;
     RECT  36.72 43.879 87.93 44.185 ;
     RECT  94.215 44.107 97.434 44.185 ;
     RECT  98.28 43.469 102.078 44.185 ;
     RECT  103.176 43.469 103.23 44.221 ;
     RECT  94.215 44.185 102.078 44.249 ;
     RECT  33.228 44.185 33.246 44.339 ;
     RECT  29.376 43.267 30.978 44.419 ;
     RECT  32.115 2.413 32.397 44.419 ;
     RECT  100.62 44.249 102.078 44.491 ;
     RECT  103.176 44.221 103.266 44.491 ;
     RECT  36.648 44.185 87.93 44.539 ;
     RECT  100.62 44.491 103.266 44.621 ;
     RECT  34.815 44.069 35.097 44.68 ;
     RECT  35.964 44.539 87.93 44.68 ;
     RECT  34.815 44.68 87.93 44.717 ;
     RECT  36 44.717 87.93 44.761 ;
     RECT  88.815 43.709 90.594 44.761 ;
     RECT  100.62 44.621 103.23 44.915 ;
     RECT  88.815 44.761 90.666 44.987 ;
     RECT  100.62 44.915 101.214 44.987 ;
     RECT  33.516 44.851 33.534 45.023 ;
     RECT  94.215 44.249 99.897 45.031 ;
     RECT  100.62 44.987 101.142 45.031 ;
     RECT  101.988 44.915 103.23 45.293 ;
     RECT  94.215 45.031 101.142 45.527 ;
     RECT  94.215 45.527 99.99 45.599 ;
     RECT  98.064 45.599 99.99 45.761 ;
     RECT  100.908 45.527 101.142 45.805 ;
     RECT  101.988 45.293 103.194 45.805 ;
     RECT  36 44.761 88.038 45.833 ;
     RECT  36 45.833 38.25 45.883 ;
     RECT  33.552 45.841 33.57 45.931 ;
     RECT  33.336 45.931 33.57 45.959 ;
     RECT  35.964 45.883 38.25 45.959 ;
     RECT  100.908 45.805 103.194 45.965 ;
     RECT  33.336 45.959 33.354 46.031 ;
     RECT  29.376 44.419 32.397 46.075 ;
     RECT  36.432 45.959 38.25 46.265 ;
     RECT  100.908 45.965 101.25 46.309 ;
     RECT  88.815 44.987 90.594 46.381 ;
     RECT  91.515 34.655 92.394 46.381 ;
     RECT  98.1 45.761 99.99 46.381 ;
     RECT  100.764 46.309 101.25 46.381 ;
     RECT  102.024 45.965 103.194 46.643 ;
     RECT  37.26 46.265 38.25 46.651 ;
     RECT  39.06 45.833 88.038 46.651 ;
     RECT  29.124 46.075 32.397 46.769 ;
     RECT  94.215 45.599 97.254 46.885 ;
     RECT  98.1 46.381 101.25 46.885 ;
     RECT  37.26 46.651 88.038 47.317 ;
     RECT  36.432 46.265 36.45 47.323 ;
     RECT  37.224 47.317 88.038 47.323 ;
     RECT  102.528 46.643 103.194 47.425 ;
     RECT  34.815 44.717 35.097 47.461 ;
     RECT  94.215 46.885 101.574 47.563 ;
     RECT  102.492 47.425 103.194 47.563 ;
     RECT  36.432 47.323 88.038 47.623 ;
     RECT  34.668 47.461 35.097 47.695 ;
     RECT  36.324 47.623 88.038 47.695 ;
     RECT  36.18 47.695 88.038 47.731 ;
     RECT  94.215 47.563 103.194 47.755 ;
     RECT  29.196 46.769 32.397 47.857 ;
     RECT  94.215 47.755 103.23 47.893 ;
     RECT  2.415 2.413 2.697 47.947 ;
     RECT  5.115 2.413 5.397 48.001 ;
     RECT  34.488 47.695 35.097 48.001 ;
     RECT  35.928 47.731 88.038 48.001 ;
     RECT  29.196 47.857 32.49 48.119 ;
     RECT  0.108 48.043 0.126 48.139 ;
     RECT  94.215 47.893 103.302 48.173 ;
     RECT  3.996 48.091 4.014 48.199 ;
     RECT  5.04 48.001 5.397 48.199 ;
     RECT  2.415 47.947 2.718 48.235 ;
     RECT  3.996 48.199 5.397 48.235 ;
     RECT  34.488 48.001 88.038 48.235 ;
     RECT  3.6 48.235 5.397 48.272 ;
     RECT  2.415 48.235 2.862 48.361 ;
     RECT  29.196 48.119 32.397 48.361 ;
     RECT  34.308 48.235 88.038 48.425 ;
     RECT  3.996 48.272 5.397 48.461 ;
     RECT  2.376 48.361 2.862 48.523 ;
     RECT  0.108 48.139 0.162 48.569 ;
     RECT  2.304 48.523 2.862 48.659 ;
     RECT  3.996 48.461 4.014 48.659 ;
     RECT  94.215 48.173 103.194 48.749 ;
     RECT  39.78 48.425 88.038 48.767 ;
     RECT  29.088 48.361 32.397 48.811 ;
     RECT  27.972 48.361 27.99 48.901 ;
     RECT  28.872 48.811 32.397 48.901 ;
     RECT  34.308 48.425 39.042 48.973 ;
     RECT  94.215 48.749 102.042 49.001 ;
     RECT  40.032 48.767 88.038 49.009 ;
     RECT  88.815 46.381 92.394 49.009 ;
     RECT  34.092 48.973 39.042 49.045 ;
     RECT  33.84 49.045 39.042 49.081 ;
     RECT  0.144 48.569 0.162 49.109 ;
     RECT  2.415 48.659 2.862 49.235 ;
     RECT  33.66 49.081 39.042 49.243 ;
     RECT  27.972 48.901 32.397 49.291 ;
     RECT  27.972 49.291 32.49 49.351 ;
     RECT  33.516 49.243 39.042 49.351 ;
     RECT  103.176 48.749 103.194 49.351 ;
     RECT  101.484 49.001 102.042 49.477 ;
     RECT  103.176 49.351 103.23 49.477 ;
     RECT  26.715 2.413 26.997 49.771 ;
     RECT  27.972 49.351 39.042 49.771 ;
     RECT  26.715 49.771 39.042 49.811 ;
     RECT  27.972 49.811 39.042 49.819 ;
     RECT  94.215 49.001 100.242 49.819 ;
     RECT  27.972 49.819 39.258 49.847 ;
     RECT  28.152 49.847 39.258 49.855 ;
     RECT  40.032 49.009 92.394 49.855 ;
     RECT  28.152 49.855 92.394 49.883 ;
     RECT  101.484 49.477 103.23 49.997 ;
     RECT  28.62 49.883 92.394 50.009 ;
     RECT  3.672 49.351 3.69 50.045 ;
     RECT  94.215 49.819 100.314 50.045 ;
     RECT  29.088 50.009 92.394 50.081 ;
     RECT  101.484 49.997 103.194 50.093 ;
     RECT  5.076 48.461 5.397 50.117 ;
     RECT  101.484 50.093 102.69 50.125 ;
     RECT  101.34 50.125 102.69 50.161 ;
     RECT  100.872 50.161 102.69 50.573 ;
     RECT  29.124 50.081 92.394 50.729 ;
     RECT  94.215 50.045 100.098 50.935 ;
     RECT  101.484 50.573 102.69 50.957 ;
     RECT  33.192 50.729 92.394 50.963 ;
     RECT  34.092 50.963 92.394 50.999 ;
     RECT  33.192 50.963 33.354 51.089 ;
     RECT  34.092 50.999 90.666 51.089 ;
     RECT  101.988 50.957 102.69 51.115 ;
     RECT  101.988 51.115 103.194 51.211 ;
     RECT  33.192 51.089 33.246 51.245 ;
     RECT  101.988 51.211 103.23 51.269 ;
     RECT  94.215 50.935 100.458 51.331 ;
     RECT  101.988 51.269 103.194 51.359 ;
     RECT  94.215 51.331 100.638 51.601 ;
     RECT  101.988 51.359 102.654 51.691 ;
     RECT  33.228 51.245 33.246 51.907 ;
     RECT  34.092 51.089 90.594 51.907 ;
     RECT  94.215 51.601 100.71 52.169 ;
     RECT  33.228 51.907 90.594 52.249 ;
     RECT  101.484 51.691 102.654 52.411 ;
     RECT  91.515 50.999 92.394 52.447 ;
     RECT  29.124 50.729 32.397 52.717 ;
     RECT  33.228 52.249 90.702 52.717 ;
     RECT  29.124 52.717 90.702 52.753 ;
     RECT  91.44 52.447 92.394 52.753 ;
     RECT  29.124 52.753 92.394 52.979 ;
     RECT  94.215 52.169 100.314 53.095 ;
     RECT  101.052 52.411 102.654 53.095 ;
     RECT  33.228 52.979 92.394 53.123 ;
     RECT  94.215 53.095 102.654 53.131 ;
     RECT  94.215 53.131 103.194 53.261 ;
     RECT  39.852 53.123 92.394 53.491 ;
     RECT  93.132 22.235 93.402 53.491 ;
     RECT  94.215 53.261 100.998 53.519 ;
     RECT  39.852 53.491 93.402 53.591 ;
     RECT  101.988 53.261 103.194 53.699 ;
     RECT  39.924 53.591 93.402 53.789 ;
     RECT  102.024 53.699 103.194 53.869 ;
     RECT  102.024 53.869 103.23 53.933 ;
     RECT  33.228 53.123 39.006 54.139 ;
     RECT  29.124 52.979 32.397 54.175 ;
     RECT  33.228 54.139 39.042 54.175 ;
     RECT  94.215 53.519 100.494 54.301 ;
     RECT  39.96 53.789 93.402 54.329 ;
     RECT  102.024 53.933 103.194 54.707 ;
     RECT  94.215 54.301 100.998 54.949 ;
     RECT  29.124 54.175 39.042 54.985 ;
     RECT  94.215 54.949 101.502 55.211 ;
     RECT  28.944 54.985 39.042 55.219 ;
     RECT  39.996 54.329 93.402 55.219 ;
     RECT  28.944 55.219 93.402 55.243 ;
     RECT  28.764 55.243 93.402 55.283 ;
     RECT  102.528 54.707 103.194 55.915 ;
     RECT  102.528 55.915 103.23 56.107 ;
     RECT  29.016 55.283 93.402 56.219 ;
     RECT  94.215 55.211 101.466 56.335 ;
     RECT  94.215 56.335 101.574 56.795 ;
     RECT  102.528 56.107 103.266 57.029 ;
     RECT  102.636 57.029 103.266 57.209 ;
     RECT  29.016 56.219 32.397 57.271 ;
     RECT  33.228 56.219 93.402 57.271 ;
     RECT  94.215 56.795 101.466 57.299 ;
     RECT  29.016 57.271 93.402 57.371 ;
     RECT  102.636 57.209 102.654 57.407 ;
     RECT  94.215 57.299 100.818 57.569 ;
     RECT  94.215 57.569 100.638 57.605 ;
     RECT  29.016 57.371 32.397 58.459 ;
     RECT  33.228 57.371 93.402 58.459 ;
     RECT  29.016 58.459 93.402 58.495 ;
     RECT  28.872 58.495 93.402 58.531 ;
     RECT  94.215 57.605 100.494 58.559 ;
     RECT  28.764 58.531 93.402 58.621 ;
     RECT  28.512 58.621 93.402 58.927 ;
     RECT  27.936 58.927 93.402 59.071 ;
     RECT  26.715 49.811 26.997 59.197 ;
     RECT  27.792 59.071 93.402 59.197 ;
     RECT  94.215 58.559 99.954 59.333 ;
     RECT  94.215 59.333 99.897 59.639 ;
     RECT  94.215 59.639 97.866 60.125 ;
     RECT  26.715 59.197 93.402 60.151 ;
     RECT  94.215 60.125 97.197 60.179 ;
     RECT  98.82 59.639 99.897 60.655 ;
     RECT  98.82 60.655 100.35 60.925 ;
     RECT  98.82 60.925 101.286 60.961 ;
     RECT  98.82 60.961 101.502 61.051 ;
     RECT  102.636 60.691 102.654 61.051 ;
     RECT  102.636 61.051 102.69 61.123 ;
     RECT  98.676 61.051 101.502 61.159 ;
     RECT  102.636 61.123 103.194 61.159 ;
     RECT  98.676 61.159 103.194 61.195 ;
     RECT  96.552 60.179 97.197 61.339 ;
     RECT  98.172 61.195 103.194 61.501 ;
     RECT  96.552 61.339 97.254 61.591 ;
     RECT  26.136 60.151 93.402 61.613 ;
     RECT  98.028 61.501 103.194 61.655 ;
     RECT  100.836 61.655 103.194 61.709 ;
     RECT  102.564 61.709 103.194 61.771 ;
     RECT  96.336 61.591 97.254 61.861 ;
     RECT  98.028 61.655 100.098 61.861 ;
     RECT  26.208 61.613 93.402 61.925 ;
     RECT  102.564 61.771 103.23 61.969 ;
     RECT  28.368 61.925 93.402 62.159 ;
     RECT  94.215 60.179 95.49 62.203 ;
     RECT  96.3 61.861 100.098 62.203 ;
     RECT  102.564 61.969 103.266 62.239 ;
     RECT  102.564 62.239 103.986 62.381 ;
     RECT  100.836 61.709 101.502 62.545 ;
     RECT  102.564 62.381 103.194 62.573 ;
     RECT  100.836 62.545 101.574 62.581 ;
     RECT  103.968 62.381 103.986 62.765 ;
     RECT  94.215 62.203 100.098 62.815 ;
     RECT  100.836 62.581 101.718 62.815 ;
     RECT  26.208 61.925 27.63 63.121 ;
     RECT  28.368 62.159 90.774 63.121 ;
     RECT  91.515 62.159 93.402 63.121 ;
     RECT  26.1 63.121 93.402 63.239 ;
     RECT  26.208 63.239 93.402 63.629 ;
     RECT  94.215 62.815 101.718 63.821 ;
     RECT  102.6 62.573 103.194 63.917 ;
     RECT  102.6 63.917 102.69 64.129 ;
     RECT  102.564 64.129 102.69 64.165 ;
     RECT  94.215 63.821 101.178 64.319 ;
     RECT  101.016 64.319 101.178 64.589 ;
     RECT  101.16 64.589 101.178 64.669 ;
     RECT  102.024 64.165 102.69 64.669 ;
     RECT  26.244 63.629 93.402 64.867 ;
     RECT  25.74 64.867 93.402 64.925 ;
     RECT  101.16 64.669 102.69 65.011 ;
     RECT  26.244 64.925 93.402 65.129 ;
     RECT  101.16 65.011 103.194 65.129 ;
     RECT  101.412 65.129 103.194 65.399 ;
     RECT  94.215 64.319 100.17 65.515 ;
     RECT  94.215 65.515 100.314 65.821 ;
     RECT  26.46 65.129 93.402 66.019 ;
     RECT  94.215 65.821 100.458 66.019 ;
     RECT  26.46 66.019 100.458 66.361 ;
     RECT  26.46 66.361 100.998 66.551 ;
     RECT  26.46 66.551 100.35 66.595 ;
     RECT  26.064 66.595 100.35 66.653 ;
     RECT  101.952 65.399 103.194 66.667 ;
     RECT  26.172 66.653 100.35 67.369 ;
     RECT  101.088 66.667 103.194 67.369 ;
     RECT  26.172 67.369 103.194 67.441 ;
     RECT  26.064 67.441 103.194 67.613 ;
     RECT  26.064 67.613 100.89 67.703 ;
     RECT  26.316 67.703 100.89 67.757 ;
     RECT  26.316 67.757 100.674 67.829 ;
     RECT  26.316 67.829 100.494 67.865 ;
     RECT  102.024 67.613 103.194 68.141 ;
     RECT  102.024 68.141 102.69 68.207 ;
     RECT  101.484 68.521 101.502 68.719 ;
     RECT  26.388 67.865 100.386 68.791 ;
     RECT  101.304 68.719 101.502 68.791 ;
     RECT  26.388 68.791 101.502 68.881 ;
     RECT  26.208 68.881 101.502 68.909 ;
     RECT  102.564 68.207 102.69 68.989 ;
     RECT  102.564 68.989 103.194 69.163 ;
     RECT  102.024 69.163 103.194 69.359 ;
     RECT  98.136 68.909 101.25 69.449 ;
     RECT  98.136 69.449 100.494 69.593 ;
     RECT  102.564 69.359 103.194 69.677 ;
     RECT  98.136 69.593 100.35 69.773 ;
     RECT  26.208 68.909 97.362 69.835 ;
     RECT  98.136 69.773 100.314 69.899 ;
     RECT  26.136 69.835 97.362 69.979 ;
     RECT  98.136 69.899 99.897 69.979 ;
     RECT  101.268 69.871 101.286 69.989 ;
     RECT  101.484 70.105 101.502 70.123 ;
     RECT  102.564 69.677 102.654 70.123 ;
     RECT  26.136 69.979 99.897 70.231 ;
     RECT  101.484 70.123 102.654 70.541 ;
     RECT  102.06 70.541 102.654 70.637 ;
     RECT  26.064 70.231 99.897 70.681 ;
     RECT  102.276 70.637 102.654 70.681 ;
     RECT  100.872 70.771 100.89 70.915 ;
     RECT  26.064 70.681 100.026 70.951 ;
     RECT  100.764 70.915 100.89 70.951 ;
     RECT  102.276 70.681 103.194 71.467 ;
     RECT  26.064 70.951 100.89 71.519 ;
     RECT  102.024 71.467 103.194 71.959 ;
     RECT  26.136 71.519 100.89 72.031 ;
     RECT  102.024 71.959 103.23 72.139 ;
     RECT  26.136 72.031 100.926 72.149 ;
     RECT  96.336 72.149 100.926 72.265 ;
     RECT  96.336 72.265 100.962 72.301 ;
     RECT  101.988 72.139 103.23 72.301 ;
     RECT  26.136 72.149 95.562 72.841 ;
     RECT  96.336 72.301 103.23 72.995 ;
     RECT  26.028 72.841 95.562 73.309 ;
     RECT  96.336 72.995 101.178 73.309 ;
     RECT  26.028 73.309 101.178 73.345 ;
     RECT  101.952 72.995 103.23 73.372 ;
     RECT  25.992 73.345 101.178 73.507 ;
     RECT  101.952 73.372 103.266 73.543 ;
     RECT  101.952 73.543 103.302 73.613 ;
     RECT  101.952 73.613 103.266 73.679 ;
     RECT  101.952 73.679 103.194 73.769 ;
     RECT  102.708 73.769 103.194 73.877 ;
     RECT  102.708 73.877 102.762 73.949 ;
     RECT  102.708 73.949 102.726 74.039 ;
     RECT  25.884 73.507 101.178 74.075 ;
     RECT  25.884 74.075 99.954 74.083 ;
     RECT  25.776 74.083 99.954 74.111 ;
     RECT  101.952 73.769 101.97 74.309 ;
     RECT  100.872 74.075 100.89 74.345 ;
     RECT  25.776 74.111 97.722 74.425 ;
     RECT  25.488 74.425 97.722 74.587 ;
     RECT  25.308 74.587 97.722 74.723 ;
     RECT  25.308 74.723 97.686 76.301 ;
     RECT  25.308 76.301 95.562 76.505 ;
     RECT  94.215 76.505 95.562 76.847 ;
     RECT  25.308 76.505 93.474 76.855 ;
     RECT  96.336 76.301 97.686 76.925 ;
     RECT  98.496 74.111 99.954 77.017 ;
     RECT  101.628 77.089 101.646 77.125 ;
     RECT  100.98 77.125 101.718 77.287 ;
     RECT  102.636 77.161 102.654 77.359 ;
     RECT  96.372 76.925 97.686 77.431 ;
     RECT  98.424 77.017 99.954 77.431 ;
     RECT  102.636 77.359 103.194 77.431 ;
     RECT  100.908 77.287 101.718 77.521 ;
     RECT  102.6 77.431 103.194 77.629 ;
     RECT  96.372 77.431 99.954 77.665 ;
     RECT  100.764 77.521 101.718 77.665 ;
     RECT  96.372 77.665 101.718 77.701 ;
     RECT  96.336 77.701 101.718 77.935 ;
     RECT  102.6 77.629 103.23 77.935 ;
     RECT  94.215 76.847 95.49 77.971 ;
     RECT  96.336 77.935 103.23 78.125 ;
     RECT  94.215 77.971 95.562 78.133 ;
     RECT  96.336 78.125 103.194 78.133 ;
     RECT  25.092 76.855 93.474 78.403 ;
     RECT  94.215 78.133 103.194 78.403 ;
     RECT  25.092 78.403 103.194 78.893 ;
     RECT  25.092 78.893 101.502 78.971 ;
     RECT  98.064 78.971 101.502 79.169 ;
     RECT  102.6 78.893 103.194 79.213 ;
     RECT  98.208 79.169 101.502 79.661 ;
     RECT  98.208 79.661 101.286 79.709 ;
     RECT  102.6 79.213 103.23 79.861 ;
     RECT  102.564 79.861 103.23 79.949 ;
     RECT  25.092 78.971 97.29 79.951 ;
     RECT  98.208 79.709 101.25 79.951 ;
     RECT  102.564 79.949 103.194 80.059 ;
     RECT  102.492 80.059 103.194 80.107 ;
     RECT  102.024 80.107 103.194 80.159 ;
     RECT  25.092 79.951 101.25 80.249 ;
     RECT  25.092 80.249 100.062 80.429 ;
     RECT  100.836 80.249 101.25 80.599 ;
     RECT  100.836 80.599 101.754 81.131 ;
     RECT  25.092 80.429 99.897 81.211 ;
     RECT  101.556 81.131 101.754 81.259 ;
     RECT  102.528 80.159 103.194 81.259 ;
     RECT  25.092 81.211 100.818 81.677 ;
     RECT  101.556 81.259 103.194 81.707 ;
     RECT  100.8 81.677 100.818 82.111 ;
     RECT  101.556 81.707 102.618 82.111 ;
     RECT  100.8 82.111 102.618 82.561 ;
     RECT  100.764 82.561 102.618 82.699 ;
     RECT  25.092 81.677 100.026 82.831 ;
     RECT  100.764 82.699 103.194 82.831 ;
     RECT  25.092 82.831 103.194 82.949 ;
     RECT  100.8 82.949 103.194 83.759 ;
     RECT  100.836 83.759 103.194 83.795 ;
     RECT  25.092 82.949 100.026 83.831 ;
     RECT  100.908 83.795 103.194 84.029 ;
     RECT  25.2 83.831 100.026 84.451 ;
     RECT  101.052 84.029 103.194 84.677 ;
     RECT  101.052 84.677 102.654 85.133 ;
     RECT  25.2 84.451 100.062 85.225 ;
     RECT  101.052 85.133 101.43 85.225 ;
     RECT  102.492 85.133 102.654 85.289 ;
     RECT  102.528 85.289 102.654 85.421 ;
     RECT  25.2 85.225 101.43 85.999 ;
     RECT  25.2 85.999 101.538 86.035 ;
     RECT  102.528 85.421 102.618 86.035 ;
     RECT  25.2 86.035 102.618 86.063 ;
     RECT  101.196 86.063 102.618 86.155 ;
     RECT  25.2 86.063 100.458 86.531 ;
     RECT  101.196 86.155 103.194 86.881 ;
     RECT  101.196 86.881 103.23 87.245 ;
     RECT  101.196 87.245 103.194 87.269 ;
     RECT  25.2 86.531 100.35 87.349 ;
     RECT  102.024 87.269 103.194 87.437 ;
     RECT  25.2 87.349 101.106 87.575 ;
     RECT  102.528 87.437 103.194 88.171 ;
     RECT  102.492 88.171 103.194 88.223 ;
     RECT  100.98 87.575 101.106 88.231 ;
     RECT  25.2 87.575 100.062 88.321 ;
     RECT  100.98 88.231 101.142 88.349 ;
     RECT  100.98 88.349 100.998 88.429 ;
     RECT  102.528 88.223 103.194 88.555 ;
     RECT  102.528 88.555 103.23 88.619 ;
     RECT  100.944 88.429 100.998 88.771 ;
     RECT  25.2 88.321 100.134 88.799 ;
     RECT  90.9 88.799 100.134 88.889 ;
     RECT  100.908 88.771 100.998 88.973 ;
     RECT  90.972 88.889 100.134 89.033 ;
     RECT  92.592 89.033 100.134 89.041 ;
     RECT  102.564 88.619 103.23 89.323 ;
     RECT  101.268 89.311 101.502 89.429 ;
     RECT  25.2 88.799 89.766 89.453 ;
     RECT  88.524 89.453 89.766 89.465 ;
     RECT  101.268 89.429 101.286 89.465 ;
     RECT  102.564 89.323 103.302 89.573 ;
     RECT  92.592 89.041 100.494 89.701 ;
     RECT  102.564 89.573 103.266 89.707 ;
     RECT  102.528 89.707 103.266 89.744 ;
     RECT  102.564 89.744 103.266 89.771 ;
     RECT  102.564 89.771 103.194 89.807 ;
     RECT  102.564 89.807 102.69 89.879 ;
     RECT  92.592 89.701 101.106 89.969 ;
     RECT  92.592 89.969 100.998 90.029 ;
     RECT  85.5 89.453 87.39 90.041 ;
     RECT  100.98 90.029 100.998 90.041 ;
     RECT  102.6 89.879 102.69 90.239 ;
     RECT  25.2 89.453 84.762 90.355 ;
     RECT  92.592 90.029 100.134 90.383 ;
     RECT  102.6 90.239 102.618 90.509 ;
     RECT  25.164 90.355 84.762 90.553 ;
     RECT  85.5 90.041 86.958 90.553 ;
     RECT  25.164 90.553 86.958 91.435 ;
     RECT  90.972 89.033 91.797 92.443 ;
     RECT  90.648 92.443 91.797 92.573 ;
     RECT  93.348 90.383 100.134 92.579 ;
     RECT  25.056 91.435 86.958 93.011 ;
     RECT  98.604 92.579 100.134 93.389 ;
     RECT  92.592 90.383 92.61 93.659 ;
     RECT  98.676 93.389 100.134 93.929 ;
     RECT  25.056 93.011 86.67 94.171 ;
     RECT  25.056 94.171 86.886 94.405 ;
     RECT  93.348 92.579 97.794 94.433 ;
     RECT  25.056 94.405 86.958 94.559 ;
     RECT  98.856 93.929 100.134 94.631 ;
     RECT  98.856 94.631 100.062 94.937 ;
     RECT  99.615 94.937 100.062 94.973 ;
     RECT  93.348 94.433 97.758 95.009 ;
     RECT  25.056 94.559 86.67 95.449 ;
     RECT  25.056 95.449 86.706 95.549 ;
     RECT  98.856 94.937 98.874 95.947 ;
     RECT  98.604 95.947 98.874 96.077 ;
     RECT  88.815 89.465 89.766 96.089 ;
     RECT  93.744 95.009 97.758 96.557 ;
     RECT  90.972 92.573 91.797 96.593 ;
     RECT  25.056 95.549 86.67 96.691 ;
     RECT  93.78 96.557 97.758 96.827 ;
     RECT  93.78 96.827 97.686 97.133 ;
     RECT  25.056 96.691 86.706 97.291 ;
     RECT  93.78 97.133 94.497 97.331 ;
     RECT  25.056 97.291 86.778 97.439 ;
     RECT  95.22 97.133 97.686 97.439 ;
     RECT  95.22 97.439 95.706 97.673 ;
     RECT  25.056 97.439 86.742 97.799 ;
     RECT  96.915 97.439 97.686 97.979 ;
     RECT  25.056 97.799 86.67 98.069 ;
     RECT  25.056 98.069 86.598 98.105 ;
     RECT  95.688 97.673 95.706 98.249 ;
     RECT  98.856 96.077 98.874 98.339 ;
     RECT  25.056 98.105 86.454 98.689 ;
     RECT  24.015 2.413 24.297 98.725 ;
     RECT  25.02 98.689 86.454 98.725 ;
     RECT  24.015 98.725 86.454 98.765 ;
     RECT  25.524 98.765 86.454 98.879 ;
     RECT  24.015 98.765 24.75 99.535 ;
     RECT  25.524 98.879 86.397 99.535 ;
     RECT  24.015 99.535 86.397 99.725 ;
     RECT  24.015 99.725 84.438 99.995 ;
     RECT  85.5 99.725 86.397 99.995 ;
     RECT  79.992 99.995 84.402 100.229 ;
     RECT  79.992 100.229 84.258 100.499 ;
     RECT  24.015 99.995 79.254 100.535 ;
     RECT  79.992 100.499 84.114 100.535 ;
     RECT  79.992 100.535 83.697 100.741 ;
     RECT  24.015 100.535 78.858 100.769 ;
     RECT  24.015 100.769 78.678 100.829 ;
     RECT  79.74 100.741 83.697 101.309 ;
     RECT  26.715 100.829 78.678 101.849 ;
     RECT  24.015 100.829 25.974 102.043 ;
     RECT  26.715 101.849 36.09 102.043 ;
     RECT  82.224 101.309 83.697 102.119 ;
     RECT  77.76 101.849 78.678 102.191 ;
     RECT  79.74 101.309 80.997 102.199 ;
     RECT  79.74 102.199 81.126 102.433 ;
     RECT  82.224 102.119 82.638 102.659 ;
     RECT  77.76 102.191 78.297 102.703 ;
     RECT  36.828 101.849 76.986 102.739 ;
     RECT  77.724 102.703 78.297 102.739 ;
     RECT  79.236 102.433 81.126 102.775 ;
     RECT  82.224 102.659 82.242 102.775 ;
     RECT  24.015 102.043 36.09 102.811 ;
     RECT  36.828 102.739 78.297 102.811 ;
     RECT  79.236 102.775 82.242 102.839 ;
     RECT  79.236 102.839 81.594 103.073 ;
     RECT  24.015 102.811 78.297 103.085 ;
     RECT  79.236 103.073 79.83 103.109 ;
     RECT  2.415 49.235 2.697 103.157 ;
     RECT  5.115 50.117 5.397 103.157 ;
     RECT  7.815 2.413 8.097 103.157 ;
     RECT  10.515 2.413 10.797 103.157 ;
     RECT  13.215 2.413 13.497 103.157 ;
     RECT  15.915 2.413 16.197 103.157 ;
     RECT  18.615 2.413 18.897 103.157 ;
     RECT  21.315 2.413 21.597 103.157 ;
     RECT  24.015 103.085 38.07 103.157 ;
     RECT  38.952 103.085 78.297 103.157 ;
     RECT  80.715 103.073 81.594 103.157 ;
     RECT  83.415 102.119 83.697 103.157 ;
     RECT  86.115 99.995 86.397 103.157 ;
     RECT  88.815 96.089 89.097 103.157 ;
     RECT  91.515 96.593 91.797 103.157 ;
     RECT  94.215 97.331 94.497 103.157 ;
     RECT  96.915 97.979 97.197 103.157 ;
     RECT  99.615 94.973 99.897 103.157 ;
     RECT  38.952 103.157 77.346 103.199 ;
     RECT  39.204 103.199 77.346 103.235 ;
     RECT  39.204 103.235 59.49 103.277 ;
     RECT  50.76 103.277 59.49 103.28 ;
     RECT  24.207 103.157 38.07 103.307 ;
     RECT  50.76 103.28 59.397 103.307 ;
     RECT  50.832 103.307 54.198 103.325 ;
     RECT  54.936 103.307 59.397 103.373 ;
     RECT  24.207 103.307 37.797 103.379 ;
     RECT  50.832 103.325 53.997 103.379 ;
     RECT  56.34 103.373 59.397 103.379 ;
     RECT  60.444 103.235 77.346 103.379 ;
     RECT  80.907 103.157 81.594 103.379 ;
     RECT  24.207 103.379 31.158 103.421 ;
     RECT  31.932 103.379 37.797 103.421 ;
     RECT  2.607 103.157 2.697 103.427 ;
     RECT  5.307 103.157 5.397 103.427 ;
     RECT  8.007 103.157 8.097 103.427 ;
     RECT  10.707 103.157 10.797 103.427 ;
     RECT  13.407 103.157 13.497 103.427 ;
     RECT  16.107 103.157 16.197 103.427 ;
     RECT  18.807 103.157 18.897 103.427 ;
     RECT  21.507 103.157 21.597 103.427 ;
     RECT  24.207 103.421 25.902 103.427 ;
     RECT  26.907 103.421 31.158 103.427 ;
     RECT  34.452 103.421 37.797 103.427 ;
     RECT  39.204 103.277 50.022 103.427 ;
     RECT  50.868 103.379 53.997 103.427 ;
     RECT  58.644 103.379 59.397 103.427 ;
     RECT  60.444 103.379 77.274 103.427 ;
     RECT  78.207 103.157 78.297 103.427 ;
     RECT  80.907 103.379 80.997 103.427 ;
     RECT  83.607 103.157 83.697 103.427 ;
     RECT  86.307 103.157 86.397 103.427 ;
     RECT  89.007 103.157 89.097 103.427 ;
     RECT  91.707 103.157 91.797 103.427 ;
     RECT  94.407 103.157 94.497 103.427 ;
     RECT  97.107 103.157 97.197 103.427 ;
     RECT  99.807 103.157 99.897 103.427 ;
     RECT  31.932 103.421 33.642 103.469 ;
     RECT  35.316 103.427 37.134 103.469 ;
     RECT  54.936 103.373 55.602 103.469 ;
     RECT  56.34 103.379 57.87 103.469 ;
     RECT  60.444 103.427 75.078 103.469 ;
     RECT  75.816 103.427 77.274 103.469 ;
     RECT  79.812 103.109 79.83 103.469 ;
     RECT  27.108 103.427 31.158 103.517 ;
     RECT  54.936 103.469 55.422 103.517 ;
     RECT  60.48 103.469 75.078 103.517 ;
     RECT  55.224 103.517 55.422 103.541 ;
     RECT  56.34 103.469 57.474 103.541 ;
     RECT  60.48 103.517 73.026 103.541 ;
     RECT  73.908 103.517 75.078 103.541 ;
     RECT  30.06 103.517 31.158 103.565 ;
     RECT  39.204 103.427 45.306 103.565 ;
     RECT  46.26 103.427 50.022 103.565 ;
     RECT  55.224 103.541 55.242 103.565 ;
     RECT  56.952 103.541 57.474 103.565 ;
     RECT  58.644 103.427 58.77 103.577 ;
     RECT  27.108 103.517 29.322 103.613 ;
     RECT  50.868 103.427 53.874 103.613 ;
     RECT  58.716 103.577 58.77 103.613 ;
     RECT  71.352 103.541 73.026 103.613 ;
     RECT  73.908 103.541 73.926 103.613 ;
     RECT  72.576 103.613 73.026 103.649 ;
     RECT  76.284 103.469 77.274 103.649 ;
     RECT  31.968 103.469 33.642 103.661 ;
     RECT  71.352 103.613 71.622 103.694 ;
     RECT  76.284 103.649 76.626 103.694 ;
     RECT  27.108 103.613 29.178 103.709 ;
     RECT  31.968 103.661 33.354 103.709 ;
     RECT  71.352 103.694 71.478 103.739 ;
     RECT  74.664 103.541 75.078 103.739 ;
     RECT  30.24 103.565 31.158 103.757 ;
     RECT  31.968 103.709 32.454 103.757 ;
     RECT  33.336 103.709 33.354 103.757 ;
     RECT  40.356 103.565 45.306 103.757 ;
     RECT  50.868 103.613 53.838 103.757 ;
     RECT  65.808 103.541 70.542 103.757 ;
     RECT  71.46 103.739 71.478 103.997 ;
     RECT  76.284 103.694 76.482 103.997 ;
     RECT  73.008 103.649 73.026 104.045 ;
     RECT  35.676 103.469 36.954 104.189 ;
     RECT  30.24 103.757 30.726 104.285 ;
     RECT  35.676 104.189 36.414 104.285 ;
     RECT  50.868 103.757 53.622 104.285 ;
     RECT  58.752 103.613 58.77 104.285 ;
     RECT  75.06 103.739 75.078 104.285 ;
     RECT  40.752 103.757 45.306 104.287 ;
     RECT  46.26 103.565 48.186 104.287 ;
     RECT  48.924 103.565 50.022 104.287 ;
     RECT  60.48 103.541 64.998 104.287 ;
     RECT  40.752 104.287 50.022 104.315 ;
     RECT  30.708 104.285 30.726 104.333 ;
     RECT  59.832 104.287 64.998 104.333 ;
     RECT  76.464 103.997 76.482 104.573 ;
     RECT  66.312 103.757 70.542 104.621 ;
     RECT  27.108 103.709 29.07 104.731 ;
     RECT  57.24 103.565 57.474 104.731 ;
     RECT  60.48 104.333 64.998 104.861 ;
     RECT  24.732 103.427 25.902 104.875 ;
     RECT  27.108 104.731 29.214 104.875 ;
     RECT  39.204 103.565 39.582 104.875 ;
     RECT  40.752 104.315 45.63 104.875 ;
     RECT  60.588 104.861 64.998 105.367 ;
     RECT  50.868 104.285 53.334 105.403 ;
     RECT  60.588 105.367 65.106 105.403 ;
     RECT  31.248 105.451 31.266 105.499 ;
     RECT  71.208 105.451 71.226 105.499 ;
     RECT  57.24 104.731 57.834 105.533 ;
     RECT  31.068 105.499 31.266 105.547 ;
     RECT  39.06 104.875 45.63 105.547 ;
     RECT  46.548 104.315 48.942 105.547 ;
     RECT  50.868 105.403 53.406 105.547 ;
     RECT  24.66 104.875 29.214 105.595 ;
     RECT  35.712 104.285 36.414 105.595 ;
     RECT  60.588 105.403 65.43 105.595 ;
     RECT  66.312 104.621 70.398 105.595 ;
     RECT  73.26 105.547 73.278 105.595 ;
     RECT  57.348 105.533 57.798 105.629 ;
     RECT  35.604 105.595 36.414 105.677 ;
     RECT  71.208 105.499 71.514 105.677 ;
     RECT  24.66 105.595 29.25 105.725 ;
     RECT  30.024 105.595 30.042 105.725 ;
     RECT  30.924 105.547 31.266 105.725 ;
     RECT  34.452 103.427 34.47 105.725 ;
     RECT  35.604 105.677 35.622 105.725 ;
     RECT  36.396 105.677 36.414 105.725 ;
     RECT  50.004 104.315 50.022 105.725 ;
     RECT  54.396 105.499 54.414 105.725 ;
     RECT  57.456 105.629 57.798 105.725 ;
     RECT  60.588 105.595 70.434 105.725 ;
     RECT  71.496 105.677 71.514 105.725 ;
     RECT  73.26 105.595 73.638 105.725 ;
     RECT  39.06 105.547 48.942 105.773 ;
     RECT  50.868 105.547 53.442 105.773 ;
     RECT  51.156 105.773 53.442 105.78 ;
     RECT  24.66 105.725 29.214 105.804 ;
     RECT  39.06 105.773 45.918 105.804 ;
     RECT  47.052 105.773 48.798 105.804 ;
     RECT  51.156 105.78 53.406 105.804 ;
     RECT  60.948 105.725 70.398 105.804 ;
     RECT  41.832 105.804 41.85 105.809 ;
     RECT  45.288 105.804 45.306 105.809 ;
     RECT  65.952 105.804 65.97 105.809 ;
     RECT  70.38 105.804 70.398 105.809 ;
    LAYER M4 ;
     RECT  0.06 47.76 0.371 48.552 ;
     RECT  0.371 47.952 2.408 48.552 ;
     RECT  0.325 54.912 2.408 54.936 ;
     RECT  0.181 66.816 2.408 66.84 ;
     RECT  2.408 2.148 2.512 103.152 ;
     RECT  2.512 2.418 2.6 103.152 ;
     RECT  2.6 2.418 2.704 103.422 ;
     RECT  2.704 47.952 2.729 48.264 ;
     RECT  2.729 48.24 5.108 48.264 ;
     RECT  2.704 54.912 5.108 54.936 ;
     RECT  2.704 66.816 5.108 66.84 ;
     RECT  5.108 2.148 5.212 103.152 ;
     RECT  5.212 2.418 5.3 103.152 ;
     RECT  5.3 2.418 5.404 103.422 ;
     RECT  5.404 48.24 7.808 48.264 ;
     RECT  5.404 54.912 7.808 54.936 ;
     RECT  5.404 66.816 7.808 66.84 ;
     RECT  7.808 2.148 7.912 103.152 ;
     RECT  7.912 2.418 8 103.152 ;
     RECT  8 2.418 8.104 103.422 ;
     RECT  8.104 48.24 10.508 48.264 ;
     RECT  8.104 54.912 10.508 54.936 ;
     RECT  8.104 66.816 10.508 66.84 ;
     RECT  10.508 2.148 10.612 103.152 ;
     RECT  10.612 2.418 10.7 103.152 ;
     RECT  10.7 2.418 10.804 103.422 ;
     RECT  10.804 48.24 13.208 48.264 ;
     RECT  10.804 54.912 13.208 54.936 ;
     RECT  10.804 66.816 13.208 66.84 ;
     RECT  13.208 2.148 13.312 103.152 ;
     RECT  13.312 2.418 13.4 103.152 ;
     RECT  13.4 2.418 13.504 103.422 ;
     RECT  13.504 48.24 15.908 48.264 ;
     RECT  13.504 54.912 15.908 54.936 ;
     RECT  13.504 66.816 15.908 66.84 ;
     RECT  15.908 2.148 16.012 103.152 ;
     RECT  16.012 2.418 16.1 103.152 ;
     RECT  16.1 2.418 16.204 103.422 ;
     RECT  16.204 48.24 18.608 48.264 ;
     RECT  16.204 54.912 18.608 54.936 ;
     RECT  16.204 66.816 18.608 66.84 ;
     RECT  18.608 2.148 18.712 103.152 ;
     RECT  18.712 2.418 18.8 103.152 ;
     RECT  18.8 2.418 18.904 103.422 ;
     RECT  18.904 48.24 21.308 48.264 ;
     RECT  18.904 54.912 21.308 54.936 ;
     RECT  18.904 66.816 21.308 66.84 ;
     RECT  21.308 2.148 21.412 103.152 ;
     RECT  21.412 2.418 21.5 103.152 ;
     RECT  21.5 2.418 21.604 103.422 ;
     RECT  21.604 48.24 24.008 48.264 ;
     RECT  21.604 54.912 24.008 54.936 ;
     RECT  21.604 66.816 24.008 66.84 ;
     RECT  24.008 2.148 24.112 103.152 ;
     RECT  24.112 2.418 24.2 103.152 ;
     RECT  24.2 2.418 24.304 103.422 ;
     RECT  24.649 104.88 24.793 104.904 ;
     RECT  24.304 98.496 25.597 98.76 ;
     RECT  24.304 66.816 26.053 66.84 ;
     RECT  26.017 72.864 26.053 72.888 ;
     RECT  26.053 66.624 26.117 66.84 ;
     RECT  26.117 66.624 26.149 67.272 ;
     RECT  26.108 71.52 26.149 71.544 ;
     RECT  24.304 101.472 26.197 103.368 ;
     RECT  26.197 63.6 26.233 63.624 ;
     RECT  25.729 64.896 26.233 64.92 ;
     RECT  26.197 101.472 26.245 103.416 ;
     RECT  26.233 63.6 26.305 64.92 ;
     RECT  25.729 99.072 26.396 99.192 ;
     RECT  26.305 63.216 26.437 64.92 ;
     RECT  26.149 66.336 26.437 67.272 ;
     RECT  26.245 100.8 26.533 103.416 ;
     RECT  26.341 76.944 26.581 76.968 ;
     RECT  24.304 48.24 26.708 48.264 ;
     RECT  24.304 54.912 26.708 54.936 ;
     RECT  26.125 61.584 26.708 61.608 ;
     RECT  26.437 63.216 26.708 67.272 ;
     RECT  26.233 68.928 26.708 68.952 ;
     RECT  26.149 71.52 26.708 71.64 ;
     RECT  26.053 72.864 26.708 73.8 ;
     RECT  26.108 74.784 26.708 74.808 ;
     RECT  26.581 76.224 26.708 76.968 ;
     RECT  25.837 98.016 26.708 98.04 ;
     RECT  26.396 99.072 26.708 99.72 ;
     RECT  26.533 100.8 26.708 103.512 ;
     RECT  26.708 2.148 26.812 103.512 ;
     RECT  26.812 2.418 27.004 103.512 ;
     RECT  27.004 78.144 27.206 78.696 ;
     RECT  27.004 72.816 27.245 74.376 ;
     RECT  27.206 78.144 27.245 78.648 ;
     RECT  24.793 104.88 27.347 105.768 ;
     RECT  27.004 63.024 27.389 63.528 ;
     RECT  27.004 68.928 27.389 71.64 ;
     RECT  27.004 48.24 27.395 49.8 ;
     RECT  27.395 48.912 27.436 49.8 ;
     RECT  27.004 95.952 27.493 103.512 ;
     RECT  27.493 95.952 27.577 103.752 ;
     RECT  27.389 68.928 27.641 71.304 ;
     RECT  27.641 68.928 27.731 70.728 ;
     RECT  27.004 66.336 27.821 66.84 ;
     RECT  27.821 66.672 27.865 66.84 ;
     RECT  27.245 78.432 27.893 78.648 ;
     RECT  27.389 63.504 27.929 63.528 ;
     RECT  27.347 104.88 27.973 105.672 ;
     RECT  27.004 65.136 27.997 65.16 ;
     RECT  27.004 94.656 27.997 94.68 ;
     RECT  27.577 95.952 27.997 102.504 ;
     RECT  27.997 94.656 28.019 102.504 ;
     RECT  28.019 94.656 28.067 96.936 ;
     RECT  27.731 68.928 28.145 69.048 ;
     RECT  28.019 97.92 28.145 102.504 ;
     RECT  27.004 59.808 28.165 59.832 ;
     RECT  27.893 78.624 28.211 78.648 ;
     RECT  28.067 94.656 28.213 96.888 ;
     RECT  27.245 72.816 28.309 73.272 ;
     RECT  27.004 82.608 28.309 82.632 ;
     RECT  27.731 70.032 28.325 70.728 ;
     RECT  27.004 67.824 28.357 67.848 ;
     RECT  27.004 93.312 28.357 93.336 ;
     RECT  28.145 97.92 28.361 102.072 ;
     RECT  28.325 70.128 28.397 70.728 ;
     RECT  28.165 80.256 28.397 81.048 ;
     RECT  28.309 82.608 28.397 83.256 ;
     RECT  28.357 93.312 28.429 93.384 ;
     RECT  27.245 74.352 28.46 74.376 ;
     RECT  28.309 72.576 28.465 73.272 ;
     RECT  28.46 74.352 28.465 75.048 ;
     RECT  28.165 59.28 28.501 60.216 ;
     RECT  28.465 72.576 28.501 75.048 ;
     RECT  28.397 82.608 28.537 82.632 ;
     RECT  27.004 76.224 28.604 77.16 ;
     RECT  28.397 70.224 28.645 70.728 ;
     RECT  27.577 103.728 28.645 103.752 ;
     RECT  27.973 104.784 28.645 105.672 ;
     RECT  28.501 72.336 28.681 75.048 ;
     RECT  28.604 76.032 28.681 77.256 ;
     RECT  28.645 103.728 28.693 105.672 ;
     RECT  28.693 103.536 28.741 105.672 ;
     RECT  28.556 90.384 28.748 90.408 ;
     RECT  27.004 54.912 28.753 54.936 ;
     RECT  27.865 66.72 28.789 66.84 ;
     RECT  28.357 67.824 28.789 68.712 ;
     RECT  28.681 72.336 28.789 77.256 ;
     RECT  28.748 90.384 28.789 91.176 ;
     RECT  28.429 92.928 28.837 93.384 ;
     RECT  28.213 94.416 28.837 96.888 ;
     RECT  28.501 58.656 28.933 60.216 ;
     RECT  27.004 61.344 28.933 61.368 ;
     RECT  28.741 103.536 28.933 105.72 ;
     RECT  28.537 78.96 28.981 78.984 ;
     RECT  28.397 80.256 28.981 80.952 ;
     RECT  28.789 72.336 29.069 77.304 ;
     RECT  27.997 64.848 29.077 65.16 ;
     RECT  28.789 66.72 29.077 68.712 ;
     RECT  29.069 72.336 29.185 77.544 ;
     RECT  28.981 78.96 29.185 80.952 ;
     RECT  28.837 92.928 29.221 96.888 ;
     RECT  28.361 97.92 29.221 102.024 ;
     RECT  29.249 63.312 29.269 63.336 ;
     RECT  27.436 48.912 29.329 48.936 ;
     RECT  29.329 48.72 29.408 48.936 ;
     RECT  28.753 54.912 29.408 55.272 ;
     RECT  28.933 58.656 29.408 61.368 ;
     RECT  29.269 62.976 29.408 63.336 ;
     RECT  29.077 64.368 29.408 65.16 ;
     RECT  29.077 66.192 29.408 68.712 ;
     RECT  28.645 70.224 29.408 71.304 ;
     RECT  29.185 72.336 29.408 80.952 ;
     RECT  28.537 82.56 29.408 82.632 ;
     RECT  28.789 90.048 29.408 91.176 ;
     RECT  29.221 92.928 29.408 102.024 ;
     RECT  28.933 103.488 29.408 105.72 ;
     RECT  29.408 2.148 29.512 105.72 ;
     RECT  29.512 2.418 29.651 105.72 ;
     RECT  29.651 2.418 29.704 104.28 ;
     RECT  29.704 72.48 29.843 79.08 ;
     RECT  29.704 101.616 29.873 101.64 ;
     RECT  29.704 82.608 29.945 82.632 ;
     RECT  29.843 73.968 30.169 79.08 ;
     RECT  30.169 73.968 30.179 77.64 ;
     RECT  29.704 80.256 30.179 80.424 ;
     RECT  29.704 58.128 30.305 65.16 ;
     RECT  30.305 58.128 30.371 58.152 ;
     RECT  30.179 73.968 30.413 77.496 ;
     RECT  29.704 86.928 30.419 100.296 ;
     RECT  30.419 86.928 30.515 93.624 ;
     RECT  30.413 76.176 30.557 77.496 ;
     RECT  30.169 78.72 30.557 79.08 ;
     RECT  30.515 87.504 30.563 93.624 ;
     RECT  30.563 87.504 30.593 92.952 ;
     RECT  29.704 70.512 30.697 70.68 ;
     RECT  29.704 103.056 30.697 104.28 ;
     RECT  30.179 80.256 30.733 80.28 ;
     RECT  30.697 70.512 30.737 71.112 ;
     RECT  29.704 66.72 30.757 67.944 ;
     RECT  30.697 103.056 30.757 104.328 ;
     RECT  29.651 105.504 30.757 105.72 ;
     RECT  30.305 59.472 30.769 65.16 ;
     RECT  30.757 66.672 30.769 67.944 ;
     RECT  30.593 87.552 30.773 92.952 ;
     RECT  30.413 73.968 30.803 75.192 ;
     RECT  30.773 88.944 30.817 92.952 ;
     RECT  30.419 94.848 30.881 100.296 ;
     RECT  30.769 59.472 30.899 67.944 ;
     RECT  30.757 102.528 30.899 104.328 ;
     RECT  29.843 72.48 30.908 72.936 ;
     RECT  30.908 72.48 30.949 72.984 ;
     RECT  30.899 102.528 30.949 103.752 ;
     RECT  30.949 102 31.045 103.752 ;
     RECT  30.733 79.392 31.061 80.28 ;
     RECT  30.881 97.488 31.129 100.296 ;
     RECT  31.045 101.424 31.129 103.752 ;
     RECT  30.949 72.48 31.133 73.08 ;
     RECT  30.737 71.088 31.201 71.112 ;
     RECT  31.133 72.48 31.201 72.936 ;
     RECT  30.757 105.456 31.277 105.72 ;
     RECT  31.277 105.6 31.283 105.72 ;
     RECT  31.283 105.648 31.321 105.72 ;
     RECT  30.899 59.472 31.345 65.16 ;
     RECT  30.557 77.472 31.345 77.496 ;
     RECT  30.881 94.848 31.381 95.688 ;
     RECT  31.345 77.472 31.525 78.12 ;
     RECT  31.669 83.76 31.849 83.784 ;
     RECT  31.381 94.656 31.849 95.688 ;
     RECT  30.803 74.688 31.885 75.192 ;
     RECT  30.817 90.816 31.885 92.952 ;
     RECT  31.849 94.656 31.885 96.216 ;
     RECT  31.885 90.816 31.909 96.216 ;
     RECT  30.949 69.552 31.957 69.816 ;
     RECT  31.849 83.76 31.957 84.072 ;
     RECT  31.909 90.816 31.957 96.312 ;
     RECT  31.129 97.488 31.957 103.752 ;
     RECT  29.704 48.72 32.108 48.744 ;
     RECT  31.525 49.776 32.108 49.8 ;
     RECT  31.525 53.088 32.108 53.112 ;
     RECT  29.704 54.912 32.108 54.936 ;
     RECT  31.345 59.232 32.108 65.16 ;
     RECT  30.899 66.72 32.108 67.944 ;
     RECT  31.957 69.552 32.108 70.104 ;
     RECT  31.201 71.088 32.108 72.936 ;
     RECT  31.885 74.592 32.108 75.192 ;
     RECT  30.557 76.176 32.108 76.344 ;
     RECT  31.525 77.472 32.108 78.312 ;
     RECT  31.061 80.016 32.108 80.28 ;
     RECT  31.921 81.456 32.108 81.48 ;
     RECT  31.957 82.848 32.108 84.072 ;
     RECT  29.704 85.92 32.108 85.944 ;
     RECT  30.773 87.552 32.108 87.912 ;
     RECT  30.817 88.944 32.108 89.496 ;
     RECT  31.957 90.816 32.108 103.752 ;
     RECT  32.108 2.148 32.212 103.752 ;
     RECT  31.321 105.648 32.243 105.672 ;
     RECT  32.212 2.418 32.404 103.752 ;
     RECT  32.404 90.816 32.429 90.936 ;
     RECT  32.404 62.112 32.501 67.944 ;
     RECT  32.404 92.208 32.537 103.752 ;
     RECT  32.501 62.112 32.573 67.848 ;
     RECT  32.404 78.624 32.771 85.224 ;
     RECT  32.537 92.208 32.789 98.376 ;
     RECT  32.771 81.456 32.933 85.224 ;
     RECT  32.573 63.264 33.005 67.848 ;
     RECT  32.771 78.624 33.005 79.752 ;
     RECT  32.933 81.456 33.005 84.936 ;
     RECT  33.005 63.264 33.041 66.84 ;
     RECT  33.005 83.472 33.041 84.936 ;
     RECT  32.789 92.208 33.077 95.784 ;
     RECT  32.789 97.104 33.077 98.376 ;
     RECT  33.041 63.36 33.113 66.84 ;
     RECT  32.404 71.952 33.113 73.08 ;
     RECT  33.041 84.912 33.113 84.936 ;
     RECT  33.077 93.744 33.149 95.784 ;
     RECT  32.537 101.328 33.149 103.752 ;
     RECT  33.149 93.792 33.203 95.784 ;
     RECT  33.005 81.456 33.329 82.2 ;
     RECT  33.149 101.712 33.365 103.752 ;
     RECT  32.404 74.592 33.433 74.952 ;
     RECT  32.404 59.136 33.437 60.696 ;
     RECT  33.005 78.624 33.437 79.512 ;
     RECT  32.404 86.496 33.437 87.96 ;
     RECT  32.537 99.744 33.437 99.768 ;
     RECT  32.404 51.216 33.443 53.112 ;
     RECT  33.437 86.496 33.541 87.624 ;
     RECT  32.429 90.912 33.541 90.936 ;
     RECT  32.404 48.72 33.577 50.04 ;
     RECT  33.443 51.216 33.577 51.72 ;
     RECT  33.005 67.824 33.577 67.848 ;
     RECT  32.404 70.08 33.613 70.92 ;
     RECT  33.613 69.504 33.637 70.92 ;
     RECT  33.113 71.952 33.637 72.36 ;
     RECT  33.433 74.592 33.653 75.048 ;
     RECT  33.041 83.472 33.653 83.64 ;
     RECT  33.637 69.504 33.683 72.36 ;
     RECT  32.404 54.912 33.685 54.936 ;
     RECT  33.683 69.504 33.697 69.816 ;
     RECT  33.577 67.824 33.761 67.944 ;
     RECT  33.443 53.088 33.829 53.112 ;
     RECT  32.573 62.112 33.829 62.136 ;
     RECT  33.437 59.136 33.901 60.312 ;
     RECT  33.077 92.208 33.925 92.712 ;
     RECT  33.653 74.64 34.009 75.048 ;
     RECT  33.653 83.616 34.009 83.64 ;
     RECT  33.113 63.36 34.117 63.384 ;
     RECT  33.113 64.704 34.117 65.16 ;
     RECT  33.925 92.16 34.117 92.712 ;
     RECT  33.203 93.792 34.117 95.16 ;
     RECT  32.404 76.224 34.153 76.536 ;
     RECT  33.365 101.712 34.165 103.656 ;
     RECT  33.577 56.64 34.189 56.664 ;
     RECT  32.404 89.088 34.189 89.496 ;
     RECT  34.117 92.16 34.213 95.16 ;
     RECT  33.077 97.104 34.261 97.368 ;
     RECT  33.077 98.352 34.261 98.376 ;
     RECT  33.541 90.528 34.297 90.936 ;
     RECT  34.213 91.968 34.297 95.16 ;
     RECT  33.437 78.624 34.309 79.416 ;
     RECT  33.329 81.84 34.309 82.2 ;
     RECT  34.261 97.104 34.309 98.376 ;
     RECT  33.829 61.344 34.333 62.136 ;
     RECT  34.117 63.36 34.333 65.16 ;
     RECT  33.761 67.872 34.333 67.944 ;
     RECT  33.637 105.648 34.357 105.672 ;
     RECT  33.829 53.088 34.369 53.928 ;
     RECT  33.685 54.912 34.369 55.32 ;
     RECT  34.357 105.552 34.397 105.672 ;
     RECT  34.369 53.088 34.405 55.32 ;
     RECT  34.009 83.616 34.405 84.168 ;
     RECT  34.165 101.184 34.412 103.656 ;
     RECT  34.189 88.656 34.441 89.496 ;
     RECT  34.297 90.528 34.441 95.16 ;
     RECT  34.397 105.552 34.481 105.72 ;
     RECT  33.901 58.992 34.549 60.312 ;
     RECT  33.541 86.016 34.549 87.624 ;
     RECT  34.549 58.704 34.585 60.312 ;
     RECT  34.309 97.104 34.597 98.664 ;
     RECT  34.597 97.104 34.645 99.576 ;
     RECT  33.697 69.792 34.693 69.816 ;
     RECT  34.412 101.184 34.693 103.752 ;
     RECT  34.549 85.776 34.729 87.624 ;
     RECT  34.441 88.656 34.729 95.16 ;
     RECT  33.683 70.896 34.765 72.36 ;
     RECT  34.22 73.392 34.765 73.416 ;
     RECT  34.693 100.8 34.789 103.752 ;
     RECT  33.577 48.72 34.808 51.72 ;
     RECT  34.405 52.8 34.808 55.32 ;
     RECT  34.189 56.496 34.808 56.664 ;
     RECT  34.585 57.936 34.808 60.312 ;
     RECT  34.333 61.344 34.808 65.16 ;
     RECT  33.113 66.144 34.808 66.84 ;
     RECT  34.333 67.872 34.808 68.328 ;
     RECT  34.693 69.792 34.808 69.864 ;
     RECT  34.765 70.896 34.808 73.416 ;
     RECT  34.009 74.64 34.808 75.144 ;
     RECT  34.153 76.224 34.808 77.496 ;
     RECT  34.309 78.48 34.808 79.416 ;
     RECT  34.309 81.024 34.808 82.2 ;
     RECT  34.405 83.616 34.808 84.6 ;
     RECT  34.729 85.776 34.808 95.16 ;
     RECT  34.645 96.384 34.808 99.576 ;
     RECT  34.789 100.8 34.808 104.28 ;
     RECT  34.481 105.552 34.885 105.672 ;
     RECT  34.808 2.148 34.912 104.28 ;
     RECT  34.912 2.418 35.104 104.28 ;
     RECT  35.104 79.728 35.201 95.16 ;
     RECT  35.201 79.728 35.309 87.336 ;
     RECT  35.104 54.336 35.315 59.256 ;
     RECT  35.315 56.688 35.345 59.256 ;
     RECT  34.885 105.36 35.365 105.672 ;
     RECT  35.104 66.528 35.381 67.464 ;
     RECT  35.309 79.728 35.381 87.144 ;
     RECT  35.345 57.936 35.417 59.256 ;
     RECT  35.365 105.312 35.461 105.672 ;
     RECT  35.104 68.832 35.699 70.92 ;
     RECT  35.381 80.64 35.885 87.144 ;
     RECT  35.104 76.752 35.957 76.92 ;
     RECT  35.417 58.128 36.133 59.256 ;
     RECT  35.104 60.288 36.133 60.312 ;
     RECT  35.699 68.88 36.133 70.92 ;
     RECT  35.104 71.952 36.133 75.144 ;
     RECT  35.104 96.48 36.133 104.28 ;
     RECT  35.461 105.312 36.133 105.72 ;
     RECT  35.315 54.336 36.173 55.704 ;
     RECT  35.104 44.544 36.179 45.912 ;
     RECT  35.104 47.856 36.179 49.512 ;
     RECT  36.133 58.128 36.205 60.312 ;
     RECT  35.104 61.632 36.205 65.16 ;
     RECT  35.345 56.688 36.209 56.712 ;
     RECT  36.133 68.88 36.209 75.144 ;
     RECT  36.133 96.48 36.277 105.72 ;
     RECT  36.277 96.288 36.371 105.72 ;
     RECT  35.381 66.672 36.385 67.464 ;
     RECT  36.371 105.696 36.425 105.72 ;
     RECT  36.371 96.288 36.46 104.184 ;
     RECT  36.205 58.128 36.461 65.16 ;
     RECT  36.461 58.704 36.467 65.16 ;
     RECT  36.467 61.968 36.493 65.16 ;
     RECT  36.385 66.576 36.493 67.464 ;
     RECT  35.885 80.88 36.533 87.144 ;
     RECT  35.201 88.464 36.565 95.16 ;
     RECT  36.46 96.288 36.565 103.08 ;
     RECT  35.104 78.48 36.601 78.6 ;
     RECT  36.179 44.544 36.637 45.624 ;
     RECT  35.957 76.752 36.637 76.776 ;
     RECT  36.179 47.856 36.817 48.264 ;
     RECT  36.601 78.48 36.961 78.792 ;
     RECT  36.46 104.16 36.965 104.184 ;
     RECT  36.209 70.512 37.033 75.144 ;
     RECT  36.637 76.512 37.033 76.776 ;
     RECT  36.637 44.352 37.177 45.624 ;
     RECT  36.961 78.48 37.213 79.464 ;
     RECT  37.177 43.392 37.237 45.624 ;
     RECT  35.104 50.88 37.381 53.112 ;
     RECT  36.173 54.336 37.381 55.56 ;
     RECT  36.179 49.44 37.393 49.512 ;
     RECT  37.381 50.88 37.393 55.56 ;
     RECT  36.533 80.88 37.501 86.76 ;
     RECT  35.104 23.568 37.508 23.592 ;
     RECT  36.853 40.32 37.508 40.344 ;
     RECT  37.237 43.392 37.508 46.2 ;
     RECT  36.817 47.328 37.508 48.264 ;
     RECT  37.393 49.44 37.508 55.56 ;
     RECT  36.637 57.696 37.508 57.72 ;
     RECT  36.467 58.704 37.508 60.84 ;
     RECT  36.493 61.968 37.508 67.464 ;
     RECT  36.209 68.88 37.508 68.904 ;
     RECT  37.033 70.512 37.508 76.776 ;
     RECT  37.213 78.48 37.508 79.56 ;
     RECT  37.501 80.832 37.508 86.76 ;
     RECT  36.565 88.464 37.508 103.08 ;
     RECT  37.508 2.148 37.612 103.152 ;
     RECT  37.612 2.418 37.7 103.152 ;
     RECT  37.7 2.418 37.804 103.422 ;
     RECT  37.804 80.832 37.901 99.768 ;
     RECT  37.804 70.8 37.955 79.752 ;
     RECT  37.804 56.688 37.973 65.16 ;
     RECT  37.901 80.832 37.973 83.016 ;
     RECT  37.955 70.8 38.009 79.512 ;
     RECT  37.901 84.096 38.045 99.768 ;
     RECT  38.045 97.776 38.189 99.768 ;
     RECT  37.973 58.656 38.195 65.16 ;
     RECT  37.804 39.84 38.243 41.112 ;
     RECT  37.804 48.24 38.333 55.272 ;
     RECT  38.045 84.096 38.405 96.792 ;
     RECT  38.243 41.088 38.441 41.112 ;
     RECT  38.405 84.096 38.585 93.432 ;
     RECT  37.804 42.624 38.675 45.288 ;
     RECT  37.973 81.216 38.693 83.016 ;
     RECT  38.693 81.216 38.723 82.872 ;
     RECT  37.804 69.264 38.765 69.288 ;
     RECT  38.009 70.8 38.765 79.32 ;
     RECT  38.765 72 38.801 79.32 ;
     RECT  37.804 66.576 38.837 67.128 ;
     RECT  38.876 70.512 38.963 70.536 ;
     RECT  38.195 61.344 38.981 65.16 ;
     RECT  38.333 50.16 39.017 55.272 ;
     RECT  39.017 54.144 39.107 55.272 ;
     RECT  39.049 104.88 39.121 104.904 ;
     RECT  37.973 56.688 39.125 57.576 ;
     RECT  38.405 94.416 39.193 96.792 ;
     RECT  38.189 97.776 39.193 99.576 ;
     RECT  39.157 102 39.205 102.024 ;
     RECT  37.804 103.056 39.205 103.08 ;
     RECT  39.121 104.88 39.205 105 ;
     RECT  38.195 58.656 39.229 60.36 ;
     RECT  38.981 61.344 39.229 62.472 ;
     RECT  39.121 68.352 39.229 68.376 ;
     RECT  38.585 88.368 39.233 93.432 ;
     RECT  39.107 54.384 39.301 55.272 ;
     RECT  39.125 56.688 39.301 57.288 ;
     RECT  38.981 63.552 39.397 65.16 ;
     RECT  38.837 66.576 39.397 66.984 ;
     RECT  39.193 94.416 39.445 99.576 ;
     RECT  38.723 81.216 39.481 82.776 ;
     RECT  38.333 48.24 39.553 48.984 ;
     RECT  39.445 94.416 39.589 99.72 ;
     RECT  39.26 100.848 39.589 100.872 ;
     RECT  39.205 102 39.589 103.08 ;
     RECT  39.205 104.88 39.625 105.048 ;
     RECT  39.589 94.416 39.788 100.872 ;
     RECT  39.589 102 39.788 103.32 ;
     RECT  38.675 43.152 39.841 45.288 ;
     RECT  39.841 43.152 39.877 46.248 ;
     RECT  39.788 94.416 39.877 103.32 ;
     RECT  39.481 81.12 39.913 82.776 ;
     RECT  39.877 94.416 40.057 103.368 ;
     RECT  39.017 50.16 40.165 53.112 ;
     RECT  39.301 54.384 40.165 57.288 ;
     RECT  40.057 94.416 40.165 103.56 ;
     RECT  37.804 23.568 40.208 23.592 ;
     RECT  38.243 39.84 40.208 39.864 ;
     RECT  39.26 41.376 40.208 41.88 ;
     RECT  39.877 43.104 40.208 46.248 ;
     RECT  39.553 47.76 40.208 48.984 ;
     RECT  40.165 50.16 40.208 57.288 ;
     RECT  39.229 58.656 40.208 62.472 ;
     RECT  39.397 63.552 40.208 66.984 ;
     RECT  39.229 68.064 40.208 68.376 ;
     RECT  38.917 69.504 40.208 69.528 ;
     RECT  38.801 72 40.208 73.368 ;
     RECT  38.801 74.352 40.208 79.32 ;
     RECT  39.913 81.072 40.208 82.776 ;
     RECT  38.585 84.096 40.208 87.144 ;
     RECT  39.233 88.464 40.208 93.432 ;
     RECT  40.165 94.416 40.208 103.752 ;
     RECT  40.208 2.148 40.312 103.752 ;
     RECT  40.312 2.418 40.385 103.752 ;
     RECT  40.385 2.418 40.504 103.56 ;
     RECT  40.504 71.376 40.601 78.168 ;
     RECT  40.504 79.248 40.601 103.56 ;
     RECT  40.504 61.968 40.643 65.592 ;
     RECT  40.601 73.296 40.643 78.168 ;
     RECT  40.504 50.112 40.745 59.016 ;
     RECT  40.643 73.296 40.781 75.048 ;
     RECT  40.781 74.64 40.787 75.048 ;
     RECT  40.745 50.112 40.997 56.664 ;
     RECT  40.997 50.112 41.027 56.52 ;
     RECT  40.601 79.248 41.027 103.368 ;
     RECT  41.027 51.6 41.029 56.52 ;
     RECT  41.027 79.248 41.033 97.32 ;
     RECT  40.504 60.24 41.105 60.792 ;
     RECT  40.781 73.296 41.105 73.416 ;
     RECT  41.027 99.744 41.141 103.368 ;
     RECT  41.033 79.248 41.177 97.272 ;
     RECT  41.177 79.248 41.213 97.032 ;
     RECT  40.504 38.688 41.219 41.16 ;
     RECT  40.504 46.224 41.429 47.88 ;
     RECT  41.027 50.112 41.429 50.136 ;
     RECT  40.643 61.968 41.429 63.288 ;
     RECT  41.027 98.736 41.429 98.76 ;
     RECT  41.141 99.744 41.452 103.224 ;
     RECT  41.213 79.248 41.537 86.856 ;
     RECT  41.452 100.752 41.573 103.224 ;
     RECT  41.573 102.624 41.603 103.224 ;
     RECT  39.625 104.88 41.609 105.768 ;
     RECT  40.504 66.816 41.633 68.184 ;
     RECT  40.504 69.456 41.633 69.48 ;
     RECT  41.603 103.2 41.645 103.224 ;
     RECT  41.219 40.656 41.677 41.16 ;
     RECT  40.504 48.96 41.677 48.984 ;
     RECT  41.213 87.936 41.689 97.032 ;
     RECT  41.429 47.04 41.713 47.88 ;
     RECT  41.677 48.96 41.713 49.032 ;
     RECT  40.643 64.704 41.753 65.592 ;
     RECT  41.537 79.776 41.753 86.856 ;
     RECT  41.689 87.936 41.753 92.616 ;
     RECT  41.105 73.344 41.785 73.416 ;
     RECT  41.753 80.016 41.789 86.856 ;
     RECT  41.677 40.656 41.795 41.976 ;
     RECT  40.601 71.376 41.797 72.264 ;
     RECT  41.797 70.512 41.884 72.264 ;
     RECT  41.219 38.688 41.897 38.712 ;
     RECT  41.884 70.656 41.905 72.264 ;
     RECT  40.504 43.008 42.073 43.128 ;
     RECT  40.504 44.112 42.073 44.904 ;
     RECT  41.753 64.704 42.145 64.728 ;
     RECT  41.795 40.656 42.181 41.208 ;
     RECT  41.029 51.648 42.181 56.52 ;
     RECT  40.745 57.792 42.181 59.016 ;
     RECT  41.905 71.376 42.289 72.264 ;
     RECT  41.785 73.344 42.289 73.992 ;
     RECT  41.429 61.968 42.325 62.472 ;
     RECT  42.073 43.008 42.469 44.904 ;
     RECT  41.713 47.04 42.613 49.032 ;
     RECT  41.105 60.768 42.613 60.792 ;
     RECT  42.469 43.008 42.685 45.48 ;
     RECT  42.685 42.576 42.757 45.48 ;
     RECT  41.753 91.344 42.757 92.616 ;
     RECT  41.689 93.792 42.757 97.032 ;
     RECT  41.452 99.744 42.757 99.768 ;
     RECT  41.609 105.744 42.757 105.768 ;
     RECT  42.181 51.648 42.793 59.016 ;
     RECT  42.613 60.096 42.793 60.792 ;
     RECT  42.613 46.752 42.829 49.032 ;
     RECT  41.789 80.016 42.865 81.192 ;
     RECT  41.789 82.224 42.865 86.856 ;
     RECT  42.181 39.744 42.901 41.208 ;
     RECT  40.504 23.568 42.908 23.592 ;
     RECT  42.901 39.312 42.908 41.208 ;
     RECT  42.757 42.576 42.908 45.528 ;
     RECT  42.829 46.512 42.908 49.032 ;
     RECT  42.793 51.648 42.908 60.792 ;
     RECT  42.325 61.92 42.908 62.472 ;
     RECT  42.145 64.176 42.908 64.728 ;
     RECT  41.633 66.816 42.908 69.48 ;
     RECT  42.289 71.376 42.908 73.992 ;
     RECT  40.787 75.024 42.908 75.048 ;
     RECT  40.643 76.272 42.908 78.168 ;
     RECT  42.865 80.016 42.908 86.856 ;
     RECT  41.753 87.936 42.908 90.36 ;
     RECT  42.757 91.344 42.908 97.032 ;
     RECT  42.757 99.072 42.908 99.768 ;
     RECT  41.573 100.752 42.908 101.208 ;
     RECT  42.908 2.148 43.012 103.152 ;
     RECT  43.012 2.418 43.1 103.152 ;
     RECT  43.1 2.418 43.204 103.422 ;
     RECT  43.204 39.312 43.331 39.336 ;
     RECT  43.204 88.32 43.331 100.92 ;
     RECT  43.331 88.32 43.453 100.344 ;
     RECT  43.204 58.512 43.517 67.272 ;
     RECT  43.204 46.8 43.589 47.304 ;
     RECT  43.204 52.992 43.589 57.336 ;
     RECT  43.453 88.32 43.625 100.248 ;
     RECT  43.204 81.072 43.769 87.144 ;
     RECT  43.589 52.992 43.805 56.52 ;
     RECT  43.204 79.008 43.9 79.944 ;
     RECT  43.204 48.72 43.907 48.984 ;
     RECT  43.769 81.072 43.913 86.952 ;
     RECT  43.517 58.656 43.985 67.272 ;
     RECT  43.204 71.232 44.003 77.544 ;
     RECT  43.204 40.56 44.341 41.496 ;
     RECT  43.9 79.008 44.413 79.512 ;
     RECT  42.757 104.88 44.417 105.768 ;
     RECT  43.625 88.752 44.437 100.248 ;
     RECT  44.003 71.232 44.483 74.856 ;
     RECT  43.913 81.072 44.581 81.432 ;
     RECT  44.003 76.272 44.593 77.544 ;
     RECT  44.413 78.72 44.593 79.512 ;
     RECT  43.589 47.136 44.629 47.304 ;
     RECT  43.805 52.992 44.633 55.992 ;
     RECT  44.197 57.6 44.665 57.624 ;
     RECT  43.985 58.656 44.665 66.936 ;
     RECT  44.341 40.416 44.737 41.496 ;
     RECT  44.629 42.72 44.737 42.744 ;
     RECT  44.483 71.232 44.737 74.616 ;
     RECT  44.633 53.088 44.773 55.992 ;
     RECT  44.773 53.088 44.845 56.28 ;
     RECT  44.665 57.6 44.845 66.936 ;
     RECT  44.737 40.416 44.881 42.744 ;
     RECT  43.204 43.776 44.881 45.528 ;
     RECT  43.913 82.704 44.917 86.952 ;
     RECT  44.881 40.416 45.025 45.528 ;
     RECT  44.629 46.848 45.025 47.304 ;
     RECT  44.845 53.088 45.025 66.936 ;
     RECT  45.025 40.416 45.133 47.304 ;
     RECT  44.581 80.928 45.169 81.432 ;
     RECT  44.917 82.704 45.169 87.24 ;
     RECT  44.437 88.752 45.169 101.064 ;
     RECT  44.417 105.6 45.445 105.768 ;
     RECT  45.169 80.928 45.565 81.48 ;
     RECT  45.445 104.88 45.569 105.768 ;
     RECT  43.204 23.568 45.608 23.592 ;
     RECT  45.133 40.416 45.608 47.4 ;
     RECT  43.907 48.72 45.608 48.744 ;
     RECT  44.399 50.16 45.608 50.184 ;
     RECT  43.204 51.504 45.608 51.768 ;
     RECT  45.025 53.088 45.608 67.704 ;
     RECT  44.737 70.656 45.608 74.616 ;
     RECT  44.593 76.272 45.608 79.512 ;
     RECT  45.565 80.832 45.608 81.48 ;
     RECT  45.169 82.704 45.608 101.64 ;
     RECT  45.608 2.148 45.712 103.152 ;
     RECT  45.712 2.418 45.8 103.152 ;
     RECT  45.8 2.418 45.904 103.422 ;
     RECT  45.904 43.104 45.965 55.272 ;
     RECT  45.904 61.2 45.965 65.736 ;
     RECT  45.904 56.352 46.037 60.12 ;
     RECT  45.904 80.592 46.163 101.928 ;
     RECT  46.163 80.592 46.181 81.432 ;
     RECT  45.965 61.2 46.217 62.52 ;
     RECT  45.904 66.816 46.217 67.704 ;
     RECT  46.217 61.2 46.289 61.224 ;
     RECT  45.965 43.104 46.355 55.224 ;
     RECT  45.904 73.344 46.433 74.616 ;
     RECT  45.904 37.584 46.499 39.336 ;
     RECT  46.355 43.104 46.505 49.032 ;
     RECT  46.499 38.208 46.613 39.336 ;
     RECT  45.904 76.272 46.691 77.976 ;
     RECT  46.037 58.56 46.835 60.12 ;
     RECT  46.505 43.104 46.897 48.744 ;
     RECT  45.965 63.792 46.937 65.736 ;
     RECT  46.613 38.544 46.981 39.336 ;
     RECT  46.937 64.656 47.005 65.736 ;
     RECT  46.217 66.816 47.005 67.08 ;
     RECT  46.037 56.352 47.009 57.24 ;
     RECT  46.981 38.544 47.017 39.912 ;
     RECT  45.904 41.136 47.027 41.16 ;
     RECT  46.835 58.656 47.041 60.12 ;
     RECT  46.181 80.592 47.041 81.288 ;
     RECT  45.569 105.552 47.141 105.768 ;
     RECT  46.163 82.416 47.221 101.928 ;
     RECT  47.041 80.544 47.228 81.288 ;
     RECT  46.217 62.448 47.315 62.52 ;
     RECT  47.468 35.088 47.509 35.112 ;
     RECT  47.005 64.656 47.612 67.08 ;
     RECT  46.355 50.112 47.653 55.224 ;
     RECT  45.904 79.104 47.689 79.128 ;
     RECT  47.228 80.496 47.689 81.288 ;
     RECT  47.221 82.416 47.689 102.024 ;
     RECT  46.691 77.952 47.701 77.976 ;
     RECT  47.689 79.104 47.761 79.224 ;
     RECT  47.689 80.496 47.761 102.024 ;
     RECT  46.897 42.96 47.797 48.744 ;
     RECT  47.653 49.776 47.797 55.224 ;
     RECT  47.612 64.656 47.941 67.56 ;
     RECT  47.941 63.888 47.977 67.56 ;
     RECT  47.761 79.104 48.013 102.024 ;
     RECT  47.041 58.656 48.049 61.032 ;
     RECT  47.437 41.616 48.181 41.64 ;
     RECT  47.009 56.352 48.265 57 ;
     RECT  45.904 23.568 48.308 23.592 ;
     RECT  47.509 34.128 48.308 35.112 ;
     RECT  47.221 36.096 48.308 36.12 ;
     RECT  47.893 37.92 48.308 37.944 ;
     RECT  47.017 39.312 48.308 39.912 ;
     RECT  48.181 41.136 48.308 41.64 ;
     RECT  47.797 42.96 48.308 55.224 ;
     RECT  48.265 56.304 48.308 57 ;
     RECT  48.049 58.656 48.308 61.464 ;
     RECT  47.315 62.496 48.308 62.52 ;
     RECT  47.977 63.792 48.308 67.56 ;
     RECT  45.904 72 48.308 72.264 ;
     RECT  46.433 73.344 48.308 74.136 ;
     RECT  46.691 76.272 48.308 76.872 ;
     RECT  47.701 77.952 48.308 78.12 ;
     RECT  48.013 79.104 48.308 102.504 ;
     RECT  48.308 2.148 48.373 103.152 ;
     RECT  48.373 2.148 48.412 103.56 ;
     RECT  48.412 2.418 48.46 103.56 ;
     RECT  48.46 2.418 48.604 103.422 ;
     RECT  47.141 104.88 48.755 105.768 ;
     RECT  48.604 39.312 48.773 41.928 ;
     RECT  48.755 104.928 48.853 105.768 ;
     RECT  48.853 105.744 48.899 105.768 ;
     RECT  48.604 76.272 48.953 76.968 ;
     RECT  48.604 56.304 48.989 56.856 ;
     RECT  48.604 73.344 48.989 74.136 ;
     RECT  48.604 63.552 48.995 67.08 ;
     RECT  48.604 80.256 49.133 103.368 ;
     RECT  48.604 44.16 49.379 44.712 ;
     RECT  48.604 45.696 49.421 50.568 ;
     RECT  48.995 63.984 49.529 67.08 ;
     RECT  48.989 56.304 49.597 56.328 ;
     RECT  49.379 44.352 49.601 44.712 ;
     RECT  48.604 77.952 49.637 79.224 ;
     RECT  49.133 80.592 49.637 103.368 ;
     RECT  49.637 81.072 49.861 103.368 ;
     RECT  49.861 105.072 49.949 105.096 ;
     RECT  49.597 56.064 49.957 56.328 ;
     RECT  49.861 81.072 49.964 103.656 ;
     RECT  49.949 105.072 50.003 105.72 ;
     RECT  48.773 39.312 50.029 40.92 ;
     RECT  48.773 41.904 50.029 41.928 ;
     RECT  50.003 105.648 50.033 105.72 ;
     RECT  49.964 81.072 50.051 103.752 ;
     RECT  49.529 64.32 50.165 67.08 ;
     RECT  48.604 58.416 50.209 62.184 ;
     RECT  48.604 72 50.341 72.264 ;
     RECT  48.989 73.344 50.341 73.848 ;
     RECT  50.029 39.312 50.425 42.216 ;
     RECT  48.604 51.696 50.437 54.936 ;
     RECT  49.957 56.064 50.437 56.904 ;
     RECT  50.165 64.32 50.437 67.224 ;
     RECT  50.437 51.696 50.544 56.904 ;
     RECT  49.601 44.4 50.641 44.712 ;
     RECT  49.421 45.696 50.641 47.688 ;
     RECT  50.641 44.4 50.713 47.688 ;
     RECT  50.341 72 50.713 73.848 ;
     RECT  48.953 76.272 50.749 76.296 ;
     RECT  49.637 77.952 50.749 78.648 ;
     RECT  50.425 39.264 50.78 42.216 ;
     RECT  50.78 39.264 50.785 43.176 ;
     RECT  50.713 44.16 50.785 47.688 ;
     RECT  49.421 48.672 50.785 50.568 ;
     RECT  50.544 51.696 50.785 57 ;
     RECT  50.713 72 50.821 74.424 ;
     RECT  50.821 72 50.857 74.616 ;
     RECT  49.597 35.712 50.869 35.736 ;
     RECT  50.389 37.056 50.869 37.08 ;
     RECT  50.857 72 50.869 74.712 ;
     RECT  50.749 76.272 50.869 78.648 ;
     RECT  50.785 48.672 50.965 57 ;
     RECT  48.604 23.568 51.008 23.592 ;
     RECT  50.629 29.28 51.008 29.304 ;
     RECT  50.869 35.328 51.008 37.08 ;
     RECT  49.633 38.208 51.008 38.232 ;
     RECT  50.785 39.264 51.008 47.688 ;
     RECT  50.965 48.672 51.008 57.048 ;
     RECT  50.209 58.416 51.008 62.28 ;
     RECT  50.165 63.264 51.008 63.288 ;
     RECT  50.437 64.32 51.008 67.368 ;
     RECT  50.869 70.656 51.008 70.68 ;
     RECT  50.869 72 51.008 78.648 ;
     RECT  50.137 79.824 51.008 79.848 ;
     RECT  50.051 81.072 51.008 103.656 ;
     RECT  51.008 2.148 51.112 103.656 ;
     RECT  50.033 105.648 51.145 105.672 ;
     RECT  51.112 2.418 51.251 103.656 ;
     RECT  51.145 105.552 51.301 105.672 ;
     RECT  51.251 2.418 51.304 103.422 ;
     RECT  51.304 37.056 51.437 40.92 ;
     RECT  51.437 37.056 51.473 39.384 ;
     RECT  51.301 105.456 51.493 105.672 ;
     RECT  51.304 50.736 51.509 61.56 ;
     RECT  51.304 71.952 51.553 79.128 ;
     RECT  51.493 105.456 51.637 105.72 ;
     RECT  51.509 50.736 51.689 60.12 ;
     RECT  51.689 50.736 51.731 57.624 ;
     RECT  51.304 43.824 51.797 47.688 ;
     RECT  51.731 56.016 51.869 57.624 ;
     RECT  51.869 56.016 51.905 57.048 ;
     RECT  51.689 58.656 51.905 60.12 ;
     RECT  51.304 48.672 51.941 49.56 ;
     RECT  51.304 80.352 52.201 103.416 ;
     RECT  52.201 80.352 52.211 90.36 ;
     RECT  51.637 104.88 52.297 105.72 ;
     RECT  51.437 40.56 52.301 40.92 ;
     RECT  51.553 72 52.333 79.128 ;
     RECT  52.211 80.352 52.333 89.304 ;
     RECT  51.509 61.296 52.357 61.56 ;
     RECT  51.304 33.648 52.481 34.008 ;
     RECT  52.201 91.344 52.481 103.416 ;
     RECT  51.304 68.496 52.549 69.336 ;
     RECT  52.481 91.344 52.589 91.656 ;
     RECT  51.304 42.144 52.657 42.168 ;
     RECT  51.473 38.688 52.661 39.384 ;
     RECT  51.905 56.064 52.697 57.048 ;
     RECT  51.731 50.736 52.729 54.936 ;
     RECT  52.481 92.88 52.789 103.416 ;
     RECT  52.301 40.896 52.837 40.92 ;
     RECT  52.657 42.144 52.837 42.552 ;
     RECT  52.297 104.88 52.849 105.768 ;
     RECT  52.849 105.264 52.979 105.768 ;
     RECT  51.304 64.32 53.017 67.368 ;
     RECT  53.017 64.224 53.029 67.368 ;
     RECT  53.029 63.84 53.053 67.368 ;
     RECT  52.549 68.496 53.053 70.056 ;
     RECT  51.797 44.16 53.077 47.688 ;
     RECT  51.941 48.672 53.077 49.272 ;
     RECT  51.905 58.992 53.077 60.12 ;
     RECT  52.357 61.296 53.077 62.184 ;
     RECT  53.077 58.992 53.125 62.184 ;
     RECT  52.729 50.304 53.133 54.936 ;
     RECT  52.697 56.064 53.133 56.712 ;
     RECT  53.053 57.696 53.161 57.72 ;
     RECT  53.125 58.704 53.161 62.712 ;
     RECT  52.481 33.984 53.269 34.008 ;
     RECT  53.233 35.04 53.269 35.064 ;
     RECT  52.661 38.736 53.305 39.384 ;
     RECT  52.979 105.312 53.453 105.768 ;
     RECT  53.077 44.16 53.485 49.272 ;
     RECT  53.133 50.304 53.485 56.712 ;
     RECT  52.789 92.88 53.509 103.464 ;
     RECT  53.509 92.88 53.521 103.512 ;
     RECT  52.589 91.344 53.557 91.368 ;
     RECT  53.305 38.736 53.593 39.912 ;
     RECT  52.837 40.896 53.593 42.552 ;
     RECT  53.485 44.16 53.593 56.712 ;
     RECT  53.521 92.88 53.593 103.656 ;
     RECT  53.161 57.696 53.629 62.712 ;
     RECT  53.053 63.84 53.629 70.92 ;
     RECT  53.557 91.344 53.629 91.896 ;
     RECT  53.593 92.88 53.629 104.28 ;
     RECT  51.304 23.568 53.708 23.592 ;
     RECT  51.304 29.28 53.708 29.304 ;
     RECT  53.269 33.984 53.708 35.064 ;
     RECT  51.473 37.056 53.708 37.656 ;
     RECT  53.593 38.736 53.708 56.712 ;
     RECT  53.629 57.696 53.708 70.92 ;
     RECT  52.333 72 53.708 89.304 ;
     RECT  52.211 90.288 53.708 90.36 ;
     RECT  53.629 91.344 53.708 104.28 ;
     RECT  53.708 2.148 53.795 104.28 ;
     RECT  53.795 2.148 53.812 103.752 ;
     RECT  53.812 2.418 53.849 103.752 ;
     RECT  53.849 2.418 54.004 103.656 ;
     RECT  54.004 58.704 54.065 70.92 ;
     RECT  54.004 72 54.131 103.656 ;
     RECT  54.004 43.104 54.209 57.048 ;
     RECT  54.131 78.096 54.209 103.56 ;
     RECT  54.065 69.984 54.245 70.92 ;
     RECT  54.065 58.704 54.317 68.904 ;
     RECT  53.453 105.312 54.419 105.72 ;
     RECT  54.419 105.36 54.611 105.72 ;
     RECT  54.611 105.36 54.659 105.672 ;
     RECT  54.209 78.096 54.713 86.856 ;
     RECT  54.131 72 54.749 77.112 ;
     RECT  54.713 78.096 54.785 81.72 ;
     RECT  54.004 38.256 54.997 38.424 ;
     RECT  54.317 58.704 55.037 62.568 ;
     RECT  54.317 63.792 55.069 68.904 ;
     RECT  54.245 69.984 55.069 70.344 ;
     RECT  54.209 44.4 55.139 57.048 ;
     RECT  55.069 63.792 55.145 70.344 ;
     RECT  54.004 37.056 55.196 37.128 ;
     RECT  55.196 36.432 55.213 37.128 ;
     RECT  54.004 41.424 55.237 41.448 ;
     RECT  54.209 43.104 55.237 43.368 ;
     RECT  55.139 44.4 55.253 49.272 ;
     RECT  54.659 105.504 55.283 105.672 ;
     RECT  54.004 33.936 55.285 34.104 ;
     RECT  55.213 35.424 55.285 37.128 ;
     RECT  55.139 51.696 55.285 57.048 ;
     RECT  54.749 74.928 55.289 77.112 ;
     RECT  55.289 75.936 55.321 77.112 ;
     RECT  55.237 41.28 55.325 41.448 ;
     RECT  55.237 42.768 55.357 43.368 ;
     RECT  54.749 72 55.393 73.848 ;
     RECT  54.713 82.752 55.429 86.856 ;
     RECT  54.209 87.84 55.429 103.56 ;
     RECT  55.037 62.112 55.537 62.568 ;
     RECT  55.145 63.792 55.537 69.336 ;
     RECT  55.285 33.936 55.573 37.128 ;
     RECT  54.997 38.256 55.573 38.712 ;
     RECT  55.573 33.936 55.601 38.712 ;
     RECT  54.004 39.888 55.601 40.104 ;
     RECT  55.325 41.424 55.724 41.448 ;
     RECT  55.357 42.528 55.724 43.368 ;
     RECT  54.785 79.152 55.753 81.72 ;
     RECT  55.285 51.696 55.969 57.384 ;
     RECT  55.724 41.424 56.077 43.368 ;
     RECT  55.253 44.4 56.077 49.08 ;
     RECT  55.393 71.376 56.077 73.848 ;
     RECT  55.289 74.928 56.077 74.952 ;
     RECT  55.283 105.648 56.101 105.672 ;
     RECT  56.077 71.376 56.113 74.952 ;
     RECT  55.537 62.112 56.257 69.336 ;
     RECT  56.257 62.112 56.293 70.104 ;
     RECT  56.113 71.088 56.293 74.952 ;
     RECT  56.101 105.648 56.293 105.72 ;
     RECT  54.004 23.568 56.408 23.592 ;
     RECT  55.189 28.224 56.408 28.248 ;
     RECT  54.004 29.28 56.408 29.304 ;
     RECT  55.601 33.936 56.408 40.104 ;
     RECT  56.077 41.424 56.408 49.08 ;
     RECT  55.139 50.304 56.408 50.328 ;
     RECT  55.969 51.696 56.408 57.432 ;
     RECT  55.037 58.704 56.408 61.128 ;
     RECT  56.293 62.112 56.408 74.952 ;
     RECT  55.321 75.936 56.408 77.592 ;
     RECT  55.753 79.008 56.408 81.72 ;
     RECT  55.429 82.752 56.408 103.56 ;
     RECT  56.408 2.148 56.512 103.56 ;
     RECT  56.512 2.418 56.704 103.56 ;
     RECT  56.704 80.112 56.773 103.56 ;
     RECT  56.704 75.984 56.837 76.296 ;
     RECT  56.704 38.784 56.873 41.496 ;
     RECT  56.704 36.528 56.981 37.656 ;
     RECT  56.704 50.112 56.981 75 ;
     RECT  56.704 42.576 57.059 49.032 ;
     RECT  56.981 50.112 57.125 62.184 ;
     RECT  56.981 63.216 57.161 75 ;
     RECT  57.161 63.216 57.203 70.92 ;
     RECT  56.873 38.784 57.299 41.448 ;
     RECT  57.059 42.576 57.299 48.984 ;
     RECT  57.125 58.992 57.299 62.184 ;
     RECT  57.203 66.816 57.305 70.92 ;
     RECT  57.299 39.888 57.34 41.112 ;
     RECT  56.981 36.816 57.341 37.656 ;
     RECT  56.773 80.112 57.349 104.28 ;
     RECT  57.305 66.816 57.377 68.904 ;
     RECT  57.299 38.784 57.413 38.808 ;
     RECT  57.305 70.08 57.449 70.92 ;
     RECT  57.377 66.816 57.521 67.368 ;
     RECT  57.299 42.72 57.557 48.984 ;
     RECT  57.299 58.992 57.557 61.704 ;
     RECT  57.341 36.816 57.629 36.84 ;
     RECT  57.125 50.112 57.629 58.008 ;
     RECT  56.837 76.032 57.697 76.296 ;
     RECT  56.293 105.504 57.769 105.72 ;
     RECT  57.349 80.112 57.788 104.328 ;
     RECT  57.769 105.408 57.788 105.72 ;
     RECT  56.704 33.936 57.913 34.728 ;
     RECT  57.913 33.888 58.025 34.728 ;
     RECT  57.557 58.992 58.061 61.464 ;
     RECT  57.629 50.592 58.129 58.008 ;
     RECT  58.061 58.992 58.129 59.016 ;
     RECT  56.704 77.664 58.129 79.128 ;
     RECT  57.788 80.112 58.129 105.72 ;
     RECT  57.697 76.032 58.133 76.392 ;
     RECT  58.025 34.032 58.172 34.728 ;
     RECT  58.129 77.664 58.205 105.72 ;
     RECT  57.203 63.216 58.309 65.304 ;
     RECT  57.449 70.08 58.309 70.632 ;
     RECT  57.34 39.888 58.489 41.064 ;
     RECT  58.489 39.84 58.597 41.064 ;
     RECT  58.489 37.152 58.633 37.176 ;
     RECT  58.205 77.664 58.645 103.272 ;
     RECT  58.309 62.688 58.705 65.304 ;
     RECT  58.633 37.104 58.744 37.176 ;
     RECT  57.377 68.4 58.813 68.904 ;
     RECT  56.704 28.224 58.837 28.248 ;
     RECT  56.704 29.28 58.837 29.304 ;
     RECT  58.309 69.984 58.849 70.632 ;
     RECT  57.161 71.952 58.849 75 ;
     RECT  58.129 50.592 58.957 59.016 ;
     RECT  58.744 37.056 58.981 37.176 ;
     RECT  58.129 38.16 58.981 38.184 ;
     RECT  58.981 37.056 59.026 38.184 ;
     RECT  56.704 23.568 59.108 23.592 ;
     RECT  58.837 28.224 59.108 29.304 ;
     RECT  58.172 34.032 59.108 34.776 ;
     RECT  58.175 35.808 59.108 35.832 ;
     RECT  59.026 37.056 59.108 38.232 ;
     RECT  58.597 39.84 59.108 41.4 ;
     RECT  57.557 42.72 59.108 45.816 ;
     RECT  57.557 46.848 59.108 48.984 ;
     RECT  58.957 50.352 59.108 59.016 ;
     RECT  58.061 60 59.108 61.464 ;
     RECT  58.705 62.688 59.108 65.544 ;
     RECT  57.521 66.816 59.108 67.32 ;
     RECT  58.813 68.4 59.108 68.952 ;
     RECT  58.849 69.984 59.108 75 ;
     RECT  58.133 76.272 59.108 76.392 ;
     RECT  58.645 77.376 59.108 103.272 ;
     RECT  59.108 2.148 59.212 103.272 ;
     RECT  59.212 2.418 59.3 103.272 ;
     RECT  58.205 104.256 59.3 105.72 ;
     RECT  59.3 2.418 59.404 105.72 ;
     RECT  59.404 36.912 59.465 39.624 ;
     RECT  59.404 40.896 59.465 42.6 ;
     RECT  59.404 71.472 59.501 74.664 ;
     RECT  59.404 102.48 59.501 103.272 ;
     RECT  59.404 56.064 59.537 65.496 ;
     RECT  59.404 44.688 59.573 54.936 ;
     RECT  59.573 46.848 59.603 54.936 ;
     RECT  59.404 67.152 59.651 70.392 ;
     RECT  59.404 75.984 59.825 95.976 ;
     RECT  59.404 34.416 59.861 34.68 ;
     RECT  59.404 104.304 59.861 105.72 ;
     RECT  59.404 99.12 59.904 101.4 ;
     RECT  59.904 99.12 59.939 99.72 ;
     RECT  59.603 46.848 60.005 50.616 ;
     RECT  59.861 34.416 60.077 34.44 ;
     RECT  59.465 40.896 60.172 40.92 ;
     RECT  59.651 67.296 60.185 70.392 ;
     RECT  59.501 71.472 60.221 74.424 ;
     RECT  59.537 57.36 60.257 65.496 ;
     RECT  60.005 48.672 60.293 50.616 ;
     RECT  59.465 37.104 60.365 37.128 ;
     RECT  59.465 41.904 60.397 42.6 ;
     RECT  59.404 97.632 60.397 98.088 ;
     RECT  59.904 101.04 60.469 101.4 ;
     RECT  59.501 102.48 60.469 103.224 ;
     RECT  60.257 57.36 60.473 62.232 ;
     RECT  59.825 76.272 60.505 95.976 ;
     RECT  60.397 97.584 60.505 98.088 ;
     RECT  59.861 104.832 60.509 105.72 ;
     RECT  59.465 38.16 60.62 39.624 ;
     RECT  59.603 51.696 60.668 54.936 ;
     RECT  60.668 51.264 60.685 54.936 ;
     RECT  59.537 56.064 60.685 56.328 ;
     RECT  60.473 57.36 60.685 61.176 ;
     RECT  60.505 76.272 60.725 98.088 ;
     RECT  60.685 51.264 60.755 61.176 ;
     RECT  60.661 35.472 60.761 35.496 ;
     RECT  60.397 41.904 60.805 43.368 ;
     RECT  60.725 81.072 60.865 98.088 ;
     RECT  60.62 37.824 60.901 39.624 ;
     RECT  60.509 104.88 60.908 105.72 ;
     RECT  60.469 101.04 60.997 103.224 ;
     RECT  60.805 43.344 61.009 43.368 ;
     RECT  59.573 44.688 61.009 45.816 ;
     RECT  60.865 81.072 61.045 98.184 ;
     RECT  59.939 99.168 61.045 99.72 ;
     RECT  60.185 67.296 61.117 70.344 ;
     RECT  60.473 62.16 61.333 62.232 ;
     RECT  60.257 63.216 61.333 65.496 ;
     RECT  61.009 43.344 61.477 45.816 ;
     RECT  60.005 46.848 61.477 47.688 ;
     RECT  60.293 48.672 61.477 50.136 ;
     RECT  61.117 66.864 61.477 70.344 ;
     RECT  60.221 71.472 61.477 74.232 ;
     RECT  60.725 76.272 61.477 80.088 ;
     RECT  59.404 23.568 61.525 23.592 ;
     RECT  61.045 81.072 61.525 99.72 ;
     RECT  60.997 100.8 61.525 103.224 ;
     RECT  61.477 75.408 61.549 80.088 ;
     RECT  61.525 23.568 61.808 23.928 ;
     RECT  59.404 28.224 61.808 29.304 ;
     RECT  60.901 37.824 61.808 40.44 ;
     RECT  60.805 41.904 61.808 41.928 ;
     RECT  61.477 43.344 61.808 50.136 ;
     RECT  60.755 51.696 61.808 61.176 ;
     RECT  61.333 62.16 61.808 65.496 ;
     RECT  61.477 66.864 61.808 74.232 ;
     RECT  61.549 75.216 61.808 80.088 ;
     RECT  61.525 81.072 61.808 103.512 ;
     RECT  61.808 2.148 61.912 103.512 ;
     RECT  61.912 2.418 62.053 103.512 ;
     RECT  62.053 2.418 62.104 103.656 ;
     RECT  62.104 40.416 62.165 42.648 ;
     RECT  62.104 66.624 62.165 79.848 ;
     RECT  62.165 40.848 62.243 42.648 ;
     RECT  62.104 80.832 62.243 103.656 ;
     RECT  62.165 66.624 62.273 79.8 ;
     RECT  62.243 40.848 62.381 41.4 ;
     RECT  62.243 42.624 62.476 42.648 ;
     RECT  62.243 97.584 62.627 103.656 ;
     RECT  62.627 97.584 62.633 103.56 ;
     RECT  62.273 67.824 62.675 79.8 ;
     RECT  62.104 28.128 62.741 29.304 ;
     RECT  62.243 80.832 62.813 96.6 ;
     RECT  62.633 97.824 62.849 103.56 ;
     RECT  62.104 45.792 63.205 50.232 ;
     RECT  60.908 104.88 63.313 105.768 ;
     RECT  63.205 45.792 63.353 50.664 ;
     RECT  62.813 81.072 63.389 95.976 ;
     RECT  62.104 57.312 63.425 65.448 ;
     RECT  62.104 51.696 63.565 56.328 ;
     RECT  63.425 57.312 63.565 61.032 ;
     RECT  62.104 44.448 63.601 44.712 ;
     RECT  62.273 66.624 63.601 66.648 ;
     RECT  62.675 67.824 63.601 68.712 ;
     RECT  63.425 62.016 63.637 65.448 ;
     RECT  63.601 66.624 63.637 68.712 ;
     RECT  63.637 62.016 63.817 68.712 ;
     RECT  62.104 39.312 63.853 39.336 ;
     RECT  63.853 39.312 63.884 39.528 ;
     RECT  63.817 62.016 63.889 68.76 ;
     RECT  63.389 81.072 63.889 81.768 ;
     RECT  63.601 44.4 63.925 44.712 ;
     RECT  63.353 45.792 63.925 49.56 ;
     RECT  62.849 97.872 64.141 103.56 ;
     RECT  62.381 41.376 64.165 41.4 ;
     RECT  63.313 104.832 64.289 105.768 ;
     RECT  63.353 50.64 64.357 50.664 ;
     RECT  63.565 51.696 64.357 61.032 ;
     RECT  62.104 23.568 64.508 23.928 ;
     RECT  62.741 28.224 64.508 29.304 ;
     RECT  63.884 39.072 64.508 39.528 ;
     RECT  64.165 40.56 64.508 41.4 ;
     RECT  63.781 43.296 64.508 43.32 ;
     RECT  63.925 44.4 64.508 49.56 ;
     RECT  64.357 50.64 64.508 61.032 ;
     RECT  63.889 62.016 64.508 68.952 ;
     RECT  62.675 69.984 64.508 79.8 ;
     RECT  63.889 80.88 64.508 81.768 ;
     RECT  63.389 82.752 64.508 95.976 ;
     RECT  64.141 97.824 64.508 103.56 ;
     RECT  64.508 2.148 64.612 103.56 ;
     RECT  64.612 2.418 64.789 103.56 ;
     RECT  64.789 2.418 64.804 103.656 ;
     RECT  64.804 44.4 64.901 49.56 ;
     RECT  64.289 104.88 64.979 105.768 ;
     RECT  64.804 50.544 65.009 61.464 ;
     RECT  64.804 66.576 65.027 68.952 ;
     RECT  64.901 44.688 65.081 49.56 ;
     RECT  64.804 70.08 65.081 74.328 ;
     RECT  64.804 41.232 65.153 41.256 ;
     RECT  65.009 51.216 65.369 61.464 ;
     RECT  65.369 51.216 65.405 61.08 ;
     RECT  64.804 42.768 65.441 43.32 ;
     RECT  65.405 51.216 65.441 60.984 ;
     RECT  65.441 51.216 65.477 60.888 ;
     RECT  64.804 78.48 65.513 103.656 ;
     RECT  65.081 70.08 65.585 73.944 ;
     RECT  64.804 75.648 65.621 76.824 ;
     RECT  65.513 79.488 65.797 103.656 ;
     RECT  65.477 51.216 65.801 60.456 ;
     RECT  65.797 79.488 65.909 103.752 ;
     RECT  65.909 88.896 65.981 103.752 ;
     RECT  65.081 45.792 66.037 49.56 ;
     RECT  65.513 78.48 66.053 78.504 ;
     RECT  65.585 71.088 66.085 73.944 ;
     RECT  65.441 43.056 66.089 43.32 ;
     RECT  65.081 44.688 66.121 44.712 ;
     RECT  66.037 45.792 66.121 50.184 ;
     RECT  65.027 66.576 66.181 68.856 ;
     RECT  65.585 70.08 66.181 70.104 ;
     RECT  65.981 97.344 66.409 103.752 ;
     RECT  66.121 44.688 66.445 50.184 ;
     RECT  66.085 71.088 66.445 73.992 ;
     RECT  66.445 44.448 66.481 50.184 ;
     RECT  65.801 51.216 66.481 59.016 ;
     RECT  64.979 104.976 66.515 105.768 ;
     RECT  65.621 76.272 66.661 76.824 ;
     RECT  64.804 62.448 66.697 65.496 ;
     RECT  65.801 60.096 66.733 60.456 ;
     RECT  66.697 61.632 66.733 65.496 ;
     RECT  64.804 39.504 66.764 39.528 ;
     RECT  65.981 88.896 66.985 95.976 ;
     RECT  66.409 97.344 66.985 103.992 ;
     RECT  66.481 44.448 67.093 59.016 ;
     RECT  65.909 79.488 67.129 87.816 ;
     RECT  66.985 88.896 67.129 103.992 ;
     RECT  64.804 23.568 67.208 23.928 ;
     RECT  64.804 28.224 67.208 29.304 ;
     RECT  66.805 37.584 67.208 37.608 ;
     RECT  66.764 39.504 67.208 39.768 ;
     RECT  66.089 43.296 67.208 43.32 ;
     RECT  67.093 44.352 67.208 59.016 ;
     RECT  66.733 60.096 67.208 65.496 ;
     RECT  66.181 66.576 67.208 70.104 ;
     RECT  66.445 71.088 67.208 74.664 ;
     RECT  66.661 76.224 67.208 76.824 ;
     RECT  67.129 79.488 67.208 103.992 ;
     RECT  67.208 2.148 67.312 103.992 ;
     RECT  67.312 2.418 67.504 103.992 ;
     RECT  67.504 77.952 67.529 94.968 ;
     RECT  67.529 77.952 67.619 86.856 ;
     RECT  67.504 41.184 67.637 41.208 ;
     RECT  67.504 66.288 67.745 70.728 ;
     RECT  67.504 95.952 67.861 103.992 ;
     RECT  66.515 105.456 67.861 105.768 ;
     RECT  67.619 81.024 67.889 86.856 ;
     RECT  67.504 60.096 68.465 64.968 ;
     RECT  67.504 71.856 68.465 76.872 ;
     RECT  67.504 42.192 68.501 54.408 ;
     RECT  68.465 71.856 68.627 75.288 ;
     RECT  67.861 95.952 68.675 105.768 ;
     RECT  68.501 43.728 68.713 54.408 ;
     RECT  67.504 55.488 68.713 59.016 ;
     RECT  68.465 60.096 68.713 60.12 ;
     RECT  67.529 88.08 68.773 94.968 ;
     RECT  68.465 61.728 68.785 64.968 ;
     RECT  67.619 77.952 68.893 79.608 ;
     RECT  68.773 87.84 68.929 94.968 ;
     RECT  68.675 95.952 68.929 105.72 ;
     RECT  68.465 76.272 68.965 76.872 ;
     RECT  68.893 77.904 68.965 79.608 ;
     RECT  67.889 81.072 68.965 86.856 ;
     RECT  68.627 71.856 69.145 75.192 ;
     RECT  67.745 66.288 69.289 70.104 ;
     RECT  69.145 71.136 69.289 75.192 ;
     RECT  68.785 61.728 69.325 65.256 ;
     RECT  69.289 66.288 69.325 75.192 ;
     RECT  68.965 80.832 69.397 86.856 ;
     RECT  69.397 80.784 69.637 86.856 ;
     RECT  68.929 87.84 69.637 105.72 ;
     RECT  69.325 61.728 69.685 75.192 ;
     RECT  68.501 42.192 69.757 42.552 ;
     RECT  68.713 43.728 69.757 60.12 ;
     RECT  69.637 80.784 69.833 105.72 ;
     RECT  69.833 104.976 69.905 105.72 ;
     RECT  67.504 23.568 69.908 23.928 ;
     RECT  67.504 28.224 69.908 29.304 ;
     RECT  67.504 37.584 69.908 37.608 ;
     RECT  69.757 42.192 69.908 60.12 ;
     RECT  69.685 61.728 69.908 75.24 ;
     RECT  68.965 76.272 69.908 79.608 ;
     RECT  69.833 80.784 69.908 103.992 ;
     RECT  69.908 2.148 70.012 103.992 ;
     RECT  70.012 2.418 70.204 103.992 ;
     RECT  70.204 41.664 70.381 45.816 ;
     RECT  70.204 28.128 70.733 29.304 ;
     RECT  70.204 37.44 70.733 37.608 ;
     RECT  69.905 105.168 70.787 105.72 ;
     RECT  70.787 105.264 70.835 105.72 ;
     RECT  70.204 71.184 70.877 75.24 ;
     RECT  70.204 64.416 70.931 66.6 ;
     RECT  70.204 46.848 70.949 60.12 ;
     RECT  70.381 43.536 71.221 45.816 ;
     RECT  70.949 46.848 71.221 53.112 ;
     RECT  71.221 43.536 71.308 53.112 ;
     RECT  70.381 41.664 71.377 42.552 ;
     RECT  71.308 43.536 71.377 45.816 ;
     RECT  70.204 76.272 71.453 86.856 ;
     RECT  70.204 87.84 71.489 103.992 ;
     RECT  70.835 105.312 71.525 105.72 ;
     RECT  70.204 67.872 71.737 70.152 ;
     RECT  70.877 71.184 71.737 74.952 ;
     RECT  71.377 41.664 71.809 45.816 ;
     RECT  71.737 67.872 71.845 74.952 ;
     RECT  70.949 54.096 71.881 60.12 ;
     RECT  70.204 61.728 71.881 62.04 ;
     RECT  71.453 82.752 71.917 86.856 ;
     RECT  71.489 87.84 71.917 103.512 ;
     RECT  71.845 67.68 72.025 74.952 ;
     RECT  71.453 76.272 72.025 81.72 ;
     RECT  70.733 37.44 72.133 37.464 ;
     RECT  70.931 64.656 72.169 66.6 ;
     RECT  72.025 67.68 72.169 81.72 ;
     RECT  72.133 37.44 72.349 37.608 ;
     RECT  72.085 39.6 72.469 39.624 ;
     RECT  71.809 40.944 72.469 45.816 ;
     RECT  70.204 23.568 72.608 23.928 ;
     RECT  70.204 25.248 72.608 25.752 ;
     RECT  70.733 28.224 72.608 29.304 ;
     RECT  72.349 37.44 72.608 37.944 ;
     RECT  72.469 39.6 72.608 45.816 ;
     RECT  71.308 46.848 72.608 53.112 ;
     RECT  71.881 54.096 72.608 62.04 ;
     RECT  72.169 64.656 72.608 81.72 ;
     RECT  71.917 82.752 72.608 103.512 ;
     RECT  72.608 2.148 72.709 103.512 ;
     RECT  72.709 2.148 72.712 103.992 ;
     RECT  72.712 2.418 72.805 103.992 ;
     RECT  71.525 105.312 72.805 105.672 ;
     RECT  72.805 2.418 72.904 105.672 ;
     RECT  72.904 64.32 72.997 105.672 ;
     RECT  72.904 45.696 73.073 49.08 ;
     RECT  72.904 54.096 73.073 60.408 ;
     RECT  72.997 64.32 73.091 105.72 ;
     RECT  73.073 46.848 73.523 49.08 ;
     RECT  72.904 39.6 73.649 44.712 ;
     RECT  73.091 99.744 73.67 105.72 ;
     RECT  72.904 37.44 74.005 38.136 ;
     RECT  73.649 39.6 74.005 39.624 ;
     RECT  73.091 64.32 74.009 98.616 ;
     RECT  73.073 54.144 74.117 60.408 ;
     RECT  72.904 51.696 74.125 53.112 ;
     RECT  74.125 52.896 74.225 53.112 ;
     RECT  74.117 54.144 74.261 57.384 ;
     RECT  74.293 21.984 74.389 22.008 ;
     RECT  72.904 50.64 74.401 50.664 ;
     RECT  74.125 51.696 74.401 51.72 ;
     RECT  74.009 64.608 74.581 98.616 ;
     RECT  73.649 40.944 74.617 44.712 ;
     RECT  73.073 45.696 74.617 45.816 ;
     RECT  74.617 40.944 74.653 45.816 ;
     RECT  73.523 46.848 74.653 48.696 ;
     RECT  74.653 40.944 74.677 48.696 ;
     RECT  74.117 58.656 74.761 60.408 ;
     RECT  72.904 61.44 74.761 61.992 ;
     RECT  73.67 99.744 74.963 105.672 ;
     RECT  74.761 58.656 75.049 61.992 ;
     RECT  74.963 99.744 75.059 105.576 ;
     RECT  75.049 58.656 75.085 62.184 ;
     RECT  74.401 50.64 75.229 51.72 ;
     RECT  74.225 52.992 75.229 53.112 ;
     RECT  75.085 58.656 75.301 62.28 ;
     RECT  74.581 64.608 75.301 98.76 ;
     RECT  75.059 99.744 75.301 104.616 ;
     RECT  74.389 21.984 75.308 22.488 ;
     RECT  72.904 23.568 75.308 25.752 ;
     RECT  72.904 28.224 75.308 29.304 ;
     RECT  74.005 37.44 75.308 39.624 ;
     RECT  74.677 40.944 75.308 48.984 ;
     RECT  75.229 50.64 75.308 53.112 ;
     RECT  74.261 54.24 75.308 57.384 ;
     RECT  75.301 58.656 75.308 63 ;
     RECT  75.301 64.608 75.308 104.616 ;
     RECT  75.308 2.148 75.412 104.616 ;
     RECT  75.412 2.418 75.604 104.616 ;
     RECT  75.604 68.16 75.731 70.2 ;
     RECT  75.604 50.736 75.809 53.064 ;
     RECT  75.604 71.376 75.845 101.16 ;
     RECT  75.604 103.968 75.875 104.616 ;
     RECT  75.845 71.376 75.881 98.664 ;
     RECT  75.845 99.744 75.881 101.16 ;
     RECT  75.809 50.736 75.917 52.248 ;
     RECT  75.881 99.744 75.953 101.112 ;
     RECT  75.604 37.44 75.989 39.768 ;
     RECT  75.604 61.44 75.989 67.128 ;
     RECT  75.989 37.44 76.097 38.04 ;
     RECT  75.875 103.968 76.313 104.568 ;
     RECT  75.989 61.44 76.385 65.496 ;
     RECT  75.604 102.624 76.403 102.744 ;
     RECT  75.953 99.744 76.444 100.824 ;
     RECT  76.313 104.544 76.493 104.568 ;
     RECT  75.989 39.024 76.597 39.768 ;
     RECT  75.604 41.088 76.597 44.712 ;
     RECT  75.604 54.096 76.597 60.312 ;
     RECT  76.597 54.096 76.633 60.456 ;
     RECT  76.097 37.632 76.637 38.04 ;
     RECT  76.444 99.744 76.637 100.344 ;
     RECT  76.637 99.744 76.717 99.768 ;
     RECT  76.637 37.632 76.745 37.992 ;
     RECT  76.385 61.968 76.781 65.496 ;
     RECT  75.917 50.736 76.813 52.2 ;
     RECT  76.633 53.904 76.813 60.456 ;
     RECT  76.813 53.904 76.925 60.744 ;
     RECT  75.604 45.696 76.931 49.608 ;
     RECT  76.781 63.6 76.993 65.496 ;
     RECT  75.989 66.576 76.993 67.128 ;
     RECT  76.597 39.024 77.033 44.712 ;
     RECT  76.993 63.6 77.209 67.128 ;
     RECT  75.731 68.16 77.209 70.104 ;
     RECT  75.881 71.376 77.209 98.472 ;
     RECT  76.813 50.64 77.353 52.2 ;
     RECT  76.925 60.096 77.425 60.744 ;
     RECT  77.209 71.136 77.461 98.472 ;
     RECT  77.033 41.04 77.641 44.712 ;
     RECT  76.931 45.696 77.641 47.688 ;
     RECT  76.745 37.92 77.653 37.992 ;
     RECT  77.033 39.024 77.653 39.624 ;
     RECT  76.931 48.672 77.677 49.608 ;
     RECT  77.353 50.64 77.677 52.248 ;
     RECT  77.209 101.472 77.701 101.496 ;
     RECT  77.653 37.92 77.756 39.624 ;
     RECT  77.425 60.096 77.821 60.888 ;
     RECT  76.781 61.968 77.821 62.424 ;
     RECT  77.209 63.6 77.845 70.104 ;
     RECT  77.461 71.136 77.845 99.048 ;
     RECT  76.925 53.904 77.857 59.064 ;
     RECT  77.845 63.6 77.965 99.048 ;
     RECT  75.604 21.984 78.008 22.488 ;
     RECT  75.604 23.568 78.008 25.752 ;
     RECT  75.604 28.224 78.008 29.304 ;
     RECT  77.756 37.104 78.008 39.624 ;
     RECT  77.641 41.04 78.008 47.688 ;
     RECT  77.677 48.672 78.008 52.248 ;
     RECT  77.857 53.808 78.008 59.064 ;
     RECT  77.821 60.096 78.008 62.424 ;
     RECT  77.965 63.6 78.008 99.24 ;
     RECT  77.701 100.848 78.008 101.496 ;
     RECT  76.705 102.912 78.008 102.936 ;
     RECT  78.008 2.148 78.112 103.152 ;
     RECT  78.112 2.418 78.2 103.152 ;
     RECT  78.2 2.418 78.304 103.422 ;
     RECT  78.304 28.128 78.689 29.304 ;
     RECT  78.304 55.44 78.707 99.72 ;
     RECT  78.707 55.44 78.725 99.24 ;
     RECT  78.725 55.44 78.761 99.192 ;
     RECT  78.761 55.44 78.869 70.632 ;
     RECT  78.304 37.824 79.091 52.248 ;
     RECT  79.091 48.672 79.121 52.248 ;
     RECT  78.304 36.432 79.265 36.456 ;
     RECT  78.304 53.808 79.297 54.456 ;
     RECT  78.869 55.44 79.297 57.432 ;
     RECT  79.297 53.808 79.405 57.432 ;
     RECT  79.091 37.824 79.553 47.688 ;
     RECT  78.761 72 79.829 99.192 ;
     RECT  79.405 53.712 79.837 57.432 ;
     RECT  78.869 58.656 79.909 70.632 ;
     RECT  79.829 71.808 79.909 99.192 ;
     RECT  79.837 53.28 80.269 57.432 ;
     RECT  79.909 58.656 80.269 99.192 ;
     RECT  80.269 53.28 80.449 99.192 ;
     RECT  78.304 100.848 80.449 100.872 ;
     RECT  79.553 37.872 80.581 47.688 ;
     RECT  78.304 21.984 80.708 22.488 ;
     RECT  78.304 23.568 80.708 25.752 ;
     RECT  78.689 28.224 80.708 29.304 ;
     RECT  80.581 37.584 80.708 47.688 ;
     RECT  79.121 48.672 80.708 52.008 ;
     RECT  80.449 53.28 80.708 100.872 ;
     RECT  80.708 2.148 80.812 103.152 ;
     RECT  80.812 2.418 80.9 103.152 ;
     RECT  80.9 2.418 81.004 103.422 ;
     RECT  81.004 48.672 81.299 67.128 ;
     RECT  81.004 36.336 81.353 47.688 ;
     RECT  81.299 48.672 81.497 60.984 ;
     RECT  81.004 68.16 81.533 99.192 ;
     RECT  81.533 71.088 81.677 99.192 ;
     RECT  81.677 71.088 81.713 98.904 ;
     RECT  81.353 36.336 81.749 39.624 ;
     RECT  81.299 61.968 81.749 67.128 ;
     RECT  81.749 36.336 82.001 38.616 ;
     RECT  81.749 61.968 82.001 65.496 ;
     RECT  81.749 66.576 82.033 67.128 ;
     RECT  81.533 68.16 82.033 70.104 ;
     RECT  81.497 48.672 82.067 56.376 ;
     RECT  81.713 71.136 82.067 98.904 ;
     RECT  82.067 71.136 82.073 98.712 ;
     RECT  81.353 40.656 82.105 47.688 ;
     RECT  82.067 48.672 82.105 48.792 ;
     RECT  82.105 40.656 82.145 48.792 ;
     RECT  82.001 61.968 82.217 62.664 ;
     RECT  82.067 50.304 82.253 56.376 ;
     RECT  81.497 57.36 82.681 60.936 ;
     RECT  82.217 61.968 82.681 61.992 ;
     RECT  82.001 36.48 82.817 38.616 ;
     RECT  81.749 39.6 82.817 39.624 ;
     RECT  82.033 66.576 83.041 70.104 ;
     RECT  82.073 71.424 83.041 93.576 ;
     RECT  82.145 43.872 83.185 48.792 ;
     RECT  82.253 50.304 83.185 56.328 ;
     RECT  82.001 63.792 83.213 65.496 ;
     RECT  83.041 66.576 83.213 93.576 ;
     RECT  83.213 63.792 83.269 93.576 ;
     RECT  82.073 94.656 83.269 98.712 ;
     RECT  83.269 63.792 83.365 98.712 ;
     RECT  81.004 100.32 83.365 100.344 ;
     RECT  81.004 21.984 83.408 22.488 ;
     RECT  81.004 23.568 83.408 25.752 ;
     RECT  81.004 28.224 83.408 29.304 ;
     RECT  82.817 36.48 83.408 39.624 ;
     RECT  82.145 40.656 83.408 42.84 ;
     RECT  83.185 43.872 83.408 56.328 ;
     RECT  82.681 57.36 83.408 61.992 ;
     RECT  83.365 63.792 83.408 100.344 ;
     RECT  83.408 2.148 83.512 103.152 ;
     RECT  83.512 2.418 83.6 103.152 ;
     RECT  83.6 2.418 83.704 103.422 ;
     RECT  83.704 52.704 83.801 99.576 ;
     RECT  83.704 36.48 83.881 49.56 ;
     RECT  83.801 52.8 84.161 99.576 ;
     RECT  84.161 52.8 84.341 95.976 ;
     RECT  84.161 96.96 84.629 99.576 ;
     RECT  83.704 50.544 84.697 51.72 ;
     RECT  83.881 36.48 84.737 39.912 ;
     RECT  84.629 98.352 84.845 99.576 ;
     RECT  83.881 41.088 84.877 49.56 ;
     RECT  84.697 50.544 84.877 51.768 ;
     RECT  84.877 41.088 84.881 51.768 ;
     RECT  84.341 52.8 84.925 93.528 ;
     RECT  84.845 98.352 84.953 99.192 ;
     RECT  84.925 66.48 84.995 93.528 ;
     RECT  84.737 36.816 85.093 39.912 ;
     RECT  85.093 36.816 85.097 39.96 ;
     RECT  85.097 37.584 85.165 39.96 ;
     RECT  84.881 41.088 85.165 50.376 ;
     RECT  84.881 51.696 85.477 51.768 ;
     RECT  84.925 52.8 85.477 65.496 ;
     RECT  84.341 94.512 85.489 95.976 ;
     RECT  84.629 96.96 85.489 97.32 ;
     RECT  84.995 74.592 85.597 93.528 ;
     RECT  85.489 94.512 85.597 97.32 ;
     RECT  83.704 21.984 86.108 22.488 ;
     RECT  83.704 23.568 86.108 25.752 ;
     RECT  83.704 28.224 86.108 29.304 ;
     RECT  85.165 37.584 86.108 50.376 ;
     RECT  85.477 51.696 86.108 65.496 ;
     RECT  84.995 66.48 86.108 73.56 ;
     RECT  85.597 74.592 86.108 97.32 ;
     RECT  84.953 98.64 86.108 99.192 ;
     RECT  86.108 2.148 86.212 103.152 ;
     RECT  86.212 2.418 86.3 103.152 ;
     RECT  86.3 2.418 86.404 103.422 ;
     RECT  86.404 45.744 86.429 49.08 ;
     RECT  86.404 66.48 86.429 73.56 ;
     RECT  86.429 45.792 86.501 49.08 ;
     RECT  86.404 41.136 86.573 44.712 ;
     RECT  86.404 52.8 86.573 65.496 ;
     RECT  86.573 41.136 86.645 44.424 ;
     RECT  86.404 28.128 86.681 29.304 ;
     RECT  86.501 45.792 86.681 48.984 ;
     RECT  86.404 74.64 86.681 93.384 ;
     RECT  86.404 94.656 86.681 96.072 ;
     RECT  86.404 97.104 86.789 97.32 ;
     RECT  86.645 42 86.825 44.424 ;
     RECT  86.573 52.8 87.005 63.528 ;
     RECT  86.681 45.792 87.041 48.792 ;
     RECT  86.681 74.64 87.041 93.288 ;
     RECT  86.404 51.696 87.433 51.72 ;
     RECT  87.005 52.8 87.433 59.016 ;
     RECT  87.433 51.696 87.509 59.016 ;
     RECT  86.429 66.576 87.509 73.56 ;
     RECT  86.573 64.656 87.577 65.496 ;
     RECT  87.509 66.576 87.577 70.536 ;
     RECT  87.509 71.616 87.721 73.56 ;
     RECT  87.041 74.64 87.721 78.456 ;
     RECT  87.005 61.968 87.757 63.528 ;
     RECT  87.577 64.656 87.757 70.536 ;
     RECT  87.721 71.616 88.261 78.456 ;
     RECT  87.041 79.536 88.261 93.288 ;
     RECT  87.005 60.096 88.309 60.648 ;
     RECT  87.757 61.968 88.309 70.536 ;
     RECT  87.509 51.696 88.585 53.352 ;
     RECT  87.509 54.384 88.585 59.016 ;
     RECT  86.404 21.984 88.808 22.488 ;
     RECT  86.404 23.568 88.808 25.752 ;
     RECT  86.681 28.224 88.808 29.304 ;
     RECT  86.404 39.6 88.808 39.624 ;
     RECT  86.825 42 88.808 42.552 ;
     RECT  86.825 43.872 88.808 44.424 ;
     RECT  87.041 45.792 88.808 47.688 ;
     RECT  87.041 48.72 88.808 48.792 ;
     RECT  88.585 51.696 88.808 59.016 ;
     RECT  88.309 60.096 88.808 70.536 ;
     RECT  88.261 71.616 88.808 93.288 ;
     RECT  86.681 94.656 88.808 95.976 ;
     RECT  86.789 97.104 88.808 97.128 ;
     RECT  88.808 2.148 88.912 103.152 ;
     RECT  88.912 2.418 89 103.152 ;
     RECT  89 2.418 89.104 103.422 ;
     RECT  89.104 52.8 89.596 56.376 ;
     RECT  89.596 52.8 90.029 54.408 ;
     RECT  89.104 57.36 90.173 87.288 ;
     RECT  90.173 71.088 90.281 76.92 ;
     RECT  89.596 55.392 90.469 56.376 ;
     RECT  90.173 57.36 90.469 70.104 ;
     RECT  90.029 53.52 90.533 54.408 ;
     RECT  89.104 88.704 91.189 89.304 ;
     RECT  89.104 21.984 91.508 22.488 ;
     RECT  89.104 23.568 91.508 25.752 ;
     RECT  89.104 28.224 91.508 29.304 ;
     RECT  89.104 39.6 91.508 39.624 ;
     RECT  89.104 42 91.508 42.552 ;
     RECT  89.104 43.872 91.508 44.424 ;
     RECT  89.104 45.792 91.508 47.688 ;
     RECT  89.104 48.72 91.508 48.792 ;
     RECT  89.104 51.696 91.508 51.72 ;
     RECT  90.533 53.568 91.508 54.408 ;
     RECT  90.469 55.392 91.508 70.104 ;
     RECT  90.281 71.088 91.508 76.728 ;
     RECT  90.173 77.904 91.508 87.288 ;
     RECT  91.189 88.368 91.508 89.304 ;
     RECT  89.104 90.288 91.508 93.288 ;
     RECT  89.104 94.656 91.508 95.976 ;
     RECT  89.104 97.104 91.508 97.128 ;
     RECT  91.508 2.148 91.612 103.152 ;
     RECT  91.612 2.418 91.7 103.152 ;
     RECT  91.7 2.418 91.804 103.422 ;
     RECT  91.804 58.944 91.829 59.064 ;
     RECT  91.804 71.424 91.901 87.144 ;
     RECT  91.829 58.944 91.937 59.016 ;
     RECT  91.901 76.272 91.973 87.144 ;
     RECT  91.901 71.424 92.297 74.952 ;
     RECT  92.297 71.424 92.369 73.8 ;
     RECT  91.973 76.272 92.441 81.912 ;
     RECT  92.369 71.424 92.621 73.56 ;
     RECT  92.441 77.904 92.765 81.912 ;
     RECT  91.804 64.08 92.801 70.104 ;
     RECT  92.801 64.656 92.941 70.104 ;
     RECT  92.621 71.424 92.945 73.368 ;
     RECT  92.765 77.904 92.945 79.56 ;
     RECT  92.941 64.656 93.053 70.152 ;
     RECT  93.053 66.576 93.125 70.152 ;
     RECT  92.765 81.12 93.157 81.912 ;
     RECT  91.973 82.992 93.157 87.144 ;
     RECT  91.804 21.984 94.208 22.488 ;
     RECT  91.804 23.568 94.208 25.752 ;
     RECT  91.804 28.224 94.208 29.304 ;
     RECT  91.804 39.6 94.208 39.624 ;
     RECT  91.804 42 94.208 42.552 ;
     RECT  91.804 43.872 94.208 44.424 ;
     RECT  91.804 45.792 94.208 47.688 ;
     RECT  91.804 48.72 94.208 48.792 ;
     RECT  91.804 51.696 94.208 51.72 ;
     RECT  91.804 54.384 94.208 54.408 ;
     RECT  91.804 55.488 94.208 56.328 ;
     RECT  91.804 57.36 94.208 57.432 ;
     RECT  91.937 58.992 94.208 59.016 ;
     RECT  91.804 60.096 94.208 60.648 ;
     RECT  91.804 61.968 94.208 61.992 ;
     RECT  93.053 64.656 94.208 65.496 ;
     RECT  93.125 66.576 94.208 67.128 ;
     RECT  93.125 68.16 94.208 70.152 ;
     RECT  92.945 71.424 94.208 72.264 ;
     RECT  92.945 73.344 94.208 73.368 ;
     RECT  92.297 74.928 94.208 74.952 ;
     RECT  92.441 76.272 94.208 76.536 ;
     RECT  92.945 77.904 94.208 78.456 ;
     RECT  92.945 79.488 94.208 79.56 ;
     RECT  93.157 81.12 94.208 87.144 ;
     RECT  91.804 88.704 94.208 89.304 ;
     RECT  91.804 90.336 94.208 93.288 ;
     RECT  91.804 94.656 94.208 95.976 ;
     RECT  91.804 97.104 94.208 97.128 ;
     RECT  94.208 2.148 94.312 103.152 ;
     RECT  94.312 2.418 94.4 103.152 ;
     RECT  94.4 2.418 94.504 103.422 ;
     RECT  94.504 81.12 94.673 86.856 ;
     RECT  94.504 54.384 94.745 57.432 ;
     RECT  94.504 43.872 94.781 44.472 ;
     RECT  94.504 45.792 94.781 49.176 ;
     RECT  94.504 61.968 94.781 70.104 ;
     RECT  94.504 30.816 94.817 31.848 ;
     RECT  94.504 37.872 94.889 37.944 ;
     RECT  94.781 61.968 94.889 69.336 ;
     RECT  94.504 23.568 94.925 29.688 ;
     RECT  94.781 43.872 94.925 44.424 ;
     RECT  94.889 66.192 94.925 66.6 ;
     RECT  94.889 61.968 94.997 64.728 ;
     RECT  94.504 97.104 94.997 97.128 ;
     RECT  94.504 39.6 95.033 39.624 ;
     RECT  94.504 33.264 95.213 34.776 ;
     RECT  94.504 94.656 95.213 96.072 ;
     RECT  94.504 71.424 95.308 73.512 ;
     RECT  94.504 36.096 95.357 36.552 ;
     RECT  94.745 54.384 95.537 57.384 ;
     RECT  94.997 63.888 95.537 64.728 ;
     RECT  94.817 30.816 95.569 31.512 ;
     RECT  94.925 66.192 95.573 66.456 ;
     RECT  95.213 34.368 95.605 34.776 ;
     RECT  94.504 20.448 95.609 22.488 ;
     RECT  94.781 45.792 95.749 48.936 ;
     RECT  95.609 20.448 95.753 21.144 ;
     RECT  95.308 71.424 95.753 72.264 ;
     RECT  95.569 30.672 95.789 31.512 ;
     RECT  94.504 42 95.821 42.552 ;
     RECT  94.673 81.696 95.821 86.856 ;
     RECT  95.213 33.264 95.825 33.288 ;
     RECT  94.925 23.904 95.845 29.688 ;
     RECT  95.789 30.672 95.845 30.84 ;
     RECT  95.308 73.344 95.861 73.512 ;
     RECT  95.537 64.656 95.929 64.728 ;
     RECT  95.605 34.368 95.933 35.064 ;
     RECT  95.573 66.24 95.965 66.456 ;
     RECT  94.889 67.728 95.965 69.336 ;
     RECT  95.933 34.464 96.037 35.064 ;
     RECT  95.357 36.096 96.037 36.456 ;
     RECT  95.749 45.792 96.037 49.032 ;
     RECT  94.504 51.312 96.037 52.488 ;
     RECT  94.889 37.872 96.109 37.896 ;
     RECT  94.504 77.904 96.253 79.608 ;
     RECT  95.537 54.384 96.325 54.744 ;
     RECT  94.504 76.272 96.325 76.536 ;
     RECT  96.037 51.312 96.572 53.064 ;
     RECT  96.325 54.096 96.572 54.744 ;
     RECT  95.929 64.656 96.572 64.92 ;
     RECT  96.572 51.312 96.577 54.744 ;
     RECT  95.537 57.36 96.613 57.384 ;
     RECT  96.572 64.032 96.613 64.92 ;
     RECT  95.965 66.24 96.613 69.336 ;
     RECT  94.925 43.872 96.793 44.184 ;
     RECT  96.037 45.792 96.793 49.608 ;
     RECT  95.821 81.6 96.793 86.856 ;
     RECT  94.504 88.704 96.793 93.384 ;
     RECT  95.753 21.12 96.829 21.144 ;
     RECT  95.609 22.464 96.829 22.488 ;
     RECT  96.613 64.032 96.829 69.336 ;
     RECT  96.829 21.12 96.908 22.488 ;
     RECT  95.845 23.904 96.908 30.84 ;
     RECT  95.893 32.304 96.908 32.328 ;
     RECT  96.037 34.464 96.908 36.456 ;
     RECT  96.109 37.632 96.908 37.896 ;
     RECT  95.821 42 96.908 42.792 ;
     RECT  96.793 43.872 96.908 49.608 ;
     RECT  96.577 51.312 96.908 55.272 ;
     RECT  95.537 56.304 96.908 56.376 ;
     RECT  96.613 57.36 96.908 57.576 ;
     RECT  94.504 58.992 96.908 59.016 ;
     RECT  94.504 60.096 96.908 60.648 ;
     RECT  94.997 61.968 96.908 62.808 ;
     RECT  96.829 63.792 96.908 69.336 ;
     RECT  96.001 70.368 96.908 70.392 ;
     RECT  95.753 71.904 96.908 72.264 ;
     RECT  95.861 73.344 96.908 73.368 ;
     RECT  94.504 74.928 96.908 74.952 ;
     RECT  96.325 76.272 96.908 76.92 ;
     RECT  96.253 77.904 96.908 80.136 ;
     RECT  96.793 81.6 96.908 93.384 ;
     RECT  95.213 94.656 96.908 94.968 ;
     RECT  95.213 96.048 96.908 96.072 ;
     RECT  96.908 2.148 97.012 103.152 ;
     RECT  97.012 2.418 97.1 103.152 ;
     RECT  97.1 2.418 97.204 103.422 ;
     RECT  97.204 20.544 97.229 29.736 ;
     RECT  97.204 77.664 97.265 80.136 ;
     RECT  97.204 57.36 97.301 57.576 ;
     RECT  97.229 20.544 97.331 21.192 ;
     RECT  97.301 57.408 97.331 57.576 ;
     RECT  97.331 57.552 97.445 57.576 ;
     RECT  97.204 55.728 97.481 56.376 ;
     RECT  97.265 77.664 97.481 78.648 ;
     RECT  97.204 39.456 97.523 39.912 ;
     RECT  97.204 66.72 97.553 73.512 ;
     RECT  97.229 22.512 97.589 29.736 ;
     RECT  97.204 31.872 97.859 37.944 ;
     RECT  97.204 60.096 97.877 60.12 ;
     RECT  97.589 29.424 98.093 29.736 ;
     RECT  97.589 22.512 98.099 27.96 ;
     RECT  98.093 29.424 98.237 29.448 ;
     RECT  97.859 34.176 98.269 37.944 ;
     RECT  97.204 43.776 98.293 48.936 ;
     RECT  97.204 50.4 98.293 54.408 ;
     RECT  98.269 78.912 98.341 79.032 ;
     RECT  97.265 80.112 98.341 80.136 ;
     RECT  98.269 34.176 98.396 38.328 ;
     RECT  97.859 31.872 98.413 33.192 ;
     RECT  98.341 78.912 98.413 80.136 ;
     RECT  97.523 39.648 98.483 39.912 ;
     RECT  98.396 34.176 98.485 38.568 ;
     RECT  97.204 91.968 98.489 93.384 ;
     RECT  97.331 20.544 98.525 20.568 ;
     RECT  97.553 71.472 98.525 73.512 ;
     RECT  98.413 78.912 98.557 80.376 ;
     RECT  97.204 81.696 98.561 87.672 ;
     RECT  98.483 39.888 98.579 39.912 ;
     RECT  97.204 61.344 98.593 65.736 ;
     RECT  97.553 66.72 98.593 70.008 ;
     RECT  97.204 76.608 98.593 76.632 ;
     RECT  98.557 78.912 98.593 80.568 ;
     RECT  98.561 83.04 98.593 87.672 ;
     RECT  97.204 88.704 98.593 90.36 ;
     RECT  97.204 96.048 98.593 96.072 ;
     RECT  98.485 34.176 98.597 38.808 ;
     RECT  97.481 56.352 98.629 56.376 ;
     RECT  97.481 77.664 98.629 77.688 ;
     RECT  98.593 78.672 98.629 80.568 ;
     RECT  98.593 61.344 98.633 70.008 ;
     RECT  98.593 83.04 98.633 90.36 ;
     RECT  98.489 93.264 98.633 93.384 ;
     RECT  98.593 95.952 98.633 96.072 ;
     RECT  98.525 71.664 98.665 73.512 ;
     RECT  97.204 74.928 98.665 74.952 ;
     RECT  98.413 31.728 98.737 33.192 ;
     RECT  97.204 42.768 99.061 42.792 ;
     RECT  98.293 43.776 99.061 54.408 ;
     RECT  98.633 61.344 99.169 61.992 ;
     RECT  98.737 31.68 99.241 33.192 ;
     RECT  98.597 34.176 99.241 38.328 ;
     RECT  98.099 23.904 99.421 27.96 ;
     RECT  98.099 22.512 99.457 22.824 ;
     RECT  99.061 42.768 99.493 54.408 ;
     RECT  98.593 76.512 99.493 76.632 ;
     RECT  98.629 77.664 99.493 80.568 ;
     RECT  99.421 30.672 99.565 30.696 ;
     RECT  99.493 76.512 99.565 80.568 ;
     RECT  98.561 81.696 99.565 81.72 ;
     RECT  99.349 20.112 99.608 20.136 ;
     RECT  99.529 21.408 99.608 21.432 ;
     RECT  99.457 22.464 99.608 22.824 ;
     RECT  99.421 23.904 99.608 28.008 ;
     RECT  99.421 29.04 99.608 29.064 ;
     RECT  99.565 30.624 99.608 30.696 ;
     RECT  99.241 31.68 99.608 38.328 ;
     RECT  99.493 42.768 99.608 54.744 ;
     RECT  98.629 55.824 99.608 56.376 ;
     RECT  97.204 58.992 99.608 59.016 ;
     RECT  99.169 61.104 99.608 61.992 ;
     RECT  98.633 63.072 99.608 70.008 ;
     RECT  98.665 71.664 99.608 74.952 ;
     RECT  99.565 76.512 99.608 81.72 ;
     RECT  98.633 83.04 99.608 83.064 ;
     RECT  98.633 84.096 99.608 90.36 ;
     RECT  98.489 91.968 99.608 91.992 ;
     RECT  98.633 93.264 99.608 93.288 ;
     RECT  97.204 94.944 99.608 94.968 ;
     RECT  98.633 95.952 99.608 95.976 ;
     RECT  99.608 2.148 99.712 103.152 ;
     RECT  99.712 2.418 99.8 103.152 ;
     RECT  99.8 2.418 99.904 103.422 ;
     RECT  99.904 47.424 99.929 53.592 ;
     RECT  99.904 63.792 99.965 65.256 ;
     RECT  99.904 79.008 99.965 79.368 ;
     RECT  99.904 83.568 99.965 84.12 ;
     RECT  99.904 94.944 99.965 94.968 ;
     RECT  99.904 71.568 100.001 72.984 ;
     RECT  99.904 93.264 100.001 93.288 ;
     RECT  100.001 72.816 100.037 72.984 ;
     RECT  99.904 27.888 100.073 29.064 ;
     RECT  99.904 38.16 100.073 38.232 ;
     RECT  99.965 63.84 100.073 65.256 ;
     RECT  99.904 30.048 100.109 35.016 ;
     RECT  100.073 63.84 100.181 64.968 ;
     RECT  99.929 53.568 100.361 53.592 ;
     RECT  100.181 63.84 100.361 64.008 ;
     RECT  99.904 25.104 100.397 26.616 ;
     RECT  100.109 30.048 100.397 34.584 ;
     RECT  99.904 89.712 100.433 90.024 ;
     RECT  100.397 26.592 100.897 26.616 ;
     RECT  100.073 27.888 100.897 28.2 ;
     RECT  99.904 43.152 100.897 44.04 ;
     RECT  100.433 89.712 100.933 89.736 ;
     RECT  100.933 88.944 100.973 89.736 ;
     RECT  99.904 62.448 101.041 62.472 ;
     RECT  100.037 72.96 101.225 72.984 ;
     RECT  100.933 37.104 101.437 37.128 ;
     RECT  100.397 25.104 101.473 25.128 ;
     RECT  100.897 26.592 101.473 28.2 ;
     RECT  100.397 30.048 101.473 33.672 ;
     RECT  100.897 42.48 101.473 44.04 ;
     RECT  100.897 46.704 101.473 46.728 ;
     RECT  99.929 48.24 101.473 52.488 ;
     RECT  101.041 62.256 101.473 62.472 ;
     RECT  100.361 63.984 101.473 64.008 ;
     RECT  99.904 67.584 101.473 69.768 ;
     RECT  99.965 79.344 101.473 79.368 ;
     RECT  99.904 81.648 101.473 81.672 ;
     RECT  99.965 83.568 101.473 83.592 ;
     RECT  101.149 85.872 101.473 85.896 ;
     RECT  101.473 78.192 101.617 78.216 ;
     RECT  101.473 79.344 101.617 79.656 ;
     RECT  101.473 85.872 101.617 86.28 ;
     RECT  101.473 25.104 101.977 28.2 ;
     RECT  101.473 29.424 101.977 35.208 ;
     RECT  101.437 36.624 101.977 37.128 ;
     RECT  100.073 38.16 101.977 38.184 ;
     RECT  101.473 42.48 101.977 44.424 ;
     RECT  101.473 45.936 101.977 53.256 ;
     RECT  101.473 66.672 101.977 70.536 ;
     RECT  100.001 71.568 101.977 71.592 ;
     RECT  101.941 72.912 101.977 72.936 ;
     RECT  99.904 20.592 102.013 23.688 ;
     RECT  101.977 25.104 102.013 38.184 ;
     RECT  101.977 42.48 102.013 53.64 ;
     RECT  101.473 62.256 102.013 64.776 ;
     RECT  101.977 66.096 102.013 70.536 ;
     RECT  101.977 71.568 102.013 72.936 ;
     RECT  101.617 78.192 102.013 79.656 ;
     RECT  101.473 80.88 102.013 84.744 ;
     RECT  101.617 85.872 102.013 86.664 ;
     RECT  102.013 78.192 102.481 87.432 ;
     RECT  100.973 88.944 102.481 88.968 ;
     RECT  102.013 42.192 102.517 54.408 ;
     RECT  99.904 55.44 102.517 56.328 ;
     RECT  102.481 78.192 102.517 88.968 ;
     RECT  102.517 42.192 102.553 56.328 ;
     RECT  102.013 61.584 102.553 72.936 ;
     RECT  102.013 20.016 102.589 38.184 ;
     RECT  102.553 61.488 102.589 73.32 ;
     RECT  102.517 78.192 102.589 89.736 ;
     RECT  102.553 42.192 102.625 56.616 ;
     RECT  102.589 19.92 103.201 38.184 ;
     RECT  102.589 61.392 103.201 73.32 ;
     RECT  103.201 61.392 103.273 73.512 ;
     RECT  103.201 19.92 104.028 38.28 ;
     RECT  102.625 42.192 104.028 56.712 ;
     RECT  103.273 61.392 104.028 73.608 ;
     RECT  102.589 77.52 104.028 89.736 ;
    LAYER M5 ;
     RECT  2.4 2.137 2.52 2.151 ;
     RECT  5.1 2.137 5.22 2.151 ;
     RECT  7.8 2.137 7.92 2.151 ;
     RECT  10.5 2.137 10.62 2.151 ;
     RECT  13.2 2.137 13.32 2.151 ;
     RECT  15.9 2.137 16.02 2.151 ;
     RECT  18.6 2.137 18.72 2.151 ;
     RECT  21.3 2.137 21.42 2.151 ;
     RECT  24 2.137 24.12 2.151 ;
     RECT  26.7 2.137 26.82 2.151 ;
     RECT  29.4 2.137 29.52 2.151 ;
     RECT  32.1 2.137 32.22 2.151 ;
     RECT  34.8 2.137 34.92 2.151 ;
     RECT  37.5 2.137 37.62 2.151 ;
     RECT  40.2 2.137 40.32 2.151 ;
     RECT  42.9 2.137 43.02 2.151 ;
     RECT  45.6 2.137 45.72 2.151 ;
     RECT  48.3 2.137 48.42 2.151 ;
     RECT  51 2.137 51.12 2.151 ;
     RECT  53.7 2.137 53.82 2.151 ;
     RECT  56.4 2.137 56.52 2.151 ;
     RECT  59.1 2.137 59.22 2.151 ;
     RECT  61.8 2.137 61.92 2.151 ;
     RECT  64.5 2.137 64.62 2.151 ;
     RECT  67.2 2.137 67.32 2.151 ;
     RECT  69.9 2.137 70.02 2.151 ;
     RECT  72.6 2.137 72.72 2.151 ;
     RECT  75.3 2.137 75.42 2.151 ;
     RECT  78 2.137 78.12 2.151 ;
     RECT  80.7 2.137 80.82 2.151 ;
     RECT  83.4 2.137 83.52 2.151 ;
     RECT  86.1 2.137 86.22 2.151 ;
     RECT  88.8 2.137 88.92 2.151 ;
     RECT  91.5 2.137 91.62 2.151 ;
     RECT  94.2 2.137 94.32 2.151 ;
     RECT  96.9 2.137 97.02 2.151 ;
     RECT  99.6 2.137 99.72 2.151 ;
     RECT  94.2 2.151 94.512 20.869 ;
     RECT  96.9 2.151 97.212 21.157 ;
     RECT  94.2 20.869 94.968 21.683 ;
     RECT  74.304 21.973 74.328 22.453 ;
     RECT  75.3 2.151 75.612 22.453 ;
     RECT  96.9 21.157 97.32 23.125 ;
     RECT  34.8 2.151 35.112 23.557 ;
     RECT  61.8 2.151 62.112 23.893 ;
     RECT  72.6 2.151 72.912 24.613 ;
     RECT  99.6 2.151 99.912 25.045 ;
     RECT  94.2 21.683 94.512 25.141 ;
     RECT  69.9 2.151 70.212 25.237 ;
     RECT  94.2 25.141 94.632 25.283 ;
     RECT  99.264 25.045 99.912 25.715 ;
     RECT  96.9 23.125 98.088 26.579 ;
     RECT  59.1 2.151 59.412 28.741 ;
     RECT  51 2.151 51.312 29.269 ;
     RECT  96.9 26.579 97.752 29.413 ;
     RECT  95.856 28.453 95.88 30.275 ;
     RECT  103.776 30.757 103.8 30.899 ;
     RECT  96.9 29.413 97.848 33.539 ;
     RECT  94.2 25.283 94.512 33.589 ;
     RECT  53.7 2.151 54.012 33.973 ;
     RECT  48.3 2.151 48.612 34.117 ;
     RECT  55.2 28.213 55.224 34.597 ;
     RECT  58.848 28.741 59.412 34.741 ;
     RECT  94.2 33.589 94.728 34.787 ;
     RECT  53.376 33.973 54.012 35.075 ;
     RECT  96.9 33.539 97.512 35.269 ;
     RECT  55.2 34.597 55.368 35.459 ;
     RECT  61.536 23.893 62.112 35.461 ;
     RECT  58.224 34.741 59.412 35.843 ;
     RECT  96.9 35.269 97.704 35.939 ;
     RECT  47.52 34.117 48.612 36.131 ;
     RECT  55.2 35.459 55.224 36.421 ;
     RECT  83.4 2.151 83.712 36.469 ;
     RECT  55.2 36.421 55.272 37.045 ;
     RECT  56.4 2.151 56.712 37.045 ;
     RECT  58.848 35.843 59.412 37.093 ;
     RECT  60.672 35.461 62.112 37.093 ;
     RECT  78 2.151 78.312 37.093 ;
     RECT  45.6 2.151 45.912 37.573 ;
     RECT  67.2 2.151 67.512 37.573 ;
     RECT  80.7 2.151 81.012 37.573 ;
     RECT  82.464 36.469 83.88 37.619 ;
     RECT  53.7 35.075 54.012 37.621 ;
     RECT  55.2 37.045 56.712 37.621 ;
     RECT  48.3 36.131 48.612 37.909 ;
     RECT  96.9 35.939 97.512 37.909 ;
     RECT  80.592 37.573 81.012 38.149 ;
     RECT  86.1 2.151 86.412 38.149 ;
     RECT  45.6 37.573 46.488 38.243 ;
     RECT  82.848 37.619 83.88 38.435 ;
     RECT  77.808 37.093 78.312 38.533 ;
     RECT  40.2 2.151 40.512 38.677 ;
     RECT  53.04 37.621 54.012 38.677 ;
     RECT  47.904 37.909 48.612 38.725 ;
     RECT  82.848 38.435 83.712 38.819 ;
     RECT  64.5 2.151 64.812 39.061 ;
     RECT  80.4 38.149 81.012 39.107 ;
     RECT  42.9 2.151 43.212 39.301 ;
     RECT  77.664 38.533 78.312 39.347 ;
     RECT  52.416 38.677 54.012 39.395 ;
     RECT  46.944 38.725 48.612 39.493 ;
     RECT  46.944 39.493 49.56 39.539 ;
     RECT  69.9 25.237 71.16 39.589 ;
     RECT  72.6 24.613 73.032 39.589 ;
     RECT  96.9 37.909 98.472 39.683 ;
     RECT  66.816 37.573 67.512 39.779 ;
     RECT  37.5 2.151 37.812 39.829 ;
     RECT  83.4 38.819 83.712 39.877 ;
     RECT  85.488 38.149 86.412 39.923 ;
     RECT  96.9 39.683 97.512 39.923 ;
     RECT  58.848 37.093 62.112 40.451 ;
     RECT  42.9 39.301 43.32 40.595 ;
     RECT  40.2 38.677 41.208 40.693 ;
     RECT  40.2 40.693 41.784 40.739 ;
     RECT  83.4 39.877 83.832 40.835 ;
     RECT  61.536 40.451 62.112 40.837 ;
     RECT  53.04 39.395 54.012 40.885 ;
     RECT  48.192 39.539 49.56 40.931 ;
     RECT  50.64 29.269 51.312 41.075 ;
     RECT  37.5 39.829 38.232 41.123 ;
     RECT  46.944 39.539 47.016 41.171 ;
     RECT  40.2 40.739 40.512 41.365 ;
     RECT  39.312 41.365 40.512 41.891 ;
     RECT  58.848 40.451 60.12 42.227 ;
     RECT  37.5 41.123 37.812 42.613 ;
     RECT  61.536 40.837 62.232 42.613 ;
     RECT  61.536 42.613 62.424 42.709 ;
     RECT  96.9 39.923 97.368 42.803 ;
     RECT  48.192 40.931 48.612 42.995 ;
     RECT  51 41.075 51.312 43.141 ;
     RECT  46.944 41.171 46.968 43.235 ;
     RECT  85.92 39.923 86.412 43.283 ;
     RECT  55.2 37.621 57.288 43.285 ;
     RECT  78 39.347 78.312 43.285 ;
     RECT  83.4 40.835 83.712 43.285 ;
     RECT  60.768 42.709 62.424 43.379 ;
     RECT  42.9 40.595 43.212 43.765 ;
     RECT  58.848 42.227 59.412 43.813 ;
     RECT  74.304 22.453 75.612 43.813 ;
     RECT  74.112 43.813 75.612 44.053 ;
     RECT  40.2 41.891 40.512 44.101 ;
     RECT  41.76 40.739 41.784 44.101 ;
     RECT  48.3 42.995 48.612 44.149 ;
     RECT  50.832 43.141 51.312 44.149 ;
     RECT  52.848 40.885 54.012 44.195 ;
     RECT  67.2 39.779 67.512 44.341 ;
     RECT  80.592 39.107 81.012 44.341 ;
     RECT  46.992 43.285 47.016 44.389 ;
     RECT  48.3 44.149 49.368 44.389 ;
     RECT  50.832 44.149 51.432 44.483 ;
     RECT  58.8 43.813 59.412 44.483 ;
     RECT  61.536 43.379 62.424 44.483 ;
     RECT  37.5 42.613 38.664 44.581 ;
     RECT  42.9 43.765 43.8 44.627 ;
     RECT  78 43.285 78.648 44.677 ;
     RECT  37.5 44.581 38.76 44.723 ;
     RECT  40.2 44.101 41.784 44.771 ;
     RECT  40.2 44.771 41.4 44.867 ;
     RECT  83.4 43.285 84.36 44.867 ;
     RECT  42.9 44.627 43.212 44.869 ;
     RECT  37.5 44.723 38.664 44.915 ;
     RECT  78 44.677 78.696 44.963 ;
     RECT  45.6 38.243 45.912 44.965 ;
     RECT  63.936 39.061 64.812 44.965 ;
     RECT  86.1 43.283 86.412 44.965 ;
     RECT  63.936 44.965 65.016 45.011 ;
     RECT  55.2 43.285 57.48 45.059 ;
     RECT  67.104 44.341 67.512 45.157 ;
     RECT  69.9 39.589 73.032 45.205 ;
     RECT  37.5 44.915 38.616 45.253 ;
     RECT  66.672 45.157 67.512 45.301 ;
     RECT  45.072 44.965 45.912 45.349 ;
     RECT  46.992 44.389 49.368 45.349 ;
     RECT  45.072 45.349 49.368 45.491 ;
     RECT  46.896 45.491 49.368 45.539 ;
     RECT  69.552 45.205 73.032 45.541 ;
     RECT  55.392 45.059 57.48 45.635 ;
     RECT  51 44.483 51.432 45.685 ;
     RECT  64.032 45.011 65.016 45.731 ;
     RECT  34.8 23.557 35.976 45.877 ;
     RECT  34.8 45.877 36.168 45.923 ;
     RECT  98.544 39.877 98.568 46.117 ;
     RECT  98.304 46.117 98.568 46.163 ;
     RECT  37.248 45.253 38.616 46.211 ;
     RECT  66.672 45.301 67.608 46.211 ;
     RECT  40.2 44.867 41.064 46.259 ;
     RECT  79.776 44.341 81.012 46.309 ;
     RECT  67.2 46.211 67.608 46.547 ;
     RECT  53.7 44.195 54.012 46.645 ;
     RECT  55.392 45.635 57.24 46.645 ;
     RECT  59.1 44.483 59.412 46.693 ;
     RECT  51 45.685 52.2 46.787 ;
     RECT  46.992 45.539 49.368 47.077 ;
     RECT  53.7 46.645 57.24 47.269 ;
     RECT  69.456 45.541 73.032 47.269 ;
     RECT  45.072 45.491 45.912 47.315 ;
     RECT  42.48 44.869 43.212 47.363 ;
     RECT  68.64 47.269 73.032 47.461 ;
     RECT  74.064 44.053 75.612 47.461 ;
     RECT  78 44.963 78.504 47.605 ;
     RECT  79.728 46.309 81.012 47.605 ;
     RECT  78 47.605 81.012 47.651 ;
     RECT  46.992 47.077 49.416 47.653 ;
     RECT  51 46.787 51.312 47.653 ;
     RECT  64.032 45.731 64.812 47.701 ;
     RECT  40.2 46.259 40.512 47.749 ;
     RECT  0.336 47.749 0.36 47.845 ;
     RECT  34.8 45.923 35.112 47.845 ;
     RECT  36.144 45.923 36.168 47.845 ;
     RECT  68.64 47.461 75.612 47.893 ;
     RECT  53.088 47.269 57.24 48.083 ;
     RECT  26.7 2.151 27.012 48.229 ;
     RECT  34.8 47.845 36.168 48.229 ;
     RECT  37.5 46.211 38.616 48.229 ;
     RECT  85.872 44.965 86.412 48.373 ;
     RECT  45.6 47.315 45.912 48.421 ;
     RECT  46.992 47.653 51.312 48.421 ;
     RECT  67.2 46.547 67.512 48.421 ;
     RECT  59.1 46.693 59.544 48.469 ;
     RECT  39.888 47.749 40.512 48.515 ;
     RECT  53.7 48.083 57.24 48.659 ;
     RECT  42.9 47.363 43.212 48.709 ;
     RECT  45.6 48.421 51.312 48.755 ;
     RECT  59.1 48.469 59.592 48.757 ;
     RECT  99.6 25.715 99.912 48.757 ;
     RECT  34.8 48.229 38.616 48.947 ;
     RECT  42.9 48.709 43.896 48.995 ;
     RECT  53.7 48.659 57.048 49.043 ;
     RECT  99.6 48.757 100.872 49.043 ;
     RECT  68.64 47.893 75.912 49.091 ;
     RECT  61.536 44.483 62.112 49.189 ;
     RECT  63.216 47.701 64.812 49.189 ;
     RECT  34.8 48.947 35.112 49.285 ;
     RECT  48.3 48.755 51.312 49.285 ;
     RECT  34.512 49.285 35.112 49.333 ;
     RECT  36.768 48.947 38.616 49.475 ;
     RECT  34.224 49.333 35.112 49.477 ;
     RECT  61.536 49.189 64.812 49.571 ;
     RECT  85.488 48.373 86.412 49.571 ;
     RECT  48.3 49.285 51.864 49.619 ;
     RECT  67.2 48.421 67.656 49.619 ;
     RECT  26.7 48.229 27.384 49.811 ;
     RECT  98.304 46.163 98.328 49.813 ;
     RECT  98.304 49.813 98.616 49.859 ;
     RECT  40.2 48.515 40.512 50.101 ;
     RECT  42.9 48.995 43.656 50.149 ;
     RECT  66.048 49.285 66.072 50.195 ;
     RECT  61.536 49.571 62.712 50.243 ;
     RECT  68.64 49.091 73.032 50.675 ;
     RECT  82.032 49.525 82.056 50.675 ;
     RECT  37.5 49.475 38.616 50.771 ;
     RECT  68.64 50.675 68.664 50.867 ;
     RECT  74.064 49.091 75.912 51.155 ;
     RECT  53.7 49.043 56.712 51.203 ;
     RECT  78 47.651 79.08 51.203 ;
     RECT  33.84 49.477 35.112 51.205 ;
     RECT  58.704 48.757 59.592 51.205 ;
     RECT  67.2 49.619 67.512 51.205 ;
     RECT  50.208 49.619 51.864 51.251 ;
     RECT  58.656 51.205 59.592 51.251 ;
     RECT  61.536 50.243 62.112 51.253 ;
     RECT  80.544 47.651 81.012 51.347 ;
     RECT  83.4 44.867 83.712 51.493 ;
     RECT  42.9 50.149 44.472 51.539 ;
     RECT  96.9 42.803 97.212 51.637 ;
     RECT  78 51.203 78.792 51.779 ;
     RECT  37.5 50.771 37.812 51.829 ;
     RECT  42.9 51.539 43.656 51.829 ;
     RECT  53.7 51.203 54.792 51.829 ;
     RECT  40.2 50.101 41.016 51.923 ;
     RECT  53.136 51.829 54.792 51.923 ;
     RECT  78 51.779 78.408 51.923 ;
     RECT  60.72 51.253 62.112 52.019 ;
     RECT  82.608 51.493 83.712 52.019 ;
     RECT  86.1 49.571 86.412 52.021 ;
     RECT  58.656 51.251 59.412 52.213 ;
     RECT  64.032 49.571 64.812 52.213 ;
     RECT  66.768 51.205 67.512 52.261 ;
     RECT  88.8 2.151 89.112 52.261 ;
     RECT  96.9 51.637 97.32 52.261 ;
     RECT  98.592 49.859 98.616 52.307 ;
     RECT  48.3 49.619 48.612 52.405 ;
     RECT  37.008 51.829 37.812 52.499 ;
     RECT  96.624 52.261 97.32 52.499 ;
     RECT  63.84 52.213 64.812 52.595 ;
     RECT  66.768 52.261 67.8 52.595 ;
     RECT  66.768 52.595 67.512 52.691 ;
     RECT  69.9 50.675 73.032 52.693 ;
     RECT  74.064 51.155 75.768 52.693 ;
     RECT  69.9 52.693 75.768 52.931 ;
     RECT  37.5 52.499 37.812 52.981 ;
     RECT  42.768 51.829 43.656 53.027 ;
     RECT  48.192 52.405 48.612 53.075 ;
     RECT  88.608 52.261 89.112 53.267 ;
     RECT  55.824 51.203 56.712 53.269 ;
     RECT  58.656 52.213 59.64 53.411 ;
     RECT  37.5 52.981 37.944 53.555 ;
     RECT  68.784 51.781 68.808 53.557 ;
     RECT  69.9 52.931 73.032 53.557 ;
     RECT  85.488 52.021 86.412 53.557 ;
     RECT  88.8 53.267 89.112 53.557 ;
     RECT  68.784 53.557 73.032 53.603 ;
     RECT  84.96 53.557 86.412 53.603 ;
     RECT  53.136 51.923 54.696 53.795 ;
     RECT  37.5 53.555 37.812 53.797 ;
     RECT  50.208 51.251 51.312 53.845 ;
     RECT  55.824 53.269 57.048 53.891 ;
     RECT  83.4 52.019 83.712 53.893 ;
     RECT  40.2 51.923 40.512 53.989 ;
     RECT  96.624 52.499 97.212 54.085 ;
     RECT  99.6 49.043 99.912 54.133 ;
     RECT  39.072 52.981 39.096 54.179 ;
     RECT  40.2 53.989 40.632 54.227 ;
     RECT  69.504 53.603 73.032 54.229 ;
     RECT  53.136 53.795 54.648 54.371 ;
     RECT  58.752 53.411 59.64 54.371 ;
     RECT  69.504 54.229 73.08 54.467 ;
     RECT  88.8 53.557 89.544 54.563 ;
     RECT  53.28 54.371 54.648 54.707 ;
     RECT  74.064 52.931 75.768 54.709 ;
     RECT  76.896 48.421 76.92 54.709 ;
     RECT  96.336 54.085 97.212 54.755 ;
     RECT  99.504 54.133 99.912 54.755 ;
     RECT  86.1 53.603 86.412 54.853 ;
     RECT  88.8 54.563 89.112 54.853 ;
     RECT  83.28 53.893 83.712 54.899 ;
     RECT  0.192 47.845 0.36 54.947 ;
     RECT  84.96 53.603 84.984 54.949 ;
     RECT  86.1 54.853 86.52 54.949 ;
     RECT  74.064 54.709 76.92 54.995 ;
     RECT  42.9 53.027 43.656 55.045 ;
     RECT  56.4 53.891 57.048 55.093 ;
     RECT  56.4 55.093 57.816 55.139 ;
     RECT  37.392 53.797 37.812 55.141 ;
     RECT  33.408 51.205 35.112 55.189 ;
     RECT  82.08 53.365 82.104 55.235 ;
     RECT  29.4 2.151 29.712 55.237 ;
     RECT  84.96 54.949 86.52 55.283 ;
     RECT  36.432 55.141 37.812 55.331 ;
     RECT  42.9 55.045 44.472 55.331 ;
     RECT  40.2 54.227 40.512 55.381 ;
     RECT  85.2 55.283 86.52 55.427 ;
     RECT  78 51.923 78.312 55.429 ;
     RECT  67.2 52.691 67.512 55.477 ;
     RECT  45.6 48.755 47.112 55.525 ;
     RECT  50.208 53.845 51.72 55.667 ;
     RECT  53.28 54.707 54.012 55.669 ;
     RECT  69.504 54.467 73.032 55.669 ;
     RECT  66.288 55.477 67.512 55.813 ;
     RECT  99.6 54.755 99.912 55.813 ;
     RECT  88.128 54.853 89.112 55.955 ;
     RECT  56.4 55.139 56.712 55.957 ;
     RECT  40.2 55.381 41.112 56.003 ;
     RECT  44.448 55.331 44.472 56.003 ;
     RECT  64.5 52.595 64.812 56.101 ;
     RECT  57.792 55.139 57.816 56.195 ;
     RECT  61.536 52.019 62.112 56.341 ;
     RECT  98.64 55.813 99.912 56.387 ;
     RECT  40.2 56.003 40.512 56.389 ;
     RECT  42.9 55.331 43.212 56.437 ;
     RECT  53.184 55.669 54.012 56.531 ;
     RECT  66.288 55.813 67.992 56.677 ;
     RECT  68.976 55.669 73.032 56.677 ;
     RECT  42.9 56.437 43.416 56.867 ;
     RECT  78 55.429 78.696 56.869 ;
     RECT  42.9 56.867 43.212 56.917 ;
     RECT  64.272 56.101 64.812 56.965 ;
     RECT  66.288 56.677 73.032 56.965 ;
     RECT  33.408 55.189 35.304 57.059 ;
     RECT  64.272 56.965 73.032 57.059 ;
     RECT  85.2 55.427 86.412 57.109 ;
     RECT  64.272 57.059 68.376 57.251 ;
     RECT  39.36 56.389 40.512 57.299 ;
     RECT  42.528 56.917 43.212 57.301 ;
     RECT  96.9 54.755 97.212 57.397 ;
     RECT  56.064 55.957 56.712 57.443 ;
     RECT  90.48 57.013 90.504 57.541 ;
     RECT  91.5 2.151 91.812 57.541 ;
     RECT  96.9 57.397 97.32 57.541 ;
     RECT  88.416 55.955 89.112 57.587 ;
     RECT  90.48 57.541 91.812 57.587 ;
     RECT  64.272 57.251 64.812 57.635 ;
     RECT  88.704 57.587 89.112 57.683 ;
     RECT  28.8 55.237 29.712 58.117 ;
     RECT  61.008 56.341 62.112 58.163 ;
     RECT  90.576 57.587 91.812 58.163 ;
     RECT  84.864 57.109 86.412 58.403 ;
     RECT  48.3 53.075 48.612 58.597 ;
     RECT  50.208 55.667 51.312 58.597 ;
     RECT  66.288 57.251 68.376 58.643 ;
     RECT  44.448 57.589 44.472 58.645 ;
     RECT  45.456 55.525 47.112 58.645 ;
     RECT  44.448 58.645 47.112 58.691 ;
     RECT  36.432 55.331 36.456 58.693 ;
     RECT  37.5 55.331 37.812 58.693 ;
     RECT  56.4 57.443 56.712 58.693 ;
     RECT  42.192 57.301 43.212 58.739 ;
     RECT  53.7 56.531 54.012 58.741 ;
     RECT  55.824 58.693 56.712 58.741 ;
     RECT  53.7 58.741 56.712 59.075 ;
     RECT  33.408 57.059 35.112 59.171 ;
     RECT  28.8 58.117 30.36 59.221 ;
     RECT  64.5 57.635 64.812 59.221 ;
     RECT  36.432 58.693 37.812 59.267 ;
     RECT  28.656 59.221 30.36 59.269 ;
     RECT  80.7 51.347 81.012 59.605 ;
     RECT  85.2 58.403 86.412 59.605 ;
     RECT  28.176 59.269 30.36 59.701 ;
     RECT  36.432 59.267 36.456 59.797 ;
     RECT  42.9 58.739 43.212 59.797 ;
     RECT  61.536 58.163 62.112 60.277 ;
     RECT  63.648 59.221 64.812 60.277 ;
     RECT  88.8 57.683 89.112 60.325 ;
     RECT  61.536 60.277 64.812 60.373 ;
     RECT  69.456 57.059 73.032 60.373 ;
     RECT  74.064 54.995 76.632 60.373 ;
     RECT  44.64 58.691 47.112 60.421 ;
     RECT  44.64 60.421 47.304 60.467 ;
     RECT  66.288 58.643 67.992 60.467 ;
     RECT  69.456 60.373 76.632 60.467 ;
     RECT  79.968 59.605 81.012 60.469 ;
     RECT  36.336 59.797 36.456 60.563 ;
     RECT  79.968 60.469 81.288 60.611 ;
     RECT  37.5 59.267 37.812 60.805 ;
     RECT  53.7 59.075 55.176 60.853 ;
     RECT  85.104 59.605 86.412 60.899 ;
     RECT  56.4 59.075 56.712 60.949 ;
     RECT  88.32 60.325 89.112 60.949 ;
     RECT  61.536 60.373 65.064 61.043 ;
     RECT  88.32 60.949 89.208 61.043 ;
     RECT  28.176 59.701 30.84 61.091 ;
     RECT  44.64 60.467 46.248 61.091 ;
     RECT  53.088 60.853 55.176 61.285 ;
     RECT  28.176 61.091 30.36 61.379 ;
     RECT  96.624 57.541 97.32 61.379 ;
     RECT  69.456 60.467 75.864 61.475 ;
     RECT  48.3 58.597 51.312 61.619 ;
     RECT  61.536 61.043 64.812 61.619 ;
     RECT  83.4 54.899 83.712 61.621 ;
     RECT  33.84 59.171 35.112 61.667 ;
     RECT  69.456 61.475 75.612 61.763 ;
     RECT  85.44 60.899 86.412 61.813 ;
     RECT  85.44 61.813 86.568 62.147 ;
     RECT  37.5 60.805 38.184 62.195 ;
     RECT  52.368 61.285 55.176 62.195 ;
     RECT  42.9 59.797 43.656 62.245 ;
     RECT  80.7 60.611 81.288 62.291 ;
     RECT  85.488 62.147 86.568 62.339 ;
     RECT  36.432 60.563 36.456 62.389 ;
     RECT  36.24 62.389 36.456 62.435 ;
     RECT  83.4 61.621 83.88 62.435 ;
     RECT  47.28 60.467 47.304 62.483 ;
     RECT  67.2 60.467 67.992 62.483 ;
     RECT  45.456 61.091 46.248 62.629 ;
     RECT  28.656 61.379 30.36 62.677 ;
     RECT  42.9 62.245 43.704 63.011 ;
     RECT  34.512 61.667 35.112 63.107 ;
     RECT  26.7 49.811 27.012 63.205 ;
     RECT  94.2 34.787 94.512 63.205 ;
     RECT  56.4 60.949 57.288 63.251 ;
     RECT  28.656 62.677 30.744 63.253 ;
     RECT  32.1 2.151 32.412 63.253 ;
     RECT  40.2 57.299 40.512 63.253 ;
     RECT  50.208 61.619 51.312 63.299 ;
     RECT  85.488 62.339 86.412 63.395 ;
     RECT  28.656 63.253 30.792 63.443 ;
     RECT  34.8 63.107 35.112 63.781 ;
     RECT  36.24 62.435 36.264 63.781 ;
     RECT  74.304 61.763 75.612 63.781 ;
     RECT  83.4 62.435 83.712 63.781 ;
     RECT  34.8 63.781 36.264 63.827 ;
     RECT  53.088 62.195 54.012 63.829 ;
     RECT  42.9 63.011 43.32 63.923 ;
     RECT  69.456 61.763 73.032 64.309 ;
     RECT  74.304 63.781 75.72 64.309 ;
     RECT  56.4 63.251 56.712 64.357 ;
     RECT  55.152 62.195 55.176 64.403 ;
     RECT  78 56.869 78.84 64.451 ;
     RECT  53.04 63.829 54.012 64.595 ;
     RECT  67.2 62.483 67.944 64.741 ;
     RECT  69.456 64.309 75.72 64.883 ;
     RECT  51 63.299 51.312 64.933 ;
     RECT  67.2 64.741 68.28 64.979 ;
     RECT  32.1 63.253 32.856 65.027 ;
     RECT  40.2 63.253 40.632 65.027 ;
     RECT  74.304 64.883 75.72 65.125 ;
     RECT  34.8 63.827 36.024 65.171 ;
     RECT  44.784 62.629 46.248 65.219 ;
     RECT  74.304 65.125 75.768 65.267 ;
     RECT  48.3 61.619 49.08 65.509 ;
     RECT  59.1 54.371 59.64 65.509 ;
     RECT  42.9 63.923 43.212 65.557 ;
     RECT  45.072 65.219 46.248 65.603 ;
     RECT  50.352 64.933 51.312 65.651 ;
     RECT  47.664 65.509 49.08 65.699 ;
     RECT  96.624 61.379 97.212 65.701 ;
     RECT  96.624 65.701 98.04 65.747 ;
     RECT  28.656 63.443 30.744 65.845 ;
     RECT  37.5 62.195 37.812 65.941 ;
     RECT  40.2 65.027 40.512 66.085 ;
     RECT  78 64.451 78.312 66.085 ;
     RECT  32.1 65.027 32.412 66.133 ;
     RECT  63.648 61.619 64.812 66.179 ;
     RECT  83.232 63.781 83.712 66.179 ;
     RECT  56.4 64.357 57.192 66.227 ;
     RECT  26.448 63.205 27.012 66.325 ;
     RECT  45.072 65.603 45.912 66.515 ;
     RECT  26.16 66.325 27.012 66.661 ;
     RECT  28.656 65.845 30.888 66.661 ;
     RECT  34.8 65.171 35.112 66.661 ;
     RECT  36.672 65.941 37.812 66.661 ;
     RECT  26.16 66.661 30.888 66.707 ;
     RECT  50.88 65.651 51.312 66.709 ;
     RECT  86.1 63.395 86.412 66.709 ;
     RECT  32.1 66.133 33 66.755 ;
     RECT  34.8 66.661 37.812 66.755 ;
     RECT  42.9 65.557 43.992 66.755 ;
     RECT  84.864 65.509 84.888 66.755 ;
     RECT  88.8 61.043 89.208 66.803 ;
     RECT  0.192 54.947 0.216 66.851 ;
     RECT  42.9 66.755 43.212 66.901 ;
     RECT  67.2 64.979 67.944 66.995 ;
     RECT  94.2 63.205 94.776 66.995 ;
     RECT  26.16 66.707 30.792 67.091 ;
     RECT  69.456 64.883 73.032 67.093 ;
     RECT  74.304 65.267 75.612 67.093 ;
     RECT  26.16 67.091 30.408 67.139 ;
     RECT  50.208 66.709 51.312 67.235 ;
     RECT  39.408 66.085 40.512 67.237 ;
     RECT  26.16 67.139 30.36 67.283 ;
     RECT  45.264 66.515 45.912 67.283 ;
     RECT  85.968 66.709 86.412 67.283 ;
     RECT  58.992 65.509 59.64 67.331 ;
     RECT  83.4 66.179 83.712 67.333 ;
     RECT  78 66.085 78.696 67.379 ;
     RECT  91.5 58.163 91.812 67.381 ;
     RECT  34.8 66.755 35.832 67.475 ;
     RECT  47.664 65.699 48.612 67.571 ;
     RECT  83.4 67.333 84.648 67.667 ;
     RECT  56.4 66.227 56.712 67.717 ;
     RECT  67.2 66.995 67.704 67.811 ;
     RECT  26.7 67.283 30.36 67.859 ;
     RECT  56.4 67.717 57.192 67.859 ;
     RECT  61.536 61.619 62.112 67.957 ;
     RECT  39.408 67.237 40.776 68.099 ;
     RECT  91.5 67.381 91.944 68.099 ;
     RECT  40.2 68.099 40.776 68.101 ;
     RECT  42.144 66.901 43.212 68.101 ;
     RECT  80.7 62.291 81.012 68.341 ;
     RECT  91.5 68.099 91.812 68.341 ;
     RECT  83.4 67.667 83.712 68.389 ;
     RECT  88.8 66.803 89.112 68.389 ;
     RECT  40.2 68.101 43.212 68.435 ;
     RECT  83.088 68.389 83.712 68.629 ;
     RECT  56.4 67.859 56.712 68.677 ;
     RECT  40.2 68.435 41.688 68.723 ;
     RECT  69.456 67.093 75.612 68.725 ;
     RECT  34.8 67.475 35.112 68.821 ;
     RECT  59.1 67.331 59.64 68.821 ;
     RECT  64.5 66.179 64.812 68.821 ;
     RECT  55.824 68.677 56.712 68.867 ;
     RECT  64.5 68.821 65.016 68.963 ;
     RECT  59.1 68.821 59.832 68.965 ;
     RECT  80.7 68.341 81.144 68.965 ;
     RECT  94.2 66.995 94.512 68.965 ;
     RECT  69.456 68.725 75.72 69.011 ;
     RECT  87.984 68.389 89.112 69.059 ;
     RECT  93.36 68.965 94.512 69.203 ;
     RECT  61.536 67.957 62.664 69.395 ;
     RECT  80.7 68.965 81.576 69.445 ;
     RECT  90.576 68.341 91.812 69.491 ;
     RECT  26.7 67.859 27.012 69.493 ;
     RECT  28.368 67.859 30.36 69.493 ;
     RECT  82.8 68.629 83.712 69.587 ;
     RECT  66.192 68.341 66.216 69.683 ;
     RECT  34.8 68.821 35.688 69.827 ;
     RECT  78 67.379 78.312 69.829 ;
     RECT  79.824 69.445 81.576 69.923 ;
     RECT  53.088 64.595 54.012 69.973 ;
     RECT  32.1 66.755 32.412 70.021 ;
     RECT  59.1 68.965 60.504 70.067 ;
     RECT  26.7 69.493 30.36 70.163 ;
     RECT  72.096 69.011 75.72 70.211 ;
     RECT  83.4 69.587 83.712 70.261 ;
     RECT  88.8 69.059 89.112 70.357 ;
     RECT  38.928 69.493 38.952 70.547 ;
     RECT  41.808 69.445 41.832 70.547 ;
     RECT  78 69.829 78.456 70.549 ;
     RECT  77.856 70.549 78.456 70.595 ;
     RECT  79.824 69.923 81.144 70.595 ;
     RECT  83.4 70.261 84.216 70.643 ;
     RECT  64.5 68.963 64.812 70.741 ;
     RECT  80.7 70.595 81.144 71.027 ;
     RECT  88.8 70.357 89.208 71.077 ;
     RECT  31.968 70.021 32.412 71.221 ;
     RECT  64.32 70.741 64.812 71.267 ;
     RECT  37.5 66.755 37.812 71.317 ;
     RECT  41.856 70.645 41.88 71.411 ;
     RECT  64.5 71.267 64.812 71.461 ;
     RECT  26.7 70.163 27.012 71.509 ;
     RECT  33.648 69.493 33.672 71.509 ;
     RECT  34.8 69.827 35.112 71.509 ;
     RECT  33.648 71.509 35.112 71.555 ;
     RECT  37.5 71.317 38.184 71.653 ;
     RECT  80.7 71.027 81.012 71.797 ;
     RECT  36.768 71.653 38.184 71.843 ;
     RECT  77.856 70.595 78.312 71.845 ;
     RECT  99.6 56.387 99.912 71.845 ;
     RECT  84.768 71.077 84.792 71.891 ;
     RECT  50.448 67.235 51.312 71.941 ;
     RECT  94.2 69.203 94.512 72.037 ;
     RECT  36.768 71.843 37.812 72.083 ;
     RECT  99.504 71.845 99.912 72.179 ;
     RECT  67.2 67.811 67.512 72.181 ;
     RECT  96.9 65.747 98.04 72.325 ;
     RECT  34.032 71.555 35.112 72.371 ;
     RECT  88.8 71.077 90.072 72.371 ;
     RECT  96.9 72.325 98.472 72.371 ;
     RECT  69.456 69.011 70.728 72.419 ;
     RECT  45.456 67.283 45.912 72.467 ;
     RECT  69.9 72.419 70.728 72.469 ;
     RECT  28.368 70.163 30.36 72.565 ;
     RECT  42.9 68.435 43.212 72.565 ;
     RECT  44.448 71.221 44.472 72.565 ;
     RECT  31.92 71.221 32.412 72.659 ;
     RECT  94.2 72.037 95.256 72.659 ;
     RECT  77.856 71.845 78.408 72.707 ;
     RECT  34.8 72.371 35.112 72.709 ;
     RECT  50.448 71.941 51.528 72.803 ;
     RECT  28.32 72.565 30.36 72.805 ;
     RECT  53.088 69.973 54.12 72.853 ;
     RECT  50.448 72.803 51.312 72.901 ;
     RECT  67.104 72.181 67.512 72.901 ;
     RECT  64.5 71.461 65.736 72.947 ;
     RECT  28.32 72.805 30.6 72.949 ;
     RECT  61.536 69.395 62.112 72.949 ;
     RECT  56.4 68.867 56.712 72.997 ;
     RECT  69.9 72.469 71.016 72.997 ;
     RECT  72.096 70.211 75.612 72.997 ;
     RECT  79.872 71.797 81.012 72.997 ;
     RECT  28.32 72.949 30.984 73.091 ;
     RECT  64.5 72.947 65.016 73.091 ;
     RECT  69.9 72.997 75.612 73.139 ;
     RECT  55.584 72.997 56.712 73.187 ;
     RECT  61.104 72.949 62.112 73.187 ;
     RECT  83.4 70.643 83.712 73.237 ;
     RECT  84.72 72.277 84.744 73.237 ;
     RECT  37.008 72.083 37.812 73.285 ;
     RECT  37.008 73.285 38.184 73.331 ;
     RECT  78 72.707 78.408 73.331 ;
     RECT  34.8 72.709 35.928 73.381 ;
     RECT  42.9 72.565 44.472 73.381 ;
     RECT  42 73.381 44.472 73.475 ;
     RECT  66.72 72.901 67.512 73.477 ;
     RECT  68.592 72.805 68.616 73.477 ;
     RECT  52.464 72.853 54.12 73.619 ;
     RECT  83.28 73.237 84.744 73.715 ;
     RECT  71.856 73.139 75.612 73.765 ;
     RECT  88.8 72.371 89.208 73.861 ;
     RECT  61.392 73.187 62.112 73.907 ;
     RECT  37.5 73.331 38.184 74.053 ;
     RECT  46.944 73.861 46.968 74.101 ;
     RECT  48.3 67.571 48.612 74.101 ;
     RECT  79.872 72.997 81.144 74.291 ;
     RECT  83.28 73.715 83.712 74.291 ;
     RECT  84.72 73.715 84.744 74.293 ;
     RECT  84.72 74.293 84.984 74.339 ;
     RECT  91.5 69.491 91.812 74.341 ;
     RECT  80.7 74.291 81.144 74.531 ;
     RECT  34.272 73.381 35.928 74.675 ;
     RECT  40.2 68.723 40.776 74.675 ;
     RECT  28.32 73.091 30.792 74.723 ;
     RECT  34.8 74.675 35.928 74.771 ;
     RECT  26.16 71.509 27.012 74.819 ;
     RECT  88.8 73.861 89.448 74.819 ;
     RECT  42 73.475 43.212 74.821 ;
     RECT  44.448 73.475 44.472 74.821 ;
     RECT  42 74.821 44.472 74.867 ;
     RECT  69.9 73.139 70.728 74.917 ;
     RECT  71.856 73.765 75.768 74.917 ;
     RECT  86.1 67.283 86.412 75.109 ;
     RECT  66.72 73.477 68.616 75.299 ;
     RECT  64.5 73.091 64.812 75.349 ;
     RECT  84.96 74.339 84.984 75.349 ;
     RECT  86.1 75.109 86.52 75.349 ;
     RECT  84.96 75.349 86.52 75.395 ;
     RECT  37.5 74.053 38.472 75.445 ;
     RECT  69.9 74.917 75.768 75.491 ;
     RECT  80.7 74.531 81.012 75.493 ;
     RECT  63.792 75.349 64.812 75.587 ;
     RECT  78 73.331 78.312 75.685 ;
     RECT  40.2 74.675 40.632 76.211 ;
     RECT  26.7 74.819 27.012 76.213 ;
     RECT  42 74.867 43.992 76.403 ;
     RECT  42.9 76.403 43.992 76.451 ;
     RECT  45.6 72.467 45.912 76.453 ;
     RECT  46.944 74.101 48.612 76.453 ;
     RECT  69.9 75.491 75.72 76.499 ;
     RECT  85.2 75.395 86.52 76.499 ;
     RECT  50.352 72.901 51.312 76.597 ;
     RECT  53.088 73.619 54.12 76.597 ;
     RECT  77.088 75.685 78.312 76.691 ;
     RECT  90.72 74.341 91.812 76.739 ;
     RECT  77.904 76.691 78.312 76.885 ;
     RECT  26.592 76.213 27.012 76.979 ;
     RECT  63.264 76.741 63.288 77.123 ;
     RECT  59.1 70.067 59.64 77.317 ;
     RECT  80.7 75.493 81.192 77.317 ;
     RECT  59.1 77.317 60.36 77.365 ;
     RECT  83.4 74.291 83.712 77.365 ;
     RECT  99.6 72.179 99.912 77.365 ;
     RECT  91.5 76.739 91.812 77.413 ;
     RECT  34.8 74.771 35.112 77.461 ;
     RECT  28.32 74.723 30.168 77.651 ;
     RECT  50.352 76.597 54.12 77.651 ;
     RECT  77.904 76.885 78.408 77.651 ;
     RECT  64.5 75.587 64.812 77.701 ;
     RECT  66.72 75.299 68.424 77.749 ;
     RECT  69.9 76.499 75.612 77.749 ;
     RECT  61.536 73.907 62.112 77.941 ;
     RECT  66.72 77.749 75.612 77.987 ;
     RECT  58.656 77.365 60.36 78.083 ;
     RECT  99.504 77.365 99.912 78.131 ;
     RECT  83.184 77.365 83.712 78.325 ;
     RECT  69.9 77.987 75.612 78.421 ;
     RECT  61.392 77.941 62.112 78.469 ;
     RECT  63.552 77.701 64.812 78.469 ;
     RECT  61.392 78.469 64.92 78.515 ;
     RECT  77.904 77.651 78.312 78.515 ;
     RECT  28.32 77.651 30.12 78.613 ;
     RECT  50.352 77.651 52.2 78.613 ;
     RECT  82.512 78.325 83.712 78.899 ;
     RECT  42.9 76.451 43.212 78.997 ;
     RECT  28.176 78.613 30.12 79.045 ;
     RECT  53.28 77.651 54.12 79.141 ;
     RECT  36.432 78.469 36.456 79.189 ;
     RECT  37.5 75.445 38.904 79.189 ;
     RECT  59.1 78.083 60.36 79.189 ;
     RECT  91.5 77.413 92.04 79.235 ;
     RECT  78 78.515 78.312 79.237 ;
     RECT  79.392 79.189 79.416 79.237 ;
     RECT  61.392 78.515 62.712 79.283 ;
     RECT  40.2 76.211 40.512 79.285 ;
     RECT  36.432 79.189 38.904 79.331 ;
     RECT  64.5 78.515 64.92 79.475 ;
     RECT  53.28 79.141 54.888 79.619 ;
     RECT  66.72 77.987 68.424 79.621 ;
     RECT  58.656 79.189 60.36 79.669 ;
     RECT  61.392 79.283 62.112 79.669 ;
     RECT  31.968 72.659 32.412 79.717 ;
     RECT  98.448 72.371 98.472 79.717 ;
     RECT  98.352 79.717 98.472 79.763 ;
     RECT  80.7 77.317 81.24 79.765 ;
     RECT  83.4 78.899 83.712 79.813 ;
     RECT  85.2 76.499 86.412 79.813 ;
     RECT  42.9 78.997 43.848 79.955 ;
     RECT  31.968 79.717 32.76 80.051 ;
     RECT  80.4 79.765 81.24 80.195 ;
     RECT  50.208 78.613 52.2 80.293 ;
     RECT  53.28 79.619 54.12 80.293 ;
     RECT  80.4 80.195 81.192 80.387 ;
     RECT  91.5 79.235 91.944 80.387 ;
     RECT  28.176 79.045 30.168 80.435 ;
     RECT  78 79.237 79.416 80.531 ;
     RECT  66.096 79.621 68.424 80.771 ;
     RECT  45.6 76.453 48.612 80.773 ;
     RECT  83.4 79.813 86.412 80.773 ;
     RECT  82.992 80.773 86.412 80.917 ;
     RECT  88.8 74.819 89.112 80.917 ;
     RECT  82.32 80.917 86.412 80.963 ;
     RECT  69.9 78.421 76.104 81.013 ;
     RECT  28.176 80.435 30.072 81.059 ;
     RECT  34.32 77.461 35.112 81.059 ;
     RECT  88.512 80.917 89.112 81.157 ;
     RECT  82.32 80.963 82.344 81.203 ;
     RECT  83.4 80.963 86.412 81.203 ;
     RECT  44.592 80.917 44.616 81.251 ;
     RECT  34.56 81.059 35.112 81.301 ;
     RECT  36.432 79.331 38.328 81.301 ;
     RECT  50.208 80.293 54.12 81.349 ;
     RECT  58.656 79.669 62.112 81.349 ;
     RECT  80.4 80.387 81.012 81.395 ;
     RECT  32.1 80.051 32.76 81.491 ;
     RECT  34.56 81.301 38.328 81.539 ;
     RECT  50.208 81.349 55.08 81.539 ;
     RECT  69.9 81.013 76.344 81.589 ;
     RECT  66.72 80.771 68.424 81.635 ;
     RECT  66.768 81.635 68.424 81.733 ;
     RECT  69.552 81.589 76.344 81.733 ;
     RECT  91.5 80.387 91.812 81.733 ;
     RECT  83.4 81.203 84.84 81.875 ;
     RECT  94.2 72.659 94.512 82.069 ;
     RECT  78 80.531 78.648 82.261 ;
     RECT  45.6 80.773 48.984 82.453 ;
     RECT  50.208 81.539 54.012 82.453 ;
     RECT  66.768 81.733 76.344 82.645 ;
     RECT  78 82.261 79.224 82.645 ;
     RECT  34.56 81.539 36.456 82.693 ;
     RECT  37.5 81.539 38.328 82.693 ;
     RECT  34.56 82.693 38.328 82.739 ;
     RECT  83.4 81.875 84.648 82.787 ;
     RECT  32.1 81.491 32.412 82.837 ;
     RECT  36.432 82.739 38.328 82.837 ;
     RECT  66.768 82.645 79.224 82.883 ;
     RECT  85.824 81.203 86.412 82.979 ;
     RECT  55.056 81.539 55.08 83.027 ;
     RECT  69.552 82.883 79.224 83.123 ;
     RECT  42.9 79.955 43.212 83.173 ;
     RECT  28.32 81.059 30.072 83.267 ;
     RECT  58.128 81.349 62.112 83.267 ;
     RECT  88.272 81.157 89.112 83.267 ;
     RECT  83.4 82.787 84.456 83.315 ;
     RECT  94.2 82.069 94.68 83.365 ;
     RECT  88.704 83.267 89.112 83.555 ;
     RECT  40.2 79.285 41.016 83.749 ;
     RECT  31.968 82.837 32.412 83.795 ;
     RECT  69.552 83.123 76.392 83.891 ;
     RECT  42.9 83.173 43.944 84.035 ;
     RECT  56.4 73.187 56.712 84.037 ;
     RECT  36.432 82.837 38.712 84.085 ;
     RECT  36.432 84.085 38.808 84.131 ;
     RECT  94.2 83.365 95.064 84.275 ;
     RECT  64.5 79.475 64.812 84.325 ;
     RECT  56.4 84.037 57.576 84.371 ;
     RECT  38.784 84.131 38.808 84.373 ;
     RECT  86.1 82.979 86.412 84.373 ;
     RECT  38.784 84.373 38.904 84.515 ;
     RECT  90.192 82.645 90.216 84.563 ;
     RECT  40.2 83.749 41.592 84.803 ;
     RECT  69.792 83.891 76.392 84.901 ;
     RECT  40.2 84.803 40.632 84.995 ;
     RECT  63.264 84.181 63.288 84.995 ;
     RECT  91.5 81.733 92.52 84.995 ;
     RECT  98.352 79.763 98.376 85.091 ;
     RECT  78 83.123 79.224 85.093 ;
     RECT  36.432 84.131 37.812 85.139 ;
     RECT  69.648 84.901 76.392 85.139 ;
     RECT  69.9 85.139 76.392 85.141 ;
     RECT  77.76 85.093 79.224 85.141 ;
     RECT  37.5 85.139 37.812 85.381 ;
     RECT  38.784 84.515 38.808 85.381 ;
     RECT  37.5 85.381 38.808 85.427 ;
     RECT  80.7 81.395 81.012 85.477 ;
     RECT  42.9 84.035 43.896 85.523 ;
     RECT  86.1 84.373 86.52 85.523 ;
     RECT  88.8 83.555 89.112 85.669 ;
     RECT  34.56 82.739 35.112 85.765 ;
     RECT  34.56 85.765 35.208 85.811 ;
     RECT  28.464 83.267 30.072 85.909 ;
     RECT  83.4 83.315 83.712 85.957 ;
     RECT  91.5 84.995 91.812 85.957 ;
     RECT  37.5 85.427 38.616 86.195 ;
     RECT  56.4 84.371 56.712 86.245 ;
     RECT  88.176 85.669 89.112 86.293 ;
     RECT  69.9 85.141 79.224 86.435 ;
     RECT  45.6 82.453 54.012 86.581 ;
     RECT  77.184 86.435 79.224 86.581 ;
     RECT  80.7 85.477 81.144 86.581 ;
     RECT  86.1 85.523 86.412 86.581 ;
     RECT  32.1 83.795 32.412 86.629 ;
     RECT  42.9 85.523 43.212 86.629 ;
     RECT  98.304 85.477 98.328 86.675 ;
     RECT  69.9 86.435 76.104 86.725 ;
     RECT  77.184 86.581 81.144 86.917 ;
     RECT  28.464 85.909 30.504 86.963 ;
     RECT  67.2 82.883 68.424 87.109 ;
     RECT  42.9 86.629 43.704 87.155 ;
     RECT  64.5 84.325 64.92 87.155 ;
     RECT  83.4 85.957 83.976 87.157 ;
     RECT  44.928 86.581 54.012 87.251 ;
     RECT  59.1 83.267 62.112 87.253 ;
     RECT  88.176 86.293 89.88 87.299 ;
     RECT  88.176 87.299 89.112 87.395 ;
     RECT  69.792 86.725 76.104 87.397 ;
     RECT  77.184 86.917 81.48 87.397 ;
     RECT  45.6 87.251 54.012 87.541 ;
     RECT  85.968 86.581 86.412 87.587 ;
     RECT  69.792 87.397 81.48 87.685 ;
     RECT  57.792 85.957 57.816 87.827 ;
     RECT  66.672 87.109 68.424 87.827 ;
     RECT  67.2 87.827 68.424 87.829 ;
     RECT  69.648 87.685 81.48 87.829 ;
     RECT  67.2 87.829 81.48 87.923 ;
     RECT  82.608 87.157 84.36 88.115 ;
     RECT  45.6 87.541 54.12 88.259 ;
     RECT  42.9 87.155 43.212 88.309 ;
     RECT  59.1 87.253 62.712 88.403 ;
     RECT  88.272 87.395 89.112 88.403 ;
     RECT  91.2 85.957 91.812 88.403 ;
     RECT  36.432 85.139 36.456 88.741 ;
     RECT  37.5 86.195 37.812 88.741 ;
     RECT  36.432 88.741 37.812 88.885 ;
     RECT  64.5 87.155 64.812 88.885 ;
     RECT  67.2 87.923 81.012 88.931 ;
     RECT  32.1 86.629 33.384 88.981 ;
     RECT  82.8 88.115 84.36 89.075 ;
     RECT  31.968 88.981 33.384 89.123 ;
     RECT  36.432 88.885 38.184 89.267 ;
     RECT  28.464 86.963 30.456 89.461 ;
     RECT  40.2 84.995 40.512 89.461 ;
     RECT  42.9 88.309 43.608 89.461 ;
     RECT  72.288 88.931 81.012 89.603 ;
     RECT  59.1 88.403 62.112 89.605 ;
     RECT  55.44 86.245 56.712 89.699 ;
     RECT  39.648 89.461 40.512 89.797 ;
     RECT  58.944 89.605 62.112 89.939 ;
     RECT  36.432 89.267 38.04 89.987 ;
     RECT  28.464 89.461 30.792 90.083 ;
     RECT  64.5 88.885 64.968 90.083 ;
     RECT  82.8 89.075 83.712 90.083 ;
     RECT  45.6 88.259 54.012 90.229 ;
     RECT  77.184 89.603 81.012 90.275 ;
     RECT  83.28 90.083 83.712 90.275 ;
     RECT  39.312 89.797 40.512 90.373 ;
     RECT  39.312 90.373 40.728 90.563 ;
     RECT  77.184 90.275 79.224 90.659 ;
     RECT  39.312 90.563 40.512 90.995 ;
     RECT  67.2 88.931 71.256 91.093 ;
     RECT  72.288 89.603 76.008 91.093 ;
     RECT  31.968 89.123 32.412 91.139 ;
     RECT  42.9 89.461 44.568 91.141 ;
     RECT  45.6 90.229 54.216 91.141 ;
     RECT  59.1 89.939 62.112 91.141 ;
     RECT  28.464 90.083 30.312 91.333 ;
     RECT  66.144 90.949 66.168 91.475 ;
     RECT  59.1 91.141 62.712 91.619 ;
     RECT  28.464 91.333 30.504 91.621 ;
     RECT  57.84 91.429 57.864 91.621 ;
     RECT  56.4 89.699 56.712 91.669 ;
     RECT  57.84 91.621 57.912 91.669 ;
     RECT  59.1 91.619 59.544 91.669 ;
     RECT  83.4 90.275 83.712 91.669 ;
     RECT  34.8 85.811 35.208 91.717 ;
     RECT  77.184 90.659 79.08 91.717 ;
     RECT  80.592 90.275 81.012 91.717 ;
     RECT  36.432 89.987 36.456 91.811 ;
     RECT  60.816 91.619 62.712 91.859 ;
     RECT  37.5 89.987 38.04 91.955 ;
     RECT  34.368 91.717 35.208 91.957 ;
     RECT  37.5 91.955 37.812 92.005 ;
     RECT  34.224 91.957 35.208 92.147 ;
     RECT  34.224 92.147 35.112 92.149 ;
     RECT  33.936 92.149 35.112 92.197 ;
     RECT  42.9 91.141 54.216 92.245 ;
     RECT  67.2 91.093 76.008 92.245 ;
     RECT  77.184 91.717 81.012 92.245 ;
     RECT  39.648 90.995 40.512 92.339 ;
     RECT  94.2 84.275 94.512 92.437 ;
     RECT  94.2 92.437 94.632 92.579 ;
     RECT  28.464 91.621 31.032 92.677 ;
     RECT  42.768 92.245 54.216 92.677 ;
     RECT  56.304 91.669 56.712 92.723 ;
     RECT  82.08 91.141 82.104 92.723 ;
     RECT  57.84 91.669 59.544 92.725 ;
     RECT  60.816 91.859 62.112 92.725 ;
     RECT  42.768 92.677 54.264 92.773 ;
     RECT  83.28 91.669 83.712 92.773 ;
     RECT  64.5 90.083 64.812 92.965 ;
     RECT  42.768 92.773 54.504 93.061 ;
     RECT  57.84 92.725 62.112 93.061 ;
     RECT  67.2 92.245 81.012 93.205 ;
     RECT  26.7 76.979 27.012 93.301 ;
     RECT  28.464 92.677 31.08 93.301 ;
     RECT  56.4 92.723 56.712 93.301 ;
     RECT  57.84 93.061 62.28 93.301 ;
     RECT  64.5 92.965 64.968 93.301 ;
     RECT  66.24 93.205 81.012 93.301 ;
     RECT  40.2 92.339 40.512 93.397 ;
     RECT  41.616 92.533 41.64 93.539 ;
     RECT  83.28 92.773 84.408 93.539 ;
     RECT  42.768 93.061 54.696 93.589 ;
     RECT  42.768 93.589 55.176 93.781 ;
     RECT  33.552 92.197 35.112 93.877 ;
     RECT  36.576 92.005 37.812 93.877 ;
     RECT  26.7 93.301 31.08 93.925 ;
     RECT  32.1 91.139 32.412 93.925 ;
     RECT  86.1 87.587 86.412 94.021 ;
     RECT  56.4 93.301 62.28 94.115 ;
     RECT  26.7 93.925 32.412 94.403 ;
     RECT  39.312 93.397 40.512 94.643 ;
     RECT  56.4 94.115 62.112 94.643 ;
     RECT  64.5 93.301 81.012 94.643 ;
     RECT  26.7 94.403 31.08 94.691 ;
     RECT  83.28 93.539 83.712 94.837 ;
     RECT  32.1 94.403 32.412 94.981 ;
     RECT  33.552 93.877 37.812 94.981 ;
     RECT  41.808 93.781 55.176 95.125 ;
     RECT  61.8 94.643 62.112 95.125 ;
     RECT  79.872 94.643 81.012 95.171 ;
     RECT  64.5 94.643 78.696 95.315 ;
     RECT  28.032 94.691 31.08 95.653 ;
     RECT  32.1 94.981 37.812 95.653 ;
     RECT  41.808 95.125 55.272 95.699 ;
     RECT  77.856 95.315 78.696 95.701 ;
     RECT  28.032 95.653 37.944 95.795 ;
     RECT  26.7 94.691 27.012 95.941 ;
     RECT  28.032 95.795 32.412 95.941 ;
     RECT  42.096 95.699 55.272 95.989 ;
     RECT  39.552 94.643 40.512 96.179 ;
     RECT  82.704 94.837 83.712 96.323 ;
     RECT  33.552 95.795 37.944 96.325 ;
     RECT  77.856 95.701 79.224 96.469 ;
     RECT  61.8 95.125 62.232 96.707 ;
     RECT  56.4 94.643 60.648 96.757 ;
     RECT  61.8 96.707 62.112 96.757 ;
     RECT  77.664 96.469 79.224 96.803 ;
     RECT  85.68 94.021 86.412 96.995 ;
     RECT  80.496 95.171 81.012 97.381 ;
     RECT  83.232 96.323 83.712 97.381 ;
     RECT  56.4 96.757 62.112 97.429 ;
     RECT  56.304 97.429 62.112 97.523 ;
     RECT  42.096 95.989 55.32 97.525 ;
     RECT  56.304 97.523 60.36 97.525 ;
     RECT  33.552 96.325 38.52 97.811 ;
     RECT  40.2 96.179 40.512 97.861 ;
     RECT  61.8 97.523 62.112 97.861 ;
     RECT  83.232 97.381 83.832 97.907 ;
     RECT  61.8 97.861 62.808 97.957 ;
     RECT  64.5 95.315 76.68 97.957 ;
     RECT  79.824 97.381 81.012 97.957 ;
     RECT  26.7 95.941 32.412 98.005 ;
     RECT  39.36 97.861 40.512 98.101 ;
     RECT  79.824 97.957 81.816 98.293 ;
     RECT  83.232 97.907 83.712 98.339 ;
     RECT  83.28 98.339 83.712 98.435 ;
     RECT  24 2.151 24.312 98.485 ;
     RECT  25.872 98.005 32.412 98.485 ;
     RECT  33.552 97.811 37.944 98.723 ;
     RECT  39.36 98.101 41.016 98.723 ;
     RECT  77.664 96.803 78.696 98.915 ;
     RECT  79.824 98.293 82.056 98.915 ;
     RECT  77.856 98.915 78.696 98.963 ;
     RECT  24 98.485 32.412 99.203 ;
     RECT  79.824 98.915 81.816 99.203 ;
     RECT  24 99.203 31.08 99.251 ;
     RECT  24 99.251 30.744 99.299 ;
     RECT  42.096 97.525 60.36 99.491 ;
     RECT  39.696 98.723 41.016 99.685 ;
     RECT  61.8 97.957 76.68 99.685 ;
     RECT  78 98.963 78.696 99.731 ;
     RECT  61.008 99.685 76.68 99.779 ;
     RECT  39.456 99.685 41.016 100.213 ;
     RECT  42.096 99.491 59.832 100.213 ;
     RECT  80.352 99.203 81.816 100.355 ;
     RECT  61.008 99.779 76.344 100.789 ;
     RECT  39.456 100.213 59.832 100.837 ;
     RECT  78 99.731 78.312 100.837 ;
     RECT  80.352 100.355 81.012 100.883 ;
     RECT  39.312 100.837 59.832 101.029 ;
     RECT  61.008 100.789 76.392 101.029 ;
     RECT  32.1 99.203 32.412 101.317 ;
     RECT  39.312 101.029 76.392 101.411 ;
     RECT  24 99.299 30.696 101.413 ;
     RECT  32.1 101.317 32.52 101.413 ;
     RECT  33.552 98.723 37.812 101.413 ;
     RECT  77.712 100.837 78.312 101.507 ;
     RECT  39.312 101.411 59.412 101.989 ;
     RECT  60.384 101.411 76.392 102.659 ;
     RECT  60.384 102.659 76.2 103.235 ;
     RECT  2.4 2.151 2.712 103.419 ;
     RECT  5.1 2.151 5.412 103.419 ;
     RECT  7.8 2.151 8.112 103.419 ;
     RECT  10.5 2.151 10.812 103.419 ;
     RECT  13.2 2.151 13.512 103.419 ;
     RECT  15.9 2.151 16.212 103.419 ;
     RECT  18.6 2.151 18.912 103.419 ;
     RECT  21.3 2.151 21.612 103.419 ;
     RECT  24 101.413 37.812 103.419 ;
     RECT  78 101.507 78.312 103.419 ;
     RECT  80.7 100.883 81.012 103.419 ;
     RECT  83.4 98.435 83.712 103.419 ;
     RECT  86.1 96.995 86.412 103.419 ;
     RECT  88.8 88.403 89.112 103.419 ;
     RECT  91.5 88.403 91.812 103.419 ;
     RECT  94.2 92.579 94.512 103.419 ;
     RECT  96.9 72.371 97.212 103.419 ;
     RECT  99.6 78.131 99.912 103.419 ;
     RECT  2.592 103.419 2.712 103.433 ;
     RECT  5.292 103.419 5.412 103.433 ;
     RECT  7.992 103.419 8.112 103.433 ;
     RECT  10.692 103.419 10.812 103.433 ;
     RECT  13.392 103.419 13.512 103.433 ;
     RECT  16.092 103.419 16.212 103.433 ;
     RECT  18.792 103.419 18.912 103.433 ;
     RECT  21.492 103.419 21.612 103.433 ;
     RECT  24.192 103.419 36.552 103.433 ;
     RECT  37.692 103.419 37.812 103.433 ;
     RECT  39.216 101.989 59.412 103.433 ;
     RECT  78.192 103.419 78.312 103.433 ;
     RECT  80.892 103.419 81.012 103.433 ;
     RECT  83.592 103.419 83.712 103.433 ;
     RECT  86.292 103.419 86.412 103.433 ;
     RECT  88.992 103.419 89.112 103.433 ;
     RECT  91.692 103.419 91.812 103.433 ;
     RECT  94.392 103.419 94.512 103.433 ;
     RECT  97.092 103.419 97.212 103.433 ;
     RECT  99.792 103.419 99.912 103.433 ;
     RECT  60.96 103.235 76.2 104.099 ;
     RECT  60.96 104.099 75.864 104.627 ;
     RECT  39.216 103.433 58.968 104.915 ;
     RECT  39.216 104.915 42.552 105.059 ;
     RECT  60.96 104.627 75.048 105.587 ;
     RECT  24.912 103.433 36.552 105.683 ;
     RECT  43.68 104.915 58.968 105.683 ;
     RECT  43.68 105.683 58.824 105.731 ;
     RECT  60.96 105.587 74.952 105.731 ;
     RECT  24.96 105.683 36.552 105.744 ;
     RECT  46.464 105.731 58.824 105.744 ;
     RECT  65.28 105.731 74.952 105.744 ;
     RECT  24.96 105.744 27.336 105.779 ;
     RECT  39.696 105.059 42.552 105.779 ;
     RECT  43.68 105.731 44.808 105.779 ;
     RECT  46.464 105.744 48.888 105.779 ;
     RECT  60.96 105.731 63.816 105.779 ;
     RECT  65.28 105.744 68.664 105.779 ;
  END
END qfd_landh_600_NE_104x106
END LIBRARY
